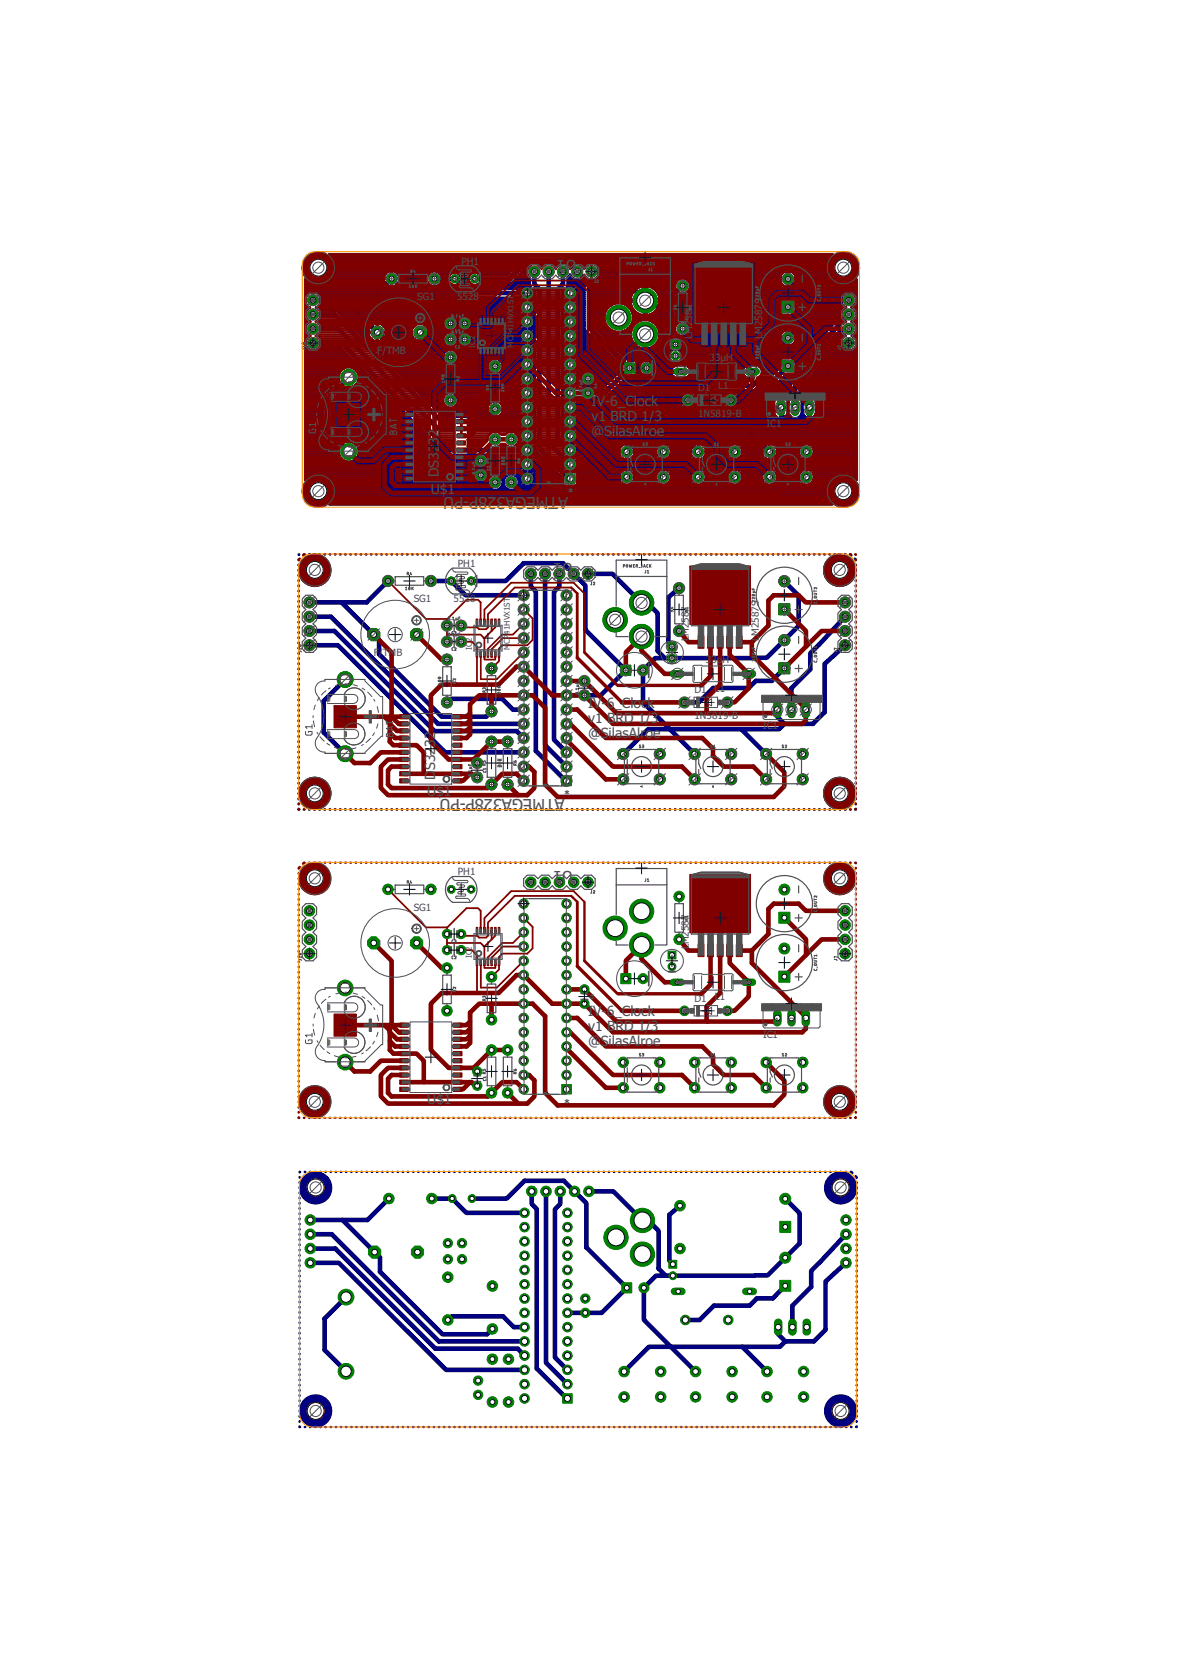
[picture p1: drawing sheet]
<svg xmlns="http://www.w3.org/2000/svg" width="210mm" height="297mm" viewBox="0 0 210 297" stroke-linecap="round" stroke-linejoin="round" font-family="sans-serif">
<defs><g id="words">
<g font-size="2.9" fill="#505050">
<text x="102.5" y="46.3" transform="rotate(-180 102.5 46.3)">U1</text>
<text x="101" y="88.3" transform="rotate(-180 101 88.3)">ATMEGA328P-PU</text>
<text x="101.8" y="100" transform="rotate(-180 101.8 100)">U1</text>
<text x="100.3" y="142" transform="rotate(-180 100.3 142)">ATMEGA328P-PU</text>
<text x="101.8" y="154.8" transform="rotate(-180 101.8 154.8)">U1</text>
</g>
<g font-size="2.5" fill="#505050">
<text x="105.1" y="72.1">IV-6_Clock</text>
<text x="105.1" y="74.8">v1 BRD 1/3</text>
<text x="105.1" y="77.5">@SilasAlroe</text>
<text x="76.6" y="87.8">U$1</text>
<text x="78" y="84.8" transform="rotate(-90 78 84.8)">DS3232</text>
<text x="104.5" y="125.9">IV-6_Clock</text>
<text x="104.5" y="128.5">v1 BRD 1/3</text>
<text x="104.5" y="131.2">@SilasAlroe</text>
<text x="75.9" y="141.5">U$1</text>
<text x="77.3" y="138.6" transform="rotate(-90 77.3 138.6)">DS3232</text>
<text x="104.5" y="180.7">IV-6_Clock</text>
<text x="104.5" y="183.4">v1 BRD 1/3</text>
<text x="104.5" y="186">@SilasAlroe</text>
<text x="75.9" y="196.3">U$1</text>
</g>
<g font-size="1.8" fill="#505050">
<text x="82" y="47">PH1</text>
<text x="74.2" y="53.4">SG1</text>
<text x="81.3" y="53.4">5528</text>
<text x="67.1" y="62.9">F/TMB</text>
<text x="123" y="60.2" transform="rotate(-90 123 60.2)">LM2587</text>
<text x="126.1" y="64.1">33µH</text>
<text x="135.5" y="60.2" transform="rotate(-90 135.5 60.2)">LM2587S</text>
<text x="124.1" y="69.5">D1</text>
<text x="127.7" y="69.2">L1</text>
<text x="124.1" y="74.1">1N5819-B</text>
<text x="136.2" y="75.9">IC1</text>
<text x="138.2" y="73.7">A</text>
<text x="140.7" y="73.7">O</text>
<text x="143.2" y="73.7">I</text>
<text x="101.9" y="86.2" transform="rotate(-180 101.9 86.2)">*</text>
<text x="81.4" y="100.8">PH1</text>
<text x="73.5" y="107.1">SG1</text>
<text x="80.6" y="107.1">5528</text>
<text x="122.4" y="113.9" transform="rotate(-90 122.4 113.9)">LM2587</text>
<text x="134.8" y="113.9" transform="rotate(-90 134.8 113.9)">LM2587S</text>
<text x="66.4" y="116.6">F/TMB</text>
<text x="125.5" y="117.8">33µH</text>
<text x="123.4" y="123.2">D1</text>
<text x="127" y="123">L1</text>
<text x="123.4" y="127.8">1N5819-B</text>
<text x="135.6" y="129.6">IC1</text>
<text x="137.5" y="127.4">A</text>
<text x="140.1" y="127.4">O</text>
<text x="142.6" y="127.4">I</text>
<text x="101.3" y="139.9" transform="rotate(-180 101.3 139.9)">*</text>
<text x="81.4" y="155.6">PH1</text>
<text x="73.5" y="161.9">SG1</text>
<text x="122.4" y="168.8" transform="rotate(-90 122.4 168.8)">LM2587</text>
<text x="123.4" y="178">D1</text>
<text x="127" y="177.8">L1</text>
<text x="135.6" y="184.5">IC1</text>
<text x="137.5" y="182.2">A</text>
<text x="140.1" y="182.2">O</text>
<text x="142.6" y="182.2">I</text>
<text x="101.3" y="194.8" transform="rotate(-180 101.3 194.8)">*</text>
</g>
<g font-size="1.4" fill="#505050">
<text x="84.5" y="61.8" transform="rotate(-90 84.5 61.8)">IC2</text>
<text x="91.3" y="61.8" transform="rotate(-90 91.3 61.8)">MCP41HVX1ST</text>
<text x="83.8" y="115.5" transform="rotate(-90 83.8 115.5)">IC2</text>
<text x="90.6" y="115.5" transform="rotate(-90 90.6 115.5)">MCP41HVX1ST</text>
<text x="83.8" y="170.3" transform="rotate(-90 83.8 170.3)">IC2</text>
</g>
</g></defs>
<g fill="#000080" stroke="#000080" stroke-width=".18">
<path d="M53.7 139.2a2.88 2.88 0 0 1 4.6 .2 2.88 2.88 0 0 1-1.5 4.4 2.88 2.88 0 0 1-3.7-2.8h2.5a.35 .35 0 0 1 .4-.3 .35 .35 0 0 1 .2 .5 .35 .35 0 0 1-.6-.1l-2.5-.1v-.6z" fill-rule="evenodd"/>
<path d="M53.7 99.6a2.89 2.89 0 0 1 4.6 .1 2.89 2.89 0 0 1-1.5 4.4 2.89 2.89 0 0 1-3.7-2.7h2.5a.35 .35 0 0 1 .4-.4 .35 .35 0 0 1 .2 .6 .35 .35 0 0 1-.6-.1l-2.5-.1v-.7z" fill-rule="evenodd"/>
<path d="M147 99.6a2.88 2.88 0 0 1 4.6 .2 2.88 2.88 0 0 1-1.5 4.3 2.88 2.88 0 0 1-3.7-2.7h2.5a.35 .35 0 0 1 .5-.3 .35 .35 0 0 1 0 .6 .35 .35 0 0 1-.5-.2l-2.5-.1 .2-1.3z" fill-rule="evenodd"/>
<path d="M147.4 138.8a2.89 2.89 0 0 1 4.4 1 2.89 2.89 0 0 1-1.9 4 2.89 2.89 0 0 1-3.5-2.8h2.5a.35 .35 0 0 1 .5-.2 .35 .35 0 0 1 0 .6 .35 .35 0 0 1-.5-.3l-2.5-.1a2.87 2.87 0 0 1 1-2.2z" fill-rule="evenodd"/>
</g>
<g fill="none" stroke="#000080" stroke-width=".83">
<path d="M55 114.7h5.1l19 19h14M55 112.2h4.4l17.8 17.8h14.6l1.3 1.2M55 109.6h3.8l19.1 19.1h15.2M60.7 107.1l6.7 6.7v2.5l11.1 11.1h7.9l1-.9M69 103.3l-3.8 3.8h-10.2M76.6 103.3h3.6l2.5 2.5h10.4M83.7 103.3h6.2l3.2-3.2h7l4 4v7.9l7.1 7.1-4.4 4.5h-6.1M94.3 102v2.2l.9 .9v28.4l5.5 5.3M96.9 102v30.5l3.8 3.8M99.4 102v2.2l-.9 1v26.3l2.2 2.2M104.5 102h4.4l5.1 5.2h1.1l1.8 1.8v6.7l1.3 1.3M119.2 117h.2"/>
<path d="M119.4 117h-3l-2.1 2.1v5.7l4.8 4.8M120.7 104.5l-1.9 1.7v8.1l.6 .7M139.4 103.3l2.5 2.6v5.4l-2.5 2.5M139.4 113.4v.4M139.4 118.8l-2.2 2.2h-2.9l-1.2 1.3h-6.4l-2.5 2.6h-2.6M139.4 113.8l-3.1 3.1-16.9 .1M150.2 114.7l-3.6 3.3v8.6l-2.1 2.1h-5.1l-1.2-1.3v-1.3M150.2 109.6l-6.2 6.5v2.9l-3.3 3.3v3.8M61.3 120.8l-3.8 3.8v5.6l3.8 3.8M79.4 124.9l.7-.7h9.2l1.9 1.9h1.9M119.1 129.6h-3.9l-4.4 4.4M119.1 129.6l4.4 4.4"/>
<path d="M119.1 129.6h12.7l4.4 4.4M139.4 128.7l-.9 .9h-6.7"/>
</g>
<g fill="none" stroke="#000080" stroke-width=".42">
<path d="M53.1 99.4v.1M53.2 98.5l-.1 .1M54 98.5h.1M54.9 98.5h.1M55.8 98.5h.1M56.8 98.5h.1M57.7 98.5h.1M58.6 98.5h.1M59.5 98.5h.1M60.4 98.5h.1M61.3 98.5h.1M62.3 98.5h.1"/>
<path d="M63.2 98.5h.1M64.1 98.5h.1M65 98.5h.1M65.9 98.5h.1M66.8 98.5h.1M67.7 98.5h.1M68.6 98.5h.2M69.6 98.5h.1M70.5 98.5h.1M71.4 98.5h.1M72.3 98.5h.1M73.2 98.5h.1"/>
<path d="M74.1 98.5h.2M75.1 98.5h.1M76 98.5h.1M76.9 98.5h.1M77.8 98.5h.1M78.7 98.5h.1M79.6 98.5h.1M80.6 98.5h.1M81.5 98.5h.1M82.4 98.5h.1M83.3 98.5h.1M84.2 98.5h.1"/>
<path d="M85.1 98.5h.1M86 98.5h.2M87 98.5h.1M87.9 98.5h.1M88.8 98.5h.1M89.7 98.5h.1M90.6 98.5h.1M91.5 98.5h.2M92.5 98.5h.1M93.4 98.5h.1M94.3 98.5h.1M95.2 98.5h.1"/>
<path d="M96.1 98.5h.1M97 98.5h.1M98 98.5h.1M98.9 98.5h.1M101.6 98.5h.1M102.5 98.5h.1M103.4 98.5h.1M104.4 98.5h.1M105.3 98.5h.1M106.2 98.5h.1M107.1 98.5h.1M108 98.5h.1"/>
<path d="M108.9 98.5h.1M109.9 98.5h.1M110.8 98.5h.1M111.7 98.5h.1M112.6 98.5h.1M113.5 98.5h.1M114.4 98.5h.1M115.3 98.5h.1M116.3 98.5h.1M117.2 98.5h.1M118.1 98.5h.1M119 98.5h.1"/>
<path d="M119.9 98.5h.1M120.8 98.5h.1M121.8 98.5h.1M122.7 98.5h.1M123.6 98.5h.1M124.5 98.5h.1M125.4 98.5h.1M126.3 98.5h.1M127.3 98.5h.1M128.2 98.5h.1M129.1 98.5h.1M130 98.5h.1"/>
<path d="M130.9 98.5h.1M131.8 98.5h.1M132.7 98.5h.1M133.7 98.5h.1M134.6 98.5h.1M135.5 98.5h.1M136.4 98.5h.1M137.3 98.5h.1M138.2 98.5h.1M139.1 98.5h.2M140.1 98.5h.1M141 98.5h.1"/>
<path d="M141.9 98.5h.1M142.8 98.5h.1M143.7 98.5h.1M144.7 98.5h.1M145.6 98.5h.1M146.5 98.5h.1M147.4 98.5h.1M148.3 98.5h.1M149.2 98.5h.1M150.1 98.5h.1M151 98.5l.3 .2M151.9 99.3l.2 .3"/>
<path d="M53.1 100.4v.1M53.1 101.3v.1M53.1 102.2v.1M53.1 103.1v.2M53.1 104.1v.1M53.1 105v.1M53.1 105.9v.1M53.1 106.8v.2M53.1 107.8v.1M53.1 108.7v.1M53.1 109.6v.1M53.1 110.5v.1"/>
<path d="M53.1 111.4v.2M53.1 112.4v.1M53.1 113.3v.1M53.1 114.2v.1M53.1 115.1v.2M53.1 116.1v.1M53.1 117v.1M53.1 117.9v.1M53.1 118.9v.1M53.1 119.8v.1M152.1 100.4v.1M152.1 101.3v.1"/>
<path d="M152.1 102.2v.2M152.1 103.2v.1M152.1 104.1v.1M152.1 105v.1M152.1 105.9v.1M152.1 106.9v.1M152.1 107.8v.1M152.1 108.7v.1M152.1 109.6v.1M152.1 110.6v.1M152.1 111.5v.1M152.1 112.4v.1"/>
<path d="M152.1 113.3v.1M152.1 114.2v.2M152.1 115.2v.1M152.1 116.1v.1M152.1 117v.1M152.1 117.9v.1M152.1 118.9v.1M152.1 119.8v.1M53.1 120.7v.1M53.1 121.6v.1M53.1 122.5v.1M53.1 123.5v.1"/>
<path d="M53.1 124.4v.1M53.1 125.3v.1M53.1 126.2v.1M53.1 127.2v.1M53.1 128.1v.1M53.1 129v.1M53.1 129.9v.1M53.1 130.9v.1M53.1 131.8v.1M53.1 132.7v.1M53.1 133.6v.1M53.1 134.5v.2"/>
<path d="M53.1 135.5v.1M53.1 136.4v.1M53.1 137.3v.1M53.1 138.2v.1M53.1 139.2v.1M152.1 120.7v.1M152.1 121.6v.1M152.1 122.6v.1M152.1 123.5v.1M152.1 124.4v.1M152.1 125.3v.1M152.1 126.2v.1"/>
<path d="M152.1 127.2v.1M152.1 128.1v.1M152.1 129v.1M152.1 129.9v.1M152.1 130.9v.1M152.1 131.8v.1M152.1 132.7v.1M152.1 133.6v.1M152.1 134.6v.1M152.1 135.5v.1M152.1 136.4v.1M152.1 137.3v.1"/>
<path d="M152.1 138.2v.1M152.1 139.2v.1M53.1 140.1v.1M53.1 141v.1M53.1 141.9v.2M53.1 142.9v.1M53.1 143.8l.1 .1M54 143.9h.1M54.9 143.9h.1M55.8 143.9h.1M56.8 143.9h.1M57.7 143.9h.1"/>
<path d="M58.6 143.9h.1M59.5 143.9h.1M60.4 143.9h.1M61.3 143.9h.1M62.3 143.9h.1M63.2 143.9h.1M64.1 143.9h.1M65 143.9h.1M65.9 143.9h.1M66.8 143.9h.1M67.7 143.9h.1M68.7 143.9h.1"/>
<path d="M69.6 143.9h.1M70.5 143.9h.1M71.4 143.9h.1M72.3 143.9h.1M73.2 143.9h.1M74.1 143.9h.2M75.1 143.9h.1M76 143.9h.1M76.9 143.9h.1M77.8 143.9h.1M78.7 143.9h.1M79.7 143.9h.1"/>
<path d="M80.6 143.9h.1M81.5 143.9h.1M82.4 143.9h.1M83.3 143.9h.1M84.2 143.9h.1M85.2 143.9h.1M86.1 143.9h.1M87 143.9h.1M87.9 143.9h.1M88.8 143.9h.1M89.7 143.9h.1M90.6 143.9h.1"/>
<path d="M91.5 143.9h.2M92.5 143.9h.1M93.4 143.9h.1M94.3 143.9h.1M95.2 143.9h.1M96.1 143.9h.1M97.1 143.9h.1M98 143.9h.1M98.9 143.9h.1M99.8 143.9h.1M100.7 143.9h.1M101.6 143.9h.1"/>
<path d="M102.6 143.9h.1M103.5 143.9h.1M104.4 143.9h.1M105.3 143.9h.1M106.2 143.9h.1M107.1 143.9h.1M108 143.9h.1M109 143.9h.1M109.9 143.9h.1M110.8 143.9h.1M111.7 143.9h.1M112.6 143.9h.1"/>
<path d="M113.5 143.9h.1M114.4 143.9h.2M115.4 143.9h.1M116.3 143.9h.1M117.2 143.9h.1M118.1 143.9h.1M119 143.9h.1M120 143.9h.1M120.9 143.9h.1M121.8 143.9h.1M122.7 143.9h.1M123.6 143.9h.1"/>
<path d="M124.5 143.9h.1M125.4 143.9h.1M126.4 143.9h.1M127.3 143.9h.1M128.2 143.9h.1M129.1 143.9h.1M130 143.9h.1M130.9 143.9h.1M131.8 143.9h.2M132.8 143.9h.1M133.7 143.9h.1M134.6 143.9h.1"/>
<path d="M135.5 143.9h.1M136.4 143.9h.1M137.4 143.9h.1M138.3 143.9h.1M139.2 143.9h.1M140.1 143.9h.1M141 143.9h.1M141.9 143.9h.1M142.9 143.9h.1M143.8 143.9h.1M144.7 143.9h.1M145.6 143.9h.1"/>
<path d="M146.5 143.9h.1M147.4 143.9h.1M148.3 143.9h.1M149.3 143.9h.1M150.2 143.9h.1M151.1 143.9h.1M152.1 143.8l-.1 .1M152.1 140.1v.1M152.1 141v.1M152.1 141.9v.2M152.1 142.9v.1"/>
</g>
<circle cx="119.4" cy="117" r=".7" fill="#008000" stroke="#008000" stroke-width=".18"/>
<circle cx="119.4" cy="117" r=".44" fill="#fff" stroke="#000" stroke-width=".18"/>
<path d="M118.7 114.3h1.4v1.4h-1.4z" fill="#008000" stroke="#008000" stroke-width=".18"/>
<circle cx="119.4" cy="115" r=".44" fill="#fff" stroke="#000" stroke-width=".18"/>
<path d="M110.3 118.3h1.8v1.7h-1.8z" fill="#008000" stroke="#008000" stroke-width=".18"/>
<circle cx="111.2" cy="119.1" r=".44" fill="#fff" stroke="#000" stroke-width=".18"/>
<circle cx="114.3" cy="119.1" r=".89" fill="#008000" stroke="#008000" stroke-width=".18"/>
<circle cx="114.3" cy="119.1" r=".44" fill="#fff" stroke="#000" stroke-width=".18"/>
<circle cx="139.4" cy="113.8" r=".97" fill="#008000" stroke="#008000" stroke-width=".18"/>
<circle cx="139.4" cy="113.8" r=".44" fill="#fff" stroke="#000" stroke-width=".18"/>
<path d="M138.4 117.8h2v2h-2z" fill="#008000" stroke="#008000" stroke-width=".18"/>
<circle cx="139.4" cy="118.8" r=".44" fill="#fff" stroke="#000" stroke-width=".18"/>
<circle cx="139.4" cy="103.3" r=".97" fill="#008000" stroke="#008000" stroke-width=".18"/>
<circle cx="139.4" cy="103.3" r=".44" fill="#fff" stroke="#000" stroke-width=".18"/>
<path d="M138.4 107.3h2v2h-2z" fill="#008000" stroke="#008000" stroke-width=".18"/>
<circle cx="139.4" cy="108.3" r=".44" fill="#fff" stroke="#000" stroke-width=".18"/>
<circle cx="121.6" cy="124.9" r=".85" fill="#008000" stroke="#008000" stroke-width=".18"/>
<circle cx="121.6" cy="124.9" r=".55" fill="#fff" stroke="#000" stroke-width=".18"/>
<circle cx="129.3" cy="124.9" r=".85" fill="#008000" stroke="#008000" stroke-width=".18"/>
<circle cx="129.3" cy="124.9" r=".55" fill="#fff" stroke="#000" stroke-width=".18"/>
<path d="M132.4 119.8h1.3" fill="none" stroke="#008000" stroke-width="1.3"/>
<circle cx="133.1" cy="119.8" r=".4" fill="#fff" stroke="#000" stroke-width=".18"/>
<path d="M119.7 119.8h1.3" fill="none" stroke="#008000" stroke-width="1.3"/>
<circle cx="120.4" cy="119.8" r=".4" fill="#fff" stroke="#000" stroke-width=".18"/>
<circle cx="120.7" cy="104.5" r=".93" fill="#008000" stroke="#008000" stroke-width=".18"/>
<circle cx="120.7" cy="104.5" r=".44" fill="#fff" stroke="#000" stroke-width=".18"/>
<circle cx="120.7" cy="112.2" r=".93" fill="#008000" stroke="#008000" stroke-width=".18"/>
<circle cx="120.7" cy="112.2" r=".44" fill="#fff" stroke="#000" stroke-width=".18"/>
<circle cx="114" cy="113.2" r="2.16" fill="#008000" stroke="#008000" stroke-width=".18"/>
<circle cx="114" cy="113.2" r="1.5" fill="#fff" stroke="#000" stroke-width=".18"/>
<circle cx="114" cy="107.2" r="2.16" fill="#008000" stroke="#008000" stroke-width=".18"/>
<circle cx="114" cy="107.2" r="1.5" fill="#fff" stroke="#000" stroke-width=".18"/>
<circle cx="109.3" cy="110.2" r="2.16" fill="#008000" stroke="#008000" stroke-width=".18"/>
<circle cx="109.3" cy="110.2" r="1.5" fill="#fff" stroke="#000" stroke-width=".18"/>
<circle cx="150.2" cy="114.7" r=".93" fill="#008000" stroke="#008000" stroke-width=".18"/>
<circle cx="150.2" cy="114.7" r=".51" fill="#fff" stroke="#000" stroke-width=".18"/>
<circle cx="150.2" cy="112.2" r=".93" fill="#008000" stroke="#008000" stroke-width=".18"/>
<circle cx="150.2" cy="112.2" r=".51" fill="#fff" stroke="#000" stroke-width=".18"/>
<circle cx="150.2" cy="109.6" r=".93" fill="#008000" stroke="#008000" stroke-width=".18"/>
<circle cx="150.2" cy="109.6" r=".51" fill="#fff" stroke="#000" stroke-width=".18"/>
<circle cx="150.2" cy="107.1" r=".93" fill="#008000" stroke="#008000" stroke-width=".18"/>
<circle cx="150.2" cy="107.1" r=".51" fill="#fff" stroke="#000" stroke-width=".18"/>
<circle cx="55" cy="114.7" r=".93" fill="#008000" stroke="#008000" stroke-width=".18"/>
<circle cx="55" cy="114.7" r=".51" fill="#fff" stroke="#000" stroke-width=".18"/>
<circle cx="55" cy="112.2" r=".93" fill="#008000" stroke="#008000" stroke-width=".18"/>
<circle cx="55" cy="112.2" r=".51" fill="#fff" stroke="#000" stroke-width=".18"/>
<circle cx="55" cy="109.6" r=".93" fill="#008000" stroke="#008000" stroke-width=".18"/>
<circle cx="55" cy="109.6" r=".51" fill="#fff" stroke="#000" stroke-width=".18"/>
<circle cx="55" cy="107.1" r=".93" fill="#008000" stroke="#008000" stroke-width=".18"/>
<circle cx="55" cy="107.1" r=".51" fill="#fff" stroke="#000" stroke-width=".18"/>
<circle cx="83.7" cy="103.3" r=".7" fill="#008000" stroke="#008000" stroke-width=".18"/>
<circle cx="83.7" cy="103.3" r=".4" fill="#fff" stroke="#000" stroke-width=".18"/>
<circle cx="80.2" cy="103.3" r=".7" fill="#008000" stroke="#008000" stroke-width=".18"/>
<circle cx="80.2" cy="103.3" r=".4" fill="#fff" stroke="#000" stroke-width=".18"/>
<circle cx="69" cy="103.3" r=".93" fill="#008000" stroke="#008000" stroke-width=".18"/>
<circle cx="69" cy="103.3" r=".44" fill="#fff" stroke="#000" stroke-width=".18"/>
<circle cx="76.6" cy="103.3" r=".93" fill="#008000" stroke="#008000" stroke-width=".18"/>
<circle cx="76.6" cy="103.3" r=".44" fill="#fff" stroke="#000" stroke-width=".18"/>
<circle cx="123.5" cy="134" r=".93" fill="#008000" stroke="#008000" stroke-width=".18"/>
<circle cx="123.5" cy="134" r=".51" fill="#fff" stroke="#000" stroke-width=".18"/>
<circle cx="130" cy="134" r=".93" fill="#008000" stroke="#008000" stroke-width=".18"/>
<circle cx="130" cy="134" r=".51" fill="#fff" stroke="#000" stroke-width=".18"/>
<circle cx="123.5" cy="138.5" r=".93" fill="#008000" stroke="#008000" stroke-width=".18"/>
<circle cx="123.5" cy="138.5" r=".51" fill="#fff" stroke="#000" stroke-width=".18"/>
<circle cx="130" cy="138.5" r=".93" fill="#008000" stroke="#008000" stroke-width=".18"/>
<circle cx="130" cy="138.5" r=".51" fill="#fff" stroke="#000" stroke-width=".18"/>
<path d="M138.2 125.4v1.5" fill="none" stroke="#008000" stroke-width="1.5"/>
<circle cx="138.2" cy="126.1" r=".51" fill="#fff" stroke="#000" stroke-width=".18"/>
<path d="M140.7 125.4v1.5" fill="none" stroke="#008000" stroke-width="1.5"/>
<circle cx="140.7" cy="126.1" r=".51" fill="#fff" stroke="#000" stroke-width=".18"/>
<path d="M143.2 125.4v1.5" fill="none" stroke="#008000" stroke-width="1.5"/>
<circle cx="143.2" cy="126.1" r=".51" fill="#fff" stroke="#000" stroke-width=".18"/>
<circle cx="136.2" cy="134" r=".93" fill="#008000" stroke="#008000" stroke-width=".18"/>
<circle cx="136.2" cy="134" r=".51" fill="#fff" stroke="#000" stroke-width=".18"/>
<circle cx="142.7" cy="134" r=".93" fill="#008000" stroke="#008000" stroke-width=".18"/>
<circle cx="142.7" cy="134" r=".51" fill="#fff" stroke="#000" stroke-width=".18"/>
<circle cx="136.2" cy="138.5" r=".93" fill="#008000" stroke="#008000" stroke-width=".18"/>
<circle cx="136.2" cy="138.5" r=".51" fill="#fff" stroke="#000" stroke-width=".18"/>
<circle cx="142.7" cy="138.5" r=".93" fill="#008000" stroke="#008000" stroke-width=".18"/>
<circle cx="142.7" cy="138.5" r=".51" fill="#fff" stroke="#000" stroke-width=".18"/>
<circle cx="110.8" cy="134" r=".93" fill="#008000" stroke="#008000" stroke-width=".18"/>
<circle cx="110.8" cy="134" r=".51" fill="#fff" stroke="#000" stroke-width=".18"/>
<circle cx="117.3" cy="134" r=".93" fill="#008000" stroke="#008000" stroke-width=".18"/>
<circle cx="117.3" cy="134" r=".51" fill="#fff" stroke="#000" stroke-width=".18"/>
<circle cx="110.8" cy="138.5" r=".93" fill="#008000" stroke="#008000" stroke-width=".18"/>
<circle cx="110.8" cy="138.5" r=".51" fill="#fff" stroke="#000" stroke-width=".18"/>
<circle cx="117.3" cy="138.5" r=".93" fill="#008000" stroke="#008000" stroke-width=".18"/>
<circle cx="117.3" cy="138.5" r=".51" fill="#fff" stroke="#000" stroke-width=".18"/>
<circle cx="66.4" cy="112.8" r="1.17" fill="#008000" stroke="#008000" stroke-width=".18"/>
<circle cx="66.4" cy="112.8" r=".51" fill="#fff" stroke="#000" stroke-width=".18"/>
<circle cx="74" cy="112.8" r="1.17" fill="#008000" stroke="#008000" stroke-width=".18"/>
<circle cx="74" cy="112.8" r=".51" fill="#fff" stroke="#000" stroke-width=".18"/>
<circle cx="79.4" cy="117.2" r=".93" fill="#008000" stroke="#008000" stroke-width=".18"/>
<circle cx="79.4" cy="117.2" r=".44" fill="#fff" stroke="#000" stroke-width=".18"/>
<circle cx="79.4" cy="124.9" r=".93" fill="#008000" stroke="#008000" stroke-width=".18"/>
<circle cx="79.4" cy="124.9" r=".44" fill="#fff" stroke="#000" stroke-width=".18"/>
<path d="M99.8 138h1.7v1.7h-1.7z" fill="#008000" stroke="#008000" stroke-width=".18"/>
<circle cx="100.7" cy="138.8" r=".55" fill="#fff" stroke="#000" stroke-width=".18"/>
<circle cx="100.7" cy="136.3" r=".85" fill="#008000" stroke="#008000" stroke-width=".18"/>
<circle cx="100.7" cy="136.3" r=".55" fill="#fff" stroke="#000" stroke-width=".18"/>
<circle cx="100.7" cy="133.7" r=".85" fill="#008000" stroke="#008000" stroke-width=".18"/>
<circle cx="100.7" cy="133.7" r=".55" fill="#fff" stroke="#000" stroke-width=".18"/>
<circle cx="100.7" cy="131.2" r=".85" fill="#008000" stroke="#008000" stroke-width=".18"/>
<circle cx="100.7" cy="131.2" r=".55" fill="#fff" stroke="#000" stroke-width=".18"/>
<circle cx="100.7" cy="128.7" r=".85" fill="#008000" stroke="#008000" stroke-width=".18"/>
<circle cx="100.7" cy="128.7" r=".55" fill="#fff" stroke="#000" stroke-width=".18"/>
<circle cx="100.7" cy="126.1" r=".85" fill="#008000" stroke="#008000" stroke-width=".18"/>
<circle cx="100.7" cy="126.1" r=".55" fill="#fff" stroke="#000" stroke-width=".18"/>
<circle cx="100.7" cy="123.6" r=".85" fill="#008000" stroke="#008000" stroke-width=".18"/>
<circle cx="100.7" cy="123.6" r=".55" fill="#fff" stroke="#000" stroke-width=".18"/>
<circle cx="100.7" cy="121.1" r=".85" fill="#008000" stroke="#008000" stroke-width=".18"/>
<circle cx="100.7" cy="121.1" r=".55" fill="#fff" stroke="#000" stroke-width=".18"/>
<circle cx="100.7" cy="118.5" r=".85" fill="#008000" stroke="#008000" stroke-width=".18"/>
<circle cx="100.7" cy="118.5" r=".55" fill="#fff" stroke="#000" stroke-width=".18"/>
<circle cx="100.7" cy="116" r=".85" fill="#008000" stroke="#008000" stroke-width=".18"/>
<circle cx="100.7" cy="116" r=".55" fill="#fff" stroke="#000" stroke-width=".18"/>
<circle cx="100.7" cy="113.4" r=".85" fill="#008000" stroke="#008000" stroke-width=".18"/>
<circle cx="100.7" cy="113.4" r=".55" fill="#fff" stroke="#000" stroke-width=".18"/>
<circle cx="100.7" cy="110.9" r=".85" fill="#008000" stroke="#008000" stroke-width=".18"/>
<circle cx="100.7" cy="110.9" r=".55" fill="#fff" stroke="#000" stroke-width=".18"/>
<circle cx="100.7" cy="108.4" r=".85" fill="#008000" stroke="#008000" stroke-width=".18"/>
<circle cx="100.7" cy="108.4" r=".55" fill="#fff" stroke="#000" stroke-width=".18"/>
<circle cx="100.7" cy="105.8" r=".85" fill="#008000" stroke="#008000" stroke-width=".18"/>
<circle cx="100.7" cy="105.8" r=".55" fill="#fff" stroke="#000" stroke-width=".18"/>
<circle cx="93.1" cy="105.8" r=".85" fill="#008000" stroke="#008000" stroke-width=".18"/>
<circle cx="93.1" cy="105.8" r=".55" fill="#fff" stroke="#000" stroke-width=".18"/>
<circle cx="93.1" cy="108.4" r=".85" fill="#008000" stroke="#008000" stroke-width=".18"/>
<circle cx="93.1" cy="108.4" r=".55" fill="#fff" stroke="#000" stroke-width=".18"/>
<circle cx="93.1" cy="110.9" r=".85" fill="#008000" stroke="#008000" stroke-width=".18"/>
<circle cx="93.1" cy="110.9" r=".55" fill="#fff" stroke="#000" stroke-width=".18"/>
<circle cx="93.1" cy="113.4" r=".85" fill="#008000" stroke="#008000" stroke-width=".18"/>
<circle cx="93.1" cy="113.4" r=".55" fill="#fff" stroke="#000" stroke-width=".18"/>
<circle cx="93.1" cy="116" r=".85" fill="#008000" stroke="#008000" stroke-width=".18"/>
<circle cx="93.1" cy="116" r=".55" fill="#fff" stroke="#000" stroke-width=".18"/>
<circle cx="93.1" cy="118.5" r=".85" fill="#008000" stroke="#008000" stroke-width=".18"/>
<circle cx="93.1" cy="118.5" r=".55" fill="#fff" stroke="#000" stroke-width=".18"/>
<circle cx="93.1" cy="121.1" r=".85" fill="#008000" stroke="#008000" stroke-width=".18"/>
<circle cx="93.1" cy="121.1" r=".55" fill="#fff" stroke="#000" stroke-width=".18"/>
<circle cx="93.1" cy="123.6" r=".85" fill="#008000" stroke="#008000" stroke-width=".18"/>
<circle cx="93.1" cy="123.6" r=".55" fill="#fff" stroke="#000" stroke-width=".18"/>
<circle cx="93.1" cy="126.1" r=".85" fill="#008000" stroke="#008000" stroke-width=".18"/>
<circle cx="93.1" cy="126.1" r=".55" fill="#fff" stroke="#000" stroke-width=".18"/>
<circle cx="93.1" cy="128.7" r=".85" fill="#008000" stroke="#008000" stroke-width=".18"/>
<circle cx="93.1" cy="128.7" r=".55" fill="#fff" stroke="#000" stroke-width=".18"/>
<circle cx="93.1" cy="131.2" r=".85" fill="#008000" stroke="#008000" stroke-width=".18"/>
<circle cx="93.1" cy="131.2" r=".55" fill="#fff" stroke="#000" stroke-width=".18"/>
<circle cx="93.1" cy="133.7" r=".85" fill="#008000" stroke="#008000" stroke-width=".18"/>
<circle cx="93.1" cy="133.7" r=".55" fill="#fff" stroke="#000" stroke-width=".18"/>
<circle cx="93.1" cy="136.3" r=".85" fill="#008000" stroke="#008000" stroke-width=".18"/>
<circle cx="93.1" cy="136.3" r=".55" fill="#fff" stroke="#000" stroke-width=".18"/>
<circle cx="93.1" cy="138.8" r=".85" fill="#008000" stroke="#008000" stroke-width=".18"/>
<circle cx="93.1" cy="138.8" r=".55" fill="#fff" stroke="#000" stroke-width=".18"/>
<circle cx="61.3" cy="134" r="1.4" fill="#008000" stroke="#008000" stroke-width=".18"/>
<circle cx="61.3" cy="134" r=".93" fill="#fff" stroke="#000" stroke-width=".18"/>
<circle cx="61.3" cy="120.8" r="1.4" fill="#008000" stroke="#008000" stroke-width=".18"/>
<circle cx="61.3" cy="120.8" r=".93" fill="#fff" stroke="#000" stroke-width=".18"/>
<circle cx="104.5" cy="102" r=".93" fill="#008000" stroke="#008000" stroke-width=".18"/>
<circle cx="104.5" cy="102" r=".51" fill="#fff" stroke="#000" stroke-width=".18"/>
<circle cx="102" cy="102" r=".93" fill="#008000" stroke="#008000" stroke-width=".18"/>
<circle cx="102" cy="102" r=".51" fill="#fff" stroke="#000" stroke-width=".18"/>
<circle cx="99.4" cy="102" r=".93" fill="#008000" stroke="#008000" stroke-width=".18"/>
<circle cx="99.4" cy="102" r=".51" fill="#fff" stroke="#000" stroke-width=".18"/>
<circle cx="96.9" cy="102" r=".93" fill="#008000" stroke="#008000" stroke-width=".18"/>
<circle cx="96.9" cy="102" r=".51" fill="#fff" stroke="#000" stroke-width=".18"/>
<circle cx="94.3" cy="102" r=".93" fill="#008000" stroke="#008000" stroke-width=".18"/>
<circle cx="94.3" cy="102" r=".51" fill="#fff" stroke="#000" stroke-width=".18"/>
<circle cx="87.4" cy="126.5" r=".93" fill="#008000" stroke="#008000" stroke-width=".18"/>
<circle cx="87.4" cy="126.5" r=".44" fill="#fff" stroke="#000" stroke-width=".18"/>
<circle cx="87.4" cy="118.8" r=".93" fill="#008000" stroke="#008000" stroke-width=".18"/>
<circle cx="87.4" cy="118.8" r=".44" fill="#fff" stroke="#000" stroke-width=".18"/>
<circle cx="87.4" cy="139.4" r=".93" fill="#008000" stroke="#008000" stroke-width=".18"/>
<circle cx="87.4" cy="139.4" r=".44" fill="#fff" stroke="#000" stroke-width=".18"/>
<circle cx="87.4" cy="131.8" r=".93" fill="#008000" stroke="#008000" stroke-width=".18"/>
<circle cx="87.4" cy="131.8" r=".44" fill="#fff" stroke="#000" stroke-width=".18"/>
<circle cx="90.2" cy="131.8" r=".93" fill="#008000" stroke="#008000" stroke-width=".18"/>
<circle cx="90.2" cy="131.8" r=".44" fill="#fff" stroke="#000" stroke-width=".18"/>
<circle cx="90.2" cy="139.4" r=".93" fill="#008000" stroke="#008000" stroke-width=".18"/>
<circle cx="90.2" cy="139.4" r=".44" fill="#fff" stroke="#000" stroke-width=".18"/>
<circle cx="84.8" cy="135.6" r=".83" fill="#008000" stroke="#008000" stroke-width=".18"/>
<circle cx="84.8" cy="135.6" r=".44" fill="#fff" stroke="#000" stroke-width=".18"/>
<circle cx="84.8" cy="138.2" r=".83" fill="#008000" stroke="#008000" stroke-width=".18"/>
<circle cx="84.8" cy="138.2" r=".44" fill="#fff" stroke="#000" stroke-width=".18"/>
<circle cx="82" cy="114.1" r=".83" fill="#008000" stroke="#008000" stroke-width=".18"/>
<circle cx="82" cy="114.1" r=".44" fill="#fff" stroke="#000" stroke-width=".18"/>
<circle cx="79.4" cy="114.1" r=".83" fill="#008000" stroke="#008000" stroke-width=".18"/>
<circle cx="79.4" cy="114.1" r=".44" fill="#fff" stroke="#000" stroke-width=".18"/>
<circle cx="82" cy="111.2" r=".83" fill="#008000" stroke="#008000" stroke-width=".18"/>
<circle cx="82" cy="111.2" r=".44" fill="#fff" stroke="#000" stroke-width=".18"/>
<circle cx="79.4" cy="111.2" r=".83" fill="#008000" stroke="#008000" stroke-width=".18"/>
<circle cx="79.4" cy="111.2" r=".44" fill="#fff" stroke="#000" stroke-width=".18"/>
<circle cx="103.9" cy="121.1" r=".83" fill="#008000" stroke="#008000" stroke-width=".18"/>
<circle cx="103.9" cy="121.1" r=".44" fill="#fff" stroke="#000" stroke-width=".18"/>
<circle cx="103.9" cy="123.6" r=".83" fill="#008000" stroke="#008000" stroke-width=".18"/>
<circle cx="103.9" cy="123.6" r=".44" fill="#fff" stroke="#000" stroke-width=".18"/>
<g fill="#800000" stroke="#800000" stroke-width=".18">
<path d="M122.6 100.6h10.8v10.4h-10.8z"/>
<path d="M124.1 113.1h1v2.1h-1z"/>
<path d="M125.8 113.1h1v2.1h-1z"/>
<path d="M127.5 113.1h1v2.1h-1z"/>
<path d="M129.2 113.1h1v2.1h-1z"/>
<path d="M130.9 113.1h1v2.1h-1z"/>
<path d="M80.6 138.4h1.5v.8h-1.5z"/>
<path d="M80.6 137.2h1.5v.7h-1.5z"/>
<path d="M80.6 135.9h1.5v.8h-1.5z"/>
<path d="M80.6 134.6h1.5v.8h-1.5z"/>
<path d="M80.6 133.4h1.5v.7h-1.5z"/>
<path d="M80.6 132.1h1.5v.7h-1.5z"/>
<path d="M80.6 130.8h1.5v.8h-1.5z"/>
<path d="M80.6 129.5h1.5v.8h-1.5z"/>
<path d="M80.6 128.3h1.5v.8h-1.5z"/>
<path d="M80.6 127h1.5v.8h-1.5z"/>
<path d="M71 128.3h1.6v.8h-1.6z"/>
<path d="M71.1 127h1.5v.8h-1.5z"/>
<path d="M71 129.5h1.6v.8h-1.6z"/>
<path d="M71 130.8h1.6v.8h-1.6z"/>
<path d="M71 132.1h1.6v.7h-1.6z"/>
<path d="M71 133.4h1.6v.7h-1.6z"/>
<path d="M71 134.6h1.6v.8h-1.6z"/>
<path d="M71 135.9h1.6v.8h-1.6z"/>
<path d="M71 137.2h1.6v.7h-1.6z"/>
<path d="M71 138.4h1.6v.8h-1.6z"/>
<path d="M59.4 125.4h3.9v4h-3.9z"/>
<path d="M84.6 115.9h.3v.9h-.3z"/>
<path d="M85.3 115.9h.3v.9h-.3z"/>
<path d="M85.9 115.9h.3v.9h-.3z"/>
<path d="M86.6 115.9h.3v.9h-.3z"/>
<path d="M87.2 115.9h.3v.9h-.3z"/>
<path d="M87.9 115.9h.3v.9h-.3z"/>
<path d="M88.5 115.9h.3v.9h-.3z"/>
<path d="M88.5 110h.3v1h-.3z"/>
<path d="M87.9 110h.3v1h-.3z"/>
<path d="M87.2 110h.3v1h-.3z"/>
<path d="M86.6 110h.3v1h-.3z"/>
<path d="M85.9 110h.3v1h-.3z"/>
<path d="M85.3 110h.3v1h-.3z"/>
<path d="M84.6 110h.3v1h-.3z"/>
</g>
<g fill="none" stroke="#800000" stroke-width=".42">
<path d="M53.3 99.3l-.2 .3M54.1 98.5l-.2 .2M55 98.5h.1M55.9 98.5h.1M56.8 98.5h.1M57.7 98.5h.1M58.6 98.5h.1M59.5 98.5h.1M60.5 98.5h.1M61.4 98.5h.1M62.3 98.5h.1M63.2 98.5h.1"/>
<path d="M64.1 98.5h.1M65 98.5h.1M65.9 98.5h.1M66.9 98.5h.1M67.8 98.5h.1M68.7 98.5h.1M69.6 98.5h.1M70.5 98.5h.1M71.4 98.5h.1M72.4 98.5h.1M73.3 98.5h.1M74.2 98.5h.1"/>
<path d="M75.1 98.5h.1M76 98.5h.1M76.9 98.5h.1M77.9 98.5h.1M78.8 98.5h.1M79.7 98.5h.1M80.6 98.5h.1M81.5 98.5h.1M82.4 98.5h.1M83.3 98.5h.1M84.2 98.5h.2M85.2 98.5h.1"/>
<path d="M86.1 98.5h.1M87 98.5h.1M87.9 98.5h.1M88.8 98.5h.1M89.7 98.5h.2M90.7 98.5h.1M91.6 98.5h.1M92.5 98.5h.1M93.4 98.5h.1M94.3 98.5h.1M95.3 98.5h.1M96.2 98.5h.1"/>
<path d="M97.1 98.5h.1M98 98.5h.1M101.6 98.5h.1M102.6 98.5h.1M103.5 98.5h.1M104.4 98.5h.1M105.3 98.5h.1M106.2 98.5h.1M107.1 98.5h.2M108.1 98.5h.1M109 98.5h.1M109.9 98.5h.1"/>
<path d="M110.8 98.5h.1M111.7 98.5h.1M112.6 98.5h.1M113.6 98.5h.1M114.5 98.5h.1M115.4 98.5h.1M116.3 98.5h.1M117.2 98.5h.1M118.1 98.5h.1M119 98.5h.1M120 98.5h.1M120.9 98.5h.1"/>
<path d="M121.8 98.5h.1M122.7 98.5h.1M123.6 98.5h.1M124.5 98.5h.2M125.5 98.5h.1M126.4 98.5h.1M127.3 98.5h.1M128.2 98.5h.1M129.1 98.5h.1M130 98.5h.1M131 98.5h.1M131.9 98.5h.1"/>
<path d="M132.8 98.5h.1M133.7 98.5h.1M134.6 98.5h.1M135.5 98.5h.1M136.4 98.5h.1M137.4 98.5h.1M138.3 98.5h.1M139.2 98.5h.1M140.1 98.5h.1M141 98.5h.1M141.9 98.5h.1M142.9 98.5h.1"/>
<path d="M143.8 98.5h.1M144.7 98.5h.1M145.6 98.5h.1M146.5 98.5h.1M147.4 98.5h.1M148.3 98.5h.1M149.3 98.5h.1M150.2 98.5h.1M151.1 98.5h.1M152 98.5l.1 .1M152.1 99.4v.1M53.1 100.4v.1"/>
<path d="M53.1 101.3v.1M53.1 102.2v.2M53.1 103.2v.1M53.1 104.1v.1M53.1 105v.1M53.1 105.9v.1M53.1 106.9v.1M53.1 107.8v.1M53.1 108.7v.1M53.1 109.6v.1M53.1 110.6v.1M53.1 111.5v.1"/>
<path d="M53.1 112.4v.1M53.1 113.3v.1M53.1 114.2v.2M53.1 115.2v.1M53.1 116.1v.1M53.1 117v.1M53.1 117.9v.1M53.1 118.9v.1M53.1 119.8v.1M101.5 104.4l1.1 1.1M103.9 105.5v10.5M152.1 100.4v.1"/>
<path d="M152.1 101.3v.1M152.1 102.2v.1M152.1 103.1v.2M152.1 104.1v.1M152.1 105v.1M152.1 105.9v.1M152.1 106.8v.2M152.1 107.8v.1M152.1 108.7v.1M152.1 109.6v.1M152.1 110.5v.1M152.1 111.4v.2"/>
<path d="M152.1 112.4v.1M152.1 113.3v.1M152.1 114.2v.1M152.1 115.1v.2M152.1 116.1v.1M152.1 117v.1M152.1 117.9v.1M152.1 118.9v.1M152.1 119.8v.1M53.1 120.7v.1M53.1 121.6v.1M53.1 122.6v.1"/>
<path d="M53.1 123.5v.1M53.1 124.4v.1M53.1 125.3v.1M53.1 126.2v.1M53.1 127.2v.1M53.1 128.1v.1M53.1 129v.1M53.1 129.9v.1M53.1 130.9v.1M53.1 131.8v.1M53.1 132.7v.1M53.1 133.6v.1"/>
<path d="M53.1 134.6v.1M53.1 135.5v.1M53.1 136.4v.1M53.1 137.3v.1M53.1 138.2v.1M53.1 139.2v.1M152.1 120.7v.1M152.1 121.6v.1M152.1 122.5v.1M152.1 123.5v.1M152.1 124.4v.1M152.1 125.3v.1"/>
<path d="M152.1 126.2v.1M152.1 127.2v.1M152.1 128.1v.1M152.1 129v.1M152.1 129.9v.1M152.1 130.9v.1M152.1 131.8v.1M152.1 132.7v.1M152.1 133.6v.1M152.1 134.5v.2M152.1 135.5v.1M152.1 136.4v.1"/>
<path d="M152.1 137.3v.1M152.1 138.2v.1M152.1 139.2v.1M53.1 140.1v.1M53.1 141v.1M53.1 141.9v.2M53.1 142.9v.1M53.1 143.8l.1 .1M54 143.9h.1M54.9 143.9h.1M55.8 143.9h.1M56.8 143.9h.1"/>
<path d="M57.7 143.9h.1M58.6 143.9h.1M59.5 143.9h.1M60.4 143.9h.1M61.3 143.9h.1M62.3 143.9h.1M63.2 143.9h.1M64.1 143.9h.1M65 143.9h.1M65.9 143.9h.1M66.8 143.9h.1M67.7 143.9h.1"/>
<path d="M68.7 143.9h.1M69.6 143.9h.1M70.5 143.9h.1M71.4 143.9h.1M72.3 143.9h.1M73.2 143.9h.1M74.1 143.9h.2M75.1 143.9h.1M76 143.9h.1M76.9 143.9h.1M77.8 143.9h.1M78.7 143.9h.1"/>
<path d="M79.7 143.9h.1M80.6 143.9h.1M81.5 143.9h.1M82.4 143.9h.1M83.3 143.9h.1M84.2 143.9h.1M85.2 143.9h.1M86.1 143.9h.1M87 143.9h.1M87.9 143.9h.1M88.8 143.9h.1M89.7 143.9h.1"/>
<path d="M90.6 143.9h.1M91.5 143.9h.2M92.5 143.9h.1M93.4 143.9h.1M94.3 143.9h.1M95.2 143.9h.1M96.1 143.9h.1M97.1 143.9h.1M98 143.9h.1M98.9 143.9h.1M99.8 143.9h.1M100.7 143.9h.1"/>
<path d="M101.6 143.9h.1M102.6 143.9h.1M103.5 143.9h.1M104.4 143.9h.1M105.3 143.9h.1M106.2 143.9h.1M107.1 143.9h.1M108 143.9h.1M109 143.9h.1M109.9 143.9h.1M110.8 143.9h.1M111.7 143.9h.1"/>
<path d="M112.6 143.9h.1M113.5 143.9h.1M114.4 143.9h.2M115.4 143.9h.1M116.3 143.9h.1M117.2 143.9h.1M118.1 143.9h.1M119 143.9h.1M120 143.9h.1M120.9 143.9h.1M121.8 143.9h.1M122.7 143.9h.1"/>
<path d="M123.6 143.9h.1M124.5 143.9h.1M125.4 143.9h.1M126.4 143.9h.1M127.3 143.9h.1M128.2 143.9h.1M129.1 143.9h.1M130 143.9h.1M130.9 143.9h.1M131.8 143.9h.2M132.8 143.9h.1M133.7 143.9h.1"/>
<path d="M134.6 143.9h.1M135.5 143.9h.1M136.4 143.9h.1M137.4 143.9h.1M138.3 143.9h.1M139.2 143.9h.1M140.1 143.9h.1M141 143.9h.1M141.9 143.9h.1M142.9 143.9h.1M143.8 143.9h.1M144.7 143.9h.1"/>
<path d="M145.6 143.9h.1M146.5 143.9h.1M147.4 143.9h.1M148.3 143.9h.1M149.3 143.9h.1M150.2 143.9h.1M151.1 143.9h.1M152.1 143.8l-.1 .1M152.1 140.1v.1M152.1 141v.1M152.1 141.9v.2M152.1 142.9v.1"/>
</g>
<g fill="none" stroke="#800000" stroke-width=".83">
<path d="M66.4 112.8l3.2 3.2v11.4h2.2M74 112.8l4.5 4.4h.9M114 113.2v2.5l4.2 4.1h2.2M114.6 113.2h-.6l-2.8 2.8v3.1M120.7 112.2l1.6 2h2.3M126.3 114.2v6l-1.6 1.6M128 114.2v7.5l-2.4 2.4v2.5l.2 .2M129.7 114.2v2.2l3.4 3.4v2.5l-2.6 2.6h-1.2M131.4 114.2h2.2M133.6 114.2v2.2l9.6 9.6v2l-.6 .7h-33.7l-5-5.1h-5.7l-5.1-5.1h-1.3l-3.2 3.2h-10.1l-1.9 1.9v8.2l3.2 3.2h4.4M139.4 108.3l3.9 3.9v2.7M150.2 112.2h-4.2l-6.6 6.6v-.6"/>
<path d="M150.2 107.1h-7l-1.3-1.3h-4.4l-.9 1v4.4l-3 3M61.3 127.4h8M68.3 127.4l1 1v.3M69.3 127.4h.3l1.3 1.3h.9M69.3 128.7l1.3 1.2h1.2M69.3 130.2l.9 1h1.6M69.3 128.7v3.1l.6 .7h4.1l1.3 1.2v3.8M69.3 127.4v1M71.8 137.5h12l.6 .7h.4M71.8 133.7h-4.1l-1.9 1.9h-2.8l-1.7-1.6M71.8 135h-2.8l-1.3 1.3v3.8l1.3 1.3h24.7l1.3-1.3v-2.9l-1-.9h-.9M71.8 136.3h-2.2l-.6 .6v2.5l.6 .7h17.1l2.6-2.6h2.5l1.3 1.3"/>
<path d="M81.3 131.2h1.6l.6-.6v-5.4l1.7-1.6h9.5l2.2 2.2v13.6l2.2 2.3h38.4l1.9-1.9v-2.5l-3.2-3.3M83.5 128l-.6 .7h-1.6M83.5 129.3l-.6 .6h-1.6M83.5 126.8l-.6 .6h-1.6M83.5 137.5l-1.2 1.3h-1M84.2 135l.6 .6M87.4 123.6v2.9M90.2 131.8h-2.8l-3.2 3.2M90.2 139.4l1.9 2M100.7 126.1h1.9l5.1 5.1h17.1l1.9 1.9v1.3l1.9 1.9h5.3l2.3 2.2M100.7 128.7h.6l7.6 7.6h12.3l2.3 2.2M100.7 121.1h3.2l5.7 5.7h27.9l.7-.7"/>
<path d="M100.7 131.2h-.4l7.4 7.3h3.1M110.5 124.9h11.1"/>
</g>
<g fill="none" stroke="#800000" stroke-width=".32">
<path d="M69 103.3l6.7 6.7h3.8M79.4 112.8h6l.7 .7M82 114.1h1.9l.9 .9v6.7M82 111.2l.3 .3h2.5M85.4 110.5v-3.4l-.4-.5h-2.1l-3.5 3.5v4M87.4 112.2l-1.3 1.3v3.7h1.9v-.8M87.4 110.5v1.7M88 110.5v1l-.6 .7M93.1 110.9l-1.9 1.9h-1.9l-2.6 2.5v1.1M93.1 108.4l1.6 1.5v3.9l-1 .9h-4.4l-.6 .6v2.2l-1.3 1.3M93.1 113.4h-3.8l-1.9 2v1M93.1 116l-4.8 4.7h-2.8l-.1-4.3"/>
<path d="M101.5 104.4h-10l-4.8 4.8v2.3l-.3 .3h-1.3l-.3-.3v-1M103.9 105.5l-1.9-1.9h-11.2l-4.7 4.8v2.1M81 121.6v.1"/>
</g>
<path d="M102.6 105.5v11.4M103.9 116l5.9 5.8h.1" fill="none" stroke="#800000" stroke-width=".51"/>
<path d="M102.6 116.9l7.9 8M109.9 121.8h14.8" fill="none" stroke="#800000" stroke-width=".61"/>
<circle cx="119.4" cy="117" r=".7" fill="#008000" stroke="#008000" stroke-width=".18"/>
<circle cx="119.4" cy="117" r=".44" fill="#fff" stroke="#000" stroke-width=".18"/>
<path d="M118.7 114.3h1.4v1.4h-1.4z" fill="#008000" stroke="#008000" stroke-width=".18"/>
<circle cx="119.4" cy="115" r=".44" fill="#fff" stroke="#000" stroke-width=".18"/>
<path d="M110.3 118.3h1.8v1.7h-1.8z" fill="#008000" stroke="#008000" stroke-width=".18"/>
<circle cx="111.2" cy="119.1" r=".44" fill="#fff" stroke="#000" stroke-width=".18"/>
<circle cx="114.3" cy="119.1" r=".89" fill="#008000" stroke="#008000" stroke-width=".18"/>
<circle cx="114.3" cy="119.1" r=".44" fill="#fff" stroke="#000" stroke-width=".18"/>
<circle cx="139.4" cy="113.8" r=".97" fill="#008000" stroke="#008000" stroke-width=".18"/>
<circle cx="139.4" cy="113.8" r=".44" fill="#fff" stroke="#000" stroke-width=".18"/>
<path d="M138.4 117.8h2v2h-2z" fill="#008000" stroke="#008000" stroke-width=".18"/>
<circle cx="139.4" cy="118.8" r=".44" fill="#fff" stroke="#000" stroke-width=".18"/>
<circle cx="139.4" cy="103.3" r=".97" fill="#008000" stroke="#008000" stroke-width=".18"/>
<circle cx="139.4" cy="103.3" r=".44" fill="#fff" stroke="#000" stroke-width=".18"/>
<path d="M138.4 107.3h2v2h-2z" fill="#008000" stroke="#008000" stroke-width=".18"/>
<circle cx="139.4" cy="108.3" r=".44" fill="#fff" stroke="#000" stroke-width=".18"/>
<circle cx="121.6" cy="124.9" r=".85" fill="#008000" stroke="#008000" stroke-width=".18"/>
<circle cx="121.6" cy="124.9" r=".55" fill="#fff" stroke="#000" stroke-width=".18"/>
<circle cx="129.3" cy="124.9" r=".85" fill="#008000" stroke="#008000" stroke-width=".18"/>
<circle cx="129.3" cy="124.9" r=".55" fill="#fff" stroke="#000" stroke-width=".18"/>
<path d="M132.4 119.8h1.3" fill="none" stroke="#008000" stroke-width="1.3"/>
<circle cx="133.1" cy="119.8" r=".4" fill="#fff" stroke="#000" stroke-width=".18"/>
<path d="M119.7 119.8h1.3" fill="none" stroke="#008000" stroke-width="1.3"/>
<circle cx="120.4" cy="119.8" r=".4" fill="#fff" stroke="#000" stroke-width=".18"/>
<circle cx="120.7" cy="104.5" r=".93" fill="#008000" stroke="#008000" stroke-width=".18"/>
<circle cx="120.7" cy="104.5" r=".44" fill="#fff" stroke="#000" stroke-width=".18"/>
<circle cx="120.7" cy="112.2" r=".93" fill="#008000" stroke="#008000" stroke-width=".18"/>
<circle cx="120.7" cy="112.2" r=".44" fill="#fff" stroke="#000" stroke-width=".18"/>
<circle cx="114" cy="113.2" r="2.16" fill="#008000" stroke="#008000" stroke-width=".18"/>
<circle cx="114" cy="113.2" r="1.5" fill="#fff" stroke="#000" stroke-width=".18"/>
<circle cx="114" cy="107.2" r="2.16" fill="#008000" stroke="#008000" stroke-width=".18"/>
<circle cx="114" cy="107.2" r="1.5" fill="#fff" stroke="#000" stroke-width=".18"/>
<circle cx="109.3" cy="110.2" r="2.16" fill="#008000" stroke="#008000" stroke-width=".18"/>
<circle cx="109.3" cy="110.2" r="1.5" fill="#fff" stroke="#000" stroke-width=".18"/>
<circle cx="150.2" cy="114.7" r=".93" fill="#008000" stroke="#008000" stroke-width=".18"/>
<circle cx="150.2" cy="114.7" r=".51" fill="#fff" stroke="#000" stroke-width=".18"/>
<circle cx="150.2" cy="112.2" r=".93" fill="#008000" stroke="#008000" stroke-width=".18"/>
<circle cx="150.2" cy="112.2" r=".51" fill="#fff" stroke="#000" stroke-width=".18"/>
<circle cx="150.2" cy="109.6" r=".93" fill="#008000" stroke="#008000" stroke-width=".18"/>
<circle cx="150.2" cy="109.6" r=".51" fill="#fff" stroke="#000" stroke-width=".18"/>
<circle cx="150.2" cy="107.1" r=".93" fill="#008000" stroke="#008000" stroke-width=".18"/>
<circle cx="150.2" cy="107.1" r=".51" fill="#fff" stroke="#000" stroke-width=".18"/>
<circle cx="55" cy="114.7" r=".93" fill="#008000" stroke="#008000" stroke-width=".18"/>
<circle cx="55" cy="114.7" r=".51" fill="#fff" stroke="#000" stroke-width=".18"/>
<circle cx="55" cy="112.2" r=".93" fill="#008000" stroke="#008000" stroke-width=".18"/>
<circle cx="55" cy="112.2" r=".51" fill="#fff" stroke="#000" stroke-width=".18"/>
<circle cx="55" cy="109.6" r=".93" fill="#008000" stroke="#008000" stroke-width=".18"/>
<circle cx="55" cy="109.6" r=".51" fill="#fff" stroke="#000" stroke-width=".18"/>
<circle cx="55" cy="107.1" r=".93" fill="#008000" stroke="#008000" stroke-width=".18"/>
<circle cx="55" cy="107.1" r=".51" fill="#fff" stroke="#000" stroke-width=".18"/>
<circle cx="83.7" cy="103.3" r=".7" fill="#008000" stroke="#008000" stroke-width=".18"/>
<circle cx="83.7" cy="103.3" r=".4" fill="#fff" stroke="#000" stroke-width=".18"/>
<circle cx="80.2" cy="103.3" r=".7" fill="#008000" stroke="#008000" stroke-width=".18"/>
<circle cx="80.2" cy="103.3" r=".4" fill="#fff" stroke="#000" stroke-width=".18"/>
<circle cx="69" cy="103.3" r=".93" fill="#008000" stroke="#008000" stroke-width=".18"/>
<circle cx="69" cy="103.3" r=".44" fill="#fff" stroke="#000" stroke-width=".18"/>
<circle cx="76.6" cy="103.3" r=".93" fill="#008000" stroke="#008000" stroke-width=".18"/>
<circle cx="76.6" cy="103.3" r=".44" fill="#fff" stroke="#000" stroke-width=".18"/>
<circle cx="123.5" cy="134" r=".93" fill="#008000" stroke="#008000" stroke-width=".18"/>
<circle cx="123.5" cy="134" r=".51" fill="#fff" stroke="#000" stroke-width=".18"/>
<circle cx="130" cy="134" r=".93" fill="#008000" stroke="#008000" stroke-width=".18"/>
<circle cx="130" cy="134" r=".51" fill="#fff" stroke="#000" stroke-width=".18"/>
<circle cx="123.5" cy="138.5" r=".93" fill="#008000" stroke="#008000" stroke-width=".18"/>
<circle cx="123.5" cy="138.5" r=".51" fill="#fff" stroke="#000" stroke-width=".18"/>
<circle cx="130" cy="138.5" r=".93" fill="#008000" stroke="#008000" stroke-width=".18"/>
<circle cx="130" cy="138.5" r=".51" fill="#fff" stroke="#000" stroke-width=".18"/>
<path d="M138.2 125.4v1.5" fill="none" stroke="#008000" stroke-width="1.5"/>
<circle cx="138.2" cy="126.1" r=".51" fill="#fff" stroke="#000" stroke-width=".18"/>
<path d="M140.7 125.4v1.5" fill="none" stroke="#008000" stroke-width="1.5"/>
<circle cx="140.7" cy="126.1" r=".51" fill="#fff" stroke="#000" stroke-width=".18"/>
<path d="M143.2 125.4v1.5" fill="none" stroke="#008000" stroke-width="1.5"/>
<circle cx="143.2" cy="126.1" r=".51" fill="#fff" stroke="#000" stroke-width=".18"/>
<circle cx="136.2" cy="134" r=".93" fill="#008000" stroke="#008000" stroke-width=".18"/>
<circle cx="136.2" cy="134" r=".51" fill="#fff" stroke="#000" stroke-width=".18"/>
<circle cx="142.7" cy="134" r=".93" fill="#008000" stroke="#008000" stroke-width=".18"/>
<circle cx="142.7" cy="134" r=".51" fill="#fff" stroke="#000" stroke-width=".18"/>
<circle cx="136.2" cy="138.5" r=".93" fill="#008000" stroke="#008000" stroke-width=".18"/>
<circle cx="136.2" cy="138.5" r=".51" fill="#fff" stroke="#000" stroke-width=".18"/>
<circle cx="142.7" cy="138.5" r=".93" fill="#008000" stroke="#008000" stroke-width=".18"/>
<circle cx="142.7" cy="138.5" r=".51" fill="#fff" stroke="#000" stroke-width=".18"/>
<circle cx="110.8" cy="134" r=".93" fill="#008000" stroke="#008000" stroke-width=".18"/>
<circle cx="110.8" cy="134" r=".51" fill="#fff" stroke="#000" stroke-width=".18"/>
<circle cx="117.3" cy="134" r=".93" fill="#008000" stroke="#008000" stroke-width=".18"/>
<circle cx="117.3" cy="134" r=".51" fill="#fff" stroke="#000" stroke-width=".18"/>
<circle cx="110.8" cy="138.5" r=".93" fill="#008000" stroke="#008000" stroke-width=".18"/>
<circle cx="110.8" cy="138.5" r=".51" fill="#fff" stroke="#000" stroke-width=".18"/>
<circle cx="117.3" cy="138.5" r=".93" fill="#008000" stroke="#008000" stroke-width=".18"/>
<circle cx="117.3" cy="138.5" r=".51" fill="#fff" stroke="#000" stroke-width=".18"/>
<circle cx="66.4" cy="112.8" r="1.17" fill="#008000" stroke="#008000" stroke-width=".18"/>
<circle cx="66.4" cy="112.8" r=".51" fill="#fff" stroke="#000" stroke-width=".18"/>
<circle cx="74" cy="112.8" r="1.17" fill="#008000" stroke="#008000" stroke-width=".18"/>
<circle cx="74" cy="112.8" r=".51" fill="#fff" stroke="#000" stroke-width=".18"/>
<circle cx="79.4" cy="117.2" r=".93" fill="#008000" stroke="#008000" stroke-width=".18"/>
<circle cx="79.4" cy="117.2" r=".44" fill="#fff" stroke="#000" stroke-width=".18"/>
<circle cx="79.4" cy="124.9" r=".93" fill="#008000" stroke="#008000" stroke-width=".18"/>
<circle cx="79.4" cy="124.9" r=".44" fill="#fff" stroke="#000" stroke-width=".18"/>
<path d="M99.8 138h1.7v1.7h-1.7z" fill="#008000" stroke="#008000" stroke-width=".18"/>
<circle cx="100.7" cy="138.8" r=".55" fill="#fff" stroke="#000" stroke-width=".18"/>
<circle cx="100.7" cy="136.3" r=".85" fill="#008000" stroke="#008000" stroke-width=".18"/>
<circle cx="100.7" cy="136.3" r=".55" fill="#fff" stroke="#000" stroke-width=".18"/>
<circle cx="100.7" cy="133.7" r=".85" fill="#008000" stroke="#008000" stroke-width=".18"/>
<circle cx="100.7" cy="133.7" r=".55" fill="#fff" stroke="#000" stroke-width=".18"/>
<circle cx="100.7" cy="131.2" r=".85" fill="#008000" stroke="#008000" stroke-width=".18"/>
<circle cx="100.7" cy="131.2" r=".55" fill="#fff" stroke="#000" stroke-width=".18"/>
<circle cx="100.7" cy="128.7" r=".85" fill="#008000" stroke="#008000" stroke-width=".18"/>
<circle cx="100.7" cy="128.7" r=".55" fill="#fff" stroke="#000" stroke-width=".18"/>
<circle cx="100.7" cy="126.1" r=".85" fill="#008000" stroke="#008000" stroke-width=".18"/>
<circle cx="100.7" cy="126.1" r=".55" fill="#fff" stroke="#000" stroke-width=".18"/>
<circle cx="100.7" cy="123.6" r=".85" fill="#008000" stroke="#008000" stroke-width=".18"/>
<circle cx="100.7" cy="123.6" r=".55" fill="#fff" stroke="#000" stroke-width=".18"/>
<circle cx="100.7" cy="121.1" r=".85" fill="#008000" stroke="#008000" stroke-width=".18"/>
<circle cx="100.7" cy="121.1" r=".55" fill="#fff" stroke="#000" stroke-width=".18"/>
<circle cx="100.7" cy="118.5" r=".85" fill="#008000" stroke="#008000" stroke-width=".18"/>
<circle cx="100.7" cy="118.5" r=".55" fill="#fff" stroke="#000" stroke-width=".18"/>
<circle cx="100.7" cy="116" r=".85" fill="#008000" stroke="#008000" stroke-width=".18"/>
<circle cx="100.7" cy="116" r=".55" fill="#fff" stroke="#000" stroke-width=".18"/>
<circle cx="100.7" cy="113.4" r=".85" fill="#008000" stroke="#008000" stroke-width=".18"/>
<circle cx="100.7" cy="113.4" r=".55" fill="#fff" stroke="#000" stroke-width=".18"/>
<circle cx="100.7" cy="110.9" r=".85" fill="#008000" stroke="#008000" stroke-width=".18"/>
<circle cx="100.7" cy="110.9" r=".55" fill="#fff" stroke="#000" stroke-width=".18"/>
<circle cx="100.7" cy="108.4" r=".85" fill="#008000" stroke="#008000" stroke-width=".18"/>
<circle cx="100.7" cy="108.4" r=".55" fill="#fff" stroke="#000" stroke-width=".18"/>
<circle cx="100.7" cy="105.8" r=".85" fill="#008000" stroke="#008000" stroke-width=".18"/>
<circle cx="100.7" cy="105.8" r=".55" fill="#fff" stroke="#000" stroke-width=".18"/>
<circle cx="93.1" cy="105.8" r=".85" fill="#008000" stroke="#008000" stroke-width=".18"/>
<circle cx="93.1" cy="105.8" r=".55" fill="#fff" stroke="#000" stroke-width=".18"/>
<circle cx="93.1" cy="108.4" r=".85" fill="#008000" stroke="#008000" stroke-width=".18"/>
<circle cx="93.1" cy="108.4" r=".55" fill="#fff" stroke="#000" stroke-width=".18"/>
<circle cx="93.1" cy="110.9" r=".85" fill="#008000" stroke="#008000" stroke-width=".18"/>
<circle cx="93.1" cy="110.9" r=".55" fill="#fff" stroke="#000" stroke-width=".18"/>
<circle cx="93.1" cy="113.4" r=".85" fill="#008000" stroke="#008000" stroke-width=".18"/>
<circle cx="93.1" cy="113.4" r=".55" fill="#fff" stroke="#000" stroke-width=".18"/>
<circle cx="93.1" cy="116" r=".85" fill="#008000" stroke="#008000" stroke-width=".18"/>
<circle cx="93.1" cy="116" r=".55" fill="#fff" stroke="#000" stroke-width=".18"/>
<circle cx="93.1" cy="118.5" r=".85" fill="#008000" stroke="#008000" stroke-width=".18"/>
<circle cx="93.1" cy="118.5" r=".55" fill="#fff" stroke="#000" stroke-width=".18"/>
<circle cx="93.1" cy="121.1" r=".85" fill="#008000" stroke="#008000" stroke-width=".18"/>
<circle cx="93.1" cy="121.1" r=".55" fill="#fff" stroke="#000" stroke-width=".18"/>
<circle cx="93.1" cy="123.6" r=".85" fill="#008000" stroke="#008000" stroke-width=".18"/>
<circle cx="93.1" cy="123.6" r=".55" fill="#fff" stroke="#000" stroke-width=".18"/>
<circle cx="93.1" cy="126.1" r=".85" fill="#008000" stroke="#008000" stroke-width=".18"/>
<circle cx="93.1" cy="126.1" r=".55" fill="#fff" stroke="#000" stroke-width=".18"/>
<circle cx="93.1" cy="128.7" r=".85" fill="#008000" stroke="#008000" stroke-width=".18"/>
<circle cx="93.1" cy="128.7" r=".55" fill="#fff" stroke="#000" stroke-width=".18"/>
<circle cx="93.1" cy="131.2" r=".85" fill="#008000" stroke="#008000" stroke-width=".18"/>
<circle cx="93.1" cy="131.2" r=".55" fill="#fff" stroke="#000" stroke-width=".18"/>
<circle cx="93.1" cy="133.7" r=".85" fill="#008000" stroke="#008000" stroke-width=".18"/>
<circle cx="93.1" cy="133.7" r=".55" fill="#fff" stroke="#000" stroke-width=".18"/>
<circle cx="93.1" cy="136.3" r=".85" fill="#008000" stroke="#008000" stroke-width=".18"/>
<circle cx="93.1" cy="136.3" r=".55" fill="#fff" stroke="#000" stroke-width=".18"/>
<circle cx="93.1" cy="138.8" r=".85" fill="#008000" stroke="#008000" stroke-width=".18"/>
<circle cx="93.1" cy="138.8" r=".55" fill="#fff" stroke="#000" stroke-width=".18"/>
<circle cx="61.3" cy="134" r="1.4" fill="#008000" stroke="#008000" stroke-width=".18"/>
<circle cx="61.3" cy="134" r=".93" fill="#fff" stroke="#000" stroke-width=".18"/>
<circle cx="61.3" cy="120.8" r="1.4" fill="#008000" stroke="#008000" stroke-width=".18"/>
<circle cx="61.3" cy="120.8" r=".93" fill="#fff" stroke="#000" stroke-width=".18"/>
<circle cx="104.5" cy="102" r=".93" fill="#008000" stroke="#008000" stroke-width=".18"/>
<circle cx="104.5" cy="102" r=".51" fill="#fff" stroke="#000" stroke-width=".18"/>
<circle cx="102" cy="102" r=".93" fill="#008000" stroke="#008000" stroke-width=".18"/>
<circle cx="102" cy="102" r=".51" fill="#fff" stroke="#000" stroke-width=".18"/>
<circle cx="99.4" cy="102" r=".93" fill="#008000" stroke="#008000" stroke-width=".18"/>
<circle cx="99.4" cy="102" r=".51" fill="#fff" stroke="#000" stroke-width=".18"/>
<circle cx="96.9" cy="102" r=".93" fill="#008000" stroke="#008000" stroke-width=".18"/>
<circle cx="96.9" cy="102" r=".51" fill="#fff" stroke="#000" stroke-width=".18"/>
<circle cx="94.3" cy="102" r=".93" fill="#008000" stroke="#008000" stroke-width=".18"/>
<circle cx="94.3" cy="102" r=".51" fill="#fff" stroke="#000" stroke-width=".18"/>
<circle cx="87.4" cy="126.5" r=".93" fill="#008000" stroke="#008000" stroke-width=".18"/>
<circle cx="87.4" cy="126.5" r=".44" fill="#fff" stroke="#000" stroke-width=".18"/>
<circle cx="87.4" cy="118.8" r=".93" fill="#008000" stroke="#008000" stroke-width=".18"/>
<circle cx="87.4" cy="118.8" r=".44" fill="#fff" stroke="#000" stroke-width=".18"/>
<circle cx="87.4" cy="139.4" r=".93" fill="#008000" stroke="#008000" stroke-width=".18"/>
<circle cx="87.4" cy="139.4" r=".44" fill="#fff" stroke="#000" stroke-width=".18"/>
<circle cx="87.4" cy="131.8" r=".93" fill="#008000" stroke="#008000" stroke-width=".18"/>
<circle cx="87.4" cy="131.8" r=".44" fill="#fff" stroke="#000" stroke-width=".18"/>
<circle cx="90.2" cy="131.8" r=".93" fill="#008000" stroke="#008000" stroke-width=".18"/>
<circle cx="90.2" cy="131.8" r=".44" fill="#fff" stroke="#000" stroke-width=".18"/>
<circle cx="90.2" cy="139.4" r=".93" fill="#008000" stroke="#008000" stroke-width=".18"/>
<circle cx="90.2" cy="139.4" r=".44" fill="#fff" stroke="#000" stroke-width=".18"/>
<circle cx="84.8" cy="135.6" r=".83" fill="#008000" stroke="#008000" stroke-width=".18"/>
<circle cx="84.8" cy="135.6" r=".44" fill="#fff" stroke="#000" stroke-width=".18"/>
<circle cx="84.8" cy="138.2" r=".83" fill="#008000" stroke="#008000" stroke-width=".18"/>
<circle cx="84.8" cy="138.2" r=".44" fill="#fff" stroke="#000" stroke-width=".18"/>
<circle cx="82" cy="114.1" r=".83" fill="#008000" stroke="#008000" stroke-width=".18"/>
<circle cx="82" cy="114.1" r=".44" fill="#fff" stroke="#000" stroke-width=".18"/>
<circle cx="79.4" cy="114.1" r=".83" fill="#008000" stroke="#008000" stroke-width=".18"/>
<circle cx="79.4" cy="114.1" r=".44" fill="#fff" stroke="#000" stroke-width=".18"/>
<circle cx="82" cy="111.2" r=".83" fill="#008000" stroke="#008000" stroke-width=".18"/>
<circle cx="82" cy="111.2" r=".44" fill="#fff" stroke="#000" stroke-width=".18"/>
<circle cx="79.4" cy="111.2" r=".83" fill="#008000" stroke="#008000" stroke-width=".18"/>
<circle cx="79.4" cy="111.2" r=".44" fill="#fff" stroke="#000" stroke-width=".18"/>
<circle cx="103.9" cy="121.1" r=".83" fill="#008000" stroke="#008000" stroke-width=".18"/>
<circle cx="103.9" cy="121.1" r=".44" fill="#fff" stroke="#000" stroke-width=".18"/>
<circle cx="103.9" cy="123.6" r=".83" fill="#008000" stroke="#008000" stroke-width=".18"/>
<circle cx="103.9" cy="123.6" r=".44" fill="#fff" stroke="#000" stroke-width=".18"/>
<g fill="#800000" stroke="#800000" stroke-width=".18">
<path d="M53.7 139.2a2.88 2.88 0 0 1 4.6 .2 2.88 2.88 0 0 1-1.5 4.4 2.88 2.88 0 0 1-3.7-2.8h2.5a.35 .35 0 0 1 .4-.3 .35 .35 0 0 1 .2 .5 .35 .35 0 0 1-.6-.1l-2.5-.1v-.6z" fill-rule="evenodd"/>
<path d="M53.7 99.6a2.89 2.89 0 0 1 4.6 .1 2.89 2.89 0 0 1-1.5 4.4 2.89 2.89 0 0 1-3.7-2.7h2.5a.35 .35 0 0 1 .4-.4 .35 .35 0 0 1 .2 .6 .35 .35 0 0 1-.6-.1l-2.5-.1v-.7z" fill-rule="evenodd"/>
<path d="M147 99.6a2.88 2.88 0 0 1 4.6 .2 2.88 2.88 0 0 1-1.5 4.3 2.88 2.88 0 0 1-3.7-2.7h2.5a.35 .35 0 0 1 .5-.3 .35 .35 0 0 1 0 .6 .35 .35 0 0 1-.5-.2l-2.5-.1 .2-1.3z" fill-rule="evenodd"/>
<path d="M147.4 138.8a2.89 2.89 0 0 1 4.4 1 2.89 2.89 0 0 1-1.9 4 2.89 2.89 0 0 1-3.5-2.8h2.5a.35 .35 0 0 1 .5-.2 .35 .35 0 0 1 0 .6 .35 .35 0 0 1-.5-.3l-2.5-.1a2.87 2.87 0 0 1 1-2.2z" fill-rule="evenodd"/>
</g>
<g fill="none" stroke="#505050" stroke-width=".18">
<path d="M53 115.7h.4l.1 .2M53.1 114.7h.4a.2 .2 0 0 1-.2 .2 .2 .2 0 0 1-.2-.2zM53.2 114.7l.2 .2M53.5 115.2v.2M53.5 115.3h-.5l.2 .1M72.1 104.5l.1-.1v.4M72.1 104.8h.2M72.4 102h.1M72.5 102l.1-.2-.2-.1v.5M72.5 102l.1 .2M72.7 104.4a.2 .2 0 0 1 .2 .2 .2 .2 0 0 1-.3 .2zM72.9 104.5l-.3 .2"/>
<path d="M73 101.7l-.1 .4h.3M73.1 102v.2M73.2 104.4v.4M73.3 104.5l.2 .3M73.5 104.4l-.3 .3M73.7 110.3h.7M74 109.9v.7M79.7 112.6v-.1a.2 .2 0 0 1 .2 .3 .2 .2 0 0 1-.2 .1zM79.7 109.7a.2 .2 0 0 1 .2 .2 .2 .2 0 0 1-.2 .2zM79.9 112.6l-.2 .3M79.9 109.8l-.2 .2M80.2 113h.1"/>
<path d="M80.2 110.2h.1M80.4 112.6l.2-.1v.5M80.4 109.8l.2-.1v.5M80.4 113h.3M80.4 110.2h.3M80.5 101.2v.3l.3 .2h2.2l.1 .1v.2l-.1 .1-1.8 .1v.2l.2 .1h1l.2 .2-.2 .2-.8 .1 .1 .3h.6v.3l-.8 .1-.1 .3 1.3 .1 .1 .2-.2 .2h-1.5l-.1 .2 .2 .2h1.9l.3 .2 .1 .3M80.5 115.1l-.2 .1 .1 .4h.1M80.5 112.3l-.2 .1 .1 .3 .1 .1M80.8 115.2h.2l-.2 .4h.3M80.8 112.3l.2 .1v.1h-.1M80.9 112.5l.1 .2-.2 .1M81 112.9l.3 .1"/>
<path d="M81 110l.3 .2M81 109.8v.5M81 112.7v.5M81.2 109.8v.2M81.2 112.7v.2M81.5 112.7h.2M81.5 109.9h.2M81.7 112.5h-.2v.5M81.7 109.7h-.2v.5M84.2 111.1h5v4.6h-5zM84.4 111.4h4.6v4.1h-4.6zM92.5 105.3h.6l.1 1.1h-.7z"/>
<path d="M92.5 107.8h.6l.1 1.1h-.7zM92.5 110.3h.7v1.2h-.7zM92.5 112.9h.7v1.1h-.7zM92.5 115.4h.7v1.1h-.7zM92.5 118h.7v1.1h-.7zM93.1 104.9h7.5v34.8h-7.5zM94 104.9h5.7M100.6 118h.7v1.1h-.7zM100.6 115.4h.7v1.1h-.7zM100.6 112.9h.7v1.1h-.7zM100.6 110.3h.7v1.2h-.7zM100.6 107.8h.7v1.1h-.7z"/>
<path d="M100.6 105.3h.7v1.1h-.7zM105.1 103.5v.4l-.1 .1M105.4 103.6l.3-.1-.3 .5h.3M110.8 100.6h.2v-.2h-.2v.4M111.3 100.4h.2v.4h-.2zM111.8 100.4l.2 .4 .1-.3 .1 .3 .1-.4M112.6 100.6h.1M112.8 100.4h-.2v.4h.2M113.1 100.6h.2v-.2h-.2v.4M113.2 100.6l.1 .2M113.6 100.9h.2M114.1 100.4v.3l-.2 .1"/>
<path d="M114.4 100.8l.1-.4 .2 .4M114.4 100.7h.3M114.8 101.4v.4l-.2 .1M115.1 101.5l.1-.1v.5M115.1 101.9h.2M115.2 100.4l-.2 .1v.3h.2M115.4 100.4v.4M115.5 100.5l.2 .3M115.7 100.4l-.3 .3M119.1 108.2h.5M119.1 107.9l.3 .3M119.3 108.7l.2-.2 .1 .3"/>
<path d="M119.3 108.6h-.2v.2M119.3 108.6v.1M119.6 107.9l-.3 .2M122.3 108.8h-.5v-.3h.2v.3M122.3 108.5l-.3 .1M122.3 108v.2M122.3 108.1h-.5l.1 .1M123.2 118.3l5.4 .1 .2-.1h1.3l.2 .2v2.6l-.3 .2h-1.2l-.2-.1-5.3 .1-.1-.2zM123.4 118.6v2.3M124.7 118.6v2.3M128.8 118.6v2.3M130 118.6v2.3"/>
<path d="M133.7 115.1v.2h.5M133.7 104.6v.2h.5M133.7 105.7a.21 .21 0 0 1 .3-.1 .21 .21 0 0 1 .1 .3h-.4zM133.7 116.2h.4a.18 .18 0 0 1-.2 .2 .18 .18 0 0 1-.2-.2zM133.8 116.2l.2 .2M133.8 105.7l.2 .2M133.8 115.8h.5M133.8 105.3h.5M133.8 115.6h.2M133.8 105.1h.2M133.9 104.6v.2M133.9 115.1v.2"/>
<path d="M134.2 115.5l-.2 .3M134.2 105.1l-.2 .2M134.2 117.2v.3l-.5-.2 .1 .2M134.2 116.7v.2l-.5-.2 .1 .2M134.2 106.8v.2l-.5-.2 .1 .2M134.2 106.2v.3l-.5-.3 .1 .3M144.7 115.6h.5M144.7 105.1h.5M144.7 117.5l.1 .2h.3l.1-.2M144.7 116h.5l-.1 .2h-.4M144.7 105.5l.5 .1-.2 .2h-.3M144.7 104.9v.3"/>
<path d="M144.7 115.4v.3M144.7 116.5h.3l.2 .2-.5 .1zM144.7 106.1h.4l.1 .1-.5 .1zM145.2 107l-.1 .2h-.3l-.1-.2M145.2 114.9v.3M145.2 104.4v.3l-.5-.2 .1 .2M145.2 115h-.5l.1 .2M145.2 106.6v.2M145.2 117v.2M148.3 115.7l.4 .1v.1M148.7 115.3l-.4-.1v.2M54.3 130l.1 .6 .8 .1 .2-.2 .1-.5h-.7v.2"/>
<path d="M55.5 128.8v.7M55.5 129.2h-1.2l.2 .3M55.7 127.2v.4M55.7 128.1l.2 1.1M56 125.3l-.2 .8M56.3 130.2l.2 .3M56.5 121.5a1.61 1.61 0 0 1 1.3-.4v-.3h7.1v.3l2.7 2.7h.4v7.1h-.2l-2.9 2.9v.1h-7.1v-.2a1.65 1.65 0 0 1-1.7-1.1 1.65 1.65 0 0 1 .5-1.9 6.9 6.9 0 0 0-.5-7.7 1.53 1.53 0 0 1 .4-1.5zM56.7 124l-.3 .5M56.9 131l.7 .8M57.9 122.8l-.8 .8M58.1 132.1l.5 .4M58.1 129.7h4.8a.8 .8 0 0 1 .8 .8 .8 .8 0 0 1-.8 .8h-4.8"/>
<path d="M58.2 123.4h4.6a.8 .8 0 0 1 .8 .9 .8 .8 0 0 1-.8 .8h-4.6M58.2 123.6v1.2M58.2 129.9v1.2M58.4 123.7v1M58.4 130v1M58.6 123.8v.8M58.6 130.1v.8M58.7 122.3l-.3 .2M59.4 132.8l.8 .3M60.5 134v.7h1.6v-.7M60.5 120.7v-.7h1.6v.7M60.7 121.6l-1 .3"/>
<path d="M61.2 125.1a1.96 1.96 0 0 0 3 .7 1.96 1.96 0 0 0 0-3.1 1.96 1.96 0 0 0-3 .7 1.95 1.95 0 0 1 3.2-.5 1.95 1.95 0 0 1-.9 3.2M61.2 123.6v1.3M61.2 129.9v1.2M61.3 133.2h.4M61.3 121.6h.4M61.4 123.7v1.1M61.4 130v1M61.6 123.8v.9M61.6 130.1v.8M62.7 121.7l.8 .2M63.3 132.9l-1.1 .3M63.5 128.6a1.96 1.96 0 0 1 .9 3.2 1.96 1.96 0 0 1-3.2-.5 1.96 1.96 0 0 0 2.9 .7 1.96 1.96 0 0 0 0-3.1 1.96 1.96 0 0 0-2.9 .7"/>
<path d="M64.3 122.3l.6 .3M64.6 132.3l-.3 .2M65.3 123l.8 .8M65.9 131.3l-.9 .7M66.4 124.3l.2 .3M66.6 130.3l-.4 .5M67 125.6l.3 1M67.2 128.7l-.3 .8M67.3 127.2v.4M68.7 128.4h1.2M68.7 128.1v.7M68.8 130.4h.3l.1 .2 .1-.3h.3l.2 .2 .1 .4h-1.2z"/>
<path d="M69.2 130.6v.3M69.6 129.2v.6M69.9 129.1l-1.2 .4 1.2 .4M72.9 126.8h7.4v12.6h-7.4zM77.9 120.9h.4a.18 .18 0 0 1-.2 .3 .18 .18 0 0 1-.2-.3zM77.9 120.4h.4a.18 .18 0 0 1-.2 .2 .18 .18 0 0 1-.2-.2zM78 120.9l.2 .3M78 120.4l.2 .2M78.4 121.5v.2M78.4 121.6h-.5l.1 .1M81 121.5h-.5v-.3h.3v.3M81 121.2l-.2 .1"/>
<path d="M81 120.7v.2l-.5-.2 .1 .2M83.3 135.9v.2h.5M83.3 137.8a.22 .22 0 0 1 .3-.1 .22 .22 0 0 1 .1 .2h-.3zM83.4 137.7l.3 .2M83.4 136.6h.5M83.4 136.4h.3M83.5 135.9v.2M83.8 137.5h.1M83.8 136.9v.3M83.8 136.3l-.1 .3M83.8 137.1h-.5l.1 .1M85.8 135.2v.3h.2l.1-.3 .2 .1v.2"/>
<path d="M85.9 137.1l.1 .2h.3l.1-.2M86 122.4l.2-.2 .1 .3M86 122.5l-.1-.3-.1 .3M86.3 123h-.5v-.2h.2l.1 .2M86.3 136h-.5v-.2h.2l.1 .2M86.3 122.8l-.2 .1M86.3 135.8l-.2 .1M86.4 136.5v.3M86.4 136.7h-.5l.1 .1M88.4 122.2h.5M88.4 135.2h.7M88.4 121.9l.3 .3"/>
<path d="M88.4 134.9l.3 .3M88.5 122.6a.22 .22 0 0 1 .2-.1 .22 .22 0 0 1 .2 .2h-.4zM88.5 135.6a.22 .22 0 0 1 .2-.1 .22 .22 0 0 1 .2 .2l-.3 .1zM88.5 122.5l.3 .3M88.5 135.6l.3 .2M88.7 135.6a.22 .22 0 0 1 .2-.1 .22 .22 0 0 1 .2 .2l-.3 .1zM88.7 134.9l.3 .3M88.8 135.6l.2 .2M88.9 121.9l-.3 .2M88.9 134.9l-.3 .2M88.9 123.1v.2l-.4-.2v.2M88.9 136.1v.2l-.4-.2v.2"/>
<path d="M89.1 134.9l-.3 .2M89.1 136.1v.2l-.4-.2 .1 .2M91.3 135.3l.2 .2M91.5 135.3h.2v.2h-.2zM91.8 136h-.5v-.2h.2l.1 .2M91.8 135.8l-.2 .1M92.5 120.5h.7v1.1h-.7zM92.5 123h.7v1.1h-.7zM92.5 125.6h.7v1.1h-.7zM92.5 128.1h.7v1.1h-.7zM92.5 130.6h.7v1.2h-.7zM92.5 133.2h.7v1.1h-.7z"/>
<path d="M92.5 135.7h.7v1.1h-.7zM92.5 138.3h.7v1.1h-.7zM94 139.7h5.4M96.6 139.7l.2-.3 .3 .1 .1 .2M100.6 138.3h.7v1.1h-.7zM100.6 135.7h.7v1.1h-.7zM100.6 133.2h.7v1.1h-.7zM100.6 130.6h.7v1.2h-.7zM100.6 128.1h.7v1.1h-.7zM100.6 125.6h.7v1.1h-.7zM100.6 123h.7v1.1h-.7zM100.6 120.5h.7v1.1h-.7z"/>
<path d="M102.3 121.3v.2h.5M102.4 123.1l.4 .1a.2 .2 0 0 1-.2 .2 .2 .2 0 0 1-.2-.3zM102.4 123.1l.3 .2M102.5 122h.5M102.5 121.8h.2M102.5 121.3v.2M102.8 122.9h.1M102.8 122.3v.3M102.8 121.7l-.1 .3M102.8 122.5h-.5l.1 .1M104.9 122.5l.1 .2h.4v-.2M105.2 122h.2"/>
<path d="M105.3 122v.2l-.4-.1M113.9 132.5l-.2-.1-.1 .2 .3 .3-.3-.1M114.2 132.4l.2 .1-.2 .2M114.2 139.7l-.3 .1 .3 .1M114.3 132.7l.1 .1-.2 .1M123.4 123.9h4.1v1.9h-4.1zM124.8 124.9h.7l1-.7v1.3l-1-.6h1.5M125.5 124.2v1.3M126.6 132.5h-.3l.3 .4-.3-.1M126.6 139.7l.1 .3 .1-.3M126.9 132.5l.1-.1v.5M126.9 132.9h.2"/>
<path d="M135.6 124.7v3l.3 .2h9.6l.3-.2v-3M139.3 132.5h-.3l.3 .4-.3-.1M139.3 139.7l.3 .1-.3 .1M139.6 132.5h.2l-.2 .4h.2"/>
<circle cx="55.9" cy="101.3" r="2.86"/>
<circle cx="70.2" cy="112.8" r="6.1"/>
<circle cx="70.2" cy="112.8" r="1.27"/>
<circle cx="112.8" cy="119.1" r="3.2"/>
<circle cx="119.4" cy="116" r="2.03"/>
<circle cx="149.2" cy="101.3" r="2.86"/>
<circle cx="55.9" cy="141" r="2.86"/>
<circle cx="149.2" cy="141" r="2.86"/>
</g>
<path d="M115.3 117.9v2.5M118.8 117.9h1.3" fill="none" stroke="#505050" stroke-width=".32"/>
<g fill="none" stroke="#505050" stroke-width=".21">
<path d="M53.7 106.5l.7-.7h1.2l.7 .7v1.2l-.7 .7 .7 .6v1.3l-.7 .6 .7 .6v1.3l-.7 .6 .7 .7v1.2l-.7 .7h-1.2l-.7-.7v-1.2l.7-.7-.7-.6v-1.3l.7-.6-.7-.6v-1.3l.7-.6-.7-.7zM70 103.3h.2M70.2 102.5h5.1v1.5h-5.1zM75.3 103.3h.3M78.7 118.5h1.5v5.1h-1.5zM79.4 118.3v.2M79.7 111.2h.5M79.7 114.1h.5M80.2 113.4v1.3M80.2 110.6v1.2M80.4 101a2.7 2.7 0 0 0 .1 4.6h3a2.7 2.7 0 0 0 0-4.6h-3M81.2 113.4v1.3"/>
<path d="M81.2 110.6v1.2M81.2 111.2h.5M81.2 114.1h.5M87.4 119.8v.3M93.1 101.4l.6-.6h1.3l.6 .6 .6-.6h1.3l.7 .6 .6-.6h1.3l.6 .6 .6-.6h1.3l.6 .6 .7-.6h1.2l.7 .6v1.2l-.7 .7h-1.2l-.7-.7-.6 .7h-1.3l-.6-.7-.6 .7h-1.3l-.6-.7-.7 .7h-1.3l-.6-.7-.6 .7h-1.3l-.6-.7zM109.5 112.5v.7h2.1M109.5 102.5h9M118.5 102.5v10.7h-2.1M118.5 102.5v-2.9h-9v8.2M119.9 105.8h1.6v5.1h-1.6zM120.7 105.6v.2M120.7 110.9v.2"/>
<path d="M122.9 101.2h10.2v10h-10.2zM122.9 100.7l1.7-.5h6.8l1.7 .5v.4h-10.2zM122.9 101.1h10.2M122.9 100.9h10.2M122.9 100.7h10.2M123.4 100.5h9.2M124 100.4h7.9M141.3 118.8h1.3M141.3 108.4h1.3M141.9 102.6v1.3M141.9 107.7v1.3M141.9 113.1v1.3"/>
<path d="M141.9 118.2v1.3M148.9 106.5l.7-.7h1.2l.7 .7v1.2l-.7 .7 .7 .6v1.3l-.7 .6 .7 .6v1.3l-.7 .6 .7 .7v1.2l-.7 .7h-1.2l-.7-.7v-1.2l.7-.7-.7-.6v-1.3l.7-.6-.7-.6v-1.3l.7-.6-.7-.7zM79.4 123.6v.2M84.2 136.4h1.3M84.2 137.4h1.3M84.8 136v.4M84.8 137.4v.5M86.6 120.1h1.5v5.1h-1.5zM86.6 133.1h1.5v5.1h-1.5zM87.4 125.2v.2M87.4 132.8v.3M87.4 138.2v.2"/>
<path d="M89.5 133.1h1.5v5.1h-1.5zM90.2 132.8v.3M90.2 138.2v.2M103.2 121.8h1.3M103.2 122.8h1.3M103.9 121.4v.4M103.9 122.8v.5M111.5 135v.8l.4 .9M111.5 136.8v.7M117.1 135.3v-1.6l-.5-.5h-5.1l-.5 .5v5.1l.5 .5h5.1l.5-.5v-3.5M124.2 135v.8l.4 .9M124.2 136.8v.7"/>
<path d="M129.8 135.3v-1.6l-.5-.5h-5.1l-.5 .5v5.1l.5 .5h5.1l.5-.5v-3.5M136.9 135v.8l.4 .9M136.9 136.8v.7M142.5 135.3v-1.6l-.6-.5h-5l-.5 .5v5.1l.5 .5h5l.6-.5v-3.5"/>
<circle cx="139.4" cy="116.3" r="5"/>
<circle cx="139.4" cy="105.8" r="5"/>
<circle cx="114" cy="136.3" r="1.78"/>
<circle cx="126.7" cy="136.3" r="1.78"/>
<circle cx="139.4" cy="136.3" r="1.78"/>
</g>
<g fill="#505050" stroke="#505050" stroke-width=".18">
<path d="M123.8 123.9h.5v1.9h-.5z"/>
<path d="M127.5 124.4h.7v.9h-.7z"/>
<path d="M122.7 124.4h.7v.9h-.7z"/>
<path d="M121.2 119.5h2v.6h-2z"/>
<path d="M130.3 119.5h1.9v.6h-1.9z"/>
<path d="M124.1 111.1h1v1.7h-1z"/>
<path d="M125.8 111.1h1v1.7h-1z"/>
<path d="M127.5 111.1h1v1.7h-1z"/>
<path d="M129.2 111.1h1v1.7h-1z"/>
<path d="M130.9 111.1h1v1.7h-1z"/>
<path d="M135.4 123.6h1.9v1.3h-1.9z"/>
<path d="M137.3 123.6h1.7v.8h-1.7z"/>
<path d="M139 123.6h.8v1.3h-.8z"/>
<path d="M139.8 123.6h1.8v.8h-1.8z"/>
<path d="M141.6 123.6h.7v1.3h-.7z"/>
<path d="M142.3 123.6h1.8v.8h-1.8z"/>
<path d="M144.1 123.6h1.9v1.3h-1.9z"/>
<path d="M64.7 127.2h2.2v.4h-2.2z"/>
<path d="M65.6 126.3h.4v2.2h-.4z"/>
<path d="M124.1 112.8h1v2.2h-1z"/>
<path d="M125.8 112.8h1v2.2h-1z"/>
<path d="M127.5 112.8h1v2.2h-1z"/>
<path d="M129.2 112.8h1v2.2h-1z"/>
<path d="M130.9 112.8h1v2.2h-1z"/>
<path d="M149.9 106.8h.6v.5h-.6z"/>
<path d="M149.9 109.4h.6v.5h-.6z"/>
<path d="M149.9 111.9h.6v.5h-.6z"/>
<path d="M149.9 114.5h.6v.5h-.6z"/>
<path d="M54.7 106.8h.5v.5h-.5z"/>
<path d="M54.7 109.4h.5v.5h-.5z"/>
<path d="M54.7 111.9h.5v.5h-.5z"/>
<path d="M54.7 114.5h.5v.5h-.5z"/>
<path d="M137.3 124.4h1.7v.5h-1.7z"/>
<path d="M139.8 124.4h1.8v.5h-1.8z"/>
<path d="M142.3 124.4h1.8v.5h-1.8z"/>
<path d="M71.5 127.2h1.3v.4h-1.3z"/>
<path d="M71.5 128.5h1.3v.4h-1.3z"/>
<path d="M71.5 129.7h1.3v.4h-1.3z"/>
<path d="M71.5 131h1.3v.4h-1.3z"/>
<path d="M71.5 132.3h1.3v.4h-1.3z"/>
<path d="M71.5 133.5h1.3v.4h-1.3z"/>
<path d="M71.5 134.8h1.3v.4h-1.3z"/>
<path d="M71.5 136.1h1.3v.4h-1.3z"/>
<path d="M71.5 137.3h1.3v.5h-1.3z"/>
<path d="M71.5 138.6h1.3v.4h-1.3z"/>
<path d="M80.3 127.2h1.3v.4h-1.3z"/>
<path d="M80.3 128.5h1.3v.4h-1.3z"/>
<path d="M80.3 129.7h1.3v.4h-1.3z"/>
<path d="M80.3 131h1.3v.4h-1.3z"/>
<path d="M80.3 132.3h1.3v.4h-1.3z"/>
<path d="M80.3 133.5h1.3v.4h-1.3z"/>
<path d="M80.3 134.8h1.3v.4h-1.3z"/>
<path d="M80.3 136.1h1.3v.4h-1.3z"/>
<path d="M80.3 137.3h1.3v.5h-1.3z"/>
<path d="M80.3 138.6h1.3v.4h-1.3z"/>
<path d="M84.7 115.7h.2v.9h-.2z"/>
<path d="M85.3 115.7h.2v.9h-.2z"/>
<path d="M86 115.7h.2v.9h-.2z"/>
<path d="M86.6 115.7h.2v.9h-.2z"/>
<path d="M87.3 115.7h.2v.9h-.2z"/>
<path d="M87.9 115.7h.2v.9h-.2z"/>
<path d="M88.6 115.7h.2v.9h-.2z"/>
<path d="M88.6 110.3h.2v.9h-.2z"/>
<path d="M87.9 110.3h.2v.9h-.2z"/>
<path d="M87.3 110.3h.2v.9h-.2z"/>
<path d="M86.6 110.3h.2v.9h-.2z"/>
<path d="M86 110.3h.2v.9h-.2z"/>
<path d="M85.3 110.3h.2v.9h-.2z"/>
<path d="M84.7 110.3h.2v.9h-.2z"/>
<path d="M94.1 101.8h.5v.5h-.5z"/>
<path d="M96.6 101.8h.5v.5h-.5z"/>
<path d="M99.2 101.8h.5v.5h-.5z"/>
<path d="M101.7 101.8h.5v.5h-.5z"/>
<path d="M104.2 101.8h.6v.5h-.6z"/>
</g>
<g fill="#505050" stroke="#505050" stroke-width=".18">
<path d="M73.4 109.8a.84 .84 0 0 1 1.3 0 .84 .84 0 0 1-.4 1.3 .84 .84 0 0 1-1.1-.8h.1a.69 .69 0 0 1 1-.7 .69 .69 0 0 1 .2 1.2 .69 .69 0 0 1-1.1-.3l-.1-.2h-.1z" fill-rule="evenodd"/>
<path d="M78.9 138.1a.61 .61 0 0 1 1 .1 .61 .61 0 0 1-.4 .9 .61 .61 0 0 1-.8-.6h.2a.46 .46 0 0 1 .7-.4 .46 .46 0 0 1 .1 .8 .46 .46 0 0 1-.8-.2v-.2h-.2z" fill-rule="evenodd"/>
<path d="M84.8 114.3a.53 .53 0 0 1 .8 .1 .53 .53 0 0 1-.4 .8 .53 .53 0 0 1-.6-.5h.1a.38 .38 0 0 1 .6-.4 .38 .38 0 0 1 .1 .7 .38 .38 0 0 1-.6-.2l-.1-.1h-.1z" fill-rule="evenodd"/>
<circle cx="136.1" cy="127.3" r=".25"/>
</g>
<path d="M121.6 124.9h1.3M128 124.9h1.3" fill="none" stroke="#505050" stroke-width=".87"/>
<path d="M120.4 119.8h1.1M131.9 119.8h1.2" fill="none" stroke="#505050" stroke-width=".61"/>
<g fill="none" stroke="#000" stroke-width=".18">
<path d="M113 99.5h2M114 98.5v2M54 114.7h2M55 113.7v2M69.2 112.8h2M70.2 111.8v2M71.8 103.3h2M72.8 102.3v2M79.7 114.1h2M79.7 111.2h2M80.7 110.2v2M80.7 113.1v2"/>
<path d="M81 103.3h2M82 102.3v2M85.9 113.4h1.7M86.7 112.6v1.7M92.1 105.8h2M93.1 104.8v2M103.5 102h2M104.5 101v2M111.7 119.1h2.1M112.8 118.1v2.1M118.4 116h2M119.4 115v2"/>
<path d="M119.7 108.4h2M120.7 107.3v2.1M125.7 119.8h2M126.7 118.8v2M127 108.4h2M128 107.3v2.1M138.4 116.3h2M138.4 105.8h2M139.4 104.8v2M139.4 115.3v2M149.2 114.7h2M150.2 113.7v2"/>
<path d="M60.3 127.4h2.1M61.3 126.4v2M75.6 133.1h2M76.6 132.1v2M78.4 121.1h2.1M79.4 120v2.1M83.8 136.9h2M84.8 135.9v2M86.3 122.6h2.1M86.3 135.6h2.1M87.4 121.6v2.1M87.4 134.6v2.1"/>
<path d="M89.2 135.6h2M90.2 134.6v2.1M102.9 122.3h2M103.9 121.3v2M113 136.3h2M114 135.3v2M124.4 124.9h2.1M125.5 123.8v2.1M125.7 136.3h2M126.7 135.3v2M138.4 136.3h2M139.4 135.3v2"/>
<path d="M139.7 123.6h2M140.7 122.6v2"/>
</g>
<g fill="none" stroke="#f90" stroke-width=".18">
<path d="M53.9 99a2.4 2.4 0 0 1 1.5-.5h94.4a2.26 2.26 0 0 1 2.3 2.3v40.8a2.29 2.29 0 0 1-2.3 2.3h-94.4a2.29 2.29 0 0 1-2.3-2.3v-40.8a2.31 2.31 0 0 1 .8-1.8z"/>
<circle cx="55.9" cy="141" r="1.5"/>
</g>
<circle cx="55.9" cy="141" r="1.5" fill="#fff" stroke="#000" stroke-width=".18"/>
<circle cx="55.9" cy="101.3" r="1.5" fill="none" stroke="#f90" stroke-width=".18"/>
<circle cx="55.9" cy="101.3" r="1.5" fill="#fff" stroke="#000" stroke-width=".18"/>
<circle cx="149.2" cy="101.3" r="1.5" fill="none" stroke="#f90" stroke-width=".18"/>
<circle cx="149.2" cy="101.3" r="1.5" fill="#fff" stroke="#000" stroke-width=".18"/>
<circle cx="149.2" cy="141" r="1.5" fill="none" stroke="#f90" stroke-width=".18"/>
<circle cx="149.2" cy="141" r="1.5" fill="#fff" stroke="#000" stroke-width=".18"/>
<g fill="none" stroke="#505050" stroke-width=".18">
<path d="M56 113.7l-2 2M56 111.1l-2 2.1M56 108.6l-2 2M56 106.1l-2 2M57 100.3l-2.1 2M62.4 119.8l-2.1 2M67.4 111.8l-2 2M67.9 103.3h2.1M69 102.3v2M75.1 111.8l-2.1 2M75.6 103.3h2M76.6 102.3v2"/>
<path d="M78.4 117.2h2.1M78.4 114.1h2.1M78.4 111.2h2.1M79.2 103.3h1l1-1v2l-1-1M79.4 110.2v2M79.4 113.1v2M79.4 116.2v2.1M81 114.1h2M81 111.2h2M82 110.2v2M82 113.1v2M82.7 103.3h1l1.1-1v2l-1.1-1"/>
<path d="M86.3 118.8h2.1M87.4 117.8v2M94.1 117.5l-2 2M94.1 115l-2 2M94.1 112.4l-2 2.1M94.1 104.8l-2 2M94.1 107.3l-2 2.1M94.1 109.9l-2 2M95.4 101l-2.1 2M97.9 101l-2 2M100.4 101l-2 2M101.7 117.5l-2 2"/>
<path d="M101.7 115l-2 2M101.7 112.4l-2 2.1M101.7 109.9l-2 2M101.7 107.3l-2 2.1M101.7 104.8l-2 2M103 101l-2.1 2M105.5 101l-2 2M110.2 119.1h2M110.3 109.2l-2 2M111.2 118.1v2.1M113.3 119.1h2M114.3 118.1v2.1"/>
<path d="M115 112.1l-2 2.1M115 106.2l-2 2M118.4 117h2M118.4 115h2M119.4 113.9v4.1M119.7 104.5h2M119.7 112.2h2M120.7 103.5v2.1M120.7 111.1v2.1M121.4 118.8l-2 2M134.1 118.8l-2 2M138.4 113.8h2"/>
<path d="M138.4 118.8h2M138.4 103.3h2M138.4 108.3h2M139.4 102.3v2M139.4 107.3v2M139.4 112.8v2M139.4 117.8v2M150.3 100.3l-2.1 2M151.2 113.7l-2 2M151.2 111.1l-2 2.1M151.2 108.6l-2 2M151.2 106.1l-2 2"/>
<path d="M62.4 133l-2.1 2M78.4 124.9h2.1M79.4 123.8v2.1M83.8 135.6h2M83.8 138.2h2M84.8 134.6v2.1M84.8 137.2v2M86.3 126.5h2.1M86.3 139.4h2.1M86.3 131.8h2.1M87.4 125.4v2.1M87.4 130.8v2"/>
<path d="M87.4 138.4v2.1M89.2 139.4h2M89.2 131.8h2M90.2 130.8v2M90.2 138.4v2.1M94.1 137.8l-2 2M94.1 130.2l-2 2M94.1 125.1l-2 2.1M94.1 122.6l-2 2M94.1 120l-2 2.1M94.1 127.7l-2 2M94.1 132.7l-2 2"/>
<path d="M94.1 135.3l-2 2M101.7 137.8l-2 2M101.7 135.3l-2 2M101.7 132.7l-2 2M101.7 130.2l-2 2M101.7 127.7l-2 2M101.7 125.1l-2 2.1M101.7 122.6l-2 2M101.7 120l-2 2.1M102.9 121.1h2M102.9 123.6h2M103.9 120v2.1"/>
<path d="M103.9 122.6v2M111.8 133l-2 2M111.8 137.5l-2 2.1M118.3 133l-2.1 2M118.3 137.5l-2.1 2.1M122.7 123.8l-2.1 2.1M124.5 133l-2.1 2M124.5 137.5l-2.1 2.1M130.3 123.8l-2.1 2.1M131 133l-2.1 2M131 137.5l-2.1 2.1M137.2 133l-2.1 2"/>
<path d="M137.2 137.5l-2.1 2.1M139.1 125.1l-2 2.1M141.7 125.1l-2 2.1M143.7 133l-2.1 2M143.7 137.5l-2.1 2.1M144.2 125.1l-2 2.1M57 140l-2.1 2.1M150.3 140l-2.1 2.1"/>
<circle cx="55" cy="109.6" r=".99"/>
<circle cx="55" cy="114.7" r=".99"/>
<circle cx="55" cy="107.1" r=".99"/>
<circle cx="55" cy="112.2" r=".99"/>
<circle cx="55.9" cy="101.3" r=".99"/>
<circle cx="66.4" cy="112.8" r=".99"/>
<circle cx="69" cy="103.3" r=".99"/>
<circle cx="74" cy="112.8" r=".99"/>
<circle cx="76.6" cy="103.3" r=".99"/>
<circle cx="79.4" cy="111.2" r=".99"/>
<circle cx="79.4" cy="114.1" r=".99"/>
<circle cx="79.4" cy="117.2" r=".99"/>
<circle cx="82" cy="114.1" r=".99"/>
<circle cx="82" cy="111.2" r=".99"/>
<circle cx="87.4" cy="118.8" r=".99"/>
<circle cx="93.1" cy="113.4" r=".99"/>
<circle cx="93.1" cy="108.4" r=".99"/>
<circle cx="93.1" cy="118.5" r=".99"/>
<circle cx="93.1" cy="105.8" r=".99"/>
<circle cx="93.1" cy="110.9" r=".99"/>
<circle cx="93.1" cy="116" r=".99"/>
<circle cx="94.3" cy="102" r=".99"/>
<circle cx="96.9" cy="102" r=".99"/>
<circle cx="99.4" cy="102" r=".99"/>
<circle cx="100.7" cy="116" r=".99"/>
<circle cx="100.7" cy="108.4" r=".99"/>
<circle cx="100.7" cy="113.4" r=".99"/>
<circle cx="100.7" cy="105.8" r=".99"/>
<circle cx="100.7" cy="118.5" r=".99"/>
<circle cx="100.7" cy="110.9" r=".99"/>
<circle cx="102" cy="102" r=".99"/>
<circle cx="104.5" cy="102" r=".99"/>
<circle cx="109.3" cy="110.2" r=".99"/>
<circle cx="111.2" cy="119.1" r=".99"/>
<circle cx="114" cy="113.2" r=".99"/>
<circle cx="114" cy="107.2" r=".99"/>
<circle cx="114.3" cy="119.1" r=".99"/>
<circle cx="119.4" cy="117" r=".99"/>
<circle cx="119.4" cy="115" r=".99"/>
<circle cx="120.4" cy="119.8" r=".99"/>
<circle cx="120.7" cy="112.2" r=".99"/>
<circle cx="120.7" cy="104.5" r=".99"/>
<circle cx="133.1" cy="119.8" r=".99"/>
<circle cx="139.4" cy="103.3" r=".99"/>
<circle cx="139.4" cy="118.8" r=".99"/>
<circle cx="139.4" cy="113.8" r=".99"/>
<circle cx="139.4" cy="108.3" r=".99"/>
<circle cx="149.2" cy="101.3" r=".99"/>
<circle cx="150.2" cy="112.2" r=".99"/>
<circle cx="150.2" cy="109.6" r=".99"/>
<circle cx="150.2" cy="107.1" r=".99"/>
<circle cx="150.2" cy="114.7" r=".99"/>
<circle cx="61.3" cy="134" r=".99"/>
<circle cx="61.3" cy="120.8" r=".99"/>
<circle cx="79.4" cy="124.9" r=".99"/>
<circle cx="84.8" cy="138.2" r=".99"/>
<circle cx="84.8" cy="135.6" r=".99"/>
<circle cx="87.4" cy="131.8" r=".99"/>
<circle cx="87.4" cy="126.5" r=".99"/>
<circle cx="87.4" cy="139.4" r=".99"/>
<circle cx="90.2" cy="131.8" r=".99"/>
<circle cx="90.2" cy="139.4" r=".99"/>
<circle cx="93.1" cy="128.7" r=".99"/>
<circle cx="93.1" cy="123.6" r=".99"/>
<circle cx="93.1" cy="133.7" r=".99"/>
<circle cx="93.1" cy="131.2" r=".99"/>
<circle cx="93.1" cy="138.8" r=".99"/>
<circle cx="93.1" cy="126.1" r=".99"/>
<circle cx="93.1" cy="136.3" r=".99"/>
<circle cx="93.1" cy="121.1" r=".99"/>
<circle cx="100.7" cy="128.7" r=".99"/>
<circle cx="100.7" cy="133.7" r=".99"/>
<circle cx="100.7" cy="123.6" r=".99"/>
<circle cx="100.7" cy="121.1" r=".99"/>
<circle cx="100.7" cy="136.3" r=".99"/>
<circle cx="100.7" cy="138.8" r=".99"/>
<circle cx="100.7" cy="131.2" r=".99"/>
<circle cx="100.7" cy="126.1" r=".99"/>
<circle cx="103.9" cy="123.6" r=".99"/>
<circle cx="103.9" cy="121.1" r=".99"/>
<circle cx="110.8" cy="134" r=".99"/>
<circle cx="110.8" cy="138.5" r=".99"/>
<circle cx="117.3" cy="134" r=".99"/>
<circle cx="117.3" cy="138.5" r=".99"/>
<circle cx="121.6" cy="124.9" r=".99"/>
<circle cx="123.5" cy="138.5" r=".99"/>
<circle cx="123.5" cy="134" r=".99"/>
<circle cx="129.3" cy="124.9" r=".99"/>
<circle cx="130" cy="134" r=".99"/>
<circle cx="130" cy="138.5" r=".99"/>
<circle cx="136.2" cy="134" r=".99"/>
<circle cx="136.2" cy="138.5" r=".99"/>
<circle cx="138.2" cy="126.1" r=".99"/>
<circle cx="140.7" cy="126.1" r=".99"/>
<circle cx="142.7" cy="138.5" r=".99"/>
<circle cx="142.7" cy="134" r=".99"/>
<circle cx="143.2" cy="126.1" r=".99"/>
<circle cx="55.9" cy="141" r=".99"/>
<circle cx="149.2" cy="141" r=".99"/>
</g>
<g fill="#000080" stroke="#000080" stroke-width=".18">
<path d="M54.3 85.5a2.88 2.88 0 0 1 4.7 .1 2.88 2.88 0 0 1-1.5 4.4 2.88 2.88 0 0 1-3.8-2.7h2.5a.35 .35 0 0 1 .5-.4 .35 .35 0 0 1 .1 .6 .35 .35 0 0 1-.6-.1l-2.5-.1 .1-.6z" fill-rule="evenodd"/>
<path d="M54.3 45.8a2.89 2.89 0 0 1 4.7 .2 2.89 2.89 0 0 1-1.5 4.4 2.89 2.89 0 0 1-3.8-2.8h2.5a.35 .35 0 0 1 .5-.3 .35 .35 0 0 1 .1 .5 .35 .35 0 0 1-.6-.1l-2.5-.1 .1-.6z" fill-rule="evenodd"/>
<path d="M147.6 45.8a2.88 2.88 0 0 1 4.7 .2 2.88 2.88 0 0 1-1.6 4.4 2.88 2.88 0 0 1-3.7-2.8h2.5a.35 .35 0 0 1 .6-.2 .35 .35 0 0 1 0 .6 .35 .35 0 0 1-.6-.3l-2.5-.1 .3-1.2z" fill-rule="evenodd"/>
<path d="M148.1 85a2.89 2.89 0 0 1 4.4 1 2.89 2.89 0 0 1-2 4.1 2.89 2.89 0 0 1-3.5-2.8h2.5a.35 .35 0 0 1 .6-.2 .35 .35 0 0 1 0 .6 .35 .35 0 0 1-.6-.3l-2.5-.1a2.87 2.87 0 0 1 1.1-2.3z" fill-rule="evenodd"/>
</g>
<g fill="none" stroke="#000080" stroke-width=".83">
<path d="M55.6 55.9h3.8l19.1 19h15.2M55.6 58.4h4.5l17.8 17.8h14.6l1.2 1.3M61.3 53.4l6.7 6.6v2.6l11.1 11.1h7.9l1-1M69.6 49.5l-3.8 3.9h-10.2M77.2 49.5h3.6l2.6 2.6h10.3M84.4 49.5h6.1l3.2-3.1h7l4 4v7.8l7.2 7.2-4.5 4.5h-6.1M95 48.3v2.2l.9 .9v28.4l5.4 5.3M97.5 48.3v30.4l3.8 3.8M100.1 48.3v2.2l-1 1v26.3l2.2 2.2M105.1 48.3h4.4l5.2 5.1h1l1.8 1.9v6.7l1.3 1.3M121.3 50.8l-1.9 1.6v8.2l.7 .6M140 59.7v.4"/>
<path d="M140 49.6l2.6 2.5v5.4l-2.6 2.6M150.8 55.9l-6.1 6.5v2.9l-3.4 3.3v3.8M55.6 61h5.1l19.1 19h13.9M62 67.1l-3.8 3.8v5.6l3.8 3.8M80.1 71.1l.6-.6h9.2l1.9 1.9h1.9M119.7 75.9h-3.9l-4.4 4.4M119.7 75.9l4.4 4.4M119.7 75.9h12.7l4.4 4.4M119.8 63.3h.3M120.1 63.3h-3l-2.2 2.1v5.7l4.8 4.8M140 60.1l-3.1 3.1-16.8 .1M140 74.9l-.9 1h-6.7"/>
<path d="M140 65.1l-2.2 2.2h-2.8l-1.3 1.3h-6.3l-2.6 2.5h-2.5M150.8 61l-3.6 3.3v8.6l-2.1 2h-5.1l-1.2-1.2v-1.3"/>
</g>
<g fill="none" stroke="#000080" stroke-width=".42">
<path d="M54.2 58.7h.1M54.2 58.4h.1M54.2 56.1h.1M54.2 55.7h.1M54.2 53.8h.1M54.2 53.5h.1M54.2 53.1h.1M54.2 59.1h.2M54.2 58h.2M54.2 57.6h.4M54.2 56.5h.2M54.2 55.3h.2"/>
<path d="M54.2 54.2h.3M54.2 52.7h.2M54.2 49.7h.1M54.2 59.5h.6M54.2 56.9h.5M54.2 55h.5M54.2 52.4h.5M54.2 50.1h.6M54.2 59.8h.7M54.2 57.2h.9M54.2 54.6h.8M54.2 52h1.2"/>
<path d="M54.2 50.5h1.3M54.2 50.9h14.9M54.2 51.2h27.1M54.2 51.6h27.5M54.7 52.3l.9-.3 .1 1.3v-1.3a1.4 1.4 0 0 1 1.3 1.3h-1.3v.1h1.3a1.45 1.45 0 0 1-.8 1.3l.5 .4h2.9l.3 .1 18.9 18.9h14a1.25 1.25 0 0 1 2.1 .4 1.25 1.25 0 0 1-1.3 1.7 1.27 1.27 0 0 1 1.4 1.1 1.27 1.27 0 0 1-1.2 1.4 1.27 1.27 0 0 1-1.3-1.3l-.4-.3h-.4a1.32 1.32 0 0 1 0 2.1h1.1a1.25 1.25 0 0 1 1.8-.1 1.25 1.25 0 0 1 0 1.8 1.25 1.25 0 0 1-1.8-.1h-6.8a1.24 1.24 0 0 1 .4 1.9 1.24 1.24 0 0 1-1.9 0 1.24 1.24 0 0 1 .4-1.9h-5.3l-.3-.1-18.9-18.9h-3.7a1.35 1.35 0 0 1-2.2 0 1.35 1.35 0 0 1 .7-2.1 1.33 1.33 0 0 1-1-1.3 1.33 1.33 0 0 1 1-1.2 1.34 1.34 0 0 1-.9-1.3 1.34 1.34 0 0 1 .8-1.2 1.39 1.39 0 0 1-.9-1.3h1.4v-.1h-1.4l.1-.5zM55.6 53.1h.1M55.6 52.7h.1M55.6 52.4h.1M55.6 52h.1M55.8 52h26.3M56.3 54.6h36.2M56.6 52.4h25.9"/>
<path d="M56.6 55h35.9M56.7 54.2h35.8M56.9 52.7h26M56.9 53.8h35.8M57 53.1h36M57 53.5h36.2M57.7 50.5h10.8M58.2 50.3a3.1 3.1 0 0 1-4-.6v35.6l.8-.7 1.1-.3h1l1 .3M58.4 50.1h9.9M58.4 45.3h89.6M58.8 49.7h9.4M58.9 45.6h34.5"/>
<path d="M59 49.7l-.9 .6M59.1 49.4h9.1M59.1 46h33.9M59.3 49h9M59.4 46.4h33.2M59.5 48.7l-.5 .9M59.5 48.6h9.1M59.5 46.7h32.7M59.6 48.2h9.5M59.6 47.1h32.2M59.6 47.9h31.5M59.7 47.5h31.8"/>
<path d="M59.7 47.6l-.2-1-.5-.9-.6-.4h89.6a2.96 2.96 0 0 0-1.2 2.4M59.7 47.6l-.2 1.1M60 55.3h32.7M60.4 55.7h32.7M60.8 56.1h32.3M61.2 56.5h18.1M61.5 56.9h17.5M61.9 57.2h16.9M62.3 57.6h4.1M62.7 58h3.3M63 58.4h2.6M63.4 58.7h2.1"/>
<path d="M63.8 59.1h3.2M64.2 59.5h1.3M64.5 59.8h1.1M65.5 58.4l.9-.8h.6v1.4h.1v-1.4h.6l.9 .8v.6l-1.5 .1h1.5v.6l-.9 .9h-.6v-1.5h-.1v1.5h-.6l-.9-.9v-.6l1.5-.1h-1.5zM67 59.8h.1M67 59.5h.1M67 58.7h.1M67 58.4h.1M67 58h.1M67 57.6h.1M67.1 59.1h6.1M67.8 57.6h6.2"/>
<path d="M68.1 58h5.6M68.5 59.8h4.8M68.5 58.4h4.8M68.5 48.6l.6-.3 .5-.1v1.3v-1.3a1.4 1.4 0 0 1 1.4 1.3h-1.4l1.4 .1a1.4 1.4 0 0 1-1.4 1.3v-1.3v1.3a1.36 1.36 0 0 1-1.4-1.3h1.4l-1.4-.1zM68.6 59.5h4.6M68.6 58.7h4.6M69.6 50.9h.1M69.6 50.5h.1M69.6 50.1h.1M69.6 49.7h.1M69.6 49.4h.1M69.6 49h.1"/>
<path d="M69.6 48.6h.1M69.6 48.2h.1M70 48.2h6.9M70.1 50.9h6.7M70.6 48.6h5.6M70.6 50.5h5.6M70.9 50.1h5.1M70.9 49h5.1M71 49.7h4.9M71 49.4h4.9M75.3 57.6h3.5M75.7 58h3.2"/>
<path d="M76 59.8h2.9M76 58.4h3.1M76.1 48.8a1.36 1.36 0 0 1 2.2-.1h1.8a1.09 1.09 0 0 1 1.2-.2 1.09 1.09 0 0 1 .6 1l1.8 1.8h9.1a1.19 1.19 0 0 1 1.5-.3l-.1-.3v-1.3a1.35 1.35 0 0 1 0-2.2l-3.2 3-.3 .2h-5.6a1.12 1.12 0 0 1-1.5-.1 1.12 1.12 0 0 1 0-1.5 1.12 1.12 0 0 1 1.5-.1h5.1l3.1-3 .3-.1h7.3l.3 .1 1.2 1.2a1.32 1.32 0 0 1 1.5 .9 1.32 1.32 0 0 1 1.2-.9v1.3l.1-1.3a1.36 1.36 0 0 1 1.3 1.3h-1.3v.1h1.3a1.4 1.4 0 0 1-1.3 1.4l-.1-1.4v1.3l.4 .6v7.7l6.2 6.2h1.2l.3 .3v2.1l-.3 .2h-1.2l-3.8 3.8-.3 .2h-2.2a1.19 1.19 0 0 1-1.8 0h-1.3a1.26 1.26 0 0 1-1.8 .1 1.26 1.26 0 0 1 0-1.9 1.26 1.26 0 0 1 1.8 .1h1.3a1.23 1.23 0 0 1 1.8 0h1.7l3.5-3.4v-.3l-6.6-6.6-.1-.3v-7.7l-1.1-1.1a1.31 1.31 0 0 1-1.5-.9l-.4 .7v1.3l-.2 .3a1.26 1.26 0 0 1 1.9 .9 1.26 1.26 0 0 1-1.5 1.4 1.26 1.26 0 0 1-.8-1.8l-.4 .3v25.7l.2 .1a1.25 1.25 0 0 1 1.2-1.4 1.25 1.25 0 0 1 1.3 1.3 1.25 1.25 0 0 1-1.4 1.2 1.28 1.28 0 0 1 1.4 1.3 1.28 1.28 0 0 1-1.4 1.3 1.28 1.28 0 0 1 1.4 1.3 1.28 1.28 0 0 1-1.6 1.2h1.3l.3 .3v2l-.3 .2h-2l-.2-.2v-1l-4.7-4.6-.3-.6v-28.2l-.3-.2a1.25 1.25 0 0 1-.3 1.6 1.25 1.25 0 0 1-1.7-.2h-9.6l-.5-.3-1.9-1.9-.7-.3h-1.8a1.37 1.37 0 0 1-1.9 .3 1.37 1.37 0 0 1-.3-1.9zM76.2 59.5h2.9M76.2 59.1h3.6M76.2 58.7h3.5M77.5 48.2h13.2M77.6 50.9h3.4M78.2 48.6h2M78.2 50.5h2M79.1 56.7l.5-.4 .5-.1v1.3v-1.3a1.25 1.25 0 0 1 1.2 1.3h-1.2h1.2a1.25 1.25 0 0 1-1.2 1.3v-1.3v1.3a1.29 1.29 0 0 1-1.3-1.3h1.3h-1.3zM79.1 59.5l.5-.3 .5-.1v1.2v-1.2a1.3 1.3 0 0 1 1.2 1.2h-1.2l1.2 .1a1.29 1.29 0 0 1-1.2 1.2v-1.2v1.2a1.29 1.29 0 0 1-1.3-1.2h1.3l-1.3-.1z"/>
<path d="M80.1 59.8h.1M80.1 59.5h.1M80.1 59.1h.1M80.1 58.7h.1M80.1 58.4h.1M80.1 58h.1M80.1 57.6h.1M80.1 57.2h.1M80.1 56.9h.1M80.1 56.5h.1M80.4 59.1h12.2M80.4 58.7h12.5"/>
<path d="M80.9 56.5h1M81 59.5h.8M81 58.4h.7M81.2 56.9h.3M81.2 59.8h.3M81.3 58h.2M81.3 57.2h.1M81.3 57.6h.1M81.4 48.6h2.4M81.8 49h1.6M81.9 49.4h1.4M82.2 49.7h1.1"/>
<path d="M82.5 50.1h.9M82.9 50.5h.8M83.3 50.9h10.2M83.3 56.5h9.4M83.5 59.5h9M83.5 58.4h9.8M83.7 51.2h9.1M83.7 56.9h8.8M83.7 59.8h8.8M83.7 58h9.1M83.8 57.2h8.7M83.8 57.6h8.7"/>
<path d="M85 48.6h5.3M85 50.5h9.2M91.1 50.1h3.1M91.5 49.7h2.7M91.9 49.4h2.3M92.3 49h1.5M92.6 48.6h1.1M93 48.2h.6M93.4 47.9h.3M93.8 47.5h.1M94 50.9h.3M94.1 58.4h1"/>
<path d="M94.2 53.5h.9M94.3 55.7h.8M94.4 56.1h.7M94.5 53.1h.6M94.5 58.7h.6M94.7 58h.4M94.7 53.8h.4M94.7 55.3h.4M94.8 56.5h.3M94.8 52.7h.3M94.8 59.1h.3M94.9 51.6h.1"/>
<path d="M94.9 57.6h.2M94.9 54.2h.2M94.9 55h.2M94.9 56.9h.2M95 59.8h.1M95 59.5h.1M95 57.2h.1M95 54.6h.1M95 52.4h.1M95 52h.1M99.9 59.8h.2M99.9 59.5h.2"/>
<path d="M99.9 59.1h.4M99.9 58h.5M99.9 57.6h.3M99.9 57.2h.2M99.9 56.9h.2M99.9 56.5h.4M99.9 55.3h.4M99.9 55h.2M99.9 54.6h.2M99.9 54.2h.2M99.9 53.8h.5M99.9 52.7h.4"/>
<path d="M99.9 52.4h.2M99.9 52h.2M99.9 58.7h.7M99.9 56.1h.8M99.9 55.7h.8M99.9 53.1h.7M99.9 58.4h1M99.9 53.5h1M100.1 51.6h.1M100.8 50.9h.3M100.9 49.4h.9M100.9 50.1h2.4"/>
<path d="M100.9 49.7h2M100.9 50.5h2.8M101 45.6h46.6M101.2 49h.2M101.5 46h45.8M101.6 50.9h2.3M101.8 58.4h2.1M101.8 53.5h2.1M101.8 46.4h45.3M101.9 55.7h2M102 56.1h1.9M102.1 53.1h1.8"/>
<path d="M102.1 58.7h1.9M102.2 46.7h44.8M102.2 51.2h1.7M102.3 58h1.6M102.3 53.8h1.6M102.4 55.3h1.5M102.4 56.5h1.5M102.4 52.7h1.5M102.4 59.1h2M102.5 51.6h1.4M102.5 57.6h1.4M102.5 54.2h1.4"/>
<path d="M102.5 56.9h1.4M102.5 55h1.4M102.6 57.2h1.3M102.6 54.6h1.3M102.6 52.4h1.3M102.6 52h1.3M102.6 59.5h2.2M102.6 59.8h2.5M103.3 47.1h1.1M103.7 47.5h.3M105.1 49.4h.1M105.1 49h.1"/>
<path d="M105.1 48.6h.1M105.1 47.9h.1M105.1 47.5h.1M105.1 47.1h.1M105.2 48.2h34.4M105.2 49.7h15.3M105.5 50.1h14.7M105.5 57.6h2.2M105.5 57.2h2M105.5 56.9h1.9M105.5 56.5h1.9M105.5 56.1h1.9"/>
<path d="M105.5 55.7h2M105.5 55.3h2.1M105.5 55h2.4M105.5 54.6h2.7M105.5 54.2h3.2M105.5 53.8h6.6M105.5 53.1h6.6M105.5 52.7h6.6M105.5 52.4h6.8M105.5 52h7M105.5 51.6h7.3M105.5 51.2h7.8"/>
<path d="M105.5 53.5h9M105.5 50.9h8.8M105.5 50.5h14.5M105.6 58h2.3M105.9 47.1h41M105.9 58.4h2.4M106 49.4h32.6M106.3 47.5h40.5M106.3 58.7h2.5M106.3 49h32.5M106.5 47.9h40.3M106.5 48.6h32.5"/>
<path d="M106.7 59.1h5.4M107.1 59.5h5M107.4 59.8h4.7M111.2 58.7h1M111.3 54.2h.9M111.7 58.4h.6M111.7 54.6h.6M112 58h.5M112.1 55h.4M112.3 57.6h.6M112.3 55.3h.6M112.4 57.2h1"/>
<path d="M112.4 55.7h1M112.5 56.9h6.1M112.5 56.5h6.1M112.5 56.1h6.1M112.9 51.5l.8-.5 .8-.2v2.4h.4v-2.4a2.62 2.62 0 0 1 2.4 2.4h-2.4v.5h2.4a2.62 2.62 0 0 1-2.4 2.3v-2.3h-.4v2.3a2.58 2.58 0 0 1-2.4-2.3h2.4v-.5h-2.4l.3-1zM114.5 55.7h.4M114.5 55.3h.4M114.5 55h.4M114.5 54.6h.4M114.5 54.2h.4M114.5 53.8h.4M114.5 53.1h.4"/>
<path d="M114.5 52.7h.4M114.5 52.4h.4M114.5 52h.4M114.5 51.6h.4M114.5 51.2h.4M114.5 50.9h.4M114.9 53.5h3.7M115.1 50.9h4.9M116 57.2h2.6M116 55.7h2.6M116.1 51.2h3.5M116.4 57.6h2.2"/>
<path d="M116.5 55.3h2.1M116.5 51.6h2.7M116.8 58h1.8M116.8 55h1.8M116.8 52h2M117 58.4h1.6M117 54.6h1.6M117 52.4h1.6M117.1 58.7h1.5M117.2 54.2h1.4M117.2 52.7h1.4M117.2 59.8h1.4"/>
<path d="M117.2 59.5h1.4M117.2 59.1h1.4M117.2 53.8h1.4M117.2 53.1h1.4M120.2 50.1a1.37 1.37 0 0 1 2.4 .2 1.37 1.37 0 0 1-1.6 1.9l-.7 .6v4.8a1.36 1.36 0 0 1 2-.2 1.36 1.36 0 0 1 0 2.1 1.36 1.36 0 0 1-2-.2v.8h.6l.3 .3v1.7l-.4 .2 .3 .4 .1 .5-1.1 .1h1.1a1.15 1.15 0 0 1-1.1 1.1v-1.1l-.1 1.1a1.15 1.15 0 0 1-1.1-1.1l1.1-.1h-1.1l.1-.4 .3-.5-.4-.2v-.8l-.3-.5v-8.6l.2-.3 1.2-1zM120.3 57.6h.1M120.3 59.5h.2M120.3 57.2h.5M120.3 59.8h18.3M120.3 55.7h18.4M120.3 55.3h18.4M120.3 55h18.4"/>
<path d="M120.3 54.6h18.4M120.3 54.2h18.4M120.3 53.8h18.4M120.3 53.5h18.4M120.3 56.9h28.5M120.3 56.5h28.9M120.3 56.1h29.2M120.3 53.1h29.2M120.4 52.7h29.3M120.8 52.4h29.2M121.9 57.2h26.6M122.1 52h30.1"/>
<path d="M122.1 49.7h16.5M122.2 59.5h16.6M122.4 57.6h25.8M122.5 51.6h29.7M122.5 50.1h16.2M122.5 59.1h16.5M122.6 58h25.2M122.6 51.2h29.6M122.6 50.5h16.3M122.7 58.7h16.9M122.7 50.9h16.7M122.7 58.4h24.8"/>
<path d="M138.7 53.5l.2-.3h2.3l.2 .3v2.2l-.2 .3h-2.3l-.2-.3zM139 59.1l.5-.3 .5-.1 .1 1.3v-1.3a1.43 1.43 0 0 1 1.4 1.3h-1.4l1.4 .1a1.4 1.4 0 0 1-1.4 1.4v-1.4l-.1 1.4a1.43 1.43 0 0 1-1.4-1.4h1.4l-1.4-.1zM139 48.7l.5-.4 .5-.1 .1 1.4v-1.4a1.43 1.43 0 0 1 1.4 1.4h-1.4h1.4a1.4 1.4 0 0 1-1.4 1.4v-1.4l-.1 1.4a1.39 1.39 0 0 1-1.4-1.4h1.4h-1.4zM140 59.8h.1M140 59.5h.1M140 59.1h.1M140 58.7h.1M140 50.9h.1M140 50.5h.1M140 50.1h.1M140 49.7h.1M140 49.4h.1"/>
<path d="M140 49h.1M140 48.6h.1M140 48.2h.1M140.5 48.2h6.4M140.5 58.7h6.6M140.7 50.9h11.5M141.1 48.6h5.9M141.1 59.1h5.7M141.2 50.5h7.6M141.3 59.5h5.1M141.3 49h5.9M141.4 50.1h6.7"/>
<path d="M141.4 55.7h8.1M141.4 55.3h8.2M141.4 53.8h8.2M141.4 53.5h8.1M141.4 55h8.5M141.4 54.6h8.9M141.4 54.2h8.4M141.5 59.8h4.5M141.5 49.4h5.9M141.5 49.7h6.1M146.8 47.6l.2 1.1M147 48.7l.5 1"/>
<path d="M147.5 49.6h.1M147.5 49.6a3.1 3.1 0 0 0 4 .7M148.3 59.8h1.7M148.6 59.5h1.4M149 59.1h.7M149.3 58.7h.2M149.7 52.6a1.37 1.37 0 0 1 2.2-.1 1.37 1.37 0 0 1-.6 2.1 1.34 1.34 0 0 1 .9 1.3 1.34 1.34 0 0 1-.9 1.3 1.34 1.34 0 0 1 .9 1.2 1.34 1.34 0 0 1-.8 1.3 1.32 1.32 0 0 1 .8 1.2h-1.3l1.3 .1a1.36 1.36 0 0 1-1.3 1.4v-1.4h-.1v1.4a1.4 1.4 0 0 1-1.4-1.4h1.4l-1.4-.1a1.37 1.37 0 0 1 .9-1.2 1.19 1.19 0 0 1-.8-1.2l-4 4.2v2.7l-.2 .3-3.2 3.2v1.9l.4 .6v2a1.2 1.2 0 0 1-1.2 1 1.2 1.2 0 0 1-1.1-1v-2l.3-.6v-2.4l.1-.3 3.3-3.2v-2.7l.1-.2 5.5-5.8a1.28 1.28 0 0 1 .9-1.6 1.33 1.33 0 0 1-.7-2zM151 50.5h1.2M151.4 54.6h.8M151.4 50.3l.8-.6v35.6l-.8-.7-1-.3h-1l-1.1 .3-.8 .7M151.4 57.2h.8M151.7 59.8h.5"/>
<path d="M151.7 50.1h.5M151.7 59.5h.5M151.8 52.4h.4M151.8 56.9h.4M151.8 55h.4M151.9 54.2h.3M151.9 57.6h.3M152 59.1h.2M152 52.7h.2M152.1 56.5h.1M152.1 55.3h.1M152.1 58h.1"/>
<path d="M152.1 53.8h.1M152.2 49.7h.1M152.2 58.7h.1M152.2 58.4h.1M152.2 56.1h.1M152.2 55.7h.1M152.2 53.5h.1M152.2 53.1h.1M54.2 61.3h.1M54.2 61h.1M54.2 61.7h.3M54.2 60.6h.1"/>
<path d="M54.2 60.2h.3M54.2 62.1h.6M54.2 76.7h3.2M54.2 76.3h3.2M54.2 75.9h3.2M54.2 75.6h3.2M54.2 75.2h3.2M54.2 74.8h3.2M54.2 74.4h3.2M54.2 74.1h3.2M54.2 73.7h3.2M54.2 73.3h3.2"/>
<path d="M54.2 72.9h3.2M54.2 72.6h3.2M54.2 72.2h3.2M54.2 71.8h3.2M54.2 71.5h3.2M54.2 71.1h3.2M54.2 70.7h3.2M54.2 77.1h3.4M54.2 70.3h3.4M54.2 77.4h3.8M54.2 70h3.7M54.2 77.8h4.2"/>
<path d="M54.2 69.6h4.1M54.2 78.2h4.5M54.2 69.2h4.5M54.2 68.8h4.9M54.2 78.6h4.9M54.2 78.9h5.3M54.2 68.5h5.2M54.2 79.3h5.7M54.2 68.1h5.6M54.2 79.7h6M54.2 67.7h6M54.2 67.3h6"/>
<path d="M54.2 66.9h6M54.2 66.6h6M54.2 66.2h6.2M54.2 65.8h6.5M54.2 65.5h7M54.2 62.5h6.9M54.2 62.8h7.2M54.2 63.2h7.6M54.2 63.6h8M54.2 64h8.4M54.2 64.3h8.7M54.2 64.7h9.1"/>
<path d="M54.2 65.1h9.5M56.4 62.1h4.3M59 71.5h11M59 71.8h11.4M59 72.2h11.8M59 72.6h12.2M59 72.9h12.5M59 73.3h12.9M59 73.7h13.3M59 74.1h13.7M59 74.4h14M59 74.8h14.4"/>
<path d="M59 75.2h14.8M59 75.6h15.2M59 75.9h15.5M59.1 71.1h10.6M59.2 76.3h15.7M59.5 70.7h9.8M59.5 76.7h15.8M59.9 70.3h9M59.9 77.1h15.8M60.2 70h8.3M60.3 77.4h15.7M60.5 66.1a1.82 1.82 0 0 1 2.3-.7 1.82 1.82 0 0 1 .9 2.4 1.82 1.82 0 0 1-2.3 1l-2.4 2.4v4.9l2.4 2.5a1.81 1.81 0 0 1 2.4 1.5 1.81 1.81 0 0 1-2 2 1.81 1.81 0 0 1-1.5-2.4l-2.8-2.8-.1-.3v-5.9l.1-.3 2.8-2.8-.1-.9z"/>
<path d="M60.6 69.6h7.6M60.7 77.8h15.7M61 69.2h6.8M61.1 78.2h15.7M61.4 68.8h.1M62.4 68.8h5M62.5 78.6h14.7M62.8 65.5h1.2M63.1 68.5h3.9M63.2 78.9h14.3M63.3 65.8h1.1M63.5 68.1h3.2"/>
<path d="M63.5 79.3h14.4M63.6 66.2h1.2M63.7 67.7h2.6M63.7 79.7h14.6M63.7 66.6h1.5M63.8 66.9h1.7M63.8 67.3h2.1M64.9 60.2h1.1M65.3 60.6h1.1M65.7 61h13.3M66 61.3h13.3M66.4 61.7h26.2"/>
<path d="M66.8 62.1h25.7M67 60.6h.1M67 60.2h.1M67.1 62.5h12.1M67.5 62.8h11.4M67.7 60.6h11.1M67.9 63.2h10.8M68.1 60.2h5.6M68.3 63.6h10.4M68.7 64h10.1M69 64.3h10M69.4 64.7h10"/>
<path d="M69.8 65.1h16.9M70.2 65.5h16.5M70.5 65.8h16.4M70.9 66.2h16.3M71.3 66.6h21.4M71.7 66.9h20.8M72 67.3h20.5M72.4 67.7h20.1M72.8 68.1h19.9M73.1 68.5h20.1M73.5 68.8h19.4M73.9 69.2h18.7"/>
<path d="M74.3 69.6h18.1M74.6 70h4.8M75 70.3h4M75.4 70.7h3.4M75.6 60.2h3.2M75.8 71.1h2.9M76.1 71.5h2.6M76.5 71.8h2.4M76.9 72.2h2.3M77.3 72.6h9.3M77.6 72.9h9M78 73.3h8.7"/>
<path d="M78.4 73.7h8.6M78.8 74.1h8.9M78.9 70.4l.4-.4 .5-.2 .7-.1h9.6l.3 .1 1.7 1.8h.7a1.25 1.25 0 0 1 1.8-.1 1.25 1.25 0 0 1 0 1.8 1.25 1.25 0 0 1-1.8-.1h-1.1l-.3-.1-1.8-1.8h-8.2a1.36 1.36 0 0 1-1.8 1.1 1.36 1.36 0 0 1-.7-2zM80.1 61.3h.1M80.1 61h.1M80.1 60.6h.1M80.1 60.2h.1M80.7 64.7h6M80.9 61.3h1M80.9 72.2h5.8M80.9 62.5h11.6M81.2 64.3h5.7"/>
<path d="M81.2 61h.3M81.2 71.8h5.7M81.2 62.8h11.4M81.3 60.6h.1M81.3 60.2h.1M81.3 64h5.9M81.4 71.5h6M81.4 63.2h11.5M81.4 63.6h12M83.4 61.3h9.5M83.7 61h11.4M83.8 60.2h8.8"/>
<path d="M83.8 60.6h9M87.1 71.6l.4-.2 .5-.1v1.4v-1.4a1.36 1.36 0 0 1 1.4 1.4h-1.4h1.4a1.36 1.36 0 0 1-1.4 1.4v-1.4v1.4a1.4 1.4 0 0 1-1.4-1.4h1.4h-1.4l.1-.5zM88 74.1h.1M88 73.7h.1M88 73.3h.1M88 72.9h.1M88 72.6h.1M88 72.2h.1M88 71.8h.1M88 71.5h.1M88.4 74.1h4.4M88.6 71.5h1.1"/>
<path d="M88.8 64h4M88.8 66.2h4.4M89 73.7h4.5M89.1 71.8h1M89.1 64.3h3.4M89.2 65.8h3.8M89.3 73.3h3.6M89.3 72.2h1.2M89.3 64.7h3.2M89.3 65.5h3.4M89.4 65.1h3.1M89.4 72.9h1.8"/>
<path d="M89.4 72.6h1.4M90.5 70h1.9M90.9 70.3h1.6M91.3 70.7h1.4M91.6 71.1h1.7M91.7 77.1h.5M91.9 78.9h1.2M92 71.5h.9M92 77.4h.5M92.1 78.6h1M92.2 77.8h.3M92.2 78.2h.5"/>
<path d="M92.9 68.9l.7-.3v1.2h.2v-1.2a1.26 1.26 0 0 1 1.2 1.2h-1.2v.1h1.2a1.26 1.26 0 0 1-1.2 1.3v-1.3h-.2v1.3a1.3 1.3 0 0 1-1.2-1.3h1.2v-.1h-1.2l.1-.4zM93.6 71.1h.2M93.6 70.7h.2M93.6 70.3h.2M93.6 70h.2M93.6 69.6h.2M93.6 69.2h.2M93.6 68.8h.2M94 73.7h1.1M94.1 63.6h1M94.2 76.3h.9M94.2 71.1h.9"/>
<path d="M94.2 68.5h.9M94.3 66.2h.8M94.3 78.6h.8M94.4 78.9h.7M94.4 65.8h.7M94.5 75.9h.6M94.5 68.8h.6M94.5 71.5h.6M94.5 63.2h.6M94.6 73.3h.5M94.6 61.3h.5M94.6 74.1h.5"/>
<path d="M94.6 60.6h.5M94.6 64h.5M94.7 76.7h.4M94.7 70.7h.4M94.7 68.1h.4M94.7 66.6h.4M94.8 79.3h.3M94.8 78.2h.3M94.8 65.5h.3M94.8 75.6h.3M94.8 62.8h.3M94.8 72.9h.3"/>
<path d="M94.8 71.8h.3M94.8 69.2h.3M94.9 74.4h.2M94.9 61.7h.2M94.9 60.2h.2M94.9 64.3h.2M94.9 77.1h.2M94.9 67.7h.2M94.9 79.7h.2M94.9 77.8h.2M94.9 66.9h.2M94.9 70.3h.2"/>
<path d="M94.9 65.1h.2M95 77.4h.1M95 75.2h.1M95 74.8h.1M95 72.6h.1M95 72.2h.1M95 67.3h.1M95 64.7h.1M95 62.5h.1M95 62.1h.1M95 69.6h.1M95 70h.1"/>
<path d="M99.9 77.4h.2M99.9 77.1h.3M99.9 76.7h.5M99.9 75.6h.4M99.9 75.2h.2M99.9 74.8h.2M99.9 74.4h.3M99.9 74.1h.5M99.9 73.3h.6M99.9 72.9h.3M99.9 72.6h.2M99.9 72.2h.2"/>
<path d="M99.9 71.8h.3M99.9 70.7h.5M99.9 70.3h.3M99.9 70h.2M99.9 69.6h.2M99.9 69.2h.4M99.9 68.1h.4M99.9 67.7h.2M99.9 66.9h.2M99.9 66.6h.4M99.9 65.5h.4M99.9 65.1h.2"/>
<path d="M99.9 64.7h.2M99.9 64.3h.3M99.9 64h.5M99.9 62.8h.3M99.9 62.5h.2M99.9 62.1h.2M99.9 61.7h.3M99.9 61.3h.6M99.9 60.6h.6M99.9 60.2h.3M99.9 75.9h.7M99.9 71.5h.6"/>
<path d="M99.9 68.8h.7M99.9 68.5h.8M99.9 66.2h.8M99.9 65.8h.7M99.9 63.2h.6M99.9 76.3h1M99.9 73.7h1.2M99.9 71.1h1.1M99.9 67.3h1.4M99.9 63.6h1.1M99.9 61h6.4M100.5 66.3l.8-.3v1.2h.1v-1.2a1.26 1.26 0 0 1 1.2 1.2h-1.2v.2h1.2a1.26 1.26 0 0 1-1.2 1.2v-1.2h-.1v1.2a1.3 1.3 0 0 1-1.3-1.2h1.3v-.2h-1.3l.1-.4z"/>
<path d="M101.3 68.5h.1M101.3 68.1h.1M101.3 67.7h.1M101.3 66.9h.1M101.3 66.6h.1M101.3 66.2h.1M101.4 67.3h7.4M101.6 73.7h36.1M101.6 71.1h2.6M101.7 63.6h7.2M101.8 76.3h50.4M102 68.5h1.9"/>
<path d="M102 78.6h50.2M102 66.2h1.9M102 78.9h9.1M102.1 68.8h1.7M102.1 65.8h8.2M102.1 75.9h50.1M102.1 63.2h6.4M102.1 71.5h19M102.2 61.3h4.4M102.2 73.3h35.4M102.2 60.6h3.7M102.2 74.1h35.8"/>
<path d="M102.3 70.7h1.3M102.3 64h7M102.3 76.7h49.9M102.4 68.1h1.1M102.4 66.6h1.1M102.4 79.3h8M102.4 78.2h49.8M102.4 65.5h8.2M102.4 75.6h49.8M102.4 62.8h5.7M102.4 71.8h18.8M102.5 61.7h4.5"/>
<path d="M102.5 72.9h35.1M102.5 60.2h3M102.5 74.4h49.7M102.5 64.3h7.1M102.5 77.1h49.7M102.5 79.7h7.7M102.5 77.8h49.7M102.6 65.1h7.8M102.6 67.7h.7M102.6 66.9h.7M102.6 62.5h5.2M102.6 62.1h4.8"/>
<path d="M102.6 64.7h7.4M102.6 72.2h19M102.6 72.6h35M102.6 77.4h49.6M102.6 75.2h49.6M102.6 74.8h49.6M103.5 66.5l.3-.3 .7-.2v1.3v-1.3a1.29 1.29 0 0 1 1.3 1.3h-1.3l1.3 .1a1.3 1.3 0 0 1-1.3 1.2v-1.2v1.2a1.25 1.25 0 0 1-1.3-1.2h1.3l-1.3-.1zM104.5 68.5h.1M104.5 68.1h.1M104.5 67.7h.1M104.5 66.9h.1M104.5 66.6h.1"/>
<path d="M104.5 66.2h.1M104.8 71.1h16.2M105.1 68.5h2.6M105.1 66.2h4.8M105.2 68.8h2.1M105.4 70.7h15.7M105.5 68.1h2.6M105.6 66.6h4M105.7 67.7h2.7M105.7 66.9h3.5M107.8 60.2h4.4M108.1 70.3h13.2"/>
<path d="M108.2 60.6h4.2M108.5 70h13.3M108.6 61h4M108.9 69.6h16.3M108.9 61.3h4M109.2 69.2h16.4M109.3 61.7h4.2M109.6 68.8h16.4M109.7 62.1h9.2M110 68.5h16.3M110.1 62.5h9.1M110.4 68.1h16.3"/>
<path d="M110.4 62.8h8.6M110.5 79.2l.9-.3v1.3h.1v-1.3a1.36 1.36 0 0 1 1.3 1.3h-1.3v.1h1.3a1.33 1.33 0 0 1-1.3 1.4v-1.4h-.1v1.4a1.36 1.36 0 0 1-1.4-1.4h1.4v-.1h-1.4l.1-.4zM110.7 67.7h22.7M110.8 63.2h8.1M111.1 67.3h22.7M111.2 63.6h7.7M111.4 79.7h.1M111.4 79.3h.1M111.4 78.9h.1M111.5 66.9h8.2M111.6 64h7.5M111.7 78.9h12.1"/>
<path d="M112.4 79.3h4.6M112.7 79.7h4M113.1 66.6h1.1M113.1 64.3h1M113.2 66.2h.6M113.2 65.8h.4M113.2 65.5h.4M113.2 65.1h.4M113.2 64.7h.6M113.9 64.5l.5-.3 .5-.1v1.3v-1.3a1.36 1.36 0 0 1 1.4 1.3h-1.4h1.4a1.37 1.37 0 0 1-1.4 1.4v-1.4v1.4a1.36 1.36 0 0 1-1.3-1.4h1.3h-1.3zM114.9 66.6h.1M114.9 66.2h.1"/>
<path d="M114.9 65.8h.1M114.9 65.5h.1M114.9 65.1h.1M114.9 64.7h.1M114.9 64.3h.1M115.6 66.6h3.8M115.7 64.3h3.9M115.9 61.7h3M116 66.2h3.3M116.1 64.7h22.6M116.2 65.8h3.1M116.2 65.1h3.7"/>
<path d="M116.3 65.5h3.1M116.4 61.3h2.5M116.7 61h2M117 60.6h1.6M117.1 60.2h1.5M118.8 79.3h4.3M119.1 79.7h3.8M119.4 65.4l.7-.4h1.8a1.09 1.09 0 0 1 .8 1 1.09 1.09 0 0 1-.8 1.1h-1.8a1.09 1.09 0 0 1-.7-1.7zM120 64.3h.1M120 64h.1M120 63.6h.1M120.5 64.3h18.2"/>
<path d="M120.9 62.5h23M121 64h17.7M121 60.2h17.6M121.1 62.8h22.8M121.2 60.6h17.5M121.2 61.3h18.2M121.2 61h17.7M121.2 62.1h22.7M121.2 61.7h23M121.2 63.6h22.7M121.2 70.4a1.26 1.26 0 0 1 2-.1h1.3l2.4-2.4 .3-.1h6.2l.6-.7h-1.2a1.09 1.09 0 0 1-.8-1.1 1.09 1.09 0 0 1 .8-1h1.8a1.09 1.09 0 0 1 .7 1.5h2.2l1.2-1.2v-1.4l.2-.2h2.3l.2 .2v2.3l-.2 .2h-1.4l-1.5 1.6-.3 .1h-2.7l-1.1 1.2-.3 .1h-6.2l-2.4 2.4-.3 .1h-1.8a1.27 1.27 0 0 1-1.7 .2 1.27 1.27 0 0 1-.3-1.7zM121.2 63.2h22.7"/>
<path d="M122.1 65.1h10.5M122.3 66.9h10.1M122.6 65.5h9.5M122.6 66.6h9.5M122.7 70h2.1M122.7 66.2h9.3M122.7 65.8h9.3M123 72.2h6.2M123.2 79.2l.9-.3v1.3h.1v-1.3a1.36 1.36 0 0 1 1.3 1.3h-1.3v.1h1.3a1.37 1.37 0 0 1-1.3 1.4v-1.4h-.1v1.4a1.36 1.36 0 0 1-1.4-1.4h1.4v-.1h-1.4l.1-.4zM124.1 79.7h.1M124.1 79.3h.1M124.1 78.9h.1"/>
<path d="M124.4 78.9h12.1M125.1 79.3h4.6M125.3 71.8h3.5M125.4 79.7h4M125.7 71.5h3M126 71.1h2.6M126.4 70.7h2.3M126.8 70.3h2.1M127.2 70h2.3M127.5 69.6h13M130.3 70h10.2M130.6 72.2h7"/>
<path d="M130.9 70.3h9.6M131 71.8h6.6M131.1 70.7h6.9M131.1 71.5h6.5M131.2 71.1h6.5M131.5 79.3h4.3M131.8 79.7h3.8M134.2 69.2h6.3M134.6 68.8h5.9M134.8 65.1h3.9M135 68.5h5.5M135.3 65.5h3.2"/>
<path d="M135.4 66.2h2.4M135.4 65.8h2.7M135.9 79.2l.9-.3v1.3v-1.3a1.36 1.36 0 0 1 1.4 1.3h-1.4v.1h1.4a1.37 1.37 0 0 1-1.4 1.4v-1.4v1.4a1.36 1.36 0 0 1-1.4-1.4h1.4v-.1h-1.4l.1-.4zM136.8 79.7h.1M136.8 79.3h.1M136.8 78.9h.1M137.1 78.9h15.1M137.8 79.3h4.6M138 70.7l.7-.3v1.9h.1v-1.9a1.23 1.23 0 0 1 1.2 1.1v.8h-1.2v.2h1.2v.8a1.23 1.23 0 0 1-1.2 1.1v-1.9h-.1v1.9a1.23 1.23 0 0 1-1.1-1.1v-.8h1.1v-.2h-1.1v-.9zM138.1 68.1h2.6M138.1 79.7h4M138.6 67.7h2.5"/>
<path d="M138.7 74.1h.1M138.7 73.7h.1M138.7 73.3h.1M138.7 72.9h.1M138.7 72.6h.1M138.7 72.2h.1M138.7 71.8h.1M138.7 71.5h.1M138.7 71.1h.1M138.7 70.7h.1M138.9 67.3h2.5M139.3 66.9h2.5"/>
<path d="M139.6 70.7h.9M139.7 66.6h2.5M139.9 73.7h.4M139.9 71.1h.4M140 71.5h.2M140 73.3h.2M140 72.9h.2M140 72.6h.2M140 72.2h.2M140 71.8h.2M140 61.3h.1M140 61h.1"/>
<path d="M140 60.6h.1M140 60.2h.1M140.7 61.3h3.9M141.2 61h3.8M141.4 60.6h3.9M141.4 66.2h1.2M141.4 65.8h1.5M141.4 65.5h1.9M141.4 65.1h2.3M141.4 64.7h2.5M141.4 64.3h2.5M141.4 64h2.5"/>
<path d="M141.5 60.2h4.2M142.1 70.7h1.1M142.1 70.3h10.1M142.1 70h10.1M142.1 69.6h10.1M142.1 69.2h10.1M142.2 68.8h10M142.4 71.1h.4M142.4 73.7h.4M142.5 73.3h.2M142.5 72.9h.2M142.5 72.6h.2"/>
<path d="M142.5 72.2h.2M142.5 71.8h.2M142.5 71.5h.2M142.6 68.5h9.6M142.9 71a1.19 1.19 0 0 1 1.2-.5 1.19 1.19 0 0 1 .9 .9v2a1.2 1.2 0 0 1-1.1 1 1.2 1.2 0 0 1-1.2-1v-2zM143 68.1h9.2M143.4 67.7h8.8M143.7 67.3h8.5M144.1 66.9h8.1M144.2 79.3h8M144.5 66.6h7.7M144.5 79.7h7.7"/>
<path d="M144.6 70.7h7.6M144.6 74.1h7.6M144.9 66.2h7.3M144.9 71.1h7.3M144.9 73.7h7.3M145 73.3h7.2M145 72.9h7.2M145 72.6h7.2M145 72.2h7.2M145 71.8h7.2M145 71.5h7.2M145.2 65.8h7"/>
<path d="M145.5 65.5h6.7M145.5 65.1h6.7M145.5 64.7h6.7M145.5 64.3h6.7M145.5 64h6.7M145.5 63.6h6.7M145.5 63.2h6.7M145.5 62.8h6.7M145.7 62.5h6.5M146.1 62.1h3.9M146.5 61.7h3.2M146.9 61.3h2.6"/>
<path d="M147.2 61h3.6M147.6 60.6h1.9M147.9 60.2h1.8M150.8 62.1h.1M150.8 61.7h.1M150.8 61.3h.1M150.9 61h1.3M151.7 62.1h.5M152 60.2h.2M152 61.7h.2M152.2 61.3h.1M152.2 60.6h.1"/>
<path d="M54.2 85.3h.1M54.2 84.9h.5M54.2 84.6h1.1M54.2 81.2h6.2M54.2 80.8h6.1M54.2 80.4h6M54.2 80.1h6M54.2 81.6h6.5M54.2 81.9h7.1M54.2 84.2h30M54.2 83.8h30.2M54.2 82.7h30.3"/>
<path d="M54.2 82.3h30.1M54.2 83.4h30.5M54.2 83.1h30.8M57.9 84.6h26.3M58.2 84.6l.8 .7M58.5 84.9h25.8M58.8 89.4h88.9M58.9 85.3h25.6M59 85.3l.5 1M59.1 89h88.3M59.1 85.7h26M59.3 88.7h87.9"/>
<path d="M59.4 86h27.3M59.5 86.3l.2 1-.2 1.1-.5 .9-.5 .4h89.5l-.5-.4M59.5 88.3h87.5M59.5 86.4h27.3M59.6 87.9h87.3M59.6 86.8h27.6M59.6 87.5h87.2M59.7 87.2h87.1M62.7 81.9h21.5M63.2 81.6h21.1M63.5 81.2h21M63.7 80.8h15.9"/>
<path d="M63.8 80.1h14.8M63.8 80.4h15.2M84.5 83.6l.5-.3 .4-.1 .1 1.2v-1.2a1.25 1.25 0 0 1 1.2 1.2h-1.2l1.2 .1a1.25 1.25 0 0 1-1.2 1.2v-1.2l-.1 1.2a1.3 1.3 0 0 1-1.2-1.2h1.2l-1.2-.1zM85.4 85.3h.1M85.4 85.7h.1M85.4 84.9h.1M85.4 84.6h.1M85.4 84.2h.1M85.4 83.8h.1M85.4 83.4h.1M85.9 85.7h.8M85.9 83.1h6.7"/>
<path d="M86.2 83.4h6.6M86.4 85.3h.3M86.5 82.7h6M86.5 81.2h6.8M86.6 83.8h12.2M86.6 82.3h5.9M86.6 81.6h6.3M86.7 84.9h.2M86.7 81.9h5.9M86.7 84.2h6.2M86.7 84.6h.6M88.7 84.6h1.5"/>
<path d="M88.8 86.8h1.2M89.1 84.9h.7M89.2 86.4h.5M89.3 85.3h.3M89.3 86h.2M89.4 85.7h.1M91.6 84.6h1M91.7 86.8h55.2M92 84.9h.5M92 86.4h55M92.1 85.3h.4M92.2 86h.7"/>
<path d="M92.2 85.7h.4M94.2 81.2h1.9M94.5 81.6h2M94.5 86h5.6M94.6 84.2h4.5M94.6 83.4h3.8M94.7 80.8h1.1M94.8 81.9h2.1M94.8 85.7h5.3M94.8 84.6h4.7M94.9 83.1h3.1M94.9 80.4h.5"/>
<path d="M95 80.1h.1M95 82.7h2.6M95 82.3h2.3M95 85.3h5.1M95 84.9h4.9M101.1 83.8h9.4M101.8 81.2h8.5M102.1 81.6h8.7M102.2 83.4h50M102.3 80.8h7.8M102.4 81.9h49.8M102.5 83.1h49.7"/>
<path d="M102.5 80.4h7.5M102.6 80.1h7.4M102.6 85.3h7.6M102.6 84.9h7.5M102.6 84.6h7.5M102.6 84.2h7.6M102.6 86h8.3M102.6 85.7h7.8M102.6 82.7h49.6M102.6 82.3h49.6M111.4 81.6h.1M111.4 81.2h.1"/>
<path d="M111.4 80.8h.1M111.4 80.4h.1M111.4 80.1h.1M111.9 86h5.5M112 81.6h5.4M112.3 83.8h4.7M112.5 85.7h4.4M112.5 81.2h4.4M112.6 84.2h4.1M112.7 85.3h4M112.7 80.8h4M112.8 84.9h3.8"/>
<path d="M112.8 84.6h3.8M112.8 80.1h3.8M112.8 80.4h3.8M118.4 81.6h5.1M118.4 86h5.2M118.8 83.8h4.4M118.9 81.2h4.1M119 85.7h4.1M119.1 84.2h3.8M119.2 80.8h3.6M119.2 85.3h3.7M119.3 80.4h3.4"/>
<path d="M119.3 80.1h3.4M119.3 84.9h3.5M119.3 84.6h3.5M124.1 81.6h.1M124.1 81.2h.1M124.1 80.8h.1M124.1 80.4h.1M124.1 80.1h.1M124.6 86h5.5M124.7 81.6h5.4M125 83.8h4.7M125.1 85.7h4.5"/>
<path d="M125.2 81.2h4.4M125.3 84.2h4.1M125.4 85.3h4M125.4 80.8h4M125.5 84.9h3.8M125.5 84.6h3.8M125.5 80.1h3.8M125.5 80.4h3.8M131.1 81.6h5.1M131.1 86h5.2M131.5 83.8h4.4M131.6 81.2h4.1"/>
<path d="M131.6 85.7h4.2M131.8 84.2h3.8M131.9 85.3h3.7M131.9 80.8h3.6M132 80.4h3.4M132 80.1h3.4M132 84.9h3.5M132 84.6h3.5M136.8 81.6h.1M136.8 81.2h.1M136.8 80.8h.1M136.8 80.4h.1"/>
<path d="M136.8 80.1h.1M137.3 86h5.5M137.4 81.6h5.4M137.7 83.8h4.7M137.8 85.7h4.5M137.9 81.2h4.4M138 84.2h4.1M138.1 85.3h4M138.1 80.8h4M138.2 84.9h3.7M138.2 84.6h3.7M138.2 80.1h3.7"/>
<path d="M138.2 80.4h3.7M143.8 81.6h8.4M143.8 86h3.3M144.2 83.8h8M144.3 81.2h7.9M144.3 85.7h3M144.5 84.2h7.7M144.6 85.3h3M144.6 80.8h7.6M144.7 84.9h3.3M144.7 84.6h3.9M144.7 80.4h7.5"/>
<path d="M144.7 80.1h7.5M147 86.3a3.2 3.2 0 0 0 .5 3M147.5 85.3l-.5 1M147.5 89.3h.1M151.2 84.6h1M151.8 84.9h.4M152.2 85.3h.1"/>
<circle cx="74.7" cy="59.1" r="1.61"/>
<circle cx="82.6" cy="57.5" r="1.26"/>
<circle cx="93.7" cy="54.6" r="1.28"/>
<circle cx="93.7" cy="59.7" r="1.27"/>
<circle cx="93.7" cy="57.2" r="1.27"/>
<circle cx="101.3" cy="54.6" r="1.28"/>
<circle cx="101.3" cy="57.2" r="1.27"/>
<circle cx="101.3" cy="59.7" r="1.27"/>
<circle cx="110" cy="56.4" r="2.59"/>
<circle cx="114.7" cy="59.4" r="2.59"/>
<circle cx="80.1" cy="63.5" r="1.37"/>
<circle cx="82.6" cy="60.4" r="1.26"/>
<circle cx="88" cy="65.1" r="1.37"/>
<circle cx="93.7" cy="67.3" r="1.27"/>
<circle cx="93.7" cy="64.8" r="1.27"/>
<circle cx="93.7" cy="62.2" r="1.27"/>
<circle cx="101.3" cy="72.4" r="1.27"/>
<circle cx="101.3" cy="74.9" r="1.27"/>
<circle cx="101.3" cy="62.2" r="1.27"/>
<circle cx="101.3" cy="64.8" r="1.27"/>
<circle cx="129.9" cy="71.1" r="1.28"/>
<circle cx="88" cy="85.7" r="1.37"/>
<circle cx="90.9" cy="85.7" r="1.37"/>
<circle cx="93.7" cy="82.6" r="1.27"/>
<circle cx="93.7" cy="85.1" r="1.27"/>
<circle cx="111.4" cy="84.8" r="1.38"/>
<circle cx="117.9" cy="80.3" r="1.37"/>
<circle cx="117.9" cy="84.8" r="1.37"/>
<circle cx="124.1" cy="84.8" r="1.38"/>
<circle cx="130.6" cy="80.3" r="1.38"/>
<circle cx="130.6" cy="84.8" r="1.38"/>
<circle cx="136.8" cy="84.8" r="1.38"/>
<circle cx="143.3" cy="80.3" r="1.38"/>
<circle cx="143.3" cy="84.8" r="1.38"/>
</g>
<circle cx="120.1" cy="63.3" r=".7" fill="#008000" stroke="#008000" stroke-width=".18"/>
<circle cx="120.1" cy="63.3" r=".44" fill="#fff" stroke="#000" stroke-width=".18"/>
<path d="M119.4 60.5h1.4v1.4h-1.4z" fill="#008000" stroke="#008000" stroke-width=".18"/>
<circle cx="120.1" cy="61.2" r=".44" fill="#fff" stroke="#000" stroke-width=".18"/>
<path d="M111 64.5h1.8v1.8h-1.8z" fill="#008000" stroke="#008000" stroke-width=".18"/>
<circle cx="111.9" cy="65.4" r=".44" fill="#fff" stroke="#000" stroke-width=".18"/>
<circle cx="114.9" cy="65.4" r=".89" fill="#008000" stroke="#008000" stroke-width=".18"/>
<circle cx="114.9" cy="65.4" r=".44" fill="#fff" stroke="#000" stroke-width=".18"/>
<circle cx="140" cy="60.1" r=".97" fill="#008000" stroke="#008000" stroke-width=".18"/>
<circle cx="140" cy="60.1" r=".44" fill="#fff" stroke="#000" stroke-width=".18"/>
<path d="M139.1 64.1h1.9v1.9h-1.9z" fill="#008000" stroke="#008000" stroke-width=".18"/>
<circle cx="140" cy="65.1" r=".44" fill="#fff" stroke="#000" stroke-width=".18"/>
<circle cx="140" cy="49.6" r=".97" fill="#008000" stroke="#008000" stroke-width=".18"/>
<circle cx="140" cy="49.6" r=".44" fill="#fff" stroke="#000" stroke-width=".18"/>
<path d="M139.1 53.6h1.9v2h-1.9z" fill="#008000" stroke="#008000" stroke-width=".18"/>
<circle cx="140" cy="54.6" r=".44" fill="#fff" stroke="#000" stroke-width=".18"/>
<circle cx="122.3" cy="71.1" r=".85" fill="#008000" stroke="#008000" stroke-width=".18"/>
<circle cx="122.3" cy="71.1" r=".55" fill="#fff" stroke="#000" stroke-width=".18"/>
<circle cx="129.9" cy="71.1" r=".85" fill="#008000" stroke="#008000" stroke-width=".18"/>
<circle cx="129.9" cy="71.1" r=".55" fill="#fff" stroke="#000" stroke-width=".18"/>
<path d="M133 66.1h1.4" fill="none" stroke="#008000" stroke-width="1.3"/>
<circle cx="133.7" cy="66.1" r=".4" fill="#fff" stroke="#000" stroke-width=".18"/>
<path d="M120.4 66.1h1.3" fill="none" stroke="#008000" stroke-width="1.3"/>
<circle cx="121" cy="66.1" r=".4" fill="#fff" stroke="#000" stroke-width=".18"/>
<circle cx="121.3" cy="50.8" r=".93" fill="#008000" stroke="#008000" stroke-width=".18"/>
<circle cx="121.3" cy="50.8" r=".44" fill="#fff" stroke="#000" stroke-width=".18"/>
<circle cx="121.3" cy="58.4" r=".93" fill="#008000" stroke="#008000" stroke-width=".18"/>
<circle cx="121.3" cy="58.4" r=".44" fill="#fff" stroke="#000" stroke-width=".18"/>
<circle cx="114.7" cy="59.4" r="2.16" fill="#008000" stroke="#008000" stroke-width=".18"/>
<circle cx="114.7" cy="59.4" r="1.5" fill="#fff" stroke="#000" stroke-width=".18"/>
<circle cx="114.7" cy="53.4" r="2.16" fill="#008000" stroke="#008000" stroke-width=".18"/>
<circle cx="114.7" cy="53.4" r="1.5" fill="#fff" stroke="#000" stroke-width=".18"/>
<circle cx="110" cy="56.4" r="2.16" fill="#008000" stroke="#008000" stroke-width=".18"/>
<circle cx="110" cy="56.5" r="1.5" fill="#fff" stroke="#000" stroke-width=".18"/>
<circle cx="150.8" cy="61" r=".93" fill="#008000" stroke="#008000" stroke-width=".18"/>
<circle cx="150.8" cy="61" r=".51" fill="#fff" stroke="#000" stroke-width=".18"/>
<circle cx="150.8" cy="58.4" r=".93" fill="#008000" stroke="#008000" stroke-width=".18"/>
<circle cx="150.8" cy="58.4" r=".51" fill="#fff" stroke="#000" stroke-width=".18"/>
<circle cx="150.8" cy="55.9" r=".93" fill="#008000" stroke="#008000" stroke-width=".18"/>
<circle cx="150.8" cy="55.9" r=".51" fill="#fff" stroke="#000" stroke-width=".18"/>
<circle cx="150.8" cy="53.4" r=".93" fill="#008000" stroke="#008000" stroke-width=".18"/>
<circle cx="150.8" cy="53.4" r=".51" fill="#fff" stroke="#000" stroke-width=".18"/>
<circle cx="55.6" cy="61" r=".93" fill="#008000" stroke="#008000" stroke-width=".18"/>
<circle cx="55.6" cy="61" r=".51" fill="#fff" stroke="#000" stroke-width=".18"/>
<circle cx="55.6" cy="58.4" r=".93" fill="#008000" stroke="#008000" stroke-width=".18"/>
<circle cx="55.6" cy="58.4" r=".51" fill="#fff" stroke="#000" stroke-width=".18"/>
<circle cx="55.6" cy="55.9" r=".93" fill="#008000" stroke="#008000" stroke-width=".18"/>
<circle cx="55.6" cy="55.9" r=".51" fill="#fff" stroke="#000" stroke-width=".18"/>
<circle cx="55.6" cy="53.4" r=".93" fill="#008000" stroke="#008000" stroke-width=".18"/>
<circle cx="55.6" cy="53.4" r=".51" fill="#fff" stroke="#000" stroke-width=".18"/>
<circle cx="84.4" cy="49.5" r=".7" fill="#008000" stroke="#008000" stroke-width=".18"/>
<circle cx="84.4" cy="49.5" r=".4" fill="#fff" stroke="#000" stroke-width=".18"/>
<circle cx="80.8" cy="49.5" r=".7" fill="#008000" stroke="#008000" stroke-width=".18"/>
<circle cx="80.8" cy="49.5" r=".4" fill="#fff" stroke="#000" stroke-width=".18"/>
<circle cx="69.6" cy="49.5" r=".93" fill="#008000" stroke="#008000" stroke-width=".18"/>
<circle cx="69.6" cy="49.5" r=".44" fill="#fff" stroke="#000" stroke-width=".18"/>
<circle cx="77.2" cy="49.5" r=".93" fill="#008000" stroke="#008000" stroke-width=".18"/>
<circle cx="77.2" cy="49.5" r=".44" fill="#fff" stroke="#000" stroke-width=".18"/>
<circle cx="124.1" cy="80.3" r=".93" fill="#008000" stroke="#008000" stroke-width=".18"/>
<circle cx="124.1" cy="80.3" r=".51" fill="#fff" stroke="#000" stroke-width=".18"/>
<circle cx="130.6" cy="80.3" r=".93" fill="#008000" stroke="#008000" stroke-width=".18"/>
<circle cx="130.6" cy="80.3" r=".51" fill="#fff" stroke="#000" stroke-width=".18"/>
<circle cx="124.1" cy="84.8" r=".93" fill="#008000" stroke="#008000" stroke-width=".18"/>
<circle cx="124.1" cy="84.8" r=".51" fill="#fff" stroke="#000" stroke-width=".18"/>
<circle cx="130.6" cy="84.8" r=".93" fill="#008000" stroke="#008000" stroke-width=".18"/>
<circle cx="130.6" cy="84.8" r=".51" fill="#fff" stroke="#000" stroke-width=".18"/>
<path d="M138.8 71.6v1.6" fill="none" stroke="#008000" stroke-width="1.5"/>
<circle cx="138.8" cy="72.4" r=".51" fill="#fff" stroke="#000" stroke-width=".18"/>
<path d="M141.3 71.6v1.6" fill="none" stroke="#008000" stroke-width="1.5"/>
<circle cx="141.3" cy="72.4" r=".51" fill="#fff" stroke="#000" stroke-width=".18"/>
<path d="M143.9 71.6v1.6" fill="none" stroke="#008000" stroke-width="1.5"/>
<circle cx="143.9" cy="72.4" r=".51" fill="#fff" stroke="#000" stroke-width=".18"/>
<circle cx="136.8" cy="80.3" r=".93" fill="#008000" stroke="#008000" stroke-width=".18"/>
<circle cx="136.8" cy="80.3" r=".51" fill="#fff" stroke="#000" stroke-width=".18"/>
<circle cx="143.3" cy="80.3" r=".93" fill="#008000" stroke="#008000" stroke-width=".18"/>
<circle cx="143.3" cy="80.3" r=".51" fill="#fff" stroke="#000" stroke-width=".18"/>
<circle cx="136.8" cy="84.8" r=".93" fill="#008000" stroke="#008000" stroke-width=".18"/>
<circle cx="136.8" cy="84.8" r=".51" fill="#fff" stroke="#000" stroke-width=".18"/>
<circle cx="143.3" cy="84.8" r=".93" fill="#008000" stroke="#008000" stroke-width=".18"/>
<circle cx="143.3" cy="84.8" r=".51" fill="#fff" stroke="#000" stroke-width=".18"/>
<circle cx="111.4" cy="80.3" r=".93" fill="#008000" stroke="#008000" stroke-width=".18"/>
<circle cx="111.4" cy="80.3" r=".51" fill="#fff" stroke="#000" stroke-width=".18"/>
<circle cx="117.9" cy="80.3" r=".93" fill="#008000" stroke="#008000" stroke-width=".18"/>
<circle cx="117.9" cy="80.3" r=".51" fill="#fff" stroke="#000" stroke-width=".18"/>
<circle cx="111.4" cy="84.8" r=".93" fill="#008000" stroke="#008000" stroke-width=".18"/>
<circle cx="111.4" cy="84.8" r=".51" fill="#fff" stroke="#000" stroke-width=".18"/>
<circle cx="117.9" cy="84.8" r=".93" fill="#008000" stroke="#008000" stroke-width=".18"/>
<circle cx="117.9" cy="84.8" r=".51" fill="#fff" stroke="#000" stroke-width=".18"/>
<circle cx="67.1" cy="59.1" r="1.17" fill="#008000" stroke="#008000" stroke-width=".18"/>
<circle cx="67.1" cy="59.1" r=".51" fill="#fff" stroke="#000" stroke-width=".18"/>
<circle cx="74.7" cy="59.1" r="1.17" fill="#008000" stroke="#008000" stroke-width=".18"/>
<circle cx="74.7" cy="59.1" r=".51" fill="#fff" stroke="#000" stroke-width=".18"/>
<circle cx="80.1" cy="63.5" r=".93" fill="#008000" stroke="#008000" stroke-width=".18"/>
<circle cx="80.1" cy="63.5" r=".44" fill="#fff" stroke="#000" stroke-width=".18"/>
<circle cx="80.1" cy="71.1" r=".93" fill="#008000" stroke="#008000" stroke-width=".18"/>
<circle cx="80.1" cy="71.1" r=".44" fill="#fff" stroke="#000" stroke-width=".18"/>
<path d="M100.5 84.2h1.7v1.7h-1.7z" fill="#008000" stroke="#008000" stroke-width=".18"/>
<circle cx="101.3" cy="85.1" r=".55" fill="#fff" stroke="#000" stroke-width=".18"/>
<circle cx="101.3" cy="82.5" r=".85" fill="#008000" stroke="#008000" stroke-width=".18"/>
<circle cx="101.3" cy="82.5" r=".55" fill="#fff" stroke="#000" stroke-width=".18"/>
<circle cx="101.3" cy="80" r=".85" fill="#008000" stroke="#008000" stroke-width=".18"/>
<circle cx="101.3" cy="80" r=".55" fill="#fff" stroke="#000" stroke-width=".18"/>
<circle cx="101.3" cy="77.5" r=".85" fill="#008000" stroke="#008000" stroke-width=".18"/>
<circle cx="101.3" cy="77.5" r=".55" fill="#fff" stroke="#000" stroke-width=".18"/>
<circle cx="101.3" cy="74.9" r=".85" fill="#008000" stroke="#008000" stroke-width=".18"/>
<circle cx="101.3" cy="74.9" r=".55" fill="#fff" stroke="#000" stroke-width=".18"/>
<circle cx="101.3" cy="72.4" r=".85" fill="#008000" stroke="#008000" stroke-width=".18"/>
<circle cx="101.3" cy="72.4" r=".55" fill="#fff" stroke="#000" stroke-width=".18"/>
<circle cx="101.3" cy="69.9" r=".85" fill="#008000" stroke="#008000" stroke-width=".18"/>
<circle cx="101.3" cy="69.9" r=".55" fill="#fff" stroke="#000" stroke-width=".18"/>
<circle cx="101.3" cy="67.3" r=".85" fill="#008000" stroke="#008000" stroke-width=".18"/>
<circle cx="101.3" cy="67.3" r=".55" fill="#fff" stroke="#000" stroke-width=".18"/>
<circle cx="101.3" cy="64.8" r=".85" fill="#008000" stroke="#008000" stroke-width=".18"/>
<circle cx="101.3" cy="64.8" r=".55" fill="#fff" stroke="#000" stroke-width=".18"/>
<circle cx="101.3" cy="62.2" r=".85" fill="#008000" stroke="#008000" stroke-width=".18"/>
<circle cx="101.3" cy="62.2" r=".55" fill="#fff" stroke="#000" stroke-width=".18"/>
<circle cx="101.3" cy="59.7" r=".85" fill="#008000" stroke="#008000" stroke-width=".18"/>
<circle cx="101.3" cy="59.7" r=".55" fill="#fff" stroke="#000" stroke-width=".18"/>
<circle cx="101.3" cy="57.2" r=".85" fill="#008000" stroke="#008000" stroke-width=".18"/>
<circle cx="101.3" cy="57.2" r=".55" fill="#fff" stroke="#000" stroke-width=".18"/>
<circle cx="101.3" cy="54.6" r=".85" fill="#008000" stroke="#008000" stroke-width=".18"/>
<circle cx="101.3" cy="54.6" r=".55" fill="#fff" stroke="#000" stroke-width=".18"/>
<circle cx="101.3" cy="52.1" r=".85" fill="#008000" stroke="#008000" stroke-width=".18"/>
<circle cx="101.3" cy="52.1" r=".55" fill="#fff" stroke="#000" stroke-width=".18"/>
<circle cx="93.7" cy="52.1" r=".85" fill="#008000" stroke="#008000" stroke-width=".18"/>
<circle cx="93.7" cy="52.1" r=".55" fill="#fff" stroke="#000" stroke-width=".18"/>
<circle cx="93.7" cy="54.6" r=".85" fill="#008000" stroke="#008000" stroke-width=".18"/>
<circle cx="93.7" cy="54.6" r=".55" fill="#fff" stroke="#000" stroke-width=".18"/>
<circle cx="93.7" cy="57.2" r=".85" fill="#008000" stroke="#008000" stroke-width=".18"/>
<circle cx="93.7" cy="57.2" r=".55" fill="#fff" stroke="#000" stroke-width=".18"/>
<circle cx="93.7" cy="59.7" r=".85" fill="#008000" stroke="#008000" stroke-width=".18"/>
<circle cx="93.7" cy="59.7" r=".55" fill="#fff" stroke="#000" stroke-width=".18"/>
<circle cx="93.7" cy="62.2" r=".85" fill="#008000" stroke="#008000" stroke-width=".18"/>
<circle cx="93.7" cy="62.2" r=".55" fill="#fff" stroke="#000" stroke-width=".18"/>
<circle cx="93.7" cy="64.8" r=".85" fill="#008000" stroke="#008000" stroke-width=".18"/>
<circle cx="93.7" cy="64.8" r=".55" fill="#fff" stroke="#000" stroke-width=".18"/>
<circle cx="93.7" cy="67.3" r=".85" fill="#008000" stroke="#008000" stroke-width=".18"/>
<circle cx="93.7" cy="67.3" r=".55" fill="#fff" stroke="#000" stroke-width=".18"/>
<circle cx="93.7" cy="69.9" r=".85" fill="#008000" stroke="#008000" stroke-width=".18"/>
<circle cx="93.7" cy="69.9" r=".55" fill="#fff" stroke="#000" stroke-width=".18"/>
<circle cx="93.7" cy="72.4" r=".85" fill="#008000" stroke="#008000" stroke-width=".18"/>
<circle cx="93.7" cy="72.4" r=".55" fill="#fff" stroke="#000" stroke-width=".18"/>
<circle cx="93.7" cy="74.9" r=".85" fill="#008000" stroke="#008000" stroke-width=".18"/>
<circle cx="93.7" cy="74.9" r=".55" fill="#fff" stroke="#000" stroke-width=".18"/>
<circle cx="93.7" cy="77.5" r=".85" fill="#008000" stroke="#008000" stroke-width=".18"/>
<circle cx="93.7" cy="77.5" r=".55" fill="#fff" stroke="#000" stroke-width=".18"/>
<circle cx="93.7" cy="80" r=".85" fill="#008000" stroke="#008000" stroke-width=".18"/>
<circle cx="93.7" cy="80" r=".55" fill="#fff" stroke="#000" stroke-width=".18"/>
<circle cx="93.7" cy="82.5" r=".85" fill="#008000" stroke="#008000" stroke-width=".18"/>
<circle cx="93.7" cy="82.5" r=".55" fill="#fff" stroke="#000" stroke-width=".18"/>
<circle cx="93.7" cy="85.1" r=".85" fill="#008000" stroke="#008000" stroke-width=".18"/>
<circle cx="93.7" cy="85.1" r=".55" fill="#fff" stroke="#000" stroke-width=".18"/>
<circle cx="62" cy="80.3" r="1.4" fill="#008000" stroke="#008000" stroke-width=".18"/>
<circle cx="62" cy="80.3" r=".93" fill="#fff" stroke="#000" stroke-width=".18"/>
<circle cx="62" cy="67.1" r="1.4" fill="#008000" stroke="#008000" stroke-width=".18"/>
<circle cx="62" cy="67.1" r=".93" fill="#fff" stroke="#000" stroke-width=".18"/>
<circle cx="105.1" cy="48.3" r=".93" fill="#008000" stroke="#008000" stroke-width=".18"/>
<circle cx="105.1" cy="48.3" r=".51" fill="#fff" stroke="#000" stroke-width=".18"/>
<circle cx="102.6" cy="48.3" r=".93" fill="#008000" stroke="#008000" stroke-width=".18"/>
<circle cx="102.6" cy="48.3" r=".51" fill="#fff" stroke="#000" stroke-width=".18"/>
<circle cx="100.1" cy="48.3" r=".93" fill="#008000" stroke="#008000" stroke-width=".18"/>
<circle cx="100.1" cy="48.3" r=".51" fill="#fff" stroke="#000" stroke-width=".18"/>
<circle cx="97.5" cy="48.3" r=".93" fill="#008000" stroke="#008000" stroke-width=".18"/>
<circle cx="97.5" cy="48.3" r=".51" fill="#fff" stroke="#000" stroke-width=".18"/>
<circle cx="95" cy="48.3" r=".93" fill="#008000" stroke="#008000" stroke-width=".18"/>
<circle cx="95" cy="48.3" r=".51" fill="#fff" stroke="#000" stroke-width=".18"/>
<circle cx="88" cy="72.7" r=".93" fill="#008000" stroke="#008000" stroke-width=".18"/>
<circle cx="88" cy="72.7" r=".44" fill="#fff" stroke="#000" stroke-width=".18"/>
<circle cx="88" cy="65.1" r=".93" fill="#008000" stroke="#008000" stroke-width=".18"/>
<circle cx="88" cy="65.1" r=".44" fill="#fff" stroke="#000" stroke-width=".18"/>
<circle cx="88" cy="85.7" r=".93" fill="#008000" stroke="#008000" stroke-width=".18"/>
<circle cx="88" cy="85.7" r=".44" fill="#fff" stroke="#000" stroke-width=".18"/>
<circle cx="88" cy="78.1" r=".93" fill="#008000" stroke="#008000" stroke-width=".18"/>
<circle cx="88" cy="78.1" r=".44" fill="#fff" stroke="#000" stroke-width=".18"/>
<circle cx="90.9" cy="78.1" r=".93" fill="#008000" stroke="#008000" stroke-width=".18"/>
<circle cx="90.9" cy="78.1" r=".44" fill="#fff" stroke="#000" stroke-width=".18"/>
<circle cx="90.9" cy="85.7" r=".93" fill="#008000" stroke="#008000" stroke-width=".18"/>
<circle cx="90.9" cy="85.7" r=".44" fill="#fff" stroke="#000" stroke-width=".18"/>
<circle cx="85.5" cy="81.9" r=".83" fill="#008000" stroke="#008000" stroke-width=".18"/>
<circle cx="85.5" cy="81.9" r=".44" fill="#fff" stroke="#000" stroke-width=".18"/>
<circle cx="85.5" cy="84.5" r=".83" fill="#008000" stroke="#008000" stroke-width=".18"/>
<circle cx="85.5" cy="84.5" r=".44" fill="#fff" stroke="#000" stroke-width=".18"/>
<circle cx="82.6" cy="60.3" r=".83" fill="#008000" stroke="#008000" stroke-width=".18"/>
<circle cx="82.6" cy="60.3" r=".44" fill="#fff" stroke="#000" stroke-width=".18"/>
<circle cx="80.1" cy="60.3" r=".83" fill="#008000" stroke="#008000" stroke-width=".18"/>
<circle cx="80.1" cy="60.3" r=".44" fill="#fff" stroke="#000" stroke-width=".18"/>
<circle cx="82.6" cy="57.5" r=".83" fill="#008000" stroke="#008000" stroke-width=".18"/>
<circle cx="82.6" cy="57.5" r=".44" fill="#fff" stroke="#000" stroke-width=".18"/>
<circle cx="80.1" cy="57.5" r=".83" fill="#008000" stroke="#008000" stroke-width=".18"/>
<circle cx="80.1" cy="57.5" r=".44" fill="#fff" stroke="#000" stroke-width=".18"/>
<circle cx="104.5" cy="67.3" r=".83" fill="#008000" stroke="#008000" stroke-width=".18"/>
<circle cx="104.5" cy="67.3" r=".44" fill="#fff" stroke="#000" stroke-width=".18"/>
<circle cx="104.5" cy="69.9" r=".83" fill="#008000" stroke="#008000" stroke-width=".18"/>
<circle cx="104.5" cy="69.9" r=".44" fill="#fff" stroke="#000" stroke-width=".18"/>
<g fill="#800000" stroke="#800000" stroke-width=".18">
<path d="M123.2 46.9h10.8v10.4h-10.8z"/>
<path d="M124.7 59.3h1.1v2.2h-1.1z"/>
<path d="M126.4 59.3h1.1v2.2h-1.1z"/>
<path d="M128.1 59.3h1.1v2.2h-1.1z"/>
<path d="M129.8 59.3h1.1v2.2h-1.1z"/>
<path d="M131.5 59.3h1.1v2.2h-1.1z"/>
<path d="M81.2 84.7h1.5v.8h-1.5z"/>
<path d="M81.2 83.4h1.5v.8h-1.5z"/>
<path d="M81.2 82.2h1.5v.7h-1.5z"/>
<path d="M81.2 80.9h1.5v.8h-1.5z"/>
<path d="M81.2 79.6h1.5v.8h-1.5z"/>
<path d="M81.2 78.4h1.5v.7h-1.5z"/>
<path d="M81.2 77.1h1.5v.7h-1.5z"/>
<path d="M81.2 75.8h1.5v.8h-1.5z"/>
<path d="M81.2 74.6h1.5v.7h-1.5z"/>
<path d="M81.2 73.3h1.5v.8h-1.5z"/>
<path d="M71.7 74.6h1.5v.7h-1.5z"/>
<path d="M71.7 73.3h1.5v.8h-1.5z"/>
<path d="M71.7 75.8h1.5v.8h-1.5z"/>
<path d="M71.7 77.1h1.5v.7h-1.5z"/>
<path d="M71.7 78.4h1.5v.7h-1.5z"/>
<path d="M71.7 79.6h1.5v.8h-1.5z"/>
<path d="M71.7 80.9h1.5v.8h-1.5z"/>
<path d="M71.7 82.2h1.5v.7h-1.5z"/>
<path d="M71.7 83.4h1.5v.8h-1.5z"/>
<path d="M71.7 84.7h1.5v.8h-1.5z"/>
<path d="M60 71.7h4v3.9h-4z"/>
<path d="M85.3 62.1h.3v1h-.3z"/>
<path d="M85.9 62.1h.3v1h-.3z"/>
<path d="M86.6 62.1h.3v1h-.3z"/>
<path d="M87.2 62.1h.3v1h-.3z"/>
<path d="M87.9 62.1h.3v1h-.3z"/>
<path d="M88.5 62.1h.3v1h-.3z"/>
<path d="M89.2 62.1h.3v1h-.3z"/>
<path d="M89.2 56.3h.3v1h-.3z"/>
<path d="M88.5 56.3h.3v1h-.3z"/>
<path d="M87.9 56.3h.3v1h-.3z"/>
<path d="M87.2 56.3h.3v1h-.3z"/>
<path d="M86.6 56.3h.3v1h-.3z"/>
<path d="M85.9 56.3h.3v1h-.3z"/>
<path d="M85.3 56.3h.3v1h-.3z"/>
</g>
<g fill="none" stroke="#800000" stroke-width=".42">
<path d="M54.2 58.7h.1M54.2 58.4h.1M54.2 56.1h.1M54.2 55.7h.1M54.2 53.8h.1M54.2 53.5h.1M54.2 53.1h.1M54.2 59.1h.2M54.2 58h.2M54.2 57.6h.4M54.2 56.5h.2M54.2 55.3h.2"/>
<path d="M54.2 54.2h.3M54.2 52.7h.2M54.2 49.7h.1M54.2 59.5h.6M54.2 56.9h.5M54.2 55h.5M54.2 52.4h.5M54.2 50.1h.6M54.2 59.8h.7M54.2 57.2h.9M54.2 54.6h.8M54.2 52h1.2"/>
<path d="M54.2 50.5h1.3M54.2 50.9h14.9M54.2 51.6h34.8M54.2 51.2h35.2M54.6 52.4l.5-.3 .5-.1 .1 1.3v-1.3a1.4 1.4 0 0 1 1.3 1.3h-1.3v.1h1.3a1.45 1.45 0 0 1-.8 1.3 1.32 1.32 0 0 1 .8 1.3 1.32 1.32 0 0 1-.9 1.2 1.33 1.33 0 0 1 .9 1.2 1.33 1.33 0 0 1-.9 1.3 1.36 1.36 0 0 1 .6 2.1 1.36 1.36 0 0 1-2.2 0 1.36 1.36 0 0 1 .7-2.1 1.33 1.33 0 0 1-1-1.3 1.33 1.33 0 0 1 1-1.2 1.34 1.34 0 0 1-.9-1.3 1.34 1.34 0 0 1 .8-1.2 1.39 1.39 0 0 1-.9-1.3h1.4v-.1h-1.4zM55.6 53.1h.1M55.6 52.7h.1M55.6 52.4h.1M55.6 52h.1M55.8 52h32.8M56.2 57.2h22.6M56.3 54.6h29.9"/>
<path d="M56.4 59.8h9.2M56.5 59.5h9M56.6 56.9h22.4M56.6 55h29.6M56.6 52.4h31.6M56.7 57.6h9.7M56.7 54.2h29.6M56.8 59.1h10.2M56.9 56.5h22.4M56.9 55.3h29.3M56.9 52.7h30.9M56.9 58h9.1"/>
<path d="M56.9 53.8h29.8M57 58.7h8.5M57 58.4h8.6M57 56.1h27.9M57 55.7h29.2M57 53.1h30.5M57 53.5h30.1M57.7 50.5h10.8M58.2 50.3a3.1 3.1 0 0 1-4-.6v35.6l.8-.7 1.1-.3h1l1 .3M58.4 50.1h9.9M58.4 45.3h89.6M58.8 49.7h9.4"/>
<path d="M58.9 45.6h88.7M59 49.7l-.9 .6M59.1 49.4h9.1M59.1 46h88.2M59.3 49h9M59.4 46.4h87.7M59.5 48.7l-.5 .9M59.5 48.6h9.1M59.5 46.7h63.3M59.6 48.2h9.5M59.6 47.1h34.7M59.6 47.9h34.1"/>
<path d="M59.7 47.5h34.2M59.7 47.6l-.2-1-.5-.9-.6-.4h89.6a2.96 2.96 0 0 0-1.2 2.4M59.7 47.6l-.2 1.1M65.5 58.4l.9-.8h.6v1.4h.1v-1.4h.6l.9 .8v.6l-1.5 .1h1.5v.6l-.9 .9h-.6v-1.5h-.1v1.5h-.6l-.9-.9v-.6l1.5-.1h-1.5zM67 59.8h.1M67 59.5h.1M67 58.7h.1M67 58.4h.1M67 58h.1M67 57.6h.1M67.1 59.1h6.1M67.8 57.6h6.2"/>
<path d="M68.1 58h5.6M68.5 59.8h4.8M68.5 58.4h4.8M68.5 48.6l.6-.3 .5-.1v1.3v-1.3a1.4 1.4 0 0 1 1.4 1.3h-1.4l1.4 .1a1.4 1.4 0 0 1-1.4 1.3v-1.3v1.3a1.36 1.36 0 0 1-1.4-1.3h1.4l-1.4-.1zM68.6 59.5h4.6M68.6 58.7h4.6M69.6 50.9h.1M69.6 50.5h.1M69.6 50.1h.1M69.6 49.7h.1M69.6 49.4h.1M69.6 49h.1"/>
<path d="M69.6 48.6h.1M69.6 48.2h.1M70 48.2h6.9M70.1 50.9h6.7M70.6 48.6h5.6M70.6 50.5h5.6M70.9 50.1h5.1M70.9 49h5.1M71 49.7h4.9M71 49.4h4.9M73.2 58.5l.9-.9h1.2l.9 .9v.9l3 3.1a1.37 1.37 0 0 1 2 .2 1.37 1.37 0 0 1-.3 1.9 1.37 1.37 0 0 1-1.9-.3l-.3-.1-3.7-3.6h-.9l-.9-.9zM75.3 57.6h3.5"/>
<path d="M75.7 58h3.2M76 58.4h3.1M76.2 59.1h3.6M76.2 58.7h3.5M76.2 59.5h2.9M76.6 59.8h2.3M77.5 48.2h16.1M77.6 50.9h12.1M78.2 48.6h2M78.2 50.5h2M78.4 49h1.5M78.5 50.1h1.4"/>
<path d="M78.6 49.7h1.1M78.6 49.4h1.1M79.1 59.5l.5-.3 .5-.1v1.2v-1.2a1.3 1.3 0 0 1 1.2 1.2h-1.2l1.2 .1a1.29 1.29 0 0 1-1.2 1.2v-1.2v1.2a1.29 1.29 0 0 1-1.3-1.2h1.3l-1.3-.1zM79.1 56.7l.5-.4 .5-.1v1.3v-1.3a1.25 1.25 0 0 1 1.2 1.3h-1.2h1.2a1.25 1.25 0 0 1-1.2 1.3v-1.3v1.3a1.29 1.29 0 0 1-1.3-1.3h1.3h-1.3zM80.1 59.8h.1M80.1 59.5h.1M80.1 59.1h.1M80.1 58.7h.1M80.1 58.4h.1M80.1 58h.1M80.1 57.6h.1M80.1 57.2h.1"/>
<path d="M80.1 56.9h.1M80.1 56.5h.1M80.4 59.1h8.7M80.4 58.7h9.1M80.9 56.5h1M81 59.5h.8M81 58.4h.7M81.2 56.9h.3M81.2 59.8h.3M81.3 58h.2M81.3 57.2h.1M81.3 57.6h.1"/>
<path d="M81.4 48.6h2.4M81.5 50.5h2.2M81.8 50.1h1.6M81.8 49h1.6M81.9 49.7h1.4M81.9 49.4h1.4M83.3 56.5h1.6M83.5 59.5h5.2M83.7 56.9h1.2M83.8 57.2h1.1M84.8 59.8h3.6M85 48.6h8.7"/>
<path d="M85 50.5h5.1M85.4 50.1h5.1M85.4 49h8.4M85.5 49.7h5.4M85.5 49.4h5.7M86.1 56.8v-1l-1 .1-.2 .2v1.2h-1.1a1.25 1.25 0 0 0-1.6-1 1.25 1.25 0 0 0-.7 1.8 1.25 1.25 0 0 0 2 .3h1.7l.4 .3h1.7l.6-.7 .1-1.2M86.1 56.5h.1M86.1 56.1h.1M87.6 58.4h4.1M87.9 58h4.2M87.9 55.7h5.2M88 57.6h.1"/>
<path d="M88 57.2h.1M88 56.9h.1M88 56.5h.1M88 56.1h.1M88 56.8h.7M88 56.8v.9h.7v-.9M88 56.8v-1h.7v1M88.3 55.3h4.4M88.7 55h3.8M88.7 56.8h-.7M88.7 57.6h.1M88.7 57.2h.1"/>
<path d="M88.7 56.9h.1M88.7 56.5h.1M88.7 56.1h.1M88.7 55.8l.9 .1 .3 .2v1.4l-.3 .2h-.9zM89 54.6h3.5M89.4 54.2h3.1M89.7 57.6h2.8M89.8 53.8h2.9M89.8 56.1h3.3M89.9 57.2h2.6M89.9 56.9h2.6M89.9 56.5h2.8"/>
<path d="M90.1 53.5h3.1M90.5 53.1h2.5M90.9 52.7h1.7M91.3 52.4h1.2M91.6 52h.9M92 51.6h.6M94.2 53.5h6.7M94.4 56.1h.1M94.5 53.1h6.1M94.7 53.8h5.7M94.8 52.7h5.5M94.9 51.6h5.3"/>
<path d="M94.9 54.2h5.2M94.9 55h5.2M95 54.6h5.1M95 52.4h5.1M95 52h5.1M95.2 55.3h5.1M95.6 55.7h5.1M95.7 47.1h1.1M95.9 59.8h4.2M95.9 59.5h4.2M95.9 59.1h4.4M95.9 57.6h4.3"/>
<path d="M95.9 57.2h4.2M95.9 56.9h4.2M95.9 56.5h4.4M95.9 58.7h4.7M95.9 58h4.5M95.9 58.4h5M95.9 56.1h4.8M96.1 47.5h.3M98.2 47.1h1.2M98.6 47.5h.4M100.8 47.1h1.1M101.2 47.5h.3"/>
<path d="M101.8 58.4h.8M101.8 53.5h.8M101.9 55.7h.7M102 56.1h.6M102.1 53.1h.5M102.1 58.7h.5M102.2 50.7l1 1.1M102.3 58h.3M102.3 53.8h.3M102.4 55.3h.2M102.4 56.5h.2M102.4 52.7h.2"/>
<path d="M102.4 59.1h.2M102.5 57.6h.1M102.5 54.2h.1M102.5 56.9h.1M102.5 55h.1M102.6 59.8h.1M102.6 59.5h.1M102.6 57.2h.1M102.6 54.6h.1M102.6 52.4h.1M102.6 52h.1M102.6 52l-.1 11.4 .1 .2 7.8 7.8 .3 .4 .3 .1h10.3a1.27 1.27 0 0 0 1.9 .2 1.27 1.27 0 0 0 0-1.9 1.27 1.27 0 0 0-1.9 .1h-9.9l-7.5-7.4v-.4l6.1 6.2 .4 .1h14.5l.6 .1 .3-.1 1.8-1.9 .1-.2v-4.9l.2 .1 .7 .1v-1.5h.1v1.5l.6-.1 .2-.1v1l.2 .3 2.4 2.5a1.06 1.06 0 0 0 .8 1.5v1.2l-2.1 2a1.27 1.27 0 0 0-1.8-.1 1.27 1.27 0 0 0 0 1.9 1.27 1.27 0 0 0 1.9-.2l.7-.1 2.8-2.8 .1-.3v-1.6a1.08 1.08 0 0 0 1-1 1.08 1.08 0 0 0-.9-1.1h-.8l-2.7-2.7v-.5l.2 .1h1.4l.3-.2v-.5h.5l.1 1.9 7.4 7.4-.7 .5-.2 .4v2l.5 .7h-1.1l.5-.7v-.9h-1.2v-.2h1.2v-.8a1.23 1.23 0 0 0-1.2-1.1v1.9h-.1v-1.9a1.23 1.23 0 0 0-1.1 1.1v.8h1.1v.2h-1.1v.9l.4 .7h-28.1l-4.2-4.1a1.22 1.22 0 0 0-.7-1.3 1.22 1.22 0 0 0-1.4 .3h-1.3a1.23 1.23 0 0 0-1.9 0h-1.3l-4.1-4.1a1.23 1.23 0 0 0-.6-1.2 1.23 1.23 0 0 0-1.4 0l.3-.3a1.25 1.25 0 0 0 1.5-.4 1.25 1.25 0 0 0-.1-1.6l1.2-1.1v-4.3l-1-1a1.26 1.26 0 0 0-1.1-1.6 1.26 1.26 0 0 0-1.3 1.4 1.26 1.26 0 0 0 1.6 1l.3 .3a1.26 1.26 0 0 0-1.5 .1 1.26 1.26 0 0 0-.4 1.4l-.9 .9h-1.9l-2.9 2.9-.1 1.2"/>
<path d="M102.6 52a1.26 1.26 0 0 1-1.7 1.3 1.26 1.26 0 0 1-.5-2h-5.8a1.25 1.25 0 0 1 0 1.7 1.25 1.25 0 0 1-1.8 0 1.25 1.25 0 0 1 0-1.7h-.4l-4.5 4.4 .1 1.1M103.3 49.7h17.2M103.3 47.1h1.1M103.4 49.4h.9M103.6 50.1h16.6M103.7 47.5h.3M103.8 49h.1M104 50.5h16M104.4 50.9h9.9M104.5 51.8v10.4M104.8 51.2h8.5M105.1 49.4h.1"/>
<path d="M105.1 49h.1M105.1 48.6h.1M105.1 47.9h.1M105.1 47.5h.1M105.1 47.1h.1M105.1 51.6h7.7M105.1 57.2h2.4M105.1 56.9h2.3M105.1 56.5h2.3M105.1 56.1h2.3M105.1 55.7h2.4M105.1 57.6h2.6"/>
<path d="M105.1 55.3h2.5M105.1 58.4h3.2M105.1 58h2.8M105.1 55h2.8M105.1 54.6h3.1M105.1 58.7h3.7M105.1 54.2h3.6M105.1 59.8h7M105.1 59.5h7M105.1 59.1h7M105.1 53.8h7M105.1 53.1h7"/>
<path d="M105.1 52.7h7M105.1 52.4h7.2M105.1 52h7.4M105.1 53.5h9.4M105.2 48.2h17.6M105.9 47.1h16.9M106 49.4h16.8M106.3 47.5h16.5M106.3 49h16.5M106.5 47.9h16.3M106.5 48.6h16.3M111.2 58.7h1"/>
<path d="M111.3 54.2h.9M111.7 58.4h.6M111.7 54.6h.6M112 58h.5M112.1 55h.4M112.3 57.6h.6M112.3 55.3h.6M112.4 57.2h1M112.4 55.7h1M112.5 56.9h10.3M112.5 56.5h10.3M112.5 56.1h10.3"/>
<path d="M112.9 51.5l.8-.5 .8-.2v2.4h.4v-2.4a2.62 2.62 0 0 1 2.4 2.4h-2.4v.5h2.4a2.62 2.62 0 0 1-2.4 2.3v-2.3h-.4v2.3a2.58 2.58 0 0 1-2.4-2.3h2.4v-.5h-2.4l.3-1zM113.1 57.4a2.58 2.58 0 0 1 3.8 .7 2.58 2.58 0 0 1-1.2 3.7l3.4 3.4h.6l.4-.2h1.8a1.09 1.09 0 0 1 .8 1 1.09 1.09 0 0 1-.8 1.1h-1.8l-.4-.2h-1.1l-.3-.2-4.3-4.3-.1-.5-.4-.2-.8 .9v1.5h.2l.3 .3v2.1l-.3 .2h-2.1l-.2-.2v-2.1l.2-.3h.3v-2l.1-.3 1.2-1.2a2.58 2.58 0 0 1 .7-3.2zM114.5 55.7h.4M114.5 55.3h.4M114.5 55h.4M114.5 54.6h.4M114.5 54.2h.4M114.5 53.8h.4M114.5 53.1h.4M114.5 52.7h.4M114.5 52.4h.4M114.5 52h.4"/>
<path d="M114.5 51.6h.4M114.5 51.2h.4M114.5 50.9h.4M114.9 53.5h7.9M115.1 50.9h4.9M116 57.2h4.8M116 55.7h6.8M116.1 51.2h3.9M116.4 57.6h3.9M116.5 55.3h6.3M116.5 51.6h3.7M116.8 58h3.3"/>
<path d="M116.8 55h6M116.8 52h3.8M117 58.4h3M117 54.6h5.8M117 52.4h5.8M117.1 58.7h2.9M117.2 54.2h5.6M117.2 52.7h5.6M117.2 59.8h4.2M117.2 59.1h2.9M117.2 59.5h3.3M117.2 53.8h5.6"/>
<path d="M117.2 53.1h5.6M121.9 57.2h.9M122.1 52h.7M122.1 49.7h.7M122.4 57.6h.6M122.5 51.6h.3M122.5 50.1h.3M122.6 58h13M122.6 51.2h.2M122.6 50.5h.2M122.7 50.9h.1M122.7 58.7h12.1"/>
<path d="M122.7 58.4h12.5M122.8 46.7l.3-.2h11.1l.2 .2v10.8l-.2 .2h-11.1l-.3-.2zM122.9 59.1h1.5M123.3 59.5h1M128.6 59.8h.1M128.6 59.5h.1M128.6 59.1h.1M132.9 59.1h1.5M133 59.5h1.1M134.3 57.6h1.6M134.4 57.2h1.9M134.4 56.9h2"/>
<path d="M134.4 56.5h2M134.4 56.1h2M134.4 55.7h2M134.4 55.3h2M134.4 55h2M134.4 54.6h2M134.4 54.2h2M134.4 53.8h2M134.4 53.5h2M134.4 53.1h2M134.4 52.7h2M134.4 52.4h2.3"/>
<path d="M134.4 52h2.7M134.4 51.6h3.1M134.4 50.1h4.3M134.4 49.7h4.2M134.4 49.4h4.2M134.4 50.9h5M134.4 50.5h4.5M134.4 49h4.4M134.4 48.6h4.6M134.4 48.2h5.2M134.4 47.9h12.4M134.4 47.5h12.4"/>
<path d="M134.4 47.1h12.5M134.4 46.7h12.6M134.4 51.2h17.8M136 59.8h2.6M136.4 59.5h2.4M136.7 59.1h2.3M137.1 58.7h2.5M137.5 58.4h5.2M137.9 58h4.4M138 55.7h.7M138 55.3h.7M138 55h.7"/>
<path d="M138 54.6h.7M138 54.2h.7M138 53.8h.7M138 53.5h.7M138 56.1h2.4M138 56.9h3.2M138 56.5h2.8M138 57.6h3.9M138 57.2h3.5M138 53.4l.5-.5h3.8l1.1 1.2 .3 .1h6.1l.6 .4a1.34 1.34 0 0 0-.9 1.3 1.34 1.34 0 0 0 .9 1.3l-.6 .4h-3.3l-.3 .2-1.5 1.5v-1l-.1-.3-3.2-3.2v-1.3l-.2-.3h-2.3l-.2 .3v2.2l.2 .3h1.4l2.8 2.8v2.1l-2.8 2.8h-1.4l-.2 .2v2l-3.6-3.6v-1.5l2.8-2.8 .1-.3zM138.3 53.1h4.2M139 59.1l.5-.3 .5-.1 .1 1.3v-1.3a1.43 1.43 0 0 1 1.4 1.3h-1.4l1.4 .1a1.4 1.4 0 0 1-1.4 1.4v-1.4l-.1 1.4a1.43 1.43 0 0 1-1.4-1.4h1.4l-1.4-.1z"/>
<path d="M139 48.7l.5-.4 .5-.1 .1 1.4v-1.4a1.43 1.43 0 0 1 1.4 1.4h-1.4h1.4a1.4 1.4 0 0 1-1.4 1.4v-1.4l-.1 1.4a1.39 1.39 0 0 1-1.4-1.4h1.4h-1.4zM140 59.8h.1M140 59.5h.1M140 59.1h.1M140 58.7h.1M140 50.9h.1M140 50.5h.1M140 50.1h.1M140 49.7h.1M140 49.4h.1M140 49h.1M140 48.6h.1"/>
<path d="M140 48.2h.1M140.5 48.2h6.4M140.5 58.7h2.5M140.7 50.9h11.5M141.1 48.6h5.9M141.1 59.1h2M141.2 50.5h7.6M141.3 59.5h1.8M141.3 49h5.9M141.4 50.1h6.7M141.4 53.5h1.4M141.4 53.8h1.8"/>
<path d="M141.4 54.6h8.9M141.4 54.2h8.4M141.5 59.8h1.6M141.5 49.4h5.9M141.5 49.7h6.1M141.6 55h8.3M142 55.3h7.6M142.3 55.7h7.2M142.7 56.1h6.8M143.1 56.5h6.5M143.3 51.6h8.9M143.3 51.6l-.5-.3h-4.8l-.3 .1-1.2 1.2-.1 .3v4.2l-2.5 2.5h-.9v-.4l-.3-.3h-1.4l-.1 .2-.2-.2h-1.4l-.1 .2-.3-.2h-.5v1.5h-.1v-1.5h-.6l-.3 .2-.1-.2h-1.4l-.1 .2-.2-.2h-1.4l-.2 .3v.4h-.9l-.8-.8a1.36 1.36 0 0 0-1.1-1.7 1.36 1.36 0 0 0-1.5 1.3 1.36 1.36 0 0 0 1.4 1.4l1 1.2 .4 .2h1.5v.5l.2 .2h1.4l.2-.1v4.3l-1.2 1.3h-14.3l-5.5-5.5v-10.2l-.1-.3-1.9-1.9 .3-.1 .5-.6a1.32 1.32 0 0 0 1.2 .9v-1.4l.1 1.4a1.36 1.36 0 0 0 1.3-1.4h-1.3v-.1h1.3a1.4 1.4 0 0 0-1.3-1.3v1.3l-.1-1.3a1.35 1.35 0 0 0-1.2 .9 1.34 1.34 0 0 0-1.3-.9 1.34 1.34 0 0 0-1.3 .9 1.34 1.34 0 0 0-1.2-.9 1.34 1.34 0 0 0-1.3 .9 1.34 1.34 0 0 0-1.3-.9 1.34 1.34 0 0 0-1.2 .9 1.35 1.35 0 0 0-2.1-.6 1.35 1.35 0 0 0-.1 2.1h-2.8l-5.1 5.1-.1 2.4"/>
<path d="M143.3 51.7l.9 .9h5.6a1.35 1.35 0 0 1 2.1-.1 1.35 1.35 0 0 1-.6 2.1 1.34 1.34 0 0 1 .9 1.3 1.34 1.34 0 0 1-.9 1.3 1.34 1.34 0 0 1 .9 1.2 1.34 1.34 0 0 1-.8 1.3 1.32 1.32 0 0 1 .8 1.2h-1.3l1.3 .1a1.36 1.36 0 0 1-1.3 1.4v-1.4h-.1v1.4a1.4 1.4 0 0 1-1.4-1.4h1.4l-1.4-.1a1.37 1.37 0 0 1 .9-1.2l-.5-.5h-2.8l-5.6 5.7v1.3l-.2 .2h-2l4.2 4.2a1.14 1.14 0 0 1 1.6 .8v2l-.3 .6v.5l-.1 .3-.7 .6-.5 .4h-34l-.5-.4-4.3-4.3-.8-.2-.2-.2h-1.3a1.23 1.23 0 0 1-1.9 0h-1.8l-.3-.2-3.3-3.3a1.26 1.26 0 0 1-1.2 1.4 1.26 1.26 0 0 1-1.4-1.3 1.26 1.26 0 0 1 1.5-1.2l-.9-.3-.2-.2-2.8 2.8M143.5 56.9h6.4M143.6 52h8.6M143.8 57.2h6.5M144 52.4h6M144.2 57.6h5.6M144.6 58h1.4M144.7 59.1h.2M144.7 58.7h.6M144.7 58.4h.9M146.4 59.8h3.6M146.8 47.6l.2 1.1"/>
<path d="M146.8 59.5h3.2M147 48.7l.5 1M147.5 49.6h.1M147.5 49.6a3.1 3.1 0 0 0 4 .7M151 50.5h1.2M151.4 54.6h.8M151.4 50.3l.8-.6v35.6l-.8-.7-1-.3h-1l-1.1 .3-.8 .7M151.4 57.2h.8M151.7 59.8h.5M151.7 50.1h.5M151.7 59.5h.5M151.8 52.4h.4"/>
<path d="M151.8 56.9h.4M151.8 55h.4M151.9 54.2h.3M151.9 57.6h.3M152 59.1h.2M152 52.7h.2M152.1 56.5h.1M152.1 55.3h.1M152.1 58h.1M152.1 53.8h.1M152.2 49.7h.1M152.2 58.7h.1"/>
<path d="M152.2 58.4h.1M152.2 56.1h.1M152.2 55.7h.1M152.2 53.5h.1M152.2 53.1h.1M54.2 61.3h.1M54.2 61h.1M54.2 61.7h.3M54.2 60.6h.1M54.2 60.2h.3M54.2 62.1h.6M54.2 75.6h5.3"/>
<path d="M54.2 75.2h5.3M54.2 74.8h5.3M54.2 74.4h5.3M54.2 74.1h5.3M54.2 73.3h5.3M54.2 72.9h5.3M54.2 72.6h5.3M54.2 72.2h5.3M54.2 71.8h5.3M54.2 71.5h5.4M54.2 75.9h5.5M54.2 79.7h6.1"/>
<path d="M54.2 67.7h6.1M54.2 67.3h6M54.2 66.9h6M54.2 66.6h6M54.2 66.2h6.2M54.2 79.3h6.2M54.2 68.1h6.3M54.2 65.8h6.5M54.2 78.9h6.6M54.2 68.5h6.6M54.2 65.5h7M54.2 78.6h7.2"/>
<path d="M54.2 68.8h7.3M54.2 73.7h7.6M54.2 78.2h17.1M54.2 77.8h17M54.2 77.4h17M54.2 77.1h17M54.2 76.7h17M54.2 76.3h17M54.2 71.1h22.2M54.2 70.7h22.2M54.2 70.3h22.2M54.2 70h22.2"/>
<path d="M54.2 69.6h22.3M54.2 69.2h22.5M54.2 62.5h22.7M54.2 62.8h23.1M54.2 63.2h23.5M54.2 63.6h23.8M54.2 64h24.2M54.2 64.3h24.8M54.2 64.7h25.2M54.2 65.1h30.7M56.4 62.1h20.1M56.8 60.2h9.2"/>
<path d="M56.8 61.7h19.4M56.9 60.6h9.5M56.9 61.3h18.9M57 61h18.4M59.6 71.4l.4-.2h1.8v2.3h.4v-2.3l2 .1 .2 .3v1.9h-2.2v.4h2.2l-.1 2-.3 .2h-1.8v-2.2h-.4v2.2h-1.8l-.3-.1-.2-.3v-1.8h2.3v-.4h-2.3zM61.8 75.9h.4M61.8 75.6h.4M61.8 75.2h.4M61.8 74.8h.4M61.8 74.4h.4M61.8 74.1h.4M61.8 73.3h.4"/>
<path d="M61.8 72.9h.4M61.8 72.6h.4M61.8 72.2h.4M61.8 71.8h.4M61.8 71.5h.4M62.2 73.7h9.1M62.4 68.8h14.7M62.5 78.6h8.7M62.8 65.5h22.1M63.1 68.5h14.4M63.2 78.9h8M63.3 65.8h21.6"/>
<path d="M63.5 68.1h14.4M63.5 79.3h4.4M63.6 66.2h21.3M63.7 67.7h14.5M63.7 79.7h3.8M63.7 66.6h21.2M63.8 67.3h14.8M63.8 66.9h21.1M64.3 75.9h6.9M64.4 71.5h12M64.4 75.6h6.9M64.4 75.2h6.8"/>
<path d="M64.4 74.8h6.8M64.4 74.4h6.8M64.4 74.1h6.9M64.4 73.3h6.9M64.4 72.9h7M64.4 72.6h12M64.4 72.2h12M64.4 71.8h12M67 60.6h.1M67 60.2h.1M67.7 60.6h7.3M68.1 60.2h5.6"/>
<path d="M72.4 77.5h-1.2v1.2h2.5l-.1 .7M72.4 76.2h-1.2v1.3h2.5v1.2h-1.3M72.4 74.9h-1.2v1.3h1.2M72.4 77.5l.1 1.2M72.4 74.9v2.6M72.4 76.2l.1 1.3M72.4 78.6h.1M72.4 78.2h.1M72.4 77.8h.1M72.4 77.4h.1M72.4 77.1h.1M72.4 76.7h.1"/>
<path d="M72.4 76.3h.1M72.4 75.9h.1M72.4 75.6h.1M72.4 75.2h.1M72.4 76.2h1.3v1.3h-1.3M72.4 75l1.3-.1v1.3h-1.3M72.4 78.7h-1.2v.5h-3l-.3 .1-1.8 1.8h-2.1l-.3-.3a1.81 1.81 0 0 0-1.5-2.3 1.81 1.81 0 0 0-2 1.9 1.81 1.81 0 0 0 2.3 1.6l.7 .6 .3 .1h3.1l.3-.1 1.8-1.8h.2l-1.3 1.3-.1 .3v4.1l.1 .3 1.5 1.5 .3 .1h25.1l.3-.1 1.5-1.5 .1-.3v-3.1l-.3-.6M72.5 73.7v-.9l-1 .1-.2 .2v.6h2.4v1.2h-1.3M72.5 73.7h-1.2v.6l-.1 .2v.4l1.2 .1M72.5 77.5l-.1 1.2M72.5 74.9l-.1 1.3M72.5 73.3h.1"/>
<path d="M72.5 72.9h.1M72.5 72.8l1 .1 .2 .3v.5h-1.2zM73.5 72.9h2.9M73.6 79.4l-.1 2.5 .2 1.9h-2.5l.1 1.8h-.7l-.2-.2v-1.9l.2-.1h.6v.4h2.5l-.1 1.8h7.2v-.5h1.2M73.6 75.6h2.8M73.6 79.7h4M73.6 78.2h2.8M73.6 79.3h3.7M73.6 76.7h2.8M73.6 74.4h2.8M73.7 77.8h2.7M73.7 77.4h2.7"/>
<path d="M73.7 77.1h2.7M73.7 76.3h2.7M73.7 75.9h2.7M73.7 75.2h2.7M73.7 74.8h2.7M73.7 78.6h2.8M73.7 78.9h3.2M73.7 74.1h2.7M73.7 73.7h2.7M73.7 73.3h2.7M77 60.2h1.8M77.3 60.6h1.5"/>
<path d="M77.7 61h1.3M78 71.8h.9M78 71.5h.7M78 71.1h.7M78 70.7h.8M78 70.3h1M78 72.2h1.2M78 77.4h2.8M78 77.1h2.8M78 76.7h2.8M78 76.3h2.8M78 75.9h2.8"/>
<path d="M78 75.2h2.8M78 74.8h2.8M78 74.4h2.8M78 74.1h2.8M78 73.7h2.8M78 73.3h2.8M78 75.6h2.8M78 72.9h2.9M78 72.6h8.6M78.1 77.8h2.7M78.1 61.3h1.2M78.3 70h1.1"/>
<path d="M78.4 78.2h2.4M78.5 61.7h6.4M78.6 69.6h13.8M78.8 78.6h2M78.8 62.1h6.1M79 69.2h13.6M79.2 78.9h1.6M79.2 62.5h.1M79.4 68.8h13.5M79.6 79.3h1.2M79.9 79.7h.9M80.1 61.3h.1"/>
<path d="M80.1 61h.1M80.1 60.6h.1M80.1 60.2h.1M80.7 64.7h4.2M80.7 70h11.7M80.9 61.3h1M80.9 72.2h5.8M80.9 62.5h4M81.2 64.3h3.7M81.2 70.3h11.3M81.2 61h.3M81.2 62.8h3.7"/>
<path d="M81.2 71.8h5.7M81.3 60.6h.1M81.3 60.2h.1M81.3 64h3.6M81.4 70.7h11.3M81.4 63.2h3.5M81.4 71.5h6M81.4 63.6h3.5M81.4 71.1h11.9M82 76.2h-1.2v1.3h2.4l-.1 .6M82 73.7v-.9l-.9 .1-.3 .2v.6h1.2M82 73.7h-1.2v1.2l1.2 .1"/>
<path d="M82 74.9h-1.2v1.3h1.2M82 74.9v2.6M82 73.7v2.5M82 76.2v.8M82 77v.4M82 77.1h.1M82 76.7h.1M82 76.3h.1M82 75.9h.1M82 75.6h.1M82 75.2h.1M82 74.8h.1"/>
<path d="M82 74.4h.1M82 74.1h.1M82 73.7h.1M82 73.3h.1M82 72.9h.1M82 73.7h1.2v-.6l-.3-.2-.9-.1v2.1M82 76.2h1.2v1.3h-1.2M82 75l1.2-.1v1.3h-1.2M82 73.7h1.2v1.2h-1.2M83 72.9h3.6M83.1 78.2v2.3h1.4l2.2-2.2a1.36 1.36 0 0 1 .8-1.5 1.36 1.36 0 0 1 1.6 .5h.7a1.36 1.36 0 0 1 2-.2 1.36 1.36 0 0 1 0 2 1.36 1.36 0 0 1-2-.2h-.7l-.8 .6h-.5l-1.5 1.5a1.25 1.25 0 0 1-.2 2 1.25 1.25 0 0 1-1.9-.9h-1.1v1.1M83.1 75.6h9.5"/>
<path d="M83.1 79.7h2.2M83.1 79.3h2.5M83.1 78.9h2.9M83.1 78.6h3.3M83.1 78.2h3.6M83.2 74.4h9.4M83.2 76.7h9.5M83.2 77.8h3.5M83.2 73.3h3.5M83.2 77.4h3.6M83.2 73.7h3.8M83.2 77.1h3.9"/>
<path d="M83.2 74.1h4.5M83.2 75.2h9.3M83.2 74.8h9.3M83.2 75.9h9.8M83.2 76.3h10.1M83.4 61.3h1.3M83.7 61h.7M85.2 60.2h2.8M85.6 60.6h2M85.9 61h1.3M86 61.7h.4M86 61.3h.9"/>
<path d="M86.7 65.5h.1M86.7 65.1h.1M86.7 64.7h.1M86.7 65.8h.2M86.7 64.3h.2M86.7 66.2h.5M86.7 64h.5M86.7 63.6h2M86.7 62.6v-.9h-.7v-.7l-.9-.9-.4-.3h-1a1.25 1.25 0 0 0-1.9-.4 1.25 1.25 0 0 0 0 1.9 1.25 1.25 0 0 0 1.9-.4h.6l.6 .6v5.6h-5.9l-.3 .2-2.2 2.1-.1 .3v8.6l.1 .3 3.4 3.4 .9 .1 .1 1.1-.1 .6h2.4v1.3h-1.2M86.7 63.2h.1M86.7 62.8h.1M86.7 62.5h.1"/>
<path d="M86.7 62.1h.1M86.7 61.7h.1M86.7 62.6v1l1-.1M86.7 62.6v3.8h2l3.8-3.7v-.7l.2-.5h-2.6l-.2 .3v2.2l-.6 .6a1.37 1.37 0 0 1-1.2 1.9 1.37 1.37 0 0 1-1.5-1.6 1.37 1.37 0 0 1 1.9-1.1l.2-.2v-1v1l-1-.1M87.1 71.6l.4-.2 .5-.1v1.4v-1.4a1.36 1.36 0 0 1 1.4 1.4h-1.4h1.4a1.36 1.36 0 0 1-1.4 1.4v-1.4v1.4a1.4 1.4 0 0 1-1.4-1.4h1.4h-1.4l.1-.5zM87.6 79.7h4.9M87.7 63.5h.1M88 74.1h.1M88 73.7h.1M88 73.3h.1M88 72.9h.1M88 72.6h.1"/>
<path d="M88 72.2h.1M88 71.8h.1M88 71.5h.1M88.4 74.1h4.4M88.6 71.5h4.3M88.6 79.3h1.6M88.7 63.2h.1M88.7 62.8h.1M88.8 66.2h.2M88.9 77.1h1.1M89 73.7h4.5M89.1 78.9h.7"/>
<path d="M89.1 71.8h3.5M89.2 65.8h.2M89.3 73.3h3.6M89.3 65.5h.4M89.3 64.7h1.2M89.3 72.2h3.2M89.4 65.1h.7M89.4 72.9h3.2M89.4 72.6h3.1M89.6 64.3h1.2M89.9 64h1.3M89.9 63.6h1.7"/>
<path d="M89.9 63.2h2.1M89.9 62.8h2.4M89.9 62.5h2.6M89.9 62.1h2.6M89.9 68.5h3.3M90 68.5l-.6 .3h-10l-1.4 1.4v7.6l2.8 2.7 .1-1.1-.1-1.9h1.2M90 61.7h2.6M90.3 68.1h2.4M90.7 67.7h1.8M91 67.3h1.5M91.4 66.9h1.1M91.5 79.3h1.2"/>
<path d="M91.7 77.1h.8M91.8 66.6h.9M91.9 78.9h1.2M92 77.4h.5M92.1 78.6h1M92.2 66.2h1M92.2 77.8h.3M92.2 78.2h.5M92.5 65.8h.5M92.9 68.9l.7-.3v1.2h.2v-1.2a1.26 1.26 0 0 1 1.2 1.2h-1.2v.1h1.2a1.26 1.26 0 0 1-1.2 1.3v-1.3h-.2v1.3a1.3 1.3 0 0 1-1.2-1.3h1.2v-.1h-1.2l.1-.4zM93.2 63.6h.2M93.6 71.1h.2"/>
<path d="M93.6 70.7h.2M93.6 70.3h.2M93.6 70h.2M93.6 69.6h.2M93.6 69.2h.2M93.6 68.8h.2M94 73.7h7.1M94.1 63.6h6.9M94.2 76.3h6.7M94.2 71.1h6.8M94.2 68.5h2M94.3 78.6h6.4"/>
<path d="M94.4 78.9h6.3M94.5 75.9h6.1M94.5 68.8h2.1M94.5 71.5h6M94.5 63.2h6M94.6 73.3h5.9M94.6 74.1h5.8M94.6 64h5.8M94.7 76.7h5.7M94.7 70.7h5.7M94.7 68.1h1.2M94.8 79.3h5.5"/>
<path d="M94.8 78.2h5.5M94.8 61.3h5.7M94.8 75.6h5.5M94.8 62.8h5.4M94.8 69.2h2.2M94.8 72.9h5.4M94.8 71.8h5.4M94.9 74.4h5.3M94.9 61.7h5.3M94.9 64.3h5.3M94.9 67.7h.6M94.9 77.1h5.3"/>
<path d="M94.9 79.7h5.2M94.9 77.8h5.2M94.9 70.3h3.2M95 67.3h.1M95 77.4h5.1M95 75.2h5.1M95 74.8h5.1M95 72.6h5.1M95 72.2h5.1M95 64.7h5.1M95 62.5h5.1M95 62.1h5.1"/>
<path d="M95 69.6h2.4M95 70h2.7M95.2 61h7.4M95.2 65.1h4.9M95.5 65.5h4.8M95.5 60.6h5M95.9 60.2h4.3M95.9 65.8h4.7M96.3 66.2h4.4M96.7 66.6h3.6M97 66.9h3.1M97.4 67.3h3.9"/>
<path d="M97.8 67.7h2.3M98.2 68.1h2.1M98.5 68.5h2.2M98.9 68.8h1.7M100.3 76.8a1.26 1.26 0 0 1 1.6-.5 1.26 1.26 0 0 1 .6 1.6l6.2 6.1h1.6a1.36 1.36 0 0 1 2-.2 1.36 1.36 0 0 1 0 2 1.36 1.36 0 0 1-2-.2h-2.2l-.2-.1-5.3-5.3a1.26 1.26 0 0 1-2.1 .7 1.26 1.26 0 0 1 .6-2.1 1.33 1.33 0 0 1-.8-2zM100.3 74.2a1.32 1.32 0 0 1 2.1 .1l7.5 7.4h12.1l.3 .2 1.6 1.6a1.36 1.36 0 0 1 1.6 1.2 1.36 1.36 0 0 1-1.4 1.5 1.36 1.36 0 0 1-1.3-1.6l-1.3-1.2h-12.1l-.3-.2-7.2-7.1a1.27 1.27 0 0 1-1.5-.3 1.27 1.27 0 0 1-.1-1.6zM100.5 66.3l.8-.3v1.2h.1v-1.2a1.26 1.26 0 0 1 1.2 1.2h-1.2v.2h1.2a1.26 1.26 0 0 1-1.2 1.2v-1.2h-.1v1.2a1.3 1.3 0 0 1-1.3-1.2h1.3v-.2h-1.3l.1-.4zM101.3 68.5h.1M101.3 68.1h.1M101.3 67.7h.1M101.3 66.9h.1M101.3 66.6h.1"/>
<path d="M101.3 66.2h.1M101.4 67.3h5M101.6 73.7h1.8M101.6 71.1h2.6M101.7 63.6h.9M101.8 76.3h.4M102 68.5h1.9M102 66.2h1.9M102.1 68.8h1.7M102.1 65.8h2.8M102.1 63.2h.4M102.1 71.5h2.9"/>
<path d="M102.2 73.3h.8M102.2 61.3h.4M102.2 60.6h.4M102.2 74.1h1.6M102.3 64h.7M102.3 70.7h1.3M102.3 76.7h.3M102.4 68.1h1.1M102.4 66.6h1.1M102.4 65.5h2.1M102.4 62.8h.2M102.5 61.7h.1"/>
<path d="M102.5 60.2h.1M102.5 64.3h.9M102.5 77.1h.4M102.5 77.8h1.2M102.6 65.1h1.5M102.6 62.5h.1M102.6 62.1h.1M102.6 77.4h.7M102.6 67.7h.7M102.6 66.9h.7M102.6 64.7h1.1M102.6 74.4h1.5"/>
<path d="M102.8 78.2h1.3M103 74.8h1.5M103.2 78.6h1.2M103.4 75.2h1.5M103.5 66.5l.3-.3 .7-.2v1.3v-1.3a1.29 1.29 0 0 1 1.3 1.3h-1.3l1.3 .1a1.3 1.3 0 0 1-1.3 1.2v-1.2v1.2a1.25 1.25 0 0 1-1.3-1.2h1.3l-1.3-.1zM103.6 78.9h1.2M103.7 75.6h1.6M103.8 71.8h1.5M103.9 62.8h.3M103.9 71.9l-.5-.3h-1.1a1.26 1.26 0 0 0-1.8-.1 1.26 1.26 0 0 0 0 1.8 1.26 1.26 0 0 0 1.8-.1h.6l5 5 .2 .1h17l1.4 1.4v1.1l.2 .3 1.9 1.9M103.9 72l4.8 4.7h16.9l.3 .1 2.1 2.1 .2 .3v1.1l1.4 1.4h5.1l.3 .2 1.6 1.6a1.37 1.37 0 0 1 1.6 1.3 1.37 1.37 0 0 1-1.5 1.4 1.37 1.37 0 0 1-1.2-1.6l-1.3-1.2h-5.1l-.5-.4M104 79.3h1.2"/>
<path d="M104.1 75.9h1.5M104.2 72.2h1.5M104.3 63.2h.2M104.3 79.7h1.3M104.5 68.5h.1M104.5 68.1h.1M104.5 67.7h.1M104.5 66.9h.1M104.5 66.6h.1M104.5 66.2h.1M104.5 76.3h1.5M104.6 72.6h1.5"/>
<path d="M104.6 63.6h.3M104.9 76.7h1.5M104.9 72.9h1.6M105 64h.3M105.1 68.5h2.4M105.1 61.7h6.1M105.1 61.3h6.5M105.1 61h6.9M105.1 60.6h7.3M105.1 60.2h7.1M105.1 66.2h.1M105.2 68.8h2.7"/>
<path d="M105.2 77.1h1.5M105.3 62.1h5.8M105.4 64.3h.3M105.5 68.1h1.6M105.6 66.6h.1M105.6 69.2h2.6M105.6 77.4h1.5M105.6 62.5h5.5M105.7 73.7h1.5M105.7 66.9h.3M105.7 67.7h1M105.7 69.6h2.9"/>
<path d="M105.8 64.7h.2M105.8 70h3.2M106 62.8h5.1M106.1 74.1h1.5M106.1 70.3h3.3M106.1 65.1h.3M106.4 78.2h1.5M106.4 63.2h4.7M106.4 74.4h1.5M106.5 65.5h.3M106.5 70.7h3.2M106.8 78.6h18.6"/>
<path d="M106.8 63.6h4.3M106.8 74.8h1.5M106.9 65.8h.3M106.9 71.1h3.2M107.1 78.9h4M107.2 64h3.9M107.2 75.2h1.5M107.2 71.5h3.2M107.3 66.2h.2M107.5 79.3h2.9M107.5 64.3h3.1M107.6 75.6h1.5"/>
<path d="M107.6 71.8h3.1M107.6 66.6h.3M107.9 79.7h2.3M107.9 64.7h2.7M107.9 75.9h44.3M108 66.9h.3M108 72.2h13.6M108.3 65.1h2.3M108.3 76.3h43.9M108.4 72.6h29.2M108.4 67.3h.3M108.7 65.5h1.9"/>
<path d="M108.7 72.9h28.9M108.8 67.7h.2M109 65.8h1.6M109.1 68.1h.3M109.1 73.3h28.5M109.4 66.2h1.2M109.5 68.5h.3M109.5 73.7h28.2M109.8 66.6h.9M109.9 74.1h28.1M109.9 68.8h15M110.2 66.9h9.5"/>
<path d="M110.2 69.2h21.7M110.5 79.2l.9-.3v1.3h.1v-1.3a1.36 1.36 0 0 1 1.3 1.3h-1.3v.1h1.3a1.33 1.33 0 0 1-1.3 1.4v-1.4h-.1v1.4a1.36 1.36 0 0 1-1.4-1.4h1.4v-.1h-1.4l.1-.4zM110.5 67.3h14.4M110.6 69.6h21M111 70h10.8M111.4 79.7h.1M111.4 79.3h.1M111.4 78.9h.1M111.7 78.9h12.1M112.4 79.3h4.6M112.7 63.2h2.1M112.7 62.8h1.7"/>
<path d="M112.7 64h2.9M112.7 63.6h2.5M112.7 79.7h4M112.8 62.5h1.3M113.1 66.6h1.1M113.1 64.3h1M113.2 66.2h.6M113.2 65.8h.4M113.2 65.5h.4M113.2 65.1h.4M113.2 64.7h.6M113.2 62.1h.7"/>
<path d="M113.9 64.5l.5-.3 .5-.1v1.3v-1.3a1.36 1.36 0 0 1 1.4 1.3h-1.4h1.4a1.37 1.37 0 0 1-1.4 1.4v-1.4v1.4a1.36 1.36 0 0 1-1.3-1.4h1.3h-1.3zM114.9 66.6h.1M114.9 66.2h.1M114.9 65.8h.1M114.9 65.5h.1M114.9 65.1h.1M114.9 64.7h.1M114.9 64.3h.1M115.6 66.6h2.6M115.7 64.3h.2M115.9 61.7h3M116 62.1h2.9"/>
<path d="M116 66.2h1.8M116.1 64.7h.2M116.2 65.8h1.2M116.2 65.1h.5M116.3 65.5h.7M116.3 62.5h2.9M116.4 61.3h2.5M116.7 62.8h2.3M116.7 61h2.2M117 60.6h1.9M117.1 63.2h1.8M117.1 60.2h2"/>
<path d="M117.5 63.6h1.4M117.8 64h1.3M118.2 64.3h1.4M118.6 64.7h7.5M118.8 79.3h4.3M118.9 60.4l.3-.3h1.7l.3 .3v1.7l-.4 .2 .3 .4 .1 .5-1.1 .1h1.1a1.15 1.15 0 0 1-1.1 1.1v-1.1l-.1 1.1a1.15 1.15 0 0 1-1.1-1.1h1.1l-1.1-.1 .1-.4 .3-.5-.4-.2zM119 65.1h.9M119.1 79.7h3.8M120 64.3h.1M120 64h.1M120 63.6h.1M120.5 64.3h5.6"/>
<path d="M120.9 62.5h5.2M121 64h5.1M121 60.2h.8M121.1 62.8h5M121.2 61h1.2M121.2 60.6h.9M121.2 61.7h3.1M121.2 61.3h3.1M121.2 62.1h4.9M121.2 63.6h4.9M121.2 63.2h4.9M122.1 65.1h4"/>
<path d="M122.3 66.9h3M122.6 65.5h3.5M122.6 66.6h3.1M122.7 70h6.8M122.7 66.2h3.4M122.7 65.8h3.4M123 72.2h6.2M123.2 79.2l.9-.3v1.3h.1v-1.3a1.36 1.36 0 0 1 1.3 1.3h-1.3v.1h1.3a1.37 1.37 0 0 1-1.3 1.4v-1.4h-.1v1.4a1.36 1.36 0 0 1-1.4-1.4h1.4v-.1h-1.4l.1-.4zM123.3 70.3h5.6M123.3 71.8h5.5M123.5 70.7h5.2M123.5 71.5h5.2"/>
<path d="M123.5 71.1h5.1M124.1 79.7h.1M124.1 79.3h.1M124.1 78.9h.1M124.4 78.9h1.4M125.1 79.3h1M125.4 79.7h1.1M125.7 76.7h26.5M125.7 68.8h6.6M126.1 68.5h6.6M126.2 77.1h26M126.5 68.1h6.4"/>
<path d="M126.6 77.4h25.6M126.9 67.7h6M126.9 77.8h25.3M127.2 67.3h5.7M127.3 78.2h24.9M127.6 66.9h4.8M127.7 78.6h24.5M127.7 63.2h2M127.7 62.8h1.8M127.7 62.5h1.8M127.7 62.1h1.8M127.7 63.6h2.4"/>
<path d="M127.7 64.3h3.1M127.7 64h2.8M127.7 66.2h4.3M127.7 65.8h4.3M127.7 65.5h4.3M127.7 65.1h3.9M127.7 64.7h3.5M127.7 66.6h4.4M128.1 78.9h8.4M128.2 79.7h1.2M128.2 79.3h1.5M128.6 61.7h.1"/>
<path d="M128.6 61.3h.1M128.6 61h.1M128.6 60.6h.1M128.6 60.2h.1M130.3 70h.9M130.6 72.2h7M131.1 62.1h2.4M131.3 62.5h2.2M131.5 79.3h4.3M131.6 71.8h6M131.6 62.8h1.9M131.8 79.7h3.8"/>
<path d="M132 71.5h5.6M132 63.2h1.7M132.4 63.6h1.7M132.4 71.1h5.3M132.7 70.7h5.3M132.8 64h1.6M132.9 61.7h.6M133 61.3h.5M133.1 70.3h7.7M133.1 64.3h1.7M133.5 64.7h1.7M133.5 70h6.9"/>
<path d="M133.9 69.6h6.1M134.2 69.2h5.5M134.5 68.8h4.8M134.5 67.7h3.7M134.5 67.3h3.3M134.5 68.1h4.1M134.5 68.5h4.4M134.8 65.1h.8M135 66.9h2.4M135.1 61h3.8M135.1 61.3h4.3M135.1 62.1h6.8"/>
<path d="M135.1 61.7h7.1M135.2 60.6h3.5M135.2 62.5h6.3M135.3 65.5h.6M135.3 66.6h1.8M135.4 65.8h.9M135.4 66.2h1.3M135.6 62.8h5.5M135.6 60.2h3M135.9 79.2l.9-.3v1.3v-1.3a1.36 1.36 0 0 1 1.4 1.3h-1.4v.1h1.4a1.37 1.37 0 0 1-1.4 1.4v-1.4v1.4a1.36 1.36 0 0 1-1.4-1.4h1.4v-.1h-1.4l.1-.4zM136 63.2h4.8M136.4 63.6h4"/>
<path d="M136.7 64h2M136.8 79.7h.1M136.8 79.3h.1M136.8 78.9h.1M137.1 64.3h1.6M137.1 78.9h15.1M137.5 64.7h1.2M137.8 79.3h4.6M137.9 65.1h.8M138.1 79.7h4M138.2 65.5h.5M138.6 65.8h.1"/>
<path d="M138.7 72.2h.1M138.7 71.8h.1M138.7 71.5h.1M138.7 71.1h.1M138.7 70.7h.1M139.3 66.6h12.9M139.6 70.7h1M139.7 66.9h12.5M139.9 73.7h.4M139.9 71.1h.4M140 71.5h.2M140 73.3h.2"/>
<path d="M140 72.9h.2M140 72.6h.2M140 72.2h.2M140 71.8h.2M140 61.3h.1M140 61h.1M140 60.6h.1M140 60.2h.1M140.1 67.3h12.1M140.5 67.7h11.7M140.7 61.3h1.9M140.8 68.1h11.4"/>
<path d="M141.2 61h1.8M141.2 68.5h11M141.4 60.6h1.7M141.4 66.2h10.8M141.4 65.8h10.8M141.4 65.5h10.8M141.4 65.1h10.8M141.5 60.2h1.6M141.5 64.7h10.7M141.6 68.8h10.6M141.9 64.3h10.3M142 69.2h10.2"/>
<path d="M142.3 64h9.9M142.4 69.6h9.8M142.7 63.6h9.5M142.7 70h9.5M143.1 63.2h9.1M143.1 70.3h9.1M143.4 62.8h8.8M143.7 75.6h8.5M143.8 62.5h8.4M144.1 75.2h8.1M144.2 62.1h5.8M144.2 79.3h8"/>
<path d="M144.5 74.8h7.7M144.5 79.7h7.7M144.6 61.7h5.1M144.6 70.7h7.6M144.7 74.4h7.5M144.7 74.1h7.5M144.9 71.1h7.3M144.9 73.7h7.3M144.9 61.3h4.6M145 73.3h7.2M145 72.9h7.2M145 72.6h7.2"/>
<path d="M145 72.2h7.2M145 71.8h7.2M145 71.5h7.2M145.3 61h5.5M145.7 60.6h3.8M146.1 60.2h3.6M150.8 62.1h.1M150.8 61.7h.1M150.8 61.3h.1M150.9 61h1.3M151.7 62.1h.5M152 60.2h.2"/>
<path d="M152 61.7h.2M152.2 61.3h.1M152.2 60.6h.1M54.2 85.3h.1M54.2 84.9h.5M54.2 84.6h1.1M54.2 81.2h6.2M54.2 80.8h6.1M54.2 80.4h6M54.2 80.1h6M54.2 81.6h6.5M54.2 81.9h7.1"/>
<path d="M54.2 82.3h8.7M54.2 82.7h9.1M54.2 84.2h13.3M54.2 83.8h13.3M54.2 83.4h13.3M54.2 83.1h13.3M57.9 84.6h9.6M58.2 84.6l.8 .7M58.5 84.9h9M58.8 89.4h88.9M58.9 85.3h8.6M59 85.3l.5 1"/>
<path d="M59.1 89h88.3M59.1 85.7h8.4M59.3 88.7h87.9M59.4 86h8.1M59.5 86.3l.2 1-.2 1.1-.5 .9-.5 .4h89.5l-.5-.4M59.5 88.3h9.6M59.5 86.4h8M59.6 87.9h9.1M59.6 86.8h8M59.6 87.5h8.8M59.7 87.2h8.3M63.7 80.8h2.7"/>
<path d="M63.8 80.4h3M63.8 80.1h3.3M66.7 82.7h.8M67.2 82.3h.3M67.5 81.9h.3M67.9 81.6h.3M68.3 81.2h.2M70.4 84.2h.8M70.4 83.8h.8M70.4 85.3h.9M70.4 84.9h.9M70.4 84.6h.9"/>
<path d="M70.5 83.4h.7M73.5 81.9h6.4M73.6 80.1h4.4M73.6 80.4h4.8M73.6 80.8h5.2M73.6 81.2h5.5M73.6 81.6h5.9M73.6 85.3h7.2M73.6 84.9h7.2M73.6 84.6h7.2M73.6 83.1h7.2M73.6 82.7h7.2"/>
<path d="M73.6 82.3h7.2M73.7 84.2h7.1M73.7 83.8h7.1M73.7 83.4h7.1M80.3 80.1h.5M80.7 80.4h.1M82 83.8h-1.2v1.3h1.2M82 83.8v1.3M82 84.9h.1M82 84.6h.1M82 84.2h.1M83.1 83.2l.1 .6h-1.2"/>
<path d="M83.1 82.7h1.4M83.1 82.3h1.2M83.1 80.4h1.4M83.1 83.1h1.9M83.1 80.1h1.8M83.2 84.6h1M83.2 84.9h1.1M83.2 84.2h1M83.2 83.8h1.2M83.2 85.3h1.3M83.2 83.4h1.5M85.4 84.2h.1"/>
<path d="M85.4 83.8h.1M85.4 83.4h.1M85.9 83.1h3.7M86.2 83.4h3M86.4 85.3h.3M86.5 82.7h6M86.5 80.8h6.3M86.5 81.2h6.8M86.6 83.8h2.2M86.6 82.3h5.9M86.6 81.6h6.3M86.7 84.9h.2"/>
<path d="M86.7 81.9h5.9M86.7 84.2h1.7M86.7 84.6h.6M86.8 80.4h5.7M87.2 80.1h5.3M94.2 81.2h6.7M94.5 81.6h6.1M94.7 80.8h5.7M94.8 88.3h52.2M94.9 80.4h5.3M95 80.1h5.1M95.2 81.9h5.1"/>
<path d="M95.2 87.9h51.7M95.6 82.3h4.5M95.6 87.5h51.2M96 82.7h4.1M96 87.2h50.8M96.1 82.8l-1-.9-.4-.2a1.24 1.24 0 0 0-1.6-.2 1.24 1.24 0 0 0-.5 1.5h-2.8l-.3 .1-1.3 1.3a1.29 1.29 0 0 0-1.5 1.2h-.5l.5-.7v-.4l-1.2-.1h1.2a1.25 1.25 0 0 0-1.2-1.2v1.2l-.1-1.2a1.25 1.25 0 0 0-1.2 1.2h1.2l-1.2 .1 .1 .4 .5 .7h-1.6v-.5h-1.2M96.3 83.1h3.9M96.3 86.8h50.6M96.4 85.3h3.7M96.4 86h3.7M96.4 85.7h3.7M96.4 84.9h3.7"/>
<path d="M96.4 84.6h3.7M96.4 84.2h3.7M96.4 83.4h4M96.4 83.8h9.8M96.4 86.4h50.6M100.3 83.8h2l.3 .3v2l-.3 .2h-2l-.2-.2v-2zM101.8 81.2h1.7M102.1 81.6h1.8M102.2 83.4h3.6M102.3 80.8h.9M102.4 81.9h1.9M102.5 83.1h2.9"/>
<path d="M102.5 80.4h.3M102.6 82.3h2.1M102.6 82.7h2.4M102.6 84.2h3.9M102.6 84.6h4.3M102.6 85.3h5.1M102.6 84.9h4.7M102.6 86h8.3M102.6 85.7h7.8M104.7 80.1h1.2M105.1 80.4h1.2M105.5 80.8h1.2"/>
<path d="M105.8 81.2h1.3M106.2 81.6h1.2M106.6 81.9h1.2M107 82.3h1.2M107.3 82.7h1.3M107.7 83.1h1.2M108.1 83.4h13.5M108.2 80.1h1.8M108.5 83.8h2M108.6 80.4h1.4M109 80.8h1.1M109.4 81.2h.9"/>
<path d="M109.7 81.6h1.1M111.4 81.6h.1M111.4 81.2h.1M111.4 80.8h.1M111.4 80.4h.1M111.4 80.1h.1M111.9 86h5.5M112 81.6h5.4M112.3 83.8h4.7M112.5 85.7h4.4M112.5 81.2h4.4M112.6 84.2h4.1"/>
<path d="M112.7 85.3h4M112.7 80.8h4M112.8 84.9h3.8M112.8 84.6h3.8M112.8 80.1h3.8M112.8 80.4h3.8M118.4 81.6h5.1M118.4 86h5.2M118.8 83.8h3.1M118.9 81.2h4.1M119 85.7h4.1M119.1 84.2h3.2"/>
<path d="M119.2 80.8h3.6M119.2 85.3h3.7M119.3 84.6h3.4M119.3 80.4h3.4M119.3 80.1h3.4M119.3 84.9h3.5M122.4 81.9h5.1M122.8 82.3h5.1M123.1 82.7h5.1M123.5 83.1h5.1M123.9 83.4h10.4M124.1 81.6h.1"/>
<path d="M124.1 81.2h.1M124.1 80.8h.1M124.1 80.4h.1M124.1 80.1h.1M124.6 86h5.5M124.7 81.6h2.4M125 83.8h4.7M125.1 85.7h4.5M125.2 81.2h1.6M125.3 84.2h4.1M125.4 85.3h4M125.4 80.8h1.1"/>
<path d="M125.5 84.9h3.8M125.5 84.6h3.8M125.5 80.1h1M125.5 80.4h1M128.2 80.1h1.1M128.3 80.4h1M128.7 80.8h.7M129 81.2h.6M129.4 81.6h.7M131.1 81.6h5.1M131.1 86h5.2M131.5 83.8h3.1"/>
<path d="M131.6 81.2h4.1M131.6 85.7h4.2M131.8 84.2h3.2M131.9 85.3h3.7M131.9 80.8h3.6M132 84.6h3.4M132 80.4h3.4M132 80.1h3.4M132 84.9h3.5M135.1 81.9h17.1M135.5 82.3h16.7M135.8 82.7h16.4"/>
<path d="M136.2 83.1h16M136.6 83.4h15.6M136.8 81.6h.1M136.8 81.2h.1M136.8 80.8h.1M136.8 80.4h.1M136.8 80.1h.1M137.3 86h5.5M137.4 81.6h5.4M137.7 83.8h4.7M137.8 85.7h4.5M137.9 81.2h4.4"/>
<path d="M138 84.2h4.1M138.1 85.3h4M138.1 80.8h4M138.2 84.9h3.7M138.2 84.6h3.7M138.2 80.1h3.7M138.2 80.4h3.7M143.8 81.6h8.4M143.8 86h3.3M144.2 83.8h8M144.3 81.2h7.9M144.3 85.7h3"/>
<path d="M144.5 84.2h7.7M144.6 85.3h3M144.6 80.8h7.6M144.7 84.9h3.3M144.7 84.6h3.9M144.7 80.4h7.5M144.7 80.1h7.5M147 86.3a3.2 3.2 0 0 0 .5 3M147.5 85.3l-.5 1M147.5 89.3h.1M151.2 84.6h1M151.8 84.9h.4"/>
<path d="M152.2 85.3h.1"/>
<circle cx="77.2" cy="49.6" r="1.37"/>
<circle cx="80.8" cy="49.6" r="1.13"/>
<circle cx="84.4" cy="49.6" r="1.13"/>
<circle cx="101.3" cy="54.6" r="1.28"/>
<circle cx="101.3" cy="57.2" r="1.27"/>
<circle cx="101.3" cy="59.7" r="1.27"/>
<circle cx="110" cy="56.4" r="2.59"/>
<circle cx="121.3" cy="50.8" r="1.37"/>
<circle cx="62" cy="67.1" r="1.83"/>
<circle cx="80.1" cy="71.1" r="1.37"/>
<circle cx="93.7" cy="74.9" r="1.27"/>
<circle cx="93.7" cy="77.5" r="1.27"/>
<circle cx="93.7" cy="72.4" r="1.27"/>
<circle cx="101.3" cy="62.2" r="1.27"/>
<circle cx="101.3" cy="64.8" r="1.27"/>
<circle cx="93.7" cy="80" r="1.27"/>
<circle cx="101.3" cy="82.6" r="1.27"/>
<circle cx="117.9" cy="80.3" r="1.37"/>
<circle cx="117.9" cy="84.8" r="1.37"/>
<circle cx="130.6" cy="80.3" r="1.38"/>
<circle cx="130.6" cy="84.8" r="1.38"/>
<circle cx="143.3" cy="80.3" r="1.38"/>
<circle cx="143.3" cy="84.8" r="1.38"/>
</g>
<g fill="none" stroke="#800000" stroke-width=".83">
<path d="M67.1 59.1l3.1 3.1v11.5h2.3M74.7 59.1l4.4 4.4h1M114.7 59.4v2.5l4.1 4.2h2.2M115.3 59.4h-.6l-2.8 2.8v3.2M121.3 58.4l1.7 2h2.2M140 54.6l3.9 3.8v2.8M150.8 58.4h-4.1l-6.7 6.7v-.6M150.8 53.4h-6.9l-1.3-1.3h-4.4l-1 .9v4.5l-2.9 2.9M62 73.7h7.9M69 73.7l.9 .9v.3M69.9 74.9v3.2l.7 .6h4.1l1.3 1.3v3.8M69.9 73.7v.9"/>
<path d="M69.9 76.5l1 1h1.5M69.9 74.9l1.3 1.3h1.2M69.9 73.7h.3l1.3 1.2h.9M82 77.5h1.6l.6-.7v-5.3l1.6-1.6h9.5l2.2 2.2v13.6l2.2 2.2h38.5l1.8-1.9v-2.5l-3.2-3.2M84.2 74.3l-.6 .6h-1.6M84.2 75.6l-.6 .6h-1.6M84.2 73l-.6 .7h-1.6M88 69.9v2.8M90.9 78.1h-2.9l-3.2 3.2M101.3 74.9h.7l7.6 7.6h12.2l2.3 2.3M101.3 72.4h1.9l5.1 5.1h17.2l1.9 1.9v1.2l1.9 1.9h5.2l2.3 2.3M101.3 67.3h3.2l5.7 5.7h28l.6-.6"/>
<path d="M101.3 77.5h-.3l7.3 7.3h3.1M111.2 71.1h11.1M126.9 60.4v6.1l-1.6 1.6M128.6 60.4v7.6l-2.4 2.4v2.5l.2 .1M130.3 60.4v2.3l3.4 3.4v2.5l-2.5 2.5h-1.3M132 60.4h2.3M134.3 60.4v2.3l9.6 9.5v2.1l-.7 .6h-33.6l-5.1-5h-5.7l-5.1-5.1h-1.3l-3.1 3.2h-10.2l-1.9 1.9v8.2l3.2 3.2h4.4M72.4 80h-4.1l-1.9 1.9h-2.8l-1.6-1.6M72.4 82.5h-2.2l-.6 .7v2.5l.6 .7h17.2l2.5-2.6h2.5l1.3 1.3M72.4 83.8h12l.7 .7h.4M72.4 81.3h-2.8l-1.3 1.2v3.9l1.3 1.2h24.7l1.3-1.2v-2.9l-.9-1h-1M84.2 83.8l-1.3 1.3h-.9"/>
<path d="M84.8 81.3l.7 .6M90.9 85.7l1.9 1.9"/>
</g>
<g fill="none" stroke="#800000" stroke-width=".32">
<path d="M69.6 49.5l6.7 6.8h3.8M80.1 59.1h5.9l.7 .6M82.6 57.5l.3 .3h2.6M86.1 56.8v-3.4l-.5-.5h-2l-3.5 3.5v3.9M88 58.4l-1.3 1.3v3.8h1.9l.1-.9M88 56.8v1.6M88.7 56.8v1l-.7 .6M93.7 57.2l-1.9 1.9h-1.9l-2.5 2.5v1M93.7 59.7h-3.7l-2 2v.9M93.7 54.6l1.6 1.6v3.8l-1 1h-4.4l-.6 .6v2.2l-1.3 1.3M102.2 50.7h-10.1l-4.7 4.8v2.3l-.4 .3h-1.2l-.4-.3v-1M104.5 51.8l-1.9-1.9h-11.1l-4.8 4.8v2.1"/>
<path d="M81.6 67.9l.1 .1M82.6 60.3h1.9l.9 1 .1 6.7M93.7 62.2l-4.8 4.8h-2.8v-4.4"/>
</g>
<path d="M103.2 51.8v11.4M104.5 62.2l5.9 5.9h.1" fill="none" stroke="#800000" stroke-width=".51"/>
<path d="M103.2 63.2l8 7.9M110.5 68.1h14.8" fill="none" stroke="#800000" stroke-width=".61"/>
<circle cx="120.1" cy="63.3" r=".7" fill="#008000" stroke="#008000" stroke-width=".18"/>
<circle cx="120.1" cy="63.3" r=".44" fill="#fff" stroke="#000" stroke-width=".18"/>
<path d="M119.4 60.5h1.4v1.4h-1.4z" fill="#008000" stroke="#008000" stroke-width=".18"/>
<circle cx="120.1" cy="61.2" r=".44" fill="#fff" stroke="#000" stroke-width=".18"/>
<path d="M111 64.5h1.8v1.8h-1.8z" fill="#008000" stroke="#008000" stroke-width=".18"/>
<circle cx="111.9" cy="65.4" r=".44" fill="#fff" stroke="#000" stroke-width=".18"/>
<circle cx="114.9" cy="65.4" r=".89" fill="#008000" stroke="#008000" stroke-width=".18"/>
<circle cx="114.9" cy="65.4" r=".44" fill="#fff" stroke="#000" stroke-width=".18"/>
<circle cx="140" cy="60.1" r=".97" fill="#008000" stroke="#008000" stroke-width=".18"/>
<circle cx="140" cy="60.1" r=".44" fill="#fff" stroke="#000" stroke-width=".18"/>
<path d="M139.1 64.1h1.9v1.9h-1.9z" fill="#008000" stroke="#008000" stroke-width=".18"/>
<circle cx="140" cy="65.1" r=".44" fill="#fff" stroke="#000" stroke-width=".18"/>
<circle cx="140" cy="49.6" r=".97" fill="#008000" stroke="#008000" stroke-width=".18"/>
<circle cx="140" cy="49.6" r=".44" fill="#fff" stroke="#000" stroke-width=".18"/>
<path d="M139.1 53.6h1.9v2h-1.9z" fill="#008000" stroke="#008000" stroke-width=".18"/>
<circle cx="140" cy="54.6" r=".44" fill="#fff" stroke="#000" stroke-width=".18"/>
<circle cx="122.3" cy="71.1" r=".85" fill="#008000" stroke="#008000" stroke-width=".18"/>
<circle cx="122.3" cy="71.1" r=".55" fill="#fff" stroke="#000" stroke-width=".18"/>
<circle cx="129.9" cy="71.1" r=".85" fill="#008000" stroke="#008000" stroke-width=".18"/>
<circle cx="129.9" cy="71.1" r=".55" fill="#fff" stroke="#000" stroke-width=".18"/>
<path d="M133 66.1h1.4" fill="none" stroke="#008000" stroke-width="1.3"/>
<circle cx="133.7" cy="66.1" r=".4" fill="#fff" stroke="#000" stroke-width=".18"/>
<path d="M120.4 66.1h1.3" fill="none" stroke="#008000" stroke-width="1.3"/>
<circle cx="121" cy="66.1" r=".4" fill="#fff" stroke="#000" stroke-width=".18"/>
<circle cx="121.3" cy="50.8" r=".93" fill="#008000" stroke="#008000" stroke-width=".18"/>
<circle cx="121.3" cy="50.8" r=".44" fill="#fff" stroke="#000" stroke-width=".18"/>
<circle cx="121.3" cy="58.4" r=".93" fill="#008000" stroke="#008000" stroke-width=".18"/>
<circle cx="121.3" cy="58.4" r=".44" fill="#fff" stroke="#000" stroke-width=".18"/>
<circle cx="114.7" cy="59.4" r="2.16" fill="#008000" stroke="#008000" stroke-width=".18"/>
<circle cx="114.7" cy="59.4" r="1.5" fill="#fff" stroke="#000" stroke-width=".18"/>
<circle cx="114.7" cy="53.4" r="2.16" fill="#008000" stroke="#008000" stroke-width=".18"/>
<circle cx="114.7" cy="53.4" r="1.5" fill="#fff" stroke="#000" stroke-width=".18"/>
<circle cx="110" cy="56.4" r="2.16" fill="#008000" stroke="#008000" stroke-width=".18"/>
<circle cx="110" cy="56.5" r="1.5" fill="#fff" stroke="#000" stroke-width=".18"/>
<circle cx="150.8" cy="61" r=".93" fill="#008000" stroke="#008000" stroke-width=".18"/>
<circle cx="150.8" cy="61" r=".51" fill="#fff" stroke="#000" stroke-width=".18"/>
<circle cx="150.8" cy="58.4" r=".93" fill="#008000" stroke="#008000" stroke-width=".18"/>
<circle cx="150.8" cy="58.4" r=".51" fill="#fff" stroke="#000" stroke-width=".18"/>
<circle cx="150.8" cy="55.9" r=".93" fill="#008000" stroke="#008000" stroke-width=".18"/>
<circle cx="150.8" cy="55.9" r=".51" fill="#fff" stroke="#000" stroke-width=".18"/>
<circle cx="150.8" cy="53.4" r=".93" fill="#008000" stroke="#008000" stroke-width=".18"/>
<circle cx="150.8" cy="53.4" r=".51" fill="#fff" stroke="#000" stroke-width=".18"/>
<circle cx="55.6" cy="61" r=".93" fill="#008000" stroke="#008000" stroke-width=".18"/>
<circle cx="55.6" cy="61" r=".51" fill="#fff" stroke="#000" stroke-width=".18"/>
<circle cx="55.6" cy="58.4" r=".93" fill="#008000" stroke="#008000" stroke-width=".18"/>
<circle cx="55.6" cy="58.4" r=".51" fill="#fff" stroke="#000" stroke-width=".18"/>
<circle cx="55.6" cy="55.9" r=".93" fill="#008000" stroke="#008000" stroke-width=".18"/>
<circle cx="55.6" cy="55.9" r=".51" fill="#fff" stroke="#000" stroke-width=".18"/>
<circle cx="55.6" cy="53.4" r=".93" fill="#008000" stroke="#008000" stroke-width=".18"/>
<circle cx="55.6" cy="53.4" r=".51" fill="#fff" stroke="#000" stroke-width=".18"/>
<circle cx="84.4" cy="49.5" r=".7" fill="#008000" stroke="#008000" stroke-width=".18"/>
<circle cx="84.4" cy="49.5" r=".4" fill="#fff" stroke="#000" stroke-width=".18"/>
<circle cx="80.8" cy="49.5" r=".7" fill="#008000" stroke="#008000" stroke-width=".18"/>
<circle cx="80.8" cy="49.5" r=".4" fill="#fff" stroke="#000" stroke-width=".18"/>
<circle cx="69.6" cy="49.5" r=".93" fill="#008000" stroke="#008000" stroke-width=".18"/>
<circle cx="69.6" cy="49.5" r=".44" fill="#fff" stroke="#000" stroke-width=".18"/>
<circle cx="77.2" cy="49.5" r=".93" fill="#008000" stroke="#008000" stroke-width=".18"/>
<circle cx="77.2" cy="49.5" r=".44" fill="#fff" stroke="#000" stroke-width=".18"/>
<circle cx="124.1" cy="80.3" r=".93" fill="#008000" stroke="#008000" stroke-width=".18"/>
<circle cx="124.1" cy="80.3" r=".51" fill="#fff" stroke="#000" stroke-width=".18"/>
<circle cx="130.6" cy="80.3" r=".93" fill="#008000" stroke="#008000" stroke-width=".18"/>
<circle cx="130.6" cy="80.3" r=".51" fill="#fff" stroke="#000" stroke-width=".18"/>
<circle cx="124.1" cy="84.8" r=".93" fill="#008000" stroke="#008000" stroke-width=".18"/>
<circle cx="124.1" cy="84.8" r=".51" fill="#fff" stroke="#000" stroke-width=".18"/>
<circle cx="130.6" cy="84.8" r=".93" fill="#008000" stroke="#008000" stroke-width=".18"/>
<circle cx="130.6" cy="84.8" r=".51" fill="#fff" stroke="#000" stroke-width=".18"/>
<path d="M138.8 71.6v1.6" fill="none" stroke="#008000" stroke-width="1.5"/>
<circle cx="138.8" cy="72.4" r=".51" fill="#fff" stroke="#000" stroke-width=".18"/>
<path d="M141.3 71.6v1.6" fill="none" stroke="#008000" stroke-width="1.5"/>
<circle cx="141.3" cy="72.4" r=".51" fill="#fff" stroke="#000" stroke-width=".18"/>
<path d="M143.9 71.6v1.6" fill="none" stroke="#008000" stroke-width="1.5"/>
<circle cx="143.9" cy="72.4" r=".51" fill="#fff" stroke="#000" stroke-width=".18"/>
<circle cx="136.8" cy="80.3" r=".93" fill="#008000" stroke="#008000" stroke-width=".18"/>
<circle cx="136.8" cy="80.3" r=".51" fill="#fff" stroke="#000" stroke-width=".18"/>
<circle cx="143.3" cy="80.3" r=".93" fill="#008000" stroke="#008000" stroke-width=".18"/>
<circle cx="143.3" cy="80.3" r=".51" fill="#fff" stroke="#000" stroke-width=".18"/>
<circle cx="136.8" cy="84.8" r=".93" fill="#008000" stroke="#008000" stroke-width=".18"/>
<circle cx="136.8" cy="84.8" r=".51" fill="#fff" stroke="#000" stroke-width=".18"/>
<circle cx="143.3" cy="84.8" r=".93" fill="#008000" stroke="#008000" stroke-width=".18"/>
<circle cx="143.3" cy="84.8" r=".51" fill="#fff" stroke="#000" stroke-width=".18"/>
<circle cx="111.4" cy="80.3" r=".93" fill="#008000" stroke="#008000" stroke-width=".18"/>
<circle cx="111.4" cy="80.3" r=".51" fill="#fff" stroke="#000" stroke-width=".18"/>
<circle cx="117.9" cy="80.3" r=".93" fill="#008000" stroke="#008000" stroke-width=".18"/>
<circle cx="117.9" cy="80.3" r=".51" fill="#fff" stroke="#000" stroke-width=".18"/>
<circle cx="111.4" cy="84.8" r=".93" fill="#008000" stroke="#008000" stroke-width=".18"/>
<circle cx="111.4" cy="84.8" r=".51" fill="#fff" stroke="#000" stroke-width=".18"/>
<circle cx="117.9" cy="84.8" r=".93" fill="#008000" stroke="#008000" stroke-width=".18"/>
<circle cx="117.9" cy="84.8" r=".51" fill="#fff" stroke="#000" stroke-width=".18"/>
<circle cx="67.1" cy="59.1" r="1.17" fill="#008000" stroke="#008000" stroke-width=".18"/>
<circle cx="67.1" cy="59.1" r=".51" fill="#fff" stroke="#000" stroke-width=".18"/>
<circle cx="74.7" cy="59.1" r="1.17" fill="#008000" stroke="#008000" stroke-width=".18"/>
<circle cx="74.7" cy="59.1" r=".51" fill="#fff" stroke="#000" stroke-width=".18"/>
<circle cx="80.1" cy="63.5" r=".93" fill="#008000" stroke="#008000" stroke-width=".18"/>
<circle cx="80.1" cy="63.5" r=".44" fill="#fff" stroke="#000" stroke-width=".18"/>
<circle cx="80.1" cy="71.1" r=".93" fill="#008000" stroke="#008000" stroke-width=".18"/>
<circle cx="80.1" cy="71.1" r=".44" fill="#fff" stroke="#000" stroke-width=".18"/>
<path d="M100.5 84.2h1.7v1.7h-1.7z" fill="#008000" stroke="#008000" stroke-width=".18"/>
<circle cx="101.3" cy="85.1" r=".55" fill="#fff" stroke="#000" stroke-width=".18"/>
<circle cx="101.3" cy="82.5" r=".85" fill="#008000" stroke="#008000" stroke-width=".18"/>
<circle cx="101.3" cy="82.5" r=".55" fill="#fff" stroke="#000" stroke-width=".18"/>
<circle cx="101.3" cy="80" r=".85" fill="#008000" stroke="#008000" stroke-width=".18"/>
<circle cx="101.3" cy="80" r=".55" fill="#fff" stroke="#000" stroke-width=".18"/>
<circle cx="101.3" cy="77.5" r=".85" fill="#008000" stroke="#008000" stroke-width=".18"/>
<circle cx="101.3" cy="77.5" r=".55" fill="#fff" stroke="#000" stroke-width=".18"/>
<circle cx="101.3" cy="74.9" r=".85" fill="#008000" stroke="#008000" stroke-width=".18"/>
<circle cx="101.3" cy="74.9" r=".55" fill="#fff" stroke="#000" stroke-width=".18"/>
<circle cx="101.3" cy="72.4" r=".85" fill="#008000" stroke="#008000" stroke-width=".18"/>
<circle cx="101.3" cy="72.4" r=".55" fill="#fff" stroke="#000" stroke-width=".18"/>
<circle cx="101.3" cy="69.9" r=".85" fill="#008000" stroke="#008000" stroke-width=".18"/>
<circle cx="101.3" cy="69.9" r=".55" fill="#fff" stroke="#000" stroke-width=".18"/>
<circle cx="101.3" cy="67.3" r=".85" fill="#008000" stroke="#008000" stroke-width=".18"/>
<circle cx="101.3" cy="67.3" r=".55" fill="#fff" stroke="#000" stroke-width=".18"/>
<circle cx="101.3" cy="64.8" r=".85" fill="#008000" stroke="#008000" stroke-width=".18"/>
<circle cx="101.3" cy="64.8" r=".55" fill="#fff" stroke="#000" stroke-width=".18"/>
<circle cx="101.3" cy="62.2" r=".85" fill="#008000" stroke="#008000" stroke-width=".18"/>
<circle cx="101.3" cy="62.2" r=".55" fill="#fff" stroke="#000" stroke-width=".18"/>
<circle cx="101.3" cy="59.7" r=".85" fill="#008000" stroke="#008000" stroke-width=".18"/>
<circle cx="101.3" cy="59.7" r=".55" fill="#fff" stroke="#000" stroke-width=".18"/>
<circle cx="101.3" cy="57.2" r=".85" fill="#008000" stroke="#008000" stroke-width=".18"/>
<circle cx="101.3" cy="57.2" r=".55" fill="#fff" stroke="#000" stroke-width=".18"/>
<circle cx="101.3" cy="54.6" r=".85" fill="#008000" stroke="#008000" stroke-width=".18"/>
<circle cx="101.3" cy="54.6" r=".55" fill="#fff" stroke="#000" stroke-width=".18"/>
<circle cx="101.3" cy="52.1" r=".85" fill="#008000" stroke="#008000" stroke-width=".18"/>
<circle cx="101.3" cy="52.1" r=".55" fill="#fff" stroke="#000" stroke-width=".18"/>
<circle cx="93.7" cy="52.1" r=".85" fill="#008000" stroke="#008000" stroke-width=".18"/>
<circle cx="93.7" cy="52.1" r=".55" fill="#fff" stroke="#000" stroke-width=".18"/>
<circle cx="93.7" cy="54.6" r=".85" fill="#008000" stroke="#008000" stroke-width=".18"/>
<circle cx="93.7" cy="54.6" r=".55" fill="#fff" stroke="#000" stroke-width=".18"/>
<circle cx="93.7" cy="57.2" r=".85" fill="#008000" stroke="#008000" stroke-width=".18"/>
<circle cx="93.7" cy="57.2" r=".55" fill="#fff" stroke="#000" stroke-width=".18"/>
<circle cx="93.7" cy="59.7" r=".85" fill="#008000" stroke="#008000" stroke-width=".18"/>
<circle cx="93.7" cy="59.7" r=".55" fill="#fff" stroke="#000" stroke-width=".18"/>
<circle cx="93.7" cy="62.2" r=".85" fill="#008000" stroke="#008000" stroke-width=".18"/>
<circle cx="93.7" cy="62.2" r=".55" fill="#fff" stroke="#000" stroke-width=".18"/>
<circle cx="93.7" cy="64.8" r=".85" fill="#008000" stroke="#008000" stroke-width=".18"/>
<circle cx="93.7" cy="64.8" r=".55" fill="#fff" stroke="#000" stroke-width=".18"/>
<circle cx="93.7" cy="67.3" r=".85" fill="#008000" stroke="#008000" stroke-width=".18"/>
<circle cx="93.7" cy="67.3" r=".55" fill="#fff" stroke="#000" stroke-width=".18"/>
<circle cx="93.7" cy="69.9" r=".85" fill="#008000" stroke="#008000" stroke-width=".18"/>
<circle cx="93.7" cy="69.9" r=".55" fill="#fff" stroke="#000" stroke-width=".18"/>
<circle cx="93.7" cy="72.4" r=".85" fill="#008000" stroke="#008000" stroke-width=".18"/>
<circle cx="93.7" cy="72.4" r=".55" fill="#fff" stroke="#000" stroke-width=".18"/>
<circle cx="93.7" cy="74.9" r=".85" fill="#008000" stroke="#008000" stroke-width=".18"/>
<circle cx="93.7" cy="74.9" r=".55" fill="#fff" stroke="#000" stroke-width=".18"/>
<circle cx="93.7" cy="77.5" r=".85" fill="#008000" stroke="#008000" stroke-width=".18"/>
<circle cx="93.7" cy="77.5" r=".55" fill="#fff" stroke="#000" stroke-width=".18"/>
<circle cx="93.7" cy="80" r=".85" fill="#008000" stroke="#008000" stroke-width=".18"/>
<circle cx="93.7" cy="80" r=".55" fill="#fff" stroke="#000" stroke-width=".18"/>
<circle cx="93.7" cy="82.5" r=".85" fill="#008000" stroke="#008000" stroke-width=".18"/>
<circle cx="93.7" cy="82.5" r=".55" fill="#fff" stroke="#000" stroke-width=".18"/>
<circle cx="93.7" cy="85.1" r=".85" fill="#008000" stroke="#008000" stroke-width=".18"/>
<circle cx="93.7" cy="85.1" r=".55" fill="#fff" stroke="#000" stroke-width=".18"/>
<circle cx="62" cy="80.3" r="1.4" fill="#008000" stroke="#008000" stroke-width=".18"/>
<circle cx="62" cy="80.3" r=".93" fill="#fff" stroke="#000" stroke-width=".18"/>
<circle cx="62" cy="67.1" r="1.4" fill="#008000" stroke="#008000" stroke-width=".18"/>
<circle cx="62" cy="67.1" r=".93" fill="#fff" stroke="#000" stroke-width=".18"/>
<circle cx="105.1" cy="48.3" r=".93" fill="#008000" stroke="#008000" stroke-width=".18"/>
<circle cx="105.1" cy="48.3" r=".51" fill="#fff" stroke="#000" stroke-width=".18"/>
<circle cx="102.6" cy="48.3" r=".93" fill="#008000" stroke="#008000" stroke-width=".18"/>
<circle cx="102.6" cy="48.3" r=".51" fill="#fff" stroke="#000" stroke-width=".18"/>
<circle cx="100.1" cy="48.3" r=".93" fill="#008000" stroke="#008000" stroke-width=".18"/>
<circle cx="100.1" cy="48.3" r=".51" fill="#fff" stroke="#000" stroke-width=".18"/>
<circle cx="97.5" cy="48.3" r=".93" fill="#008000" stroke="#008000" stroke-width=".18"/>
<circle cx="97.5" cy="48.3" r=".51" fill="#fff" stroke="#000" stroke-width=".18"/>
<circle cx="95" cy="48.3" r=".93" fill="#008000" stroke="#008000" stroke-width=".18"/>
<circle cx="95" cy="48.3" r=".51" fill="#fff" stroke="#000" stroke-width=".18"/>
<circle cx="88" cy="72.7" r=".93" fill="#008000" stroke="#008000" stroke-width=".18"/>
<circle cx="88" cy="72.7" r=".44" fill="#fff" stroke="#000" stroke-width=".18"/>
<circle cx="88" cy="65.1" r=".93" fill="#008000" stroke="#008000" stroke-width=".18"/>
<circle cx="88" cy="65.1" r=".44" fill="#fff" stroke="#000" stroke-width=".18"/>
<circle cx="88" cy="85.7" r=".93" fill="#008000" stroke="#008000" stroke-width=".18"/>
<circle cx="88" cy="85.7" r=".44" fill="#fff" stroke="#000" stroke-width=".18"/>
<circle cx="88" cy="78.1" r=".93" fill="#008000" stroke="#008000" stroke-width=".18"/>
<circle cx="88" cy="78.1" r=".44" fill="#fff" stroke="#000" stroke-width=".18"/>
<circle cx="90.9" cy="78.1" r=".93" fill="#008000" stroke="#008000" stroke-width=".18"/>
<circle cx="90.9" cy="78.1" r=".44" fill="#fff" stroke="#000" stroke-width=".18"/>
<circle cx="90.9" cy="85.7" r=".93" fill="#008000" stroke="#008000" stroke-width=".18"/>
<circle cx="90.9" cy="85.7" r=".44" fill="#fff" stroke="#000" stroke-width=".18"/>
<circle cx="85.5" cy="81.9" r=".83" fill="#008000" stroke="#008000" stroke-width=".18"/>
<circle cx="85.5" cy="81.9" r=".44" fill="#fff" stroke="#000" stroke-width=".18"/>
<circle cx="85.5" cy="84.5" r=".83" fill="#008000" stroke="#008000" stroke-width=".18"/>
<circle cx="85.5" cy="84.5" r=".44" fill="#fff" stroke="#000" stroke-width=".18"/>
<circle cx="82.6" cy="60.3" r=".83" fill="#008000" stroke="#008000" stroke-width=".18"/>
<circle cx="82.6" cy="60.3" r=".44" fill="#fff" stroke="#000" stroke-width=".18"/>
<circle cx="80.1" cy="60.3" r=".83" fill="#008000" stroke="#008000" stroke-width=".18"/>
<circle cx="80.1" cy="60.3" r=".44" fill="#fff" stroke="#000" stroke-width=".18"/>
<circle cx="82.6" cy="57.5" r=".83" fill="#008000" stroke="#008000" stroke-width=".18"/>
<circle cx="82.6" cy="57.5" r=".44" fill="#fff" stroke="#000" stroke-width=".18"/>
<circle cx="80.1" cy="57.5" r=".83" fill="#008000" stroke="#008000" stroke-width=".18"/>
<circle cx="80.1" cy="57.5" r=".44" fill="#fff" stroke="#000" stroke-width=".18"/>
<circle cx="104.5" cy="67.3" r=".83" fill="#008000" stroke="#008000" stroke-width=".18"/>
<circle cx="104.5" cy="67.3" r=".44" fill="#fff" stroke="#000" stroke-width=".18"/>
<circle cx="104.5" cy="69.9" r=".83" fill="#008000" stroke="#008000" stroke-width=".18"/>
<circle cx="104.5" cy="69.9" r=".44" fill="#fff" stroke="#000" stroke-width=".18"/>
<g fill="#800000" stroke="#800000" stroke-width=".18">
<path d="M54.3 85.5a2.88 2.88 0 0 1 4.7 .1 2.88 2.88 0 0 1-1.5 4.4 2.88 2.88 0 0 1-3.8-2.7h2.5a.35 .35 0 0 1 .5-.4 .35 .35 0 0 1 .1 .6 .35 .35 0 0 1-.6-.1l-2.5-.1 .1-.6z" fill-rule="evenodd"/>
<path d="M54.3 45.8a2.89 2.89 0 0 1 4.7 .2 2.89 2.89 0 0 1-1.5 4.4 2.89 2.89 0 0 1-3.8-2.8h2.5a.35 .35 0 0 1 .5-.3 .35 .35 0 0 1 .1 .5 .35 .35 0 0 1-.6-.1l-2.5-.1 .1-.6z" fill-rule="evenodd"/>
<path d="M147.6 45.8a2.88 2.88 0 0 1 4.7 .2 2.88 2.88 0 0 1-1.6 4.4 2.88 2.88 0 0 1-3.7-2.8h2.5a.35 .35 0 0 1 .6-.2 .35 .35 0 0 1 0 .6 .35 .35 0 0 1-.6-.3l-2.5-.1 .3-1.2z" fill-rule="evenodd"/>
<path d="M148.1 85a2.89 2.89 0 0 1 4.4 1 2.89 2.89 0 0 1-2 4.1 2.89 2.89 0 0 1-3.5-2.8h2.5a.35 .35 0 0 1 .6-.2 .35 .35 0 0 1 0 .6 .35 .35 0 0 1-.6-.3l-2.5-.1a2.87 2.87 0 0 1 1.1-2.3z" fill-rule="evenodd"/>
</g>
<g fill="none" stroke="#505050" stroke-width=".18">
<path d="M72.7 50.7l.1-.1v.5M72.7 51.1h.3M73 48.3h.1M73.1 48.3l.2-.2-.3-.1v.5M73.2 48.3l.1 .2M73.3 50.7a.2 .2 0 0 1 .2 .2 .2 .2 0 0 1-.2 .2zM73.5 50.7l-.2 .3M73.6 48l-.1 .4h.3M73.7 48.3v.2M73.8 50.6v.5M73.9 50.8l.2 .3M74.1 50.6l-.3 .3"/>
<path d="M74.3 56.5h.8M74.7 56.2v.7M80.4 58.8a.2 .2 0 0 1 .2 .2 .2 .2 0 0 1-.3 .2zM80.4 56a.2 .2 0 0 1 .2 .2 .2 .2 0 0 1-.3 .2zM80.5 58.9l-.2 .3M80.5 56l-.2 .3M80.8 59.3h.1M80.8 56.4h.1M81.1 58.9l.1-.1v.5M81.1 56l.1-.1v.5M81.1 59.3h.2M81.1 56.4h.2"/>
<path d="M81.1 47.4l.1 .4 .3 .1 2.1 .1 .2 .1v.2l-.2 .1h-1.8v.3l.2 .1h1l.2 .2-.2 .2-.8 .1 .1 .2 .6 .1 .1 .3-.8 .1-.2 .1v.1l1.3 .2 .1 .2-.2 .2h-1.5l-.1 .2 .2 .2h2l.2 .2 .1 .3M81.2 58.5l-.2 .2v.3h.2M81.4 58.5l.3 .1v.2h-.2M81.6 58.8l.1 .1-.3 .1M81.7 56.1v.5M81.7 59v.4M81.7 59.2l.2 .1M81.7 56.3l.2 .1M81.9 56.1v.2M81.9 59v.2M82.2 59h.2M82.2 56.2h.2"/>
<path d="M82.4 58.8h-.2v.5M82.4 55.9h-.2v.5M84.9 57.4h5v4.6h-5zM85.1 57.7h4.5v4.1h-4.5zM93.2 51.5h.6v1.2h-.6zM93.2 54.1h.6v1.1h-.6zM93.2 56.6h.6v1.1h-.6zM93.2 59.2h.6v1.1h-.6zM93.8 51.2h7.5v34.8h-7.5zM94.7 51.2h5.7M101.3 59.2h.6v1.1h-.6zM101.3 56.6h.6v1.1h-.6z"/>
<path d="M101.3 54.1h.6v1.1h-.6zM101.3 51.5h.6v1.2h-.6zM105.8 49.7v.5h-.2M106.1 49.8h.2l-.2 .4h.2M111.4 46.9h.2v-.3h-.2v.5M112 46.7h.2v.4h-.2zM112.5 46.6l.1 .5 .1-.3 .1 .3 .1-.5M113.2 46.8h.2M113.4 46.6h-.2v.5h.2M113.7 46.9h.1M113.8 46.9l.1-.2-.2-.1v.5M113.8 46.9l.1 .2"/>
<path d="M114.2 47.2h.2M114.8 46.6v.4l-.2 .1M115 47.1l.2-.5 .1 .5M115.1 47h.2M115.4 47.6v.4l-.1 .1M115.7 47.8l.1-.2v.5M115.7 48.1h.3M115.8 46.6l-.2 .1v.4h.2M116.1 46.6v.5M116.2 46.8l.2 .3M116.4 46.6l-.3 .3M119.8 54.5h.5"/>
<path d="M119.8 54.2l.3 .3M120 54.9l-.2-.1v.3M120 54.9l.1-.1 .2 .3M120 54.9v.1M120.3 54.2l-.3 .2M122.9 55h-.5v-.2h.2l.1 .2M122.9 54.8l-.2 .1M122.9 54.2v.3M122.9 54.4h-.5l.1 .1M134.3 50.9v.2h.5M134.3 52a.21 .21 0 0 1 .3-.1 .21 .21 0 0 1 .1 .3h-.3zM134.4 52l.3 .2"/>
<path d="M134.5 51.6h.4M134.5 51.4h.2M134.5 50.9v.2M134.8 51.3l-.1 .3M134.8 53v.3l-.5-.2 .1 .2M134.8 52.5v.2l-.5-.2 .1 .2M145.3 53.3l.1 .2h.4v-.2M145.3 51.2v.3M145.3 51.3h.5M145.3 51.8h.5l-.1 .2h-.4M145.4 52.3h.4v.2l-.4 .1zM145.8 50.7v.3l-.4-.3v.3"/>
<path d="M145.9 52.8v.2M53.7 62h.4l.1 .2M53.7 61a.22 .22 0 0 1 .3-.1 .22 .22 0 0 1 .1 .2h-.4zM53.8 60.9l.3 .2M54.2 61.6h-.5l.1 .1M54.2 61.5v.2M54.9 76.3l.2 .6 .7 .1 .3-.2v-.5h-.7v.2M56.1 75.5h-1.2l.3 .3M56.1 75.1v.7M56.3 73.5v.3M56.3 74.4l.3 1.1M56.7 71.6l-.3 .8"/>
<path d="M57 76.5l.2 .3M57.1 67.7a1.61 1.61 0 0 1 1.3-.4v-.2h7.1v.2l2.8 2.8h.3v7.1h-.2l-2.9 2.9v.1h-7.1v-.2a1.65 1.65 0 0 1-1.7-1.1 1.65 1.65 0 0 1 .6-1.9 6.9 6.9 0 0 0-.6-7.7 1.53 1.53 0 0 1 .4-1.6zM57.4 70.3l-.3 .5M57.5 77.2l.8 .8M58.6 69.1l-.9 .7M58.7 78.4l.6 .3M58.8 76h4.8a.8 .8 0 0 1 .8 .8 .8 .8 0 0 1-.8 .8h-4.8M58.8 69.7h4.6a.8 .8 0 0 1 .8 .8 .8 .8 0 0 1-.8 .8h-4.6M58.9 69.9v1.2M58.9 76.2v1.2M59.1 70v1M59.1 76.3v1"/>
<path d="M59.3 70.1v.8M59.3 76.3v.9M59.3 68.6l-.3 .1M60.1 79.1l.8 .3M61.2 67v-.7h1.5v.7M61.4 67.9l-1.1 .2M61.8 69.9v1.2M61.8 76.2v1.2M61.8 71.4a1.96 1.96 0 0 0 3 .6 1.96 1.96 0 0 0 0-3 1.96 1.96 0 0 0-3 .6 1.95 1.95 0 0 1 3.3-.4 1.95 1.95 0 0 1-.9 3.1M61.9 79.5h.4M61.9 67.8h.4M62 70v1"/>
<path d="M62 76.3v1M62.2 70.1v.8M62.2 76.3v.9M63.4 68l.8 .2M63.9 79.2l-1 .3M64.2 74.9a1.96 1.96 0 0 1 .8 3.1 1.96 1.96 0 0 1-3.2-.4 1.96 1.96 0 0 0 3 .7 1.96 1.96 0 0 0 0-3.1 1.96 1.96 0 0 0-3 .7M65 68.6l.5 .3M65.2 78.6l-.3 .2M66 69.3l.7 .8M66.5 77.5l-.8 .8M67.1 70.6l.2 .3M67.2 76.5l-.3 .5"/>
<path d="M67.7 71.9l.2 1M67.8 74.9l-.2 .8M68 73.5v.3M69.3 74.4v.6M69.3 74.7h1.2M69.4 76.7h.3l.1 .2 .2-.3h.2l.2 .1 .1 .5h-1.2zM69.8 76.9v.3M70.2 75.5v.6M70.5 75.4l-1.2 .4 1.2 .4M73.5 73.1h7.4v12.6h-7.4zM78.6 67.2h.3a.18 .18 0 0 1-.2 .3 .18 .18 0 0 1-.1-.3zM78.6 66.7h.3a.18 .18 0 0 1-.2 .2 .18 .18 0 0 1-.1-.2z"/>
<path d="M78.6 67.2l.3 .2M78.6 66.7l.3 .2M79 67.9h-.5l.1 .1M79 67.7v.3M81.2 61.4l-.2 .1v.3l.2 .1M81.4 67.6l-.2-.1v.2h.4M81.4 67.6v.1M81.4 61.5h.3l-.3 .4h.3M81.6 67.5l-.2 .1M81.6 66.9v.3l-.4-.3 .1 .3M86.7 68.7l-.2-.2v.3M86.7 68.6l.1-.1 .1 .3"/>
<path d="M86.9 69.3h-.4v-.2h.2v.2M86.9 69l-.2 .1M89.1 68.5h.5M89.1 68.2l.3 .3M89.1 68.9a.22 .22 0 0 1 .3-.1 .22 .22 0 0 1 .1 .2h-.3zM89.2 68.8l.3 .2M89.6 68.2l-.3 .2M89.6 69.3v.3l-.5-.2 .1 .2M93.2 61.7h.6v1.1h-.6zM93.2 64.2h.6v1.1h-.6zM93.2 66.8h.6v1.1h-.6zM93.2 69.3h.6v1.1h-.6z"/>
<path d="M93.2 71.8h.6v1.2h-.6zM93.2 74.4h.6v1.1h-.6zM93.2 76.9h.6v1.1h-.6zM93.2 79.5h.6v1.1h-.6zM101.3 64.2h.6v1.1h-.6zM101.3 61.7h.6v1.1h-.6zM101.3 79.5h.6v1.1h-.6zM101.3 76.9h.6v1.1h-.6zM101.3 74.4h.6v1.1h-.6zM101.3 71.8h.6v1.2h-.6zM101.3 69.3h.6v1.1h-.6zM101.3 66.8h.6v1.1h-.6z"/>
<path d="M103 67.6v.2h.4M103 69.4h.4a.2 .2 0 0 1-.2 .2 .2 .2 0 0 1-.2-.2zM103.1 69.4l.2 .2M103.1 68.1h.2M103.1 68.3h.5M103.2 67.6v.2M103.4 69.1h.1M103.4 68.7h-.4l.1 .2M103.4 68.6v.3M103.4 68l-.1 .3M105.6 68.7l.1 .3 .3-.1 .1-.2M105.8 68.3h.3"/>
<path d="M105.9 68.2v.3l-.3-.1M114.5 78.8l-.2-.1v.2l.2 .2h-.2M114.8 78.7l.3 .1-.2 .1M114.9 78.9l.1 .2-.2 .1M123.9 64.6l5.4 .1 .1-.2 1.4 .1 .1 .2v2.6l-.2 .2h-1.3l-.1-.1-5.3 .1-.2-.3zM124 70.2h4.2v1.8h-4.2zM124.1 64.9v2.3M125.3 64.9v2.3M125.5 71.1h.6l1-.6v1.3l-1-.7h1.5M126.1 70.5v1.3M127.2 78.8h-.2l.2 .3h-.2M127.5 78.8l.1-.1v.5"/>
<path d="M127.5 79.2h.3M129.4 64.9v2.3M130.7 64.9v2.3M134.3 61.4v.2h.5M134.4 62.4h.3a.18 .18 0 0 1-.2 .3 .18 .18 0 0 1-.1-.3zM134.4 62.4l.3 .3M134.5 62.1h.4M134.5 61.9h.2M134.5 61.4v.2M134.8 61.8l-.1 .3M134.8 63.5v.3l-.5-.3 .1 .3M134.8 62.9v.3l-.5-.2 .1 .2"/>
<path d="M136.3 71v2.9l.2 .3h9.6l.3-.3v-2.9M139.9 78.8h-.2l.2 .3h-.2M140.2 78.8h.2l-.2 .4h.2M145.3 63.7l.1 .3 .4-.1v-.2M145.3 61.7v.3M145.3 61.8h.5M145.3 62.2l.5 .1v.2h-.5M145.4 62.8h.3l.1 .2h-.4zM145.8 61.3h-.5l.1 .1M145.8 61.2v.2M145.9 63.3v.2M148.9 62h.4l.1 .2"/>
<path d="M149.4 61.6l-.5-.1 .1 .2M61.2 80.2v.8h1.5v-.7M83.9 82.1v.3h.5M83.9 84a.22 .22 0 0 1 .3-.1 .22 .22 0 0 1 .1 .3h-.2zM84 84l.3 .2M84.1 82.7h.2M84.1 82.9h.5M84.1 82.1v.3M84.4 83.7h.1M84.4 83.3h-.5l.1 .2M84.4 83.2v.3M84.4 82.6l-.1 .3"/>
<path d="M86.5 81.5v.3h.2l.1-.3 .1 .1v.2M86.9 82.3h-.4v-.2h.2v.2M86.9 82.1l-.2 .1M87 83h-.5l.1 .1M87 83.3v.2h-.4l-.1-.2M87 82.8v.3M89.1 81.5h.7M89.1 81.2l.3 .3M89.1 81.9a.22 .22 0 0 1 .3-.1 .22 .22 0 0 1 .1 .2l-.3 .1zM89.2 81.8l.3 .2M89.3 81.9a.22 .22 0 0 1 .3-.1 .22 .22 0 0 1 .1 .2l-.2 .1zM89.3 81.2l.3 .3"/>
<path d="M89.4 81.8l.3 .2M89.6 81.2l-.3 .2M89.6 82.4v.2l-.5-.2 .1 .2M89.8 81.2l-.3 .2M89.8 82.4v.2l-.5-.2 .1 .2M91.9 81.6l.2 .2M92.3 81.5l-.2 .3M92.3 81.5h.1M92.3 81.5l.1 .3h-.3M92.4 82.3h-.5l.1-.2h.2v.2M92.4 82.1l-.2 .1M93.2 82h.6v1.1h-.6z"/>
<path d="M93.2 84.5h.6v1.2h-.6zM94.7 86h5.3M97.2 86l.3-.3h.2l.1 .3M101.3 84.5h.6v1.2h-.6zM101.3 82h.6v1.1h-.6zM114.8 86l-.3 .1 .3 .1M127.3 86l.1 .3 .1-.3M139.9 86l.3 .1-.3 .1"/>
<circle cx="56.6" cy="47.6" r="2.86"/>
<circle cx="70.9" cy="59.1" r="6.1"/>
<circle cx="70.9" cy="59.1" r="1.27"/>
<circle cx="149.9" cy="47.6" r="2.86"/>
<circle cx="113.4" cy="65.4" r="3.2"/>
<circle cx="120.1" cy="62.2" r="2.03"/>
<circle cx="56.6" cy="87.3" r="2.86"/>
<circle cx="149.9" cy="87.3" r="2.86"/>
</g>
<path d="M115.9 64.2v2.5M119.4 64.2h1.3" fill="none" stroke="#505050" stroke-width=".32"/>
<g fill="none" stroke="#505050" stroke-width=".21">
<path d="M54.4 52.7l.6-.6h1.3l.6 .6v1.3l-.6 .6 .6 .7v1.2l-.6 .7 .6 .6v1.3l-.6 .6 .6 .6v1.3l-.6 .6h-1.3l-.6-.6v-1.3l.6-.6-.6-.6v-1.3l.6-.6-.6-.7v-1.2l.6-.7-.6-.6zM70.6 49.5h.3M70.9 48.8h5.1v1.5h-5.1zM76 49.5h.2M80.4 57.5h.4M80.8 59.7v1.3M80.8 56.9v1.2M81.8 59.7v1.3M81.8 56.9v1.2M81.8 57.5h.5M84.1 51.9a2.7 2.7 0 0 0 0-4.6h-3a2.69 2.69 0 0 0 0 4.6h3M93.7 47.6l.6-.6h1.3l.7 .6 .6-.6h1.3l.6 .6 .6-.6h1.3l.6 .6 .7-.6h1.2l.7 .6 .6-.6h1.3l.6 .6v1.3l-.6 .6h-1.3l-.6-.6-.7 .6h-1.2l-.7-.6-.6 .6h-1.3l-.6-.6-.6 .6h-1.3l-.6-.6-.7 .6h-1.3l-.6-.6z"/>
<path d="M110.2 58.7v.7h2.1M110.2 48.7h9M119.2 48.7v10.7h-2.1M119.2 48.7v-2.9h-9v8.2M120.6 52.1h1.5v5.1h-1.5zM121.3 51.8v.3M121.3 57.2v.2M123.5 47.5h10.2v10h-10.2zM123.5 47l1.7-.5h6.8l1.7 .5v.4h-10.2zM123.5 47h10.2M123.5 47.3h10.2M123.5 47.2h10.2"/>
<path d="M124 46.8h9.2M124.7 46.6h7.9M142 54.6h1.2M142.6 48.9v1.3M142.6 54v1.3M142.6 59.4v1.3M149.6 52.7l.6-.6h1.3l.6 .6v1.3l-.6 .6 .6 .7v1.2l-.6 .7 .6 .6v1.3l-.6 .6 .6 .6v1.3l-.6 .6h-1.3l-.6-.6v-1.3l.6-.6-.6-.6v-1.3l.6-.6-.6-.7v-1.2l.6-.7-.6-.6zM79.3 64.8h1.5v5.1h-1.5zM80.1 64.5v.3M80.1 69.9v.2M80.4 60.3h.4M81.8 60.3h.5"/>
<path d="M87.2 66.4h1.6v5.1h-1.6zM87.2 79.4h1.6v5.1h-1.6zM88 66.1v.3M88 71.5v.2M88 79.1v.3M90.1 79.4h1.5v5.1h-1.5zM90.9 79.1v.3M103.9 68.1h1.2M103.9 69.1h1.2M104.5 67.6v.5M104.5 69.1v.5M112.1 79.5h5.1l.5 .5v5.1l-.5 .5h-5.1l-.5-.5v-5.1z"/>
<path d="M124.8 79.5h5.1l.5 .5v5.1l-.5 .5h-5.1l-.5-.5v-5.1zM137.5 79.5h5.1l.5 .5v5.1l-.5 .5h-5.1l-.5-.5v-5.1zM142 65.1h1.2M142.6 64.5v1.2M84.8 82.7h1.3M84.8 83.7h1.3M85.5 82.2v.5M85.5 83.7v.5M88 84.5v.2M90.9 84.5v.2M112.1 81.3v.7l.4 .9M112.1 83.1v.7"/>
<path d="M124.8 81.3v.7l.4 .9M124.8 83.1v.7M137.5 81.3v.7l.4 .9M137.5 83.1v.7"/>
<circle cx="140" cy="52.1" r="5"/>
<circle cx="140" cy="62.6" r="5"/>
<circle cx="114.7" cy="82.5" r="1.78"/>
<circle cx="127.4" cy="82.5" r="1.78"/>
<circle cx="140" cy="82.5" r="1.78"/>
</g>
<g fill="#505050" stroke="#505050" stroke-width=".18">
<path d="M124.4 70.2h.6v1.9h-.6z"/>
<path d="M128.2 70.7h.6v.9h-.6z"/>
<path d="M123.4 70.7h.6v.9h-.6z"/>
<path d="M121.9 65.8h1.9v.6h-1.9z"/>
<path d="M130.9 65.8h1.9v.6h-1.9z"/>
<path d="M124.7 57.4h1v1.7h-1z"/>
<path d="M126.4 57.4h1v1.7h-1z"/>
<path d="M128.1 57.4h1v1.7h-1z"/>
<path d="M129.8 57.4h1v1.7h-1z"/>
<path d="M131.5 57.4h1v1.7h-1z"/>
<path d="M136 69.9h1.9v1.2h-1.9z"/>
<path d="M137.9 69.9h1.8v.7h-1.8z"/>
<path d="M139.7 69.9h.7v1.2h-.7z"/>
<path d="M140.4 69.9h1.8v.7h-1.8z"/>
<path d="M142.2 69.9h.8v1.2h-.8z"/>
<path d="M143 69.9h1.7v.7h-1.7z"/>
<path d="M144.7 69.9h1.9v1.2h-1.9z"/>
<path d="M65.4 73.5h2.2v.4h-2.2z"/>
<path d="M66.3 72.6h.3v2.2h-.3z"/>
<path d="M124.7 59.1h1v2.1h-1z"/>
<path d="M126.4 59.1h1v2.1h-1z"/>
<path d="M128.1 59.1h1v2.1h-1z"/>
<path d="M129.8 59.1h1v2.1h-1z"/>
<path d="M131.5 59.1h1v2.1h-1z"/>
<path d="M150.6 53.1h.5v.5h-.5z"/>
<path d="M150.6 55.6h.5v.6h-.5z"/>
<path d="M150.6 58.2h.5v.5h-.5z"/>
<path d="M150.6 60.7h.5v.5h-.5z"/>
<path d="M55.4 53.1h.5v.5h-.5z"/>
<path d="M55.4 55.6h.5v.6h-.5z"/>
<path d="M55.4 58.2h.5v.5h-.5z"/>
<path d="M55.4 60.7h.5v.5h-.5z"/>
<path d="M137.9 70.6h1.8v.5h-1.8z"/>
<path d="M140.4 70.6h1.8v.5h-1.8z"/>
<path d="M143 70.6h1.7v.5h-1.7z"/>
<path d="M72.1 73.5h1.4v.4h-1.4z"/>
<path d="M72.1 74.7h1.4v.5h-1.4z"/>
<path d="M72.1 76h1.4v.4h-1.4z"/>
<path d="M72.1 77.3h1.4v.4h-1.4z"/>
<path d="M72.1 78.5h1.4v.5h-1.4z"/>
<path d="M72.1 79.8h1.4v.4h-1.4z"/>
<path d="M72.1 81.1h1.4v.4h-1.4z"/>
<path d="M72.1 82.3h1.4v.5h-1.4z"/>
<path d="M72.1 83.6h1.4v.4h-1.4z"/>
<path d="M72.1 84.9h1.4v.4h-1.4z"/>
<path d="M81 73.5h1.3v.4h-1.3z"/>
<path d="M81 74.7h1.3v.5h-1.3z"/>
<path d="M81 76h1.3v.4h-1.3z"/>
<path d="M81 77.3h1.3v.4h-1.3z"/>
<path d="M81 78.5h1.3v.5h-1.3z"/>
<path d="M81 79.8h1.3v.4h-1.3z"/>
<path d="M81 81.1h1.3v.4h-1.3z"/>
<path d="M81 82.3h1.3v.5h-1.3z"/>
<path d="M81 83.6h1.3v.4h-1.3z"/>
<path d="M81 84.9h1.3v.4h-1.3z"/>
<path d="M85.3 62h.2v.8h-.2z"/>
<path d="M86 62h.2v.8h-.2z"/>
<path d="M86.6 62h.2v.8h-.2z"/>
<path d="M87.3 62h.2v.8h-.2z"/>
<path d="M87.9 62h.2v.8h-.2z"/>
<path d="M88.6 62h.2v.8h-.2z"/>
<path d="M89.2 62h.2v.8h-.2z"/>
<path d="M89.2 56.6h.2v.8h-.2z"/>
<path d="M88.6 56.6h.2v.8h-.2z"/>
<path d="M87.9 56.6h.2v.8h-.2z"/>
<path d="M87.3 56.6h.2v.8h-.2z"/>
<path d="M86.6 56.6h.2v.8h-.2z"/>
<path d="M86 56.6h.2v.8h-.2z"/>
<path d="M85.3 56.6h.2v.8h-.2z"/>
<path d="M94.7 48h.5v.5h-.5z"/>
<path d="M97.3 48h.5v.5h-.5z"/>
<path d="M99.8 48h.5v.5h-.5z"/>
<path d="M102.3 48h.6v.5h-.6z"/>
<path d="M104.9 48h.5v.5h-.5z"/>
</g>
<g fill="#505050" stroke="#505050" stroke-width=".18">
<path d="M74 56a.84 .84 0 0 1 1.4 0 .84 .84 0 0 1-.5 1.3 .84 .84 0 0 1-1.1-.8h.2a.69 .69 0 0 1 .9-.6 .69 .69 0 0 1 .3 1.1 .69 .69 0 0 1-1.2-.2v-.3h-.2z" fill-rule="evenodd"/>
<path d="M79.6 84.3a.61 .61 0 0 1 .9 .1 .61 .61 0 0 1-.3 .9 .61 .61 0 0 1-.8-.5h.1a.46 .46 0 0 1 .7-.4 .46 .46 0 0 1 .1 .7 .46 .46 0 0 1-.7-.2l-.1-.1h-.1z" fill-rule="evenodd"/>
<path d="M85.4 60.5a.53 .53 0 0 1 .8 .2 .53 .53 0 0 1-.3 .8 .53 .53 0 0 1-.7-.6h.2a.38 .38 0 0 1 .5-.3 .38 .38 0 0 1 .1 .6 .38 .38 0 0 1-.6-.1v-.2h-.2z" fill-rule="evenodd"/>
<circle cx="136.7" cy="73.6" r=".25"/>
</g>
<path d="M122.3 71.1h1.3M128.6 71.1h1.3" fill="none" stroke="#505050" stroke-width=".87"/>
<path d="M121 66.1h1.2M132.6 66.1h1.1" fill="none" stroke="#505050" stroke-width=".61"/>
<path d="M139.6 74.1h1M142.1 74.1h1" fill="none" stroke="#000080" stroke-width=".42"/>
<path d="M105.3 73.3h1.5M106 77.8h1.5M139.6 74.1h1" fill="none" stroke="#800000" stroke-width=".42"/>
<g fill="none" stroke="#000" stroke-width=".18">
<path d="M55.6 60v2M69.9 59.1h2M70.9 58.1v2M72.4 49.5h2M73.4 48.5v2.1M80.3 57.5h2M81.3 56.5v2M81.3 59.3v2.1M81.6 49.5h2M82.6 48.5v2.1M86.5 59.7h1.8M87.4 58.8v1.8"/>
<path d="M92.7 52.1h2M93.7 51.1v2M104.1 48.3h2.1M105.1 47.3v2M113.7 45.8h2M114.7 44.7v2.1M120.3 54.6h2M121.3 53.6v2M127.6 54.6h2.1M128.6 53.6v2M139.1 52.1h2M140 51.1v2"/>
<path d="M150.8 60v2M54.6 61h2M61 73.7h2M62 72.7v2M76.2 79.4h2M77.2 78.4v2M79.1 67.3h2M80.1 66.3v2M80.3 60.3h2M87 68.9h2M88 67.9v2M103.5 68.6h2"/>
<path d="M104.5 67.6v2M112.4 65.4h2M113.4 64.4v2M119 62.2h2.1M120.1 61.2v2.1M125.1 71.1h2M126.1 70.1v2.1M126.4 66.1h2M127.4 65v2.1M139.1 62.6h2M140 61.6v2M140.3 69.9h2"/>
<path d="M141.3 68.9v2M149.8 61h2.1M84.4 83.2h2.1M85.5 82.2v2M87 81.9h2M88 80.9v2M89.8 81.9h2.1M90.9 80.9v2M113.7 82.5h2M114.7 81.5v2.1M126.4 82.5h2M127.4 81.5v2.1"/>
<path d="M139.1 82.5h2M140 81.5v2.1"/>
</g>
<g fill="none" stroke="#f90" stroke-width=".18">
<path d="M54.5 45.3a2.4 2.4 0 0 1 1.5-.6h94.5a2.26 2.26 0 0 1 2.2 2.3v40.9a2.29 2.29 0 0 1-2.2 2.3h-94.5a2.29 2.29 0 0 1-2.3-2.3v-40.8a2.31 2.31 0 0 1 .8-1.8z"/>
<circle cx="56.6" cy="87.3" r="1.5"/>
</g>
<circle cx="56.6" cy="87.3" r="1.5" fill="#fff" stroke="#000" stroke-width=".18"/>
<circle cx="56.6" cy="47.6" r="1.5" fill="none" stroke="#f90" stroke-width=".18"/>
<circle cx="56.6" cy="47.6" r="1.5" fill="#fff" stroke="#000" stroke-width=".18"/>
<circle cx="149.9" cy="47.6" r="1.5" fill="none" stroke="#f90" stroke-width=".18"/>
<circle cx="149.9" cy="47.6" r="1.5" fill="#fff" stroke="#000" stroke-width=".18"/>
<circle cx="149.9" cy="87.3" r="1.5" fill="none" stroke="#f90" stroke-width=".18"/>
<circle cx="149.9" cy="87.3" r="1.5" fill="#fff" stroke="#000" stroke-width=".18"/>
<g fill="none" stroke="#505050" stroke-width=".18">
<path d="M56.6 60l-2 2M56.6 57.4l-2 2.1M56.6 54.9l-2 2M56.6 52.3l-2 2.1M57.6 46.6l-2 2M68.1 58.1l-2.1 2M68.6 49.5h2M69.6 48.5v2.1M75.7 58.1l-2 2M76.2 49.5h2M77.2 48.5v2.1M79.1 57.5h2"/>
<path d="M79.8 49.5h1l1.1-1v2.1l-1.1-1.1M80.1 56.5v2M80.1 59.3v2.1M81.6 57.5h2M82.6 56.5v2M82.6 59.3v2.1M83.4 49.5h1l1-1v2.1l-1-1.1M94.7 58.7l-2 2M94.7 51.1l-2 2M94.7 53.6l-2 2M94.7 56.2l-2 2M96 47.3l-2 2"/>
<path d="M98.5 47.3l-2 2M101.1 47.3l-2.1 2M102.3 58.7l-2 2M102.3 56.2l-2 2M102.3 53.6l-2 2M102.3 51.1l-2 2M103.6 47.3l-2 2M106.2 47.3l-2.1 2M111 55.4l-2 2.1M115.7 58.4l-2 2.1M115.7 52.4l-2 2.1M120.3 50.8h2"/>
<path d="M120.3 58.4h2M121.3 49.8v2M121.3 57.4v2.1M139.1 49.6h2M139.1 54.6h2M140 48.6v2M140 53.6v2M140 59.1v2M150.9 46.6l-2 2M151.9 60l-2.1 2M151.9 57.4l-2.1 2.1M151.9 54.9l-2.1 2"/>
<path d="M151.9 52.3l-2.1 2.1M63 79.2l-2 2.1M63 66.1l-2 2M79.1 63.5h2M79.1 71.1h2M79.1 60.3h2M80.1 62.5v2M80.1 70.1v2.1M81.6 60.3h2M87 72.7h2M87 65.1h2M87 78.1h2"/>
<path d="M88 64.1v2M88 71.7v2M88 77.1v2M89.8 78.1h2.1M90.9 77.1v2M94.7 79l-2 2M94.7 71.4l-2 2M94.7 68.9l-2 2M94.7 66.3l-2 2M94.7 61.2l-2 2.1M94.7 63.8l-2 2M94.7 73.9l-2 2"/>
<path d="M94.7 76.5l-2 2M102.3 79l-2 2M102.3 76.5l-2 2M102.3 73.9l-2 2M102.3 71.4l-2 2M102.3 68.9l-2 2M102.3 66.3l-2 2M102.3 63.8l-2 2M102.3 61.2l-2 2.1M103.5 67.3h2M103.5 69.9h2M104.5 66.3v2"/>
<path d="M104.5 68.9v2M110.9 65.4h2M111.9 64.4v2M112.4 79.3l-2 2M113.9 65.4h2M114.9 64.4v2M118.9 79.3l-2 2M119 63.3h2.1M119 61.2h2.1M120.1 60.2v4.1M122 65l-2 2.1M123.3 70.1l-2 2.1"/>
<path d="M125.1 79.3l-2 2M130.9 70.1l-2 2.1M131.6 79.3l-2 2M134.7 65l-2 2.1M137.8 79.3l-2 2M139.1 60.1h2M139.1 65.1h2M139.8 71.4l-2 2M140 64v2.1M142.3 71.4l-2 2M144.3 79.3l-2 2M144.9 71.4l-2.1 2"/>
<path d="M57.6 86.3l-2 2M84.4 81.9h2.1M84.4 84.5h2.1M85.5 80.9v2M85.5 83.4v2.1M87 85.7h2M88 84.7v2M89.8 85.7h2.1M90.9 84.7v2M94.7 84.1l-2 2M94.7 81.5l-2 2.1M102.3 84.1l-2 2"/>
<path d="M102.3 81.5l-2 2.1M112.4 83.8l-2 2M118.9 83.8l-2 2M125.1 83.8l-2 2M131.6 83.8l-2 2M137.8 83.8l-2 2M144.3 83.8l-2 2M150.9 86.3l-2 2"/>
<circle cx="55.6" cy="55.9" r=".99"/>
<circle cx="55.6" cy="53.4" r=".99"/>
<circle cx="55.6" cy="58.4" r=".99"/>
<circle cx="56.6" cy="47.6" r=".99"/>
<circle cx="67.1" cy="59.1" r=".99"/>
<circle cx="69.6" cy="49.5" r=".99"/>
<circle cx="74.7" cy="59.1" r=".99"/>
<circle cx="77.2" cy="49.5" r=".99"/>
<circle cx="80.1" cy="57.5" r=".99"/>
<circle cx="82.6" cy="57.5" r=".99"/>
<circle cx="93.7" cy="54.6" r=".99"/>
<circle cx="93.7" cy="57.2" r=".99"/>
<circle cx="93.7" cy="52.1" r=".99"/>
<circle cx="93.7" cy="59.7" r=".99"/>
<circle cx="95" cy="48.3" r=".99"/>
<circle cx="97.5" cy="48.3" r=".99"/>
<circle cx="100.1" cy="48.3" r=".99"/>
<circle cx="101.3" cy="57.2" r=".99"/>
<circle cx="101.3" cy="59.7" r=".99"/>
<circle cx="101.3" cy="52.1" r=".99"/>
<circle cx="101.3" cy="54.6" r=".99"/>
<circle cx="102.6" cy="48.3" r=".99"/>
<circle cx="105.1" cy="48.3" r=".99"/>
<circle cx="110" cy="56.5" r=".99"/>
<circle cx="114.7" cy="53.4" r=".99"/>
<circle cx="114.7" cy="59.4" r=".99"/>
<circle cx="121.3" cy="50.8" r=".99"/>
<circle cx="121.3" cy="58.4" r=".99"/>
<circle cx="140" cy="54.6" r=".99"/>
<circle cx="140" cy="49.6" r=".99"/>
<circle cx="149.9" cy="47.6" r=".99"/>
<circle cx="150.8" cy="58.4" r=".99"/>
<circle cx="150.8" cy="55.9" r=".99"/>
<circle cx="150.8" cy="53.4" r=".99"/>
<circle cx="55.6" cy="61" r=".99"/>
<circle cx="62" cy="67.1" r=".99"/>
<circle cx="80.1" cy="60.3" r=".99"/>
<circle cx="80.1" cy="71.1" r=".99"/>
<circle cx="80.1" cy="63.5" r=".99"/>
<circle cx="82.6" cy="60.3" r=".99"/>
<circle cx="88" cy="65.1" r=".99"/>
<circle cx="88" cy="72.7" r=".99"/>
<circle cx="88" cy="78.1" r=".99"/>
<circle cx="90.9" cy="78.1" r=".99"/>
<circle cx="93.7" cy="64.8" r=".99"/>
<circle cx="93.7" cy="67.3" r=".99"/>
<circle cx="93.7" cy="74.9" r=".99"/>
<circle cx="93.7" cy="69.9" r=".99"/>
<circle cx="93.7" cy="72.4" r=".99"/>
<circle cx="93.7" cy="77.5" r=".99"/>
<circle cx="93.7" cy="62.2" r=".99"/>
<circle cx="101.3" cy="62.2" r=".99"/>
<circle cx="101.3" cy="72.4" r=".99"/>
<circle cx="101.3" cy="69.9" r=".99"/>
<circle cx="101.3" cy="64.8" r=".99"/>
<circle cx="101.3" cy="77.5" r=".99"/>
<circle cx="101.3" cy="74.9" r=".99"/>
<circle cx="101.3" cy="67.3" r=".99"/>
<circle cx="104.5" cy="67.3" r=".99"/>
<circle cx="104.5" cy="69.9" r=".99"/>
<circle cx="111.9" cy="65.4" r=".99"/>
<circle cx="114.9" cy="65.4" r=".99"/>
<circle cx="120.1" cy="63.3" r=".99"/>
<circle cx="120.1" cy="61.2" r=".99"/>
<circle cx="121" cy="66.1" r=".99"/>
<circle cx="122.3" cy="71.1" r=".99"/>
<circle cx="129.9" cy="71.1" r=".99"/>
<circle cx="133.7" cy="66.1" r=".99"/>
<circle cx="138.8" cy="72.4" r=".99"/>
<circle cx="140" cy="60.1" r=".99"/>
<circle cx="140" cy="65.1" r=".99"/>
<circle cx="141.3" cy="72.4" r=".99"/>
<circle cx="143.9" cy="72.4" r=".99"/>
<circle cx="150.8" cy="61" r=".99"/>
<circle cx="56.6" cy="87.3" r=".99"/>
<circle cx="62" cy="80.3" r=".99"/>
<circle cx="85.5" cy="81.9" r=".99"/>
<circle cx="85.5" cy="84.5" r=".99"/>
<circle cx="88" cy="85.7" r=".99"/>
<circle cx="90.9" cy="85.7" r=".99"/>
<circle cx="93.7" cy="85.1" r=".99"/>
<circle cx="93.7" cy="80" r=".99"/>
<circle cx="93.7" cy="82.5" r=".99"/>
<circle cx="101.3" cy="85.1" r=".99"/>
<circle cx="101.3" cy="80" r=".99"/>
<circle cx="101.3" cy="82.5" r=".99"/>
<circle cx="111.4" cy="84.8" r=".99"/>
<circle cx="111.4" cy="80.3" r=".99"/>
<circle cx="117.9" cy="84.8" r=".99"/>
<circle cx="117.9" cy="80.3" r=".99"/>
<circle cx="124.1" cy="84.8" r=".99"/>
<circle cx="124.1" cy="80.3" r=".99"/>
<circle cx="130.6" cy="80.3" r=".99"/>
<circle cx="130.6" cy="84.8" r=".99"/>
<circle cx="136.8" cy="80.3" r=".99"/>
<circle cx="136.8" cy="84.8" r=".99"/>
<circle cx="143.3" cy="80.3" r=".99"/>
<circle cx="143.3" cy="84.8" r=".99"/>
<circle cx="149.9" cy="87.3" r=".99"/>
</g>
<g fill="#800000" stroke="#800000" stroke-width=".18">
<path d="M122.6 155.4h10.8v10.4h-10.8z"/>
<path d="M124.1 167.9h1v2.2h-1z"/>
<path d="M125.8 167.9h1v2.2h-1z"/>
<path d="M127.5 167.9h1v2.2h-1z"/>
<path d="M129.2 167.9h1v2.2h-1z"/>
<path d="M130.9 167.9h1v2.2h-1z"/>
<path d="M80.6 193.3h1.5v.7h-1.5z"/>
<path d="M80.6 192h1.5v.7h-1.5z"/>
<path d="M80.6 190.7h1.5v.8h-1.5z"/>
<path d="M80.6 189.4h1.5v.8h-1.5z"/>
<path d="M80.6 188.2h1.5v.7h-1.5z"/>
<path d="M80.6 186.9h1.5v.8h-1.5z"/>
<path d="M80.6 185.6h1.5v.8h-1.5z"/>
<path d="M80.6 184.4h1.5v.7h-1.5z"/>
<path d="M80.6 183.1h1.5v.8h-1.5z"/>
<path d="M80.6 181.8h1.5v.8h-1.5z"/>
<path d="M71 183.1h1.6v.8h-1.6z"/>
<path d="M71.1 181.8h1.5v.8h-1.5z"/>
<path d="M71 184.4h1.6v.7h-1.6z"/>
<path d="M71 185.6h1.6v.8h-1.6z"/>
<path d="M71 186.9h1.6v.8h-1.6z"/>
<path d="M71 188.2h1.6v.7h-1.6z"/>
<path d="M71 189.4h1.6v.8h-1.6z"/>
<path d="M71 190.7h1.6v.8h-1.6z"/>
<path d="M71 192h1.6v.7h-1.6z"/>
<path d="M71 193.3h1.6v.7h-1.6z"/>
<path d="M59.4 180.3h3.9v3.9h-3.9z"/>
<path d="M84.6 170.7h.3v1h-.3z"/>
<path d="M85.3 170.7h.3v1h-.3z"/>
<path d="M85.9 170.7h.3v1h-.3z"/>
<path d="M86.6 170.7h.3v1h-.3z"/>
<path d="M87.2 170.7h.3v1h-.3z"/>
<path d="M87.9 170.7h.3v1h-.3z"/>
<path d="M88.5 170.7h.3v1h-.3z"/>
<path d="M88.5 164.8h.3v1h-.3z"/>
<path d="M87.9 164.8h.3v1h-.3z"/>
<path d="M87.2 164.8h.3v1h-.3z"/>
<path d="M86.6 164.8h.3v1h-.3z"/>
<path d="M85.9 164.8h.3v1h-.3z"/>
<path d="M85.3 164.8h.3v1h-.3z"/>
<path d="M84.6 164.8h.3v1h-.3z"/>
</g>
<g fill="none" stroke="#800000" stroke-width=".42">
<path d="M53.1 155.2v.1M53.1 156.1v.2M53.1 157.1v.1M53.1 158v.1M53.1 158.9v.1M53.1 159.8v.1M53.3 154.1l-.2 .3M54.2 153.4l-.3 .1M55 153.4h.1M55.9 153.4h.1M56.8 153.4h.1M57.7 153.4h.1"/>
<path d="M58.6 153.4h.1M59.5 153.4h.1M60.5 153.4h.1M61.4 153.4h.1M62.3 153.4h.1M63.2 153.4h.1M64.1 153.4h.1M65 153.4h.1M65.9 153.4h.1M66.9 153.4h.1M67.8 153.4h.1M68.7 153.4h.1"/>
<path d="M69.6 153.4h.1M70.5 153.4h.1M71.4 153.4h.1M72.4 153.4h.1M73.3 153.4h.1M74.2 153.4h.1M75.1 153.4h.1M76 153.4h.1M76.9 153.4h.1M77.9 153.4h.1M78.8 153.4h.1M79.7 153.4h.1"/>
<path d="M80.6 153.4h.1M81.5 153.4h.1M82.4 153.4h.1M83.3 153.4h.1M84.2 153.4h.2M85.2 153.4h.1M86.1 153.4h.1M87 153.4h.1M87.9 153.4h.1M88.8 153.4h.1M89.8 153.4h.1M90.7 153.4h.1"/>
<path d="M91.6 153.4h.1M92.5 153.4h.1M93.4 153.4h.1M94.3 153.4h.1M95.3 153.4h.1M96.2 153.4h.1M97.1 153.4h.1M98 153.4h.1M101.5 159.3l1.1 1M101.6 153.4h.2M102.6 153.4h.1M103.5 153.4h.1"/>
<path d="M104.4 153.4h.1M105.3 153.4h.1M106.2 153.4h.1M107.2 153.4h.1M108.1 153.4h.1M109 153.4h.1M109.9 153.4h.1M110.8 153.4h.1M111.7 153.4h.1M112.6 153.4h.1M113.6 153.4h.1M114.5 153.4h.1"/>
<path d="M115.4 153.4h.1M116.3 153.4h.1M117.2 153.4h.1M118.1 153.4h.1M119 153.4h.2M120 153.4h.1M120.9 153.4h.1M121.8 153.4h.1M122.7 153.4h.1M123.6 153.4h.1M124.6 153.4h.1M125.5 153.4h.1"/>
<path d="M126.4 153.4h.1M127.3 153.4h.1M128.2 153.4h.1M129.1 153.4h.1M130 153.4h.1M131 153.4h.1M131.9 153.4h.1M132.8 153.4h.1M133.7 153.4h.1M134.6 153.4h.1M135.5 153.4h.1M136.4 153.4h.2"/>
<path d="M137.4 153.4h.1M138.3 153.4h.1M139.2 153.4h.1M140.1 153.4h.1M141 153.4h.1M142 153.4h.1M142.9 153.4h.1M143.8 153.4h.1M144.7 153.4h.1M145.6 153.4h.1M146.5 153.4h.1M147.4 153.4h.1"/>
<path d="M148.3 153.4h.1M149.3 153.4h.1M150.2 153.4h.1M151.1 153.4h.1M152 153.4l.1 .1M152.1 154.3v.1M152.1 155.2v.1M152.1 156.1v.1M152.1 157v.1M152.1 158v.1M152.1 158.9v.1M152.1 159.8v.1"/>
<path d="M53.1 160.8v.1M53.1 161.7v.1M53.1 162.6v.1M53.1 163.5v.1M53.1 164.4v.2M53.1 165.4v.1M53.1 166.3v.1M53.1 167.2v.1M53.1 168.2v.1M53.1 169.1v.1M53.1 170v.1M53.1 170.9v.1"/>
<path d="M53.1 171.8v.1M53.1 172.8v.1M53.1 173.7v.1M53.1 174.6v.1M53.1 175.5v.1M53.1 176.4v.2M53.1 177.4v.1M53.1 178.3v.1M53.1 179.2v.1M103.9 160.3v10.5M152.1 160.7v.1M152.1 161.7v.1"/>
<path d="M152.1 162.6v.1M152.1 163.5v.1M152.1 164.4v.1M152.1 165.4v.1M152.1 166.3v.1M152.1 167.2v.1M152.1 168.1v.1M152.1 169v.2M152.1 170v.1M152.1 170.9v.1M152.1 171.8v.1M152.1 172.7v.1"/>
<path d="M152.1 173.7v.1M152.1 174.6v.1M152.1 175.5v.1M152.1 176.4v.2M152.1 177.4v.1M152.1 178.3v.1M152.1 179.2v.1M53.1 180.2v.1M53.1 181.1v.1M53.1 182v.1M53.1 182.9v.1M53.1 183.8v.1"/>
<path d="M53.1 184.8v.1M53.1 185.7v.1M53.1 186.6v.1M53.1 187.5v.1M53.1 188.4v.2M53.1 189.4v.1M53.1 190.3v.1M53.1 191.2v.1M53.1 192.2v.1M53.1 193.1v.1M53.1 194v.1M53.1 194.9v.1"/>
<path d="M53.1 195.8v.1M53.1 196.8v.1M53.1 197.7v.1M53.1 198.6l.1 .1M54 198.7h.1M54.9 198.7h.1M55.8 198.7h.1M56.8 198.7h.1M57.7 198.7h.1M58.6 198.7h.1M59.5 198.7h.1M60.4 198.7h.1"/>
<path d="M61.3 198.7h.1M62.3 198.7h.1M63.2 198.7h.1M64.1 198.7h.1M65 198.7h.1M65.9 198.7h.1M66.8 198.7h.1M67.7 198.7h.1M68.7 198.7h.1M69.6 198.7h.1M70.5 198.7h.1M71.4 198.7h.1"/>
<path d="M72.3 198.7h.1M73.2 198.7h.1M74.2 198.7h.1M75.1 198.7h.1M76 198.7h.1M76.9 198.7h.1M77.8 198.7h.1M78.7 198.7h.2M79.7 198.7h.1M80.6 198.7h.1M81.5 198.7h.1M82.4 198.7h.1"/>
<path d="M83.3 198.7h.1M84.2 198.7h.1M85.2 198.7h.1M86.1 198.7h.1M87 198.7h.1M87.9 198.7h.1M88.8 198.7h.1M89.7 198.7h.1M90.6 198.7h.1M91.6 198.7h.1M92.5 198.7h.1M93.4 198.7h.1"/>
<path d="M94.3 198.7h.1M95.2 198.7h.1M96.1 198.7h.2M97.1 198.7h.1M98 198.7h.1M98.9 198.7h.1M99.8 198.7h.1M100.7 198.7h.1M101.6 198.7h.1M102.6 198.7h.1M103.5 198.7h.1M104.4 198.7h.1"/>
<path d="M105.3 198.7h.1M106.2 198.7h.1M107.1 198.7h.1M108 198.7h.1M109 198.7h.1M109.9 198.7h.1M110.8 198.7h.1M111.7 198.7h.1M112.6 198.7h.1M113.5 198.7h.2M114.5 198.7h.1M115.4 198.7h.1"/>
<path d="M116.3 198.7h.1M117.2 198.7h.1M118.1 198.7h.1M119 198.7h.1M120 198.7h.1M120.9 198.7h.1M121.8 198.7h.1M122.7 198.7h.1M123.6 198.7h.1M124.5 198.7h.1M125.4 198.7h.1M126.4 198.7h.1"/>
<path d="M127.3 198.7h.1M128.2 198.7h.1M129.1 198.7h.1M130 198.7h.1M130.9 198.7h.1M131.9 198.7h.1M132.8 198.7h.1M133.7 198.7h.1M134.6 198.7h.1M135.5 198.7h.1M136.4 198.7h.2M137.4 198.7h.1"/>
<path d="M138.3 198.7h.1M139.2 198.7h.1M140.1 198.7h.1M141 198.7h.1M141.9 198.7h.1M142.9 198.7h.1M143.8 198.7h.1M144.7 198.7h.1M145.6 198.7h.1M146.5 198.7h.1M147.4 198.7h.1M148.3 198.7h.1"/>
<path d="M149.3 198.7h.1M150.2 198.7h.1M151.1 198.7h.1M152.1 198.6l-.1 .1M152.1 180.1v.1M152.1 181.1v.1M152.1 182v.1M152.1 182.9v.1M152.1 183.8v.1M152.1 184.7v.2M152.1 185.7v.1M152.1 186.6v.1"/>
<path d="M152.1 187.5v.1M152.1 188.4v.2M152.1 189.4v.1M152.1 190.3v.1M152.1 191.2v.1M152.1 192.1v.2M152.1 193.1v.1M152.1 194v.1M152.1 194.9v.1M152.1 195.8v.1M152.1 196.7v.2M152.1 197.7v.1"/>
</g>
<g fill="none" stroke="#800000" stroke-width=".83">
<path d="M66.4 167.6l3.2 3.2v11.4h2.2M74 167.6l4.5 4.5h.9M87.4 178.4v2.9M100.7 175.9h3.2l5.7 5.7h27.9l.7-.6M110.5 179.7h11.2M114 168v2.5l4.2 4.1h2.2M114.6 168h-.6l-2.8 2.8v3.2M120.7 167l1.6 2h2.3M126.3 169v6l-1.6 1.7M128 169v7.5l-2.4 2.4v2.5l.2 .2M129.7 169v2.2l3.4 3.4v2.5l-2.6 2.6h-1.2M131.4 169h2.2"/>
<path d="M133.6 169v2.2l9.6 9.6v2.1l-.6 .6h-33.6l-5.1-5.1h-5.7l-5.1-5.1h-1.3l-3.2 3.2h-10.1l-1.9 1.9v8.3l3.2 3.1h4.4M139.4 163.1l3.9 3.9v2.8M150.2 167h-4.2l-6.6 6.6v-.6M150.2 161.9h-7l-1.2-1.3h-4.5l-.9 1v4.4l-3 3M61.3 182.2h8M68.3 182.2l1 1v.3M69.3 183.5v3.2l.6 .6h4.1l1.3 1.3v3.8M69.3 182.2v1M69.3 185.1l.9 .9h1.6M69.3 183.5l1.3 1.2h1.2M69.3 182.2h.3l1.3 1.3h.9M71.8 188.6h-4.1l-1.9 1.9h-2.8l-1.7-1.7"/>
<path d="M71.8 191.1h-2.2l-.6 .6v2.6l.6 .6h17.1l2.6-2.5h2.5l1.3 1.2M71.8 192.4h12l.6 .6h.4M71.8 189.8h-2.8l-1.3 1.3v3.8l1.3 1.3h24.7l1.3-1.3v-2.9l-1-.9h-.9M81.4 186h1.5l.7-.6v-5.4l1.6-1.6h9.5l2.2 2.2v13.7l2.2 2.2h38.4l1.9-1.9v-2.5l-3.2-3.2M83.6 182.9l-.7 .6h-1.5M83.6 184.1l-.7 .6h-1.5M83.6 181.6l-.7 .6h-1.5M83.6 192.4l-1.3 1.2h-.9M84.2 189.8l.6 .7M90.2 186.7h-2.8l-3.2 3.1M90.2 194.3l1.9 1.9M100.7 183.5h.6l7.7 7.6h12.2l2.3 2.3"/>
<path d="M100.7 181h1.9l5.1 5h17.1l1.9 1.9v1.3l1.9 1.9h5.3l2.3 2.3M100.7 186h-.4l7.4 7.4h3.1"/>
</g>
<g fill="none" stroke="#800000" stroke-width=".32">
<path d="M69 158.1l6.7 6.7h3.8M101.5 159.3h-10l-4.8 4.7v2.4l-.3 .3h-1.3l-.3-.4v-1M79.4 167.6h6l.7 .7M81 176.5h.1M82 168.9h1.9l.9 .9v6.7M82 166l.3 .4h2.5M85.4 165.3v-3.4l-.4-.5h-2.1l-3.5 3.5v4M87.4 167l-1.3 1.3v3.8h1.9v-.9M87.4 165.3v1.7M88 165.3v1l-.6 .7M93.1 170.8l-4.8 4.8h-2.8l-.1-4.4M93.1 165.7l-1.9 1.9h-1.9l-2.6 2.6v1"/>
<path d="M93.1 168.3h-3.7l-2 1.9v1M93.1 163.2l1.6 1.6v3.8l-1 .9h-4.4l-.6 .6v2.2l-1.3 1.4M103.9 160.3l-1.9-1.9h-11.1l-4.8 4.8v2.1"/>
</g>
<path d="M102.6 160.3v11.4M103.9 170.8l5.9 5.9h.1" fill="none" stroke="#800000" stroke-width=".51"/>
<path d="M102.6 171.7l7.9 8M109.9 176.7h14.8" fill="none" stroke="#800000" stroke-width=".61"/>
<circle cx="119.4" cy="171.8" r=".7" fill="#008000" stroke="#008000" stroke-width=".18"/>
<circle cx="119.4" cy="171.8" r=".44" fill="#fff" stroke="#000" stroke-width=".18"/>
<path d="M118.7 169.1h1.4v1.4h-1.4z" fill="#008000" stroke="#008000" stroke-width=".18"/>
<circle cx="119.4" cy="169.8" r=".44" fill="#fff" stroke="#000" stroke-width=".18"/>
<path d="M110.3 173.1h1.8v1.8h-1.8z" fill="#008000" stroke="#008000" stroke-width=".18"/>
<circle cx="111.2" cy="174" r=".44" fill="#fff" stroke="#000" stroke-width=".18"/>
<circle cx="114.3" cy="174" r=".89" fill="#008000" stroke="#008000" stroke-width=".18"/>
<circle cx="114.3" cy="174" r=".44" fill="#fff" stroke="#000" stroke-width=".18"/>
<circle cx="139.4" cy="168.6" r=".97" fill="#008000" stroke="#008000" stroke-width=".18"/>
<circle cx="139.4" cy="168.6" r=".44" fill="#fff" stroke="#000" stroke-width=".18"/>
<path d="M138.4 172.6h2v2h-2z" fill="#008000" stroke="#008000" stroke-width=".18"/>
<circle cx="139.4" cy="173.6" r=".44" fill="#fff" stroke="#000" stroke-width=".18"/>
<circle cx="139.4" cy="158.1" r=".97" fill="#008000" stroke="#008000" stroke-width=".18"/>
<circle cx="139.4" cy="158.1" r=".44" fill="#fff" stroke="#000" stroke-width=".18"/>
<path d="M138.4 162.2h2v1.9h-2z" fill="#008000" stroke="#008000" stroke-width=".18"/>
<circle cx="139.4" cy="163.1" r=".44" fill="#fff" stroke="#000" stroke-width=".18"/>
<circle cx="121.7" cy="179.7" r=".85" fill="#008000" stroke="#008000" stroke-width=".18"/>
<circle cx="121.7" cy="179.7" r=".55" fill="#fff" stroke="#000" stroke-width=".18"/>
<circle cx="129.3" cy="179.7" r=".85" fill="#008000" stroke="#008000" stroke-width=".18"/>
<circle cx="129.3" cy="179.7" r=".55" fill="#fff" stroke="#000" stroke-width=".18"/>
<path d="M132.4 174.6h1.3" fill="none" stroke="#008000" stroke-width="1.3"/>
<circle cx="133.1" cy="174.6" r=".4" fill="#fff" stroke="#000" stroke-width=".18"/>
<path d="M119.7 174.6h1.3" fill="none" stroke="#008000" stroke-width="1.3"/>
<circle cx="120.4" cy="174.6" r=".4" fill="#fff" stroke="#000" stroke-width=".18"/>
<circle cx="120.7" cy="159.4" r=".93" fill="#008000" stroke="#008000" stroke-width=".18"/>
<circle cx="120.7" cy="159.4" r=".44" fill="#fff" stroke="#000" stroke-width=".18"/>
<circle cx="120.7" cy="167" r=".93" fill="#008000" stroke="#008000" stroke-width=".18"/>
<circle cx="120.7" cy="167" r=".44" fill="#fff" stroke="#000" stroke-width=".18"/>
<circle cx="114" cy="168" r="2.16" fill="#008000" stroke="#008000" stroke-width=".18"/>
<circle cx="114" cy="168" r="1.5" fill="#fff" stroke="#000" stroke-width=".18"/>
<circle cx="114" cy="162" r="2.16" fill="#008000" stroke="#008000" stroke-width=".18"/>
<circle cx="114" cy="162" r="1.5" fill="#fff" stroke="#000" stroke-width=".18"/>
<circle cx="109.3" cy="165" r="2.16" fill="#008000" stroke="#008000" stroke-width=".18"/>
<circle cx="109.3" cy="165" r="1.5" fill="#fff" stroke="#000" stroke-width=".18"/>
<circle cx="150.2" cy="169.5" r=".93" fill="#008000" stroke="#008000" stroke-width=".18"/>
<circle cx="150.2" cy="169.5" r=".51" fill="#fff" stroke="#000" stroke-width=".18"/>
<circle cx="150.2" cy="167" r=".93" fill="#008000" stroke="#008000" stroke-width=".18"/>
<circle cx="150.2" cy="167" r=".51" fill="#fff" stroke="#000" stroke-width=".18"/>
<circle cx="150.2" cy="164.4" r=".93" fill="#008000" stroke="#008000" stroke-width=".18"/>
<circle cx="150.2" cy="164.4" r=".51" fill="#fff" stroke="#000" stroke-width=".18"/>
<circle cx="150.2" cy="161.9" r=".93" fill="#008000" stroke="#008000" stroke-width=".18"/>
<circle cx="150.2" cy="161.9" r=".51" fill="#fff" stroke="#000" stroke-width=".18"/>
<circle cx="55" cy="169.5" r=".93" fill="#008000" stroke="#008000" stroke-width=".18"/>
<circle cx="55" cy="169.5" r=".51" fill="#fff" stroke="#000" stroke-width=".18"/>
<circle cx="55" cy="167" r=".93" fill="#008000" stroke="#008000" stroke-width=".18"/>
<circle cx="55" cy="167" r=".51" fill="#fff" stroke="#000" stroke-width=".18"/>
<circle cx="55" cy="164.4" r=".93" fill="#008000" stroke="#008000" stroke-width=".18"/>
<circle cx="55" cy="164.4" r=".51" fill="#fff" stroke="#000" stroke-width=".18"/>
<circle cx="55" cy="161.9" r=".93" fill="#008000" stroke="#008000" stroke-width=".18"/>
<circle cx="55" cy="161.9" r=".51" fill="#fff" stroke="#000" stroke-width=".18"/>
<circle cx="83.7" cy="158.1" r=".7" fill="#008000" stroke="#008000" stroke-width=".18"/>
<circle cx="83.7" cy="158.1" r=".4" fill="#fff" stroke="#000" stroke-width=".18"/>
<circle cx="80.2" cy="158.1" r=".7" fill="#008000" stroke="#008000" stroke-width=".18"/>
<circle cx="80.2" cy="158.1" r=".4" fill="#fff" stroke="#000" stroke-width=".18"/>
<circle cx="69" cy="158.1" r=".93" fill="#008000" stroke="#008000" stroke-width=".18"/>
<circle cx="69" cy="158.1" r=".44" fill="#fff" stroke="#000" stroke-width=".18"/>
<circle cx="76.6" cy="158.1" r=".93" fill="#008000" stroke="#008000" stroke-width=".18"/>
<circle cx="76.6" cy="158.1" r=".44" fill="#fff" stroke="#000" stroke-width=".18"/>
<circle cx="123.5" cy="188.9" r=".93" fill="#008000" stroke="#008000" stroke-width=".18"/>
<circle cx="123.5" cy="188.9" r=".51" fill="#fff" stroke="#000" stroke-width=".18"/>
<circle cx="130" cy="188.9" r=".93" fill="#008000" stroke="#008000" stroke-width=".18"/>
<circle cx="130" cy="188.9" r=".51" fill="#fff" stroke="#000" stroke-width=".18"/>
<circle cx="123.5" cy="193.4" r=".93" fill="#008000" stroke="#008000" stroke-width=".18"/>
<circle cx="123.5" cy="193.4" r=".51" fill="#fff" stroke="#000" stroke-width=".18"/>
<circle cx="130" cy="193.4" r=".93" fill="#008000" stroke="#008000" stroke-width=".18"/>
<circle cx="130" cy="193.4" r=".51" fill="#fff" stroke="#000" stroke-width=".18"/>
<path d="M138.2 180.2v1.5" fill="none" stroke="#008000" stroke-width="1.5"/>
<circle cx="138.2" cy="181" r=".51" fill="#fff" stroke="#000" stroke-width=".18"/>
<path d="M140.7 180.2v1.5" fill="none" stroke="#008000" stroke-width="1.5"/>
<circle cx="140.7" cy="181" r=".51" fill="#fff" stroke="#000" stroke-width=".18"/>
<path d="M143.2 180.2v1.5" fill="none" stroke="#008000" stroke-width="1.5"/>
<circle cx="143.2" cy="181" r=".51" fill="#fff" stroke="#000" stroke-width=".18"/>
<circle cx="136.2" cy="188.9" r=".93" fill="#008000" stroke="#008000" stroke-width=".18"/>
<circle cx="136.2" cy="188.9" r=".51" fill="#fff" stroke="#000" stroke-width=".18"/>
<circle cx="142.7" cy="188.9" r=".93" fill="#008000" stroke="#008000" stroke-width=".18"/>
<circle cx="142.7" cy="188.9" r=".51" fill="#fff" stroke="#000" stroke-width=".18"/>
<circle cx="136.2" cy="193.4" r=".93" fill="#008000" stroke="#008000" stroke-width=".18"/>
<circle cx="136.2" cy="193.4" r=".51" fill="#fff" stroke="#000" stroke-width=".18"/>
<circle cx="142.7" cy="193.4" r=".93" fill="#008000" stroke="#008000" stroke-width=".18"/>
<circle cx="142.7" cy="193.4" r=".51" fill="#fff" stroke="#000" stroke-width=".18"/>
<circle cx="110.8" cy="188.9" r=".93" fill="#008000" stroke="#008000" stroke-width=".18"/>
<circle cx="110.8" cy="188.9" r=".51" fill="#fff" stroke="#000" stroke-width=".18"/>
<circle cx="117.3" cy="188.9" r=".93" fill="#008000" stroke="#008000" stroke-width=".18"/>
<circle cx="117.3" cy="188.9" r=".51" fill="#fff" stroke="#000" stroke-width=".18"/>
<circle cx="110.8" cy="193.4" r=".93" fill="#008000" stroke="#008000" stroke-width=".18"/>
<circle cx="110.8" cy="193.4" r=".51" fill="#fff" stroke="#000" stroke-width=".18"/>
<circle cx="117.3" cy="193.4" r=".93" fill="#008000" stroke="#008000" stroke-width=".18"/>
<circle cx="117.3" cy="193.4" r=".51" fill="#fff" stroke="#000" stroke-width=".18"/>
<circle cx="66.4" cy="167.6" r="1.17" fill="#008000" stroke="#008000" stroke-width=".18"/>
<circle cx="66.4" cy="167.6" r=".51" fill="#fff" stroke="#000" stroke-width=".18"/>
<circle cx="74" cy="167.6" r="1.17" fill="#008000" stroke="#008000" stroke-width=".18"/>
<circle cx="74" cy="167.6" r=".51" fill="#fff" stroke="#000" stroke-width=".18"/>
<circle cx="79.4" cy="172.1" r=".93" fill="#008000" stroke="#008000" stroke-width=".18"/>
<circle cx="79.4" cy="172.1" r=".44" fill="#fff" stroke="#000" stroke-width=".18"/>
<circle cx="79.4" cy="179.7" r=".93" fill="#008000" stroke="#008000" stroke-width=".18"/>
<circle cx="79.4" cy="179.7" r=".44" fill="#fff" stroke="#000" stroke-width=".18"/>
<path d="M99.8 192.8h1.7v1.7h-1.7z" fill="#008000" stroke="#008000" stroke-width=".18"/>
<circle cx="100.7" cy="193.6" r=".55" fill="#fff" stroke="#000" stroke-width=".18"/>
<circle cx="100.7" cy="191.1" r=".85" fill="#008000" stroke="#008000" stroke-width=".18"/>
<circle cx="100.7" cy="191.1" r=".55" fill="#fff" stroke="#000" stroke-width=".18"/>
<circle cx="100.7" cy="188.6" r=".85" fill="#008000" stroke="#008000" stroke-width=".18"/>
<circle cx="100.7" cy="188.6" r=".55" fill="#fff" stroke="#000" stroke-width=".18"/>
<circle cx="100.7" cy="186" r=".85" fill="#008000" stroke="#008000" stroke-width=".18"/>
<circle cx="100.7" cy="186" r=".55" fill="#fff" stroke="#000" stroke-width=".18"/>
<circle cx="100.7" cy="183.5" r=".85" fill="#008000" stroke="#008000" stroke-width=".18"/>
<circle cx="100.7" cy="183.5" r=".55" fill="#fff" stroke="#000" stroke-width=".18"/>
<circle cx="100.7" cy="181" r=".85" fill="#008000" stroke="#008000" stroke-width=".18"/>
<circle cx="100.7" cy="181" r=".55" fill="#fff" stroke="#000" stroke-width=".18"/>
<circle cx="100.7" cy="178.4" r=".85" fill="#008000" stroke="#008000" stroke-width=".18"/>
<circle cx="100.7" cy="178.4" r=".55" fill="#fff" stroke="#000" stroke-width=".18"/>
<circle cx="100.7" cy="175.9" r=".85" fill="#008000" stroke="#008000" stroke-width=".18"/>
<circle cx="100.7" cy="175.9" r=".55" fill="#fff" stroke="#000" stroke-width=".18"/>
<circle cx="100.7" cy="173.3" r=".85" fill="#008000" stroke="#008000" stroke-width=".18"/>
<circle cx="100.7" cy="173.3" r=".55" fill="#fff" stroke="#000" stroke-width=".18"/>
<circle cx="100.7" cy="170.8" r=".85" fill="#008000" stroke="#008000" stroke-width=".18"/>
<circle cx="100.7" cy="170.8" r=".55" fill="#fff" stroke="#000" stroke-width=".18"/>
<circle cx="100.7" cy="168.3" r=".85" fill="#008000" stroke="#008000" stroke-width=".18"/>
<circle cx="100.7" cy="168.3" r=".55" fill="#fff" stroke="#000" stroke-width=".18"/>
<circle cx="100.7" cy="165.7" r=".85" fill="#008000" stroke="#008000" stroke-width=".18"/>
<circle cx="100.7" cy="165.7" r=".55" fill="#fff" stroke="#000" stroke-width=".18"/>
<circle cx="100.7" cy="163.2" r=".85" fill="#008000" stroke="#008000" stroke-width=".18"/>
<circle cx="100.7" cy="163.2" r=".55" fill="#fff" stroke="#000" stroke-width=".18"/>
<circle cx="100.7" cy="160.6" r=".85" fill="#008000" stroke="#008000" stroke-width=".18"/>
<circle cx="100.7" cy="160.6" r=".55" fill="#fff" stroke="#000" stroke-width=".18"/>
<circle cx="93.1" cy="160.6" r=".85" fill="#008000" stroke="#008000" stroke-width=".18"/>
<circle cx="93.1" cy="160.6" r=".55" fill="#fff" stroke="#000" stroke-width=".18"/>
<circle cx="93.1" cy="163.2" r=".85" fill="#008000" stroke="#008000" stroke-width=".18"/>
<circle cx="93.1" cy="163.2" r=".55" fill="#fff" stroke="#000" stroke-width=".18"/>
<circle cx="93.1" cy="165.7" r=".85" fill="#008000" stroke="#008000" stroke-width=".18"/>
<circle cx="93.1" cy="165.7" r=".55" fill="#fff" stroke="#000" stroke-width=".18"/>
<circle cx="93.1" cy="168.3" r=".85" fill="#008000" stroke="#008000" stroke-width=".18"/>
<circle cx="93.1" cy="168.3" r=".55" fill="#fff" stroke="#000" stroke-width=".18"/>
<circle cx="93.1" cy="170.8" r=".85" fill="#008000" stroke="#008000" stroke-width=".18"/>
<circle cx="93.1" cy="170.8" r=".55" fill="#fff" stroke="#000" stroke-width=".18"/>
<circle cx="93.1" cy="173.3" r=".85" fill="#008000" stroke="#008000" stroke-width=".18"/>
<circle cx="93.1" cy="173.3" r=".55" fill="#fff" stroke="#000" stroke-width=".18"/>
<circle cx="93.1" cy="175.9" r=".85" fill="#008000" stroke="#008000" stroke-width=".18"/>
<circle cx="93.1" cy="175.9" r=".55" fill="#fff" stroke="#000" stroke-width=".18"/>
<circle cx="93.1" cy="178.4" r=".85" fill="#008000" stroke="#008000" stroke-width=".18"/>
<circle cx="93.1" cy="178.4" r=".55" fill="#fff" stroke="#000" stroke-width=".18"/>
<circle cx="93.1" cy="181" r=".85" fill="#008000" stroke="#008000" stroke-width=".18"/>
<circle cx="93.1" cy="181" r=".55" fill="#fff" stroke="#000" stroke-width=".18"/>
<circle cx="93.1" cy="183.5" r=".85" fill="#008000" stroke="#008000" stroke-width=".18"/>
<circle cx="93.1" cy="183.5" r=".55" fill="#fff" stroke="#000" stroke-width=".18"/>
<circle cx="93.1" cy="186" r=".85" fill="#008000" stroke="#008000" stroke-width=".18"/>
<circle cx="93.1" cy="186" r=".55" fill="#fff" stroke="#000" stroke-width=".18"/>
<circle cx="93.1" cy="188.6" r=".85" fill="#008000" stroke="#008000" stroke-width=".18"/>
<circle cx="93.1" cy="188.6" r=".55" fill="#fff" stroke="#000" stroke-width=".18"/>
<circle cx="93.1" cy="191.1" r=".85" fill="#008000" stroke="#008000" stroke-width=".18"/>
<circle cx="93.1" cy="191.1" r=".55" fill="#fff" stroke="#000" stroke-width=".18"/>
<circle cx="93.1" cy="193.6" r=".85" fill="#008000" stroke="#008000" stroke-width=".18"/>
<circle cx="93.1" cy="193.6" r=".55" fill="#fff" stroke="#000" stroke-width=".18"/>
<circle cx="61.3" cy="188.8" r="1.4" fill="#008000" stroke="#008000" stroke-width=".18"/>
<circle cx="61.3" cy="188.8" r=".93" fill="#fff" stroke="#000" stroke-width=".18"/>
<circle cx="61.3" cy="175.6" r="1.4" fill="#008000" stroke="#008000" stroke-width=".18"/>
<circle cx="61.3" cy="175.6" r=".93" fill="#fff" stroke="#000" stroke-width=".18"/>
<circle cx="104.5" cy="156.8" r=".93" fill="#008000" stroke="#008000" stroke-width=".18"/>
<circle cx="104.5" cy="156.8" r=".51" fill="#fff" stroke="#000" stroke-width=".18"/>
<circle cx="102" cy="156.8" r=".93" fill="#008000" stroke="#008000" stroke-width=".18"/>
<circle cx="102" cy="156.8" r=".51" fill="#fff" stroke="#000" stroke-width=".18"/>
<circle cx="99.4" cy="156.8" r=".93" fill="#008000" stroke="#008000" stroke-width=".18"/>
<circle cx="99.4" cy="156.8" r=".51" fill="#fff" stroke="#000" stroke-width=".18"/>
<circle cx="96.9" cy="156.8" r=".93" fill="#008000" stroke="#008000" stroke-width=".18"/>
<circle cx="96.9" cy="156.8" r=".51" fill="#fff" stroke="#000" stroke-width=".18"/>
<circle cx="94.3" cy="156.8" r=".93" fill="#008000" stroke="#008000" stroke-width=".18"/>
<circle cx="94.3" cy="156.8" r=".51" fill="#fff" stroke="#000" stroke-width=".18"/>
<circle cx="87.4" cy="181.3" r=".93" fill="#008000" stroke="#008000" stroke-width=".18"/>
<circle cx="87.4" cy="181.3" r=".44" fill="#fff" stroke="#000" stroke-width=".18"/>
<circle cx="87.4" cy="173.7" r=".93" fill="#008000" stroke="#008000" stroke-width=".18"/>
<circle cx="87.4" cy="173.7" r=".44" fill="#fff" stroke="#000" stroke-width=".18"/>
<circle cx="87.4" cy="194.3" r=".93" fill="#008000" stroke="#008000" stroke-width=".18"/>
<circle cx="87.4" cy="194.3" r=".44" fill="#fff" stroke="#000" stroke-width=".18"/>
<circle cx="87.4" cy="186.7" r=".93" fill="#008000" stroke="#008000" stroke-width=".18"/>
<circle cx="87.4" cy="186.7" r=".44" fill="#fff" stroke="#000" stroke-width=".18"/>
<circle cx="90.2" cy="186.7" r=".93" fill="#008000" stroke="#008000" stroke-width=".18"/>
<circle cx="90.2" cy="186.7" r=".44" fill="#fff" stroke="#000" stroke-width=".18"/>
<circle cx="90.2" cy="194.3" r=".93" fill="#008000" stroke="#008000" stroke-width=".18"/>
<circle cx="90.2" cy="194.3" r=".44" fill="#fff" stroke="#000" stroke-width=".18"/>
<circle cx="84.8" cy="190.5" r=".83" fill="#008000" stroke="#008000" stroke-width=".18"/>
<circle cx="84.8" cy="190.5" r=".44" fill="#fff" stroke="#000" stroke-width=".18"/>
<circle cx="84.8" cy="193" r=".83" fill="#008000" stroke="#008000" stroke-width=".18"/>
<circle cx="84.8" cy="193" r=".44" fill="#fff" stroke="#000" stroke-width=".18"/>
<circle cx="82" cy="168.9" r=".83" fill="#008000" stroke="#008000" stroke-width=".18"/>
<circle cx="82" cy="168.9" r=".44" fill="#fff" stroke="#000" stroke-width=".18"/>
<circle cx="79.4" cy="168.9" r=".83" fill="#008000" stroke="#008000" stroke-width=".18"/>
<circle cx="79.4" cy="168.9" r=".44" fill="#fff" stroke="#000" stroke-width=".18"/>
<circle cx="82" cy="166" r=".83" fill="#008000" stroke="#008000" stroke-width=".18"/>
<circle cx="82" cy="166" r=".44" fill="#fff" stroke="#000" stroke-width=".18"/>
<circle cx="79.4" cy="166" r=".83" fill="#008000" stroke="#008000" stroke-width=".18"/>
<circle cx="79.4" cy="166" r=".44" fill="#fff" stroke="#000" stroke-width=".18"/>
<circle cx="103.9" cy="175.9" r=".83" fill="#008000" stroke="#008000" stroke-width=".18"/>
<circle cx="103.9" cy="175.9" r=".44" fill="#fff" stroke="#000" stroke-width=".18"/>
<circle cx="103.9" cy="178.4" r=".83" fill="#008000" stroke="#008000" stroke-width=".18"/>
<circle cx="103.9" cy="178.4" r=".44" fill="#fff" stroke="#000" stroke-width=".18"/>
<g fill="#800000" stroke="#800000" stroke-width=".18">
<path d="M53.7 194.1a2.88 2.88 0 0 1 4.6 .1 2.88 2.88 0 0 1-1.5 4.4 2.88 2.88 0 0 1-3.7-2.7h2.5a.35 .35 0 0 1 .5-.4 .35 .35 0 0 1 .1 .6 .35 .35 0 0 1-.6-.2h-2.5v-.7z" fill-rule="evenodd"/>
<path d="M53.7 154.4a2.89 2.89 0 0 1 4.6 .1 2.89 2.89 0 0 1-1.5 4.4 2.89 2.89 0 0 1-3.7-2.7h2.5a.35 .35 0 0 1 .4-.4 .35 .35 0 0 1 .2 .6 .35 .35 0 0 1-.6-.1l-2.5-.1v-.6z" fill-rule="evenodd"/>
<path d="M147 154.4a2.88 2.88 0 0 1 4.6 .2 2.88 2.88 0 0 1-1.5 4.4 2.88 2.88 0 0 1-3.7-2.8h2.5a.35 .35 0 0 1 .5-.3 .35 .35 0 0 1 0 .6 .35 .35 0 0 1-.5-.2l-2.5-.1 .2-1.3z" fill-rule="evenodd"/>
<path d="M147.5 193.6a2.89 2.89 0 0 1 4.4 1 2.89 2.89 0 0 1-2 4.1 2.89 2.89 0 0 1-3.5-2.8h2.5a.35 .35 0 0 1 .6-.3 .35 .35 0 0 1 0 .6 .35 .35 0 0 1-.6-.3h-2.5a2.87 2.87 0 0 1 1.1-2.3z" fill-rule="evenodd"/>
</g>
<g fill="none" stroke="#505050" stroke-width=".18">
<path d="M72.4 156.8h.1M72.5 156.8l.1-.2h-.2v.4M72.5 156.8l.1 .2M73 156.6l-.1 .3h.3M73.1 156.8v.2M80.5 156v.3l.3 .2h2.2l.1 .1v.2l-.1 .1-1.8 .1v.2l.2 .1h1l.2 .2-.2 .2-.8 .1 .1 .3h.6v.3l-.7 .1-.2 .1v.2l1.3 .1 .1 .2-.2 .2h-1.5l-.1 .2 .2 .2h1.9l.3 .2 .1 .3M93.1 159.7h7.6v34.8h-7.6zM94.1 159.7h5.6M105.1 158.3v.4l-.1 .1M105.4 158.4h.3l-.3 .4h.3M114.8 156.2v.4l-.2 .1M115.1 156.3l.1-.1v.5"/>
<path d="M115.1 156.7h.2M144.7 159.8v.2M144.7 159.9h.5M145.2 159.3v.2l-.5-.2 .1 .2M53.1 170.6h.3l.1 .1M53.1 169.5a.22 .22 0 0 1 .2-.1 .22 .22 0 0 1 .2 .3h-.4zM53.2 169.5l.2 .2M53.5 170.1h-.4l.1 .2M53.5 170v.3M56.5 176.3a1.61 1.61 0 0 1 1.3-.4v-.3h7.1v.3l2.7 2.7h.4v7.1h-.2l-2.9 2.9v.1h-7.1v-.2a1.65 1.65 0 0 1-1.7-1 1.65 1.65 0 0 1 .5-1.9 6.9 6.9 0 0 0-.5-7.7 1.53 1.53 0 0 1 .4-1.6zM56.7 178.8l-.3 .5M57.9 177.6l-.8 .8"/>
<path d="M58.2 178.3h4.6a.8 .8 0 0 1 .8 .8 .8 .8 0 0 1-.8 .8h-4.6M58.2 178.4v1.2M58.4 178.5v1M58.6 178.6v.9M58.7 177.1l-.3 .2M60.5 175.5v-.7h1.6v.7M60.7 176.4l-1 .3M61.2 178.5v1.2M61.2 179.9a1.96 1.96 0 0 0 3 .7 1.96 1.96 0 0 0 0-3.1 1.96 1.96 0 0 0-3 .7 1.95 1.95 0 0 1 3.2-.4 1.95 1.95 0 0 1-.9 3.1M61.3 176.4h.4M61.4 178.5v1.1M61.6 178.6v.9"/>
<path d="M62.7 176.5l.8 .3M64.4 177.1l.5 .4M65.3 177.8l.8 .8M66.4 179.1l.2 .4M73.7 165.1h.7M74 164.7v.8M80.5 169.9l-.2 .2 .1 .3h.1M80.5 167.1l-.2 .1 .1 .3 .1 .1M80.8 167.1l.3 .1-.1 .1h-.1M80.8 170.1l.3-.1-.3 .4h.3M80.9 167.3l.2 .2-.3 .1M81 176.3h-.5v-.2h.3v.2"/>
<path d="M81 176l-.2 .1M81 175.5v.2l-.5-.2 .1 .2M84.2 166h5v4.5h-5zM84.4 166.2h4.6v4.1h-4.6zM86 177.3l-.1-.2-.1 .2M86 177.2l.2-.1 .1 .2M86.3 177.9h-.5v-.2h.2l.1 .2M86.3 177.6l-.2 .1M92.5 160.1h.6l.1 1.1h-.7zM92.5 162.6h.6l.1 1.1h-.7zM92.5 165.2h.7v1.1h-.7zM92.5 167.7h.7v1.1h-.7z"/>
<path d="M92.5 170.2h.7v1.1h-.7zM92.5 172.8h.7v1.1h-.7zM92.5 175.3h.7v1.1h-.7zM92.5 177.8h.7v1.2h-.7zM100.6 172.8h.7v1.1h-.6zM100.6 170.2h.7v1.1h-.7zM100.6 167.7h.7v1.1h-.7zM100.6 165.2h.7v1.1h-.7zM100.6 162.6h.7v1.1h-.7zM100.6 160.1h.7v1.1h-.7zM100.7 177.8h.6v1.2h-.6zM100.7 175.3h.6v1.1h-.6z"/>
<path d="M104.9 177.3l.1 .2h.4v-.2M105.2 176.9h.2M105.3 176.8v.2l-.4-.1M122.3 163.6h-.5v-.2h.2v.2M122.3 163.3l-.3 .1M122.3 162.9h-.5l.1 .1M122.3 162.8v.2M123.2 173.1l5.4 .1 .2-.1h1.3l.2 .2v2.7l-.3 .1h-1.2l-.2-.1-5.3 .1-.1-.2zM123.4 178.8h4.1v1.8h-4.1zM123.4 173.5v2.2M124.7 173.5v2.2M124.8 179.7h.7l1-.6v1.2l-1-.6h1.5"/>
<path d="M125.5 179.1v1.2M128.8 173.5v2.2M130 173.5v2.2M135.6 179.6v2.9l.3 .2h9.6l.3-.2v-2.9M144.7 172.3l.1 .2h.3l.1-.2M144.7 161.8l.1 .2h.3l.1-.2M144.7 170.2v.3M144.7 170.4h.5M144.7 170.8l.5 .1-.1 .1h-.4M144.7 160.3l.5 .1-.2 .2h-.3M144.7 171.4l.3-.1 .2 .2-.5 .1zM144.7 160.9h.4l.1 .1-.5 .1z"/>
<path d="M145.2 169.7v.3M145.2 169.9h-.5l.1 .1M145.2 161.4v.2M145.2 171.9v.2M148.3 170.6h.4v.1M148.7 170.1l-.4-.1v.3M54.3 184.9l.1 .6h.8l.2-.2 .1-.4h-.7v.1M55.5 184h-1.2l.3 .3M55.5 183.7v.6M55.7 182v.4M55.7 183l.2 1M56 180.2l-.2 .8"/>
<path d="M56.4 185l.1 .3M56.9 185.8l.7 .8M58.1 187l.5 .3M58.2 184.5h4.7a.8 .8 0 0 1 .8 .8 .8 .8 0 0 1-.8 .8h-4.7M58.2 184.7v1.2M58.4 184.8v1M58.6 184.9v.8M59.4 187.7l.8 .2M60.5 188.8v.7h1.6v-.6M61.2 184.7v1.2M61.3 188h.4M61.4 184.8v1"/>
<path d="M61.6 184.9v.8M63.3 187.8l-1.1 .2M63.5 183.4a1.96 1.96 0 0 1 .9 3.2 1.96 1.96 0 0 1-3.2-.4 1.96 1.96 0 0 0 2.9 .6 1.96 1.96 0 0 0 0-3 1.96 1.96 0 0 0-2.9 .6M64.6 187.2l-.3 .1M65.9 186.1l-.8 .7M66.6 185.1l-.4 .5M67 180.4l.3 1.1M67.2 183.5l-.3 .8M67.3 182v.4M72.9 181.7h7.4v12.5h-7.4zM85.8 190.1v.2h.2l.1-.2h.2v.2M85.9 191.9l.1 .2h.3l.1-.2"/>
<path d="M86.3 190.9h-.5v-.2h.2l.1 .2M86.3 190.6l-.2 .1M86.4 191.5h-.5l.1 .1M86.4 191.4v.2M91.3 190.1l.2 .2M91.5 190.1h.2v.2h-.2zM91.8 190.9h-.5v-.2h.3v.2M91.8 190.6l-.2 .1M92.5 180.4h.7v1.1h-.7zM92.5 182.9h.7v1.1h-.7zM92.5 185.5h.7v1.1h-.7zM92.5 188h.7v1.1h-.7z"/>
<path d="M92.5 190.5h.7v1.2h-.7zM92.5 193.1h.7v1.1h-.7zM94.1 194.5h5.3M96.6 194.5l.2-.3 .3 .1 .1 .2M100.7 193.1h.6v1.1h-.6zM100.7 190.5h.6v1.2h-.6zM100.7 188h.6v1.1h-.6zM100.7 185.5h.6v1.1h-.6zM100.7 182.9h.6v1.1h-.6zM100.7 180.4h.6v1.1h-.6zM113.9 187.3h-.2v.1l.2 .3h-.3M114.2 187.3h.2l-.2 .2"/>
<path d="M114.3 187.5l.1 .1-.2 .1M126.6 187.3l-.3 .1 .3 .3h-.3M126.9 187.4l.1-.1v.4M126.9 187.7h.2M139.3 187.3l-.3 .1 .3 .3h-.3M139.6 187.4l.2-.1-.2 .4h.2"/>
<circle cx="55.9" cy="156.1" r="2.86"/>
<circle cx="149.3" cy="156.1" r="2.86"/>
<circle cx="70.2" cy="167.6" r="6.1"/>
<circle cx="70.2" cy="167.6" r="1.27"/>
<circle cx="112.8" cy="174" r="3.2"/>
<circle cx="119.4" cy="170.8" r="2.03"/>
<circle cx="55.9" cy="195.9" r="2.86"/>
<circle cx="149.3" cy="195.9" r="2.86"/>
</g>
<path d="M115.3 172.7v2.5M118.8 172.7h1.3" fill="none" stroke="#505050" stroke-width=".32"/>
<g fill="none" stroke="#505050" stroke-width=".21">
<path d="M70 158.1h.2M70.2 157.3h5.1v1.6h-5.1zM75.3 158.1h.3M80.5 155.8h3a2.7 2.7 0 0 1 0 4.6h-3a2.7 2.7 0 0 1-.1-4.6M93.1 156.2l.6-.6h1.3l.6 .6 .7-.6h1.2l.7 .6 .6-.6h1.3l.6 .6 .6-.6h1.3l.6 .6 .7-.6h1.2l.7 .6v1.3l-.7 .6h-1.2l-.7-.6-.6 .6h-1.3l-.6-.6-.6 .6h-1.3l-.6-.6-.7 .6h-1.2l-.7-.6-.6 .6h-1.3l-.6-.6zM109.5 157.3h9M118.5 157.3v10.7h-2.1M118.5 157.3v-2.9h-9v8.2M122.9 156h10.2v10.1h-10.2zM122.9 155.5l1.7-.5h6.8l1.7 .5v.4h-10.2zM122.9 155.9h10.2M122.9 155.7h10.2"/>
<path d="M122.9 155.5h10.2M123.4 155.4h9.2M124 155.2h7.9M142 157.5v1.2M53.7 161.3l.7-.7h1.2l.7 .7v1.2l-.7 .7 .7 .6v1.3l-.7 .6 .7 .7v1.2l-.7 .7 .7 .6v1.3l-.7 .6h-1.2l-.7-.6v-1.3l.7-.6-.7-.7v-1.2l.7-.7-.7-.6v-1.3l.7-.6-.7-.7zM78.7 173.3h1.5v5.1h-1.5zM79.4 173.1v.2M79.4 178.4v.3M79.7 166h.5M79.7 168.9h.5M80.2 168.3v1.2M80.2 165.4v1.3"/>
<path d="M81.2 168.3v1.2M81.2 165.4v1.3M81.2 166h.5M81.2 168.9h.5M86.6 174.9h1.5v5.1h-1.5zM87.4 174.7v.2M103.2 176.6h1.3M103.2 177.6h1.3M103.9 176.2v.4M103.9 177.6v.5M109.5 167.3v.7h2.1M119.9 160.6h1.6v5.1h-1.6z"/>
<path d="M120.7 160.4v.2M120.7 165.7v.3M141.3 173.7h1.3M141.3 163.2h1.3M142 162.5v1.3M142 167.9v1.3M142 173v1.3M148.9 161.3l.7-.7h1.2l.7 .7v1.2l-.7 .7 .7 .6v1.3l-.7 .6 .7 .7v1.2l-.7 .7 .7 .6v1.3l-.7 .6h-1.2l-.7-.6v-1.3l.7-.6-.7-.7v-1.2l.7-.7-.7-.6v-1.3l.7-.6-.7-.7zM84.2 191.2h1.3M84.2 192.2h1.3M84.8 190.8v.4M84.8 192.2v.5"/>
<path d="M86.6 187.9h1.5v5.1h-1.5zM87.4 180v.3M87.4 187.7v.2M87.4 193v.3M89.5 187.9h1.5v5.1h-1.5zM90.2 187.7v.2M90.2 193v.3M111.5 189.8v.8l.4 .9M111.5 191.6v.8M111.5 188h5.1l.5 .6v5l-.5 .5h-5.1l-.5-.5v-5zM124.2 189.8v.8l.4 .9M124.2 191.6v.8"/>
<path d="M124.2 188h5.1l.5 .6v5l-.5 .5h-5.1l-.5-.5v-5zM136.9 189.8v.8l.4 .9M136.9 191.6v.8M136.9 188h5.1l.5 .6v5l-.5 .5h-5.1l-.5-.5v-5z"/>
<circle cx="139.4" cy="160.6" r="5"/>
<circle cx="139.4" cy="171.1" r="5"/>
<circle cx="114" cy="191.1" r="1.78"/>
<circle cx="126.7" cy="191.1" r="1.78"/>
<circle cx="139.4" cy="191.1" r="1.78"/>
</g>
<g fill="#505050" stroke="#505050" stroke-width=".18">
<path d="M123.8 178.8h.5v1.8h-.5z"/>
<path d="M127.5 179.3h.7v.8h-.7z"/>
<path d="M122.7 179.3h.7v.8h-.7z"/>
<path d="M121.2 174.3h2v.6h-2z"/>
<path d="M130.3 174.3h1.9v.6h-1.9z"/>
<path d="M124.1 166h1v1.7h-1z"/>
<path d="M125.8 166h1v1.7h-1z"/>
<path d="M127.5 166h1v1.7h-1z"/>
<path d="M129.2 166h1v1.7h-1z"/>
<path d="M130.9 166h1v1.7h-1z"/>
<path d="M135.4 178.4h1.9v1.3h-1.9z"/>
<path d="M137.3 178.4h1.8v.8h-1.8z"/>
<path d="M139 178.4h.8v1.3h-.8z"/>
<path d="M139.8 178.4h1.8v.8h-1.8z"/>
<path d="M141.6 178.4h.7v1.3h-.7z"/>
<path d="M142.3 178.4h1.8v.8h-1.8z"/>
<path d="M144.1 178.4h1.9v1.3h-1.9z"/>
<path d="M64.7 182h2.2v.4h-2.2z"/>
<path d="M65.6 181.1h.4v2.2h-.4z"/>
<path d="M124.1 167.6h1v2.2h-1z"/>
<path d="M125.8 167.6h1v2.2h-1z"/>
<path d="M127.5 167.6h1v2.2h-1z"/>
<path d="M129.2 167.6h1v2.2h-1z"/>
<path d="M130.9 167.6h1v2.2h-1z"/>
<path d="M150 161.7h.5v.5h-.5z"/>
<path d="M150 164.2h.5v.5h-.5z"/>
<path d="M150 166.7h.5v.5h-.5z"/>
<path d="M150 169.3h.5v.5h-.5z"/>
<path d="M54.7 161.7h.6v.5h-.6z"/>
<path d="M54.7 164.2h.6v.5h-.6z"/>
<path d="M54.7 166.7h.6v.5h-.6z"/>
<path d="M54.7 169.3h.6v.5h-.6z"/>
<path d="M137.3 179.2h1.8v.5h-1.8z"/>
<path d="M139.8 179.2h1.8v.5h-1.8z"/>
<path d="M142.3 179.2h1.8v.5h-1.8z"/>
<path d="M71.5 182h1.3v.4h-1.3z"/>
<path d="M71.5 183.3h1.3v.4h-1.3z"/>
<path d="M71.5 184.5h1.3v.5h-1.3z"/>
<path d="M71.5 185.8h1.3v.4h-1.3z"/>
<path d="M71.5 187.1h1.3v.4h-1.3z"/>
<path d="M71.5 188.3h1.3v.5h-1.3z"/>
<path d="M71.5 189.6h1.3v.4h-1.3z"/>
<path d="M71.5 190.9h1.3v.4h-1.3z"/>
<path d="M71.5 192.2h1.3v.4h-1.3z"/>
<path d="M71.5 193.4h1.3v.4h-1.3z"/>
<path d="M80.3 182h1.3v.4h-1.3z"/>
<path d="M80.3 183.3h1.3v.4h-1.3z"/>
<path d="M80.3 184.5h1.3v.5h-1.3z"/>
<path d="M80.3 185.8h1.3v.4h-1.3z"/>
<path d="M80.3 187.1h1.3v.4h-1.3z"/>
<path d="M80.3 188.3h1.3v.5h-1.3z"/>
<path d="M80.3 189.6h1.3v.4h-1.3z"/>
<path d="M80.3 190.9h1.3v.4h-1.3z"/>
<path d="M80.3 192.2h1.3v.4h-1.3z"/>
<path d="M80.3 193.4h1.3v.4h-1.3z"/>
<path d="M84.7 170.5h.2v.9h-.2z"/>
<path d="M85.3 170.5h.2v.9h-.2z"/>
<path d="M86 170.5h.2v.9h-.2z"/>
<path d="M86.6 170.5h.2v.9h-.2z"/>
<path d="M87.3 170.5h.2v.9h-.2z"/>
<path d="M87.9 170.5h.2v.9h-.2z"/>
<path d="M88.6 170.5h.2v.9h-.2z"/>
<path d="M88.6 165.1h.2v.9h-.2z"/>
<path d="M87.9 165.1h.2v.9h-.2z"/>
<path d="M87.3 165.1h.2v.9h-.2z"/>
<path d="M86.6 165.1h.2v.9h-.2z"/>
<path d="M86 165.1h.2v.9h-.2z"/>
<path d="M85.3 165.1h.2v.9h-.2z"/>
<path d="M84.7 165.1h.2v.9h-.2z"/>
<path d="M94.1 156.6h.5v.5h-.5z"/>
<path d="M96.6 156.6h.5v.5h-.5z"/>
<path d="M99.2 156.6h.5v.5h-.5z"/>
<path d="M101.7 156.6h.5v.5h-.5z"/>
<path d="M104.3 156.6h.5v.5h-.5z"/>
</g>
<g fill="#505050" stroke="#505050" stroke-width=".18">
<path d="M73.4 164.6a.84 .84 0 0 1 1.3 0 .84 .84 0 0 1-.4 1.3 .84 .84 0 0 1-1.1-.8h.1a.69 .69 0 0 1 1-.7 .69 .69 0 0 1 .2 1.2 .69 .69 0 0 1-1.1-.3l-.1-.2h-.1z" fill-rule="evenodd"/>
<path d="M78.9 192.9a.61 .61 0 0 1 1 .1 .61 .61 0 0 1-.4 .9 .61 .61 0 0 1-.8-.6h.2a.46 .46 0 0 1 .7-.4 .46 .46 0 0 1 .1 .8 .46 .46 0 0 1-.8-.2v-.2h-.2z" fill-rule="evenodd"/>
<path d="M84.8 169.1a.53 .53 0 0 1 .8 .2 .53 .53 0 0 1-.4 .7 .53 .53 0 0 1-.6-.5h.1a.38 .38 0 0 1 .6-.3 .38 .38 0 0 1 .1 .6 .38 .38 0 0 1-.6-.2l-.1-.1h-.1z" fill-rule="evenodd"/>
<circle cx="136.1" cy="182.1" r=".25"/>
</g>
<path d="M121.7 179.7h1.2M128 179.7h1.3" fill="none" stroke="#505050" stroke-width=".87"/>
<path d="M120.4 174.6h1.1M131.9 174.6h1.2" fill="none" stroke="#505050" stroke-width=".61"/>
<path d="M98.9 153.4h.1M99.8 153.4h.1M100.7 153.4h.1" fill="none" stroke="#800000" stroke-width=".42"/>
<g fill="none" stroke="#000" stroke-width=".18">
<path d="M71.8 158.1h2M72.8 157.1v2M81 158.1h2M82 157.1v2M93.1 159.6v2.1M103.5 156.8h2M104.5 155.8v2M113 154.3h2M114 153.3v2M139.4 159.6v2.1M54 169.5h2M55 168.5v2"/>
<path d="M69.2 167.6h2.1M70.2 166.6v2M78.4 175.9h2.1M79.4 174.9v2M79.7 168.9h2M79.7 166h2M80.7 165v2.1M80.7 167.9v2M85.9 168.3h1.7M86.3 177.5h2.1M86.7 167.4v1.7M87.4 176.4v2.1"/>
<path d="M92.1 160.6h2M102.9 177.1h2M103.9 176.1v2.1M111.7 174h2.1M112.8 173v2M118.4 170.8h2M119.4 169.8v2M119.7 163.2h2M120.7 162.2v2M124.4 179.7h2.1M125.5 178.7v2M125.7 174.6h2"/>
<path d="M126.7 173.6v2M127 163.2h2M128 162.2v2M138.4 171.1h2M138.4 160.6h2M139.4 170.1v2M139.7 178.4h2M140.7 177.4v2M149.2 169.5h2M150.2 168.5v2M60.3 182.2h2.1M61.3 181.2v2"/>
<path d="M75.6 187.9h2M76.6 186.9v2M83.8 191.7h2M84.8 190.7v2M86.3 190.5h2.1M87.4 189.4v2.1M89.2 190.5h2M90.2 189.4v2.1M113 191.1h2M114 190.1v2M125.7 191.1h2M126.7 190.1v2"/>
<path d="M138.4 191.1h2M139.4 190.1v2"/>
</g>
<g fill="none" stroke="#f90" stroke-width=".18">
<path d="M53.9 153.8a2.4 2.4 0 0 1 1.5-.5h94.4a2.26 2.26 0 0 1 2.3 2.3v40.8a2.29 2.29 0 0 1-2.3 2.3h-94.4a2.29 2.29 0 0 1-2.3-2.3v-40.8a2.31 2.31 0 0 1 .8-1.8z"/>
<circle cx="55.9" cy="195.9" r="1.5"/>
</g>
<circle cx="55.9" cy="195.9" r="1.5" fill="#fff" stroke="#000" stroke-width=".18"/>
<circle cx="55.9" cy="156.1" r="1.5" fill="none" stroke="#f90" stroke-width=".18"/>
<circle cx="55.9" cy="156.1" r="1.5" fill="#fff" stroke="#000" stroke-width=".18"/>
<circle cx="149.3" cy="156.1" r="1.5" fill="none" stroke="#f90" stroke-width=".18"/>
<circle cx="149.3" cy="156.1" r="1.5" fill="#fff" stroke="#000" stroke-width=".18"/>
<circle cx="149.3" cy="195.9" r="1.5" fill="none" stroke="#f90" stroke-width=".18"/>
<circle cx="149.3" cy="195.9" r="1.5" fill="#fff" stroke="#000" stroke-width=".18"/>
<g fill="none" stroke="#505050" stroke-width=".18">
<path d="M57 155.1l-2.1 2M150.3 155.1l-2.1 2M57 194.8l-2.1 2.1M150.3 194.8l-2.1 2.1"/>
<circle cx="55.9" cy="156.1" r=".99"/>
<circle cx="149.3" cy="156.1" r=".99"/>
<circle cx="55.9" cy="195.9" r=".99"/>
<circle cx="149.3" cy="195.9" r=".99"/>
</g>
<g fill="#000080" stroke="#000080" stroke-width=".18">
<path d="M53.8 249a2.88 2.88 0 0 1 4.7 .1 2.88 2.88 0 0 1-1.5 4.4 2.88 2.88 0 0 1-3.8-2.7h2.5a.35 .35 0 0 1 .5-.4 .35 .35 0 0 1 .1 .6 .35 .35 0 0 1-.5-.1l-2.6-.1 .1-.6z" fill-rule="evenodd"/>
<path d="M53.8 209.3a2.89 2.89 0 0 1 4.7 .2 2.89 2.89 0 0 1-1.5 4.4 2.89 2.89 0 0 1-3.8-2.8h2.5a.35 .35 0 0 1 .5-.3 .35 .35 0 0 1 .1 .5 .35 .35 0 0 1-.5-.1l-2.6-.1 .1-.6z" fill-rule="evenodd"/>
<path d="M147.2 209.3a2.88 2.88 0 0 1 4.6 .2 2.88 2.88 0 0 1-1.5 4.4 2.88 2.88 0 0 1-3.8-2.8h2.6a.35 .35 0 0 1 .5-.2 .35 .35 0 0 1 0 .6 .35 .35 0 0 1-.5-.3l-2.6-.1 .3-1.2z" fill-rule="evenodd"/>
<path d="M147.6 248.5a2.89 2.89 0 0 1 4.4 1 2.89 2.89 0 0 1-1.9 4.1 2.89 2.89 0 0 1-3.6-2.8h2.6a.35 .35 0 0 1 .5-.2 .35 .35 0 0 1 0 .6 .35 .35 0 0 1-.5-.3l-2.6-.1a2.87 2.87 0 0 1 1.1-2.3z" fill-rule="evenodd"/>
</g>
<g fill="none" stroke="#000080" stroke-width=".83">
<path d="M55.2 219.4h3.8l19 19.1h15.2M60.9 216.9l6.6 6.6v2.6l11.1 11.1h8l.9-1M69.1 213.1l-3.8 3.8h-10.1M76.7 213.1h3.7l2.5 2.5h10.3M83.9 213.1h6.2l3.1-3.2h7l4 4v7.9l7.2 7.1-4.5 4.5h-6M94.5 211.8v2.2l.9 .9v28.4l5.5 5.3M97 211.8v30.4l3.9 3.9M99.6 211.8v2.2l-1 1v26.3l2.3 2.2M104.7 211.8h4.3l5.2 5.1h1l1.8 1.9v6.7l1.3 1.3M120.9 214.3l-1.9 1.7v8.1l.6 .6M139.6 213.1l2.5 2.5v5.4l-2.5 2.6M150.4 219.4l-6.2 6.5v2.9l-3.4 3.3v3.8"/>
<path d="M55.2 221.9h4.4l17.8 17.8h14.6l1.2 1.3M55.2 224.5h5l19.1 19h13.9M61.5 230.6l-3.8 3.8v5.6l3.8 3.8M79.6 234.6l.6-.6h9.2l1.9 1.9h1.9M119.2 239.4h-3.9l-4.4 4.4M119.2 239.4l4.4 4.4M119.2 239.4h12.7l4.4 4.4M119.3 226.8h.3M119.6 226.8h-3l-2.2 2.1v5.7l4.8 4.8M139.6 223.6l-3.2 3.1-16.8 .1M139.6 238.5l-1 .9h-6.7M139.6 228.6l-2.3 2.2h-2.8l-1.3 1.3h-6.3l-2.6 2.5h-2.5"/>
<path d="M139.6 223.2v.4M150.4 224.5l-3.7 3.3v8.6l-2.1 2.1h-5l-1.3-1.3v-1.3"/>
</g>
<g fill="none" stroke="#000080" stroke-width=".42">
<path d="M53.2 209.2v.1M53.2 210.2v.1M53.2 211.1v.1M53.2 212v.1M53.2 212.9v.1M53.2 213.8v.2M53.2 214.8v.1M53.2 215.7v.1M53.2 216.6v.1M53.2 217.5v.1M53.2 218.5v.1M53.2 219.4v.1"/>
<path d="M53.4 208.3l-.2 .1M54.2 208.3h.1M55.1 208.3h.1M56 208.3h.1M56.9 208.3h.1M57.8 208.3h.1M58.7 208.3h.1M59.7 208.3h.1M60.6 208.3h.1M61.5 208.3h.1M62.4 208.3h.1M63.3 208.3h.1"/>
<path d="M64.2 208.3h.1M65.1 208.3h.1M66.1 208.3h.1M67 208.3h.1M67.9 208.3h.1M68.8 208.3h.1M69.7 208.3h.1M70.6 208.3h.2M71.6 208.3h.1M72.5 208.3h.1M73.4 208.3h.1M74.3 208.3h.1"/>
<path d="M75.2 208.3h.1M76.1 208.3h.1M77.1 208.3h.1M78 208.3h.1M78.9 208.3h.1M79.8 208.3h.1M80.7 208.3h.1M81.6 208.3h.1M82.5 208.3h.1M83.5 208.3h.1M84.4 208.3h.1M85.3 208.3h.1"/>
<path d="M86.2 208.3h.1M87.1 208.3h.1M88 208.3h.2M89 208.3h.1M89.9 208.3h.1M90.8 208.3h.1M91.7 208.3h.1M92.6 208.3h.1M93.5 208.3h.1M94.5 208.3h.1M95.4 208.3h.1M96.3 208.3h.1"/>
<path d="M97.2 208.3h.1M98.1 208.3h.1M99 208.3h.1M99.9 208.3h.1M100.9 208.3h.1M101.8 208.3h.1M102.7 208.3h.1M103.6 208.3h.1M104.5 208.3h.1M105.4 208.3h.1M106.4 208.3h.1M107.3 208.3h.1"/>
<path d="M108.2 208.3h.1M109.1 208.3h.1M110 208.3h.1M110.9 208.3h.1M111.8 208.3h.1M112.8 208.3h.1M113.7 208.3h.1M114.6 208.3h.1M115.5 208.3h.1M116.4 208.3h.1M117.3 208.3h.1M118.2 208.3h.2"/>
<path d="M119.2 208.3h.1M120.1 208.3h.1M121 208.3h.1M121.9 208.3h.1M122.8 208.3h.1M123.8 208.3h.1M124.7 208.3h.1M125.6 208.3h.1M126.5 208.3h.1M127.4 208.3h.1M128.3 208.3h.1M129.2 208.3h.1"/>
<path d="M130.2 208.3h.1M131.1 208.3h.1M132 208.3h.1M132.9 208.3h.1M133.8 208.3h.1M134.7 208.3h.1M135.6 208.3h.2M136.6 208.3h.1M137.5 208.3h.1M138.4 208.3h.1M139.3 208.3h.1M140.2 208.3h.1"/>
<path d="M141.2 208.3h.1M142.1 208.3h.1M143 208.3h.1M143.9 208.3h.1M144.8 208.3h.1M145.7 208.3h.1M146.6 208.3h.1M147.5 208.3h.1M148.5 208.3h.1M149.4 208.3h.1M150.3 208.3h.1M151.2 208.3l.3 .2"/>
<path d="M152.1 209.1l.2 .3M152.3 210.2v.1M152.3 211.1v.1M152.3 212v.1M152.3 212.9v.2M152.3 213.9v.1M152.3 214.8v.1M152.3 215.7v.1M152.3 216.6v.2M152.3 217.6v.1M152.3 218.5v.1M152.3 219.4v.1"/>
<path d="M53.2 220.3v.1M53.2 221.2v.2M53.2 222.2v.1M53.2 223.1v.1M53.2 224v.1M53.2 224.9v.1M53.2 225.9v.1M53.2 226.8v.1M53.2 227.7v.1M53.2 228.6v.1M53.2 229.5v.1M53.2 230.5v.1"/>
<path d="M53.2 231.4v.1M53.2 232.3v.1M53.2 233.2v.2M53.2 234.2v.1M53.2 235.1v.1M53.2 236v.1M53.2 236.9v.2M53.2 237.9v.1M53.2 238.8v.1M53.2 239.7v.1M152.3 220.3v.1M152.3 221.2v.2"/>
<path d="M152.3 222.2v.1M152.3 223.1v.1M152.3 224v.1M152.3 224.9v.2M152.3 225.9v.1M152.3 226.8v.1M152.3 227.7v.1M152.3 228.6v.2M152.3 229.6v.1M152.3 230.5v.1M152.3 231.4v.1M152.3 232.3v.1"/>
<path d="M152.3 233.2v.2M152.3 234.2v.1M152.3 235.1v.1M152.3 236v.1M152.3 237v.1M152.3 237.9v.1M152.3 238.8v.1M152.3 239.7v.1M53.2 240.6v.1M53.2 241.5v.2M53.2 242.5v.1M53.2 243.4v.1"/>
<path d="M53.2 244.3v.1M53.2 245.2v.2M53.2 246.2v.1M53.2 247.1v.1M53.2 248v.1M53.2 249v.1M53.2 249.9v.1M53.2 250.8v.1M53.2 251.7v.1M53.2 252.6v.1M53.2 253.6l.2 .1M54.2 253.7h.1"/>
<path d="M55.1 253.7h.1M56 253.7h.1M56.9 253.7h.1M57.8 253.7h.1M58.7 253.7h.2M59.7 253.7h.1M60.6 253.7h.1M61.5 253.7h.1M62.4 253.7h.1M63.3 253.7h.1M64.2 253.7h.1M65.2 253.7h.1"/>
<path d="M66.1 253.7h.1M67 253.7h.1M67.9 253.7h.1M68.8 253.7h.1M69.7 253.7h.1M70.6 253.7h.2M71.6 253.7h.1M72.5 253.7h.1M73.4 253.7h.1M74.3 253.7h.1M75.2 253.7h.1M76.1 253.7h.2"/>
<path d="M77.1 253.7h.1M78 253.7h.1M78.9 253.7h.1M79.8 253.7h.1M80.7 253.7h.1M81.6 253.7h.1M82.6 253.7h.1M83.5 253.7h.1M84.4 253.7h.1M85.3 253.7h.1M86.2 253.7h.1M87.1 253.7h.1"/>
<path d="M88 253.7h.2M89 253.7h.1M89.9 253.7h.1M90.8 253.7h.1M91.7 253.7h.1M92.6 253.7h.1M93.5 253.7h.2M94.5 253.7h.1M95.4 253.7h.1M96.3 253.7h.1M97.2 253.7h.1M98.1 253.7h.1"/>
<path d="M99.1 253.7h.1M100 253.7h.1M100.9 253.7h.1M101.8 253.7h.1M102.7 253.7h.1M103.6 253.7h.1M104.5 253.7h.1M105.5 253.7h.1M106.4 253.7h.1M107.3 253.7h.1M108.2 253.7h.1M109.1 253.7h.1"/>
<path d="M110 253.7h.1M110.9 253.7h.2M111.9 253.7h.1M112.8 253.7h.1M113.7 253.7h.1M114.6 253.7h.1M115.5 253.7h.1M116.5 253.7h.1M117.4 253.7h.1M118.3 253.7h.1M119.2 253.7h.1M120.1 253.7h.1"/>
<path d="M121 253.7h.1M121.9 253.7h.1M122.9 253.7h.1M123.8 253.7h.1M124.7 253.7h.1M125.6 253.7h.1M126.5 253.7h.1M127.4 253.7h.1M128.3 253.7h.2M129.3 253.7h.1M130.2 253.7h.1M131.1 253.7h.1"/>
<path d="M132 253.7h.1M132.9 253.7h.1M133.8 253.7h.2M134.8 253.7h.1M135.7 253.7h.1M136.6 253.7h.1M137.5 253.7h.1M138.4 253.7h.1M139.4 253.7h.1M140.3 253.7h.1M141.2 253.7h.1M142.1 253.7h.1"/>
<path d="M143 253.7h.1M143.9 253.7h.1M144.8 253.7h.1M145.7 253.7h.2M146.7 253.7h.1M147.6 253.7h.1M148.5 253.7h.1M149.4 253.7h.1M150.3 253.7h.1M151.2 253.7h.2M152.3 253.6l-.1 .1M152.3 240.6v.1"/>
<path d="M152.3 241.6v.1M152.3 242.5v.1M152.3 243.4v.1M152.3 244.3v.1M152.3 245.2v.2M152.3 246.2v.1M152.3 247.1v.1M152.3 248v.1M152.3 249v.1M152.3 249.9v.1M152.3 250.8v.1M152.3 251.7v.1"/>
<path d="M152.3 252.6v.1"/>
</g>
<circle cx="119.6" cy="226.8" r=".7" fill="#008000" stroke="#008000" stroke-width=".18"/>
<circle cx="119.6" cy="226.8" r=".44" fill="#fff" stroke="#000" stroke-width=".18"/>
<path d="M118.9 224h1.4v1.4h-1.4z" fill="#008000" stroke="#008000" stroke-width=".18"/>
<circle cx="119.6" cy="224.7" r=".44" fill="#fff" stroke="#000" stroke-width=".18"/>
<path d="M110.5 228h1.8v1.8h-1.8z" fill="#008000" stroke="#008000" stroke-width=".18"/>
<circle cx="111.4" cy="228.9" r=".44" fill="#fff" stroke="#000" stroke-width=".18"/>
<circle cx="114.4" cy="228.9" r=".89" fill="#008000" stroke="#008000" stroke-width=".18"/>
<circle cx="114.4" cy="228.9" r=".44" fill="#fff" stroke="#000" stroke-width=".18"/>
<circle cx="139.6" cy="223.6" r=".97" fill="#008000" stroke="#008000" stroke-width=".18"/>
<circle cx="139.6" cy="223.6" r=".44" fill="#fff" stroke="#000" stroke-width=".18"/>
<path d="M138.6 227.6h1.9v1.9h-1.9z" fill="#008000" stroke="#008000" stroke-width=".18"/>
<circle cx="139.6" cy="228.6" r=".44" fill="#fff" stroke="#000" stroke-width=".18"/>
<circle cx="139.6" cy="213.1" r=".97" fill="#008000" stroke="#008000" stroke-width=".18"/>
<circle cx="139.6" cy="213.1" r=".44" fill="#fff" stroke="#000" stroke-width=".18"/>
<path d="M138.6 217.1h1.9v2h-1.9z" fill="#008000" stroke="#008000" stroke-width=".18"/>
<circle cx="139.6" cy="218.1" r=".44" fill="#fff" stroke="#000" stroke-width=".18"/>
<circle cx="121.8" cy="234.6" r=".85" fill="#008000" stroke="#008000" stroke-width=".18"/>
<circle cx="121.8" cy="234.6" r=".55" fill="#fff" stroke="#000" stroke-width=".18"/>
<circle cx="129.4" cy="234.6" r=".85" fill="#008000" stroke="#008000" stroke-width=".18"/>
<circle cx="129.4" cy="234.6" r=".55" fill="#fff" stroke="#000" stroke-width=".18"/>
<path d="M132.6 229.6h1.3" fill="none" stroke="#008000" stroke-width="1.3"/>
<circle cx="133.2" cy="229.6" r=".4" fill="#fff" stroke="#000" stroke-width=".18"/>
<path d="M119.9 229.6h1.3" fill="none" stroke="#008000" stroke-width="1.3"/>
<circle cx="120.5" cy="229.6" r=".4" fill="#fff" stroke="#000" stroke-width=".18"/>
<circle cx="120.9" cy="214.3" r=".93" fill="#008000" stroke="#008000" stroke-width=".18"/>
<circle cx="120.9" cy="214.3" r=".44" fill="#fff" stroke="#000" stroke-width=".18"/>
<circle cx="120.9" cy="221.9" r=".93" fill="#008000" stroke="#008000" stroke-width=".18"/>
<circle cx="120.9" cy="221.9" r=".44" fill="#fff" stroke="#000" stroke-width=".18"/>
<circle cx="114.2" cy="222.9" r="2.16" fill="#008000" stroke="#008000" stroke-width=".18"/>
<circle cx="114.2" cy="222.9" r="1.5" fill="#fff" stroke="#000" stroke-width=".18"/>
<circle cx="114.2" cy="216.9" r="2.16" fill="#008000" stroke="#008000" stroke-width=".18"/>
<circle cx="114.2" cy="216.9" r="1.5" fill="#fff" stroke="#000" stroke-width=".18"/>
<circle cx="109.5" cy="220" r="2.16" fill="#008000" stroke="#008000" stroke-width=".18"/>
<circle cx="109.5" cy="220" r="1.5" fill="#fff" stroke="#000" stroke-width=".18"/>
<circle cx="150.4" cy="224.5" r=".93" fill="#008000" stroke="#008000" stroke-width=".18"/>
<circle cx="150.4" cy="224.5" r=".51" fill="#fff" stroke="#000" stroke-width=".18"/>
<circle cx="150.4" cy="221.9" r=".93" fill="#008000" stroke="#008000" stroke-width=".18"/>
<circle cx="150.4" cy="221.9" r=".51" fill="#fff" stroke="#000" stroke-width=".18"/>
<circle cx="150.4" cy="219.4" r=".93" fill="#008000" stroke="#008000" stroke-width=".18"/>
<circle cx="150.4" cy="219.4" r=".51" fill="#fff" stroke="#000" stroke-width=".18"/>
<circle cx="150.4" cy="216.9" r=".93" fill="#008000" stroke="#008000" stroke-width=".18"/>
<circle cx="150.4" cy="216.9" r=".51" fill="#fff" stroke="#000" stroke-width=".18"/>
<circle cx="55.2" cy="224.5" r=".93" fill="#008000" stroke="#008000" stroke-width=".18"/>
<circle cx="55.2" cy="224.5" r=".51" fill="#fff" stroke="#000" stroke-width=".18"/>
<circle cx="55.2" cy="221.9" r=".93" fill="#008000" stroke="#008000" stroke-width=".18"/>
<circle cx="55.2" cy="221.9" r=".51" fill="#fff" stroke="#000" stroke-width=".18"/>
<circle cx="55.2" cy="219.4" r=".93" fill="#008000" stroke="#008000" stroke-width=".18"/>
<circle cx="55.2" cy="219.4" r=".51" fill="#fff" stroke="#000" stroke-width=".18"/>
<circle cx="55.2" cy="216.9" r=".93" fill="#008000" stroke="#008000" stroke-width=".18"/>
<circle cx="55.2" cy="216.9" r=".51" fill="#fff" stroke="#000" stroke-width=".18"/>
<circle cx="83.9" cy="213.1" r=".7" fill="#008000" stroke="#008000" stroke-width=".18"/>
<circle cx="83.9" cy="213.1" r=".4" fill="#fff" stroke="#000" stroke-width=".18"/>
<circle cx="80.4" cy="213.1" r=".7" fill="#008000" stroke="#008000" stroke-width=".18"/>
<circle cx="80.4" cy="213.1" r=".4" fill="#fff" stroke="#000" stroke-width=".18"/>
<circle cx="69.1" cy="213.1" r=".93" fill="#008000" stroke="#008000" stroke-width=".18"/>
<circle cx="69.1" cy="213.1" r=".44" fill="#fff" stroke="#000" stroke-width=".18"/>
<circle cx="76.7" cy="213.1" r=".93" fill="#008000" stroke="#008000" stroke-width=".18"/>
<circle cx="76.7" cy="213.1" r=".44" fill="#fff" stroke="#000" stroke-width=".18"/>
<circle cx="123.6" cy="243.8" r=".93" fill="#008000" stroke="#008000" stroke-width=".18"/>
<circle cx="123.6" cy="243.8" r=".51" fill="#fff" stroke="#000" stroke-width=".18"/>
<circle cx="130.1" cy="243.8" r=".93" fill="#008000" stroke="#008000" stroke-width=".18"/>
<circle cx="130.1" cy="243.8" r=".51" fill="#fff" stroke="#000" stroke-width=".18"/>
<circle cx="123.6" cy="248.3" r=".93" fill="#008000" stroke="#008000" stroke-width=".18"/>
<circle cx="123.6" cy="248.3" r=".51" fill="#fff" stroke="#000" stroke-width=".18"/>
<circle cx="130.1" cy="248.3" r=".93" fill="#008000" stroke="#008000" stroke-width=".18"/>
<circle cx="130.1" cy="248.3" r=".51" fill="#fff" stroke="#000" stroke-width=".18"/>
<path d="M138.3 235.2v1.5" fill="none" stroke="#008000" stroke-width="1.5"/>
<circle cx="138.3" cy="235.9" r=".51" fill="#fff" stroke="#000" stroke-width=".18"/>
<path d="M140.8 235.2v1.5" fill="none" stroke="#008000" stroke-width="1.5"/>
<circle cx="140.8" cy="235.9" r=".51" fill="#fff" stroke="#000" stroke-width=".18"/>
<path d="M143.4 235.2v1.5" fill="none" stroke="#008000" stroke-width="1.5"/>
<circle cx="143.4" cy="235.9" r=".51" fill="#fff" stroke="#000" stroke-width=".18"/>
<circle cx="136.3" cy="243.8" r=".93" fill="#008000" stroke="#008000" stroke-width=".18"/>
<circle cx="136.3" cy="243.8" r=".51" fill="#fff" stroke="#000" stroke-width=".18"/>
<circle cx="142.8" cy="243.8" r=".93" fill="#008000" stroke="#008000" stroke-width=".18"/>
<circle cx="142.8" cy="243.8" r=".51" fill="#fff" stroke="#000" stroke-width=".18"/>
<circle cx="136.3" cy="248.3" r=".93" fill="#008000" stroke="#008000" stroke-width=".18"/>
<circle cx="136.3" cy="248.3" r=".51" fill="#fff" stroke="#000" stroke-width=".18"/>
<circle cx="142.8" cy="248.3" r=".93" fill="#008000" stroke="#008000" stroke-width=".18"/>
<circle cx="142.8" cy="248.3" r=".51" fill="#fff" stroke="#000" stroke-width=".18"/>
<circle cx="110.9" cy="243.8" r=".93" fill="#008000" stroke="#008000" stroke-width=".18"/>
<circle cx="110.9" cy="243.8" r=".51" fill="#fff" stroke="#000" stroke-width=".18"/>
<circle cx="117.4" cy="243.8" r=".93" fill="#008000" stroke="#008000" stroke-width=".18"/>
<circle cx="117.4" cy="243.8" r=".51" fill="#fff" stroke="#000" stroke-width=".18"/>
<circle cx="110.9" cy="248.3" r=".93" fill="#008000" stroke="#008000" stroke-width=".18"/>
<circle cx="110.9" cy="248.3" r=".51" fill="#fff" stroke="#000" stroke-width=".18"/>
<circle cx="117.4" cy="248.3" r=".93" fill="#008000" stroke="#008000" stroke-width=".18"/>
<circle cx="117.4" cy="248.3" r=".51" fill="#fff" stroke="#000" stroke-width=".18"/>
<circle cx="66.6" cy="222.6" r="1.17" fill="#008000" stroke="#008000" stroke-width=".18"/>
<circle cx="66.6" cy="222.6" r=".51" fill="#fff" stroke="#000" stroke-width=".18"/>
<circle cx="74.2" cy="222.6" r="1.17" fill="#008000" stroke="#008000" stroke-width=".18"/>
<circle cx="74.2" cy="222.6" r=".51" fill="#fff" stroke="#000" stroke-width=".18"/>
<circle cx="79.6" cy="227" r=".93" fill="#008000" stroke="#008000" stroke-width=".18"/>
<circle cx="79.6" cy="227" r=".44" fill="#fff" stroke="#000" stroke-width=".18"/>
<circle cx="79.6" cy="234.6" r=".93" fill="#008000" stroke="#008000" stroke-width=".18"/>
<circle cx="79.6" cy="234.6" r=".44" fill="#fff" stroke="#000" stroke-width=".18"/>
<path d="M100 247.7h1.7v1.7h-1.7z" fill="#008000" stroke="#008000" stroke-width=".18"/>
<circle cx="100.9" cy="248.6" r=".55" fill="#fff" stroke="#000" stroke-width=".18"/>
<circle cx="100.9" cy="246.1" r=".85" fill="#008000" stroke="#008000" stroke-width=".18"/>
<circle cx="100.9" cy="246.1" r=".55" fill="#fff" stroke="#000" stroke-width=".18"/>
<circle cx="100.9" cy="243.5" r=".85" fill="#008000" stroke="#008000" stroke-width=".18"/>
<circle cx="100.9" cy="243.5" r=".55" fill="#fff" stroke="#000" stroke-width=".18"/>
<circle cx="100.9" cy="241" r=".85" fill="#008000" stroke="#008000" stroke-width=".18"/>
<circle cx="100.9" cy="241" r=".55" fill="#fff" stroke="#000" stroke-width=".18"/>
<circle cx="100.9" cy="238.5" r=".85" fill="#008000" stroke="#008000" stroke-width=".18"/>
<circle cx="100.9" cy="238.5" r=".55" fill="#fff" stroke="#000" stroke-width=".18"/>
<circle cx="100.9" cy="235.9" r=".85" fill="#008000" stroke="#008000" stroke-width=".18"/>
<circle cx="100.9" cy="235.9" r=".55" fill="#fff" stroke="#000" stroke-width=".18"/>
<circle cx="100.9" cy="233.4" r=".85" fill="#008000" stroke="#008000" stroke-width=".18"/>
<circle cx="100.9" cy="233.4" r=".55" fill="#fff" stroke="#000" stroke-width=".18"/>
<circle cx="100.9" cy="230.8" r=".85" fill="#008000" stroke="#008000" stroke-width=".18"/>
<circle cx="100.9" cy="230.8" r=".55" fill="#fff" stroke="#000" stroke-width=".18"/>
<circle cx="100.9" cy="228.3" r=".85" fill="#008000" stroke="#008000" stroke-width=".18"/>
<circle cx="100.9" cy="228.3" r=".55" fill="#fff" stroke="#000" stroke-width=".18"/>
<circle cx="100.9" cy="225.8" r=".85" fill="#008000" stroke="#008000" stroke-width=".18"/>
<circle cx="100.9" cy="225.8" r=".55" fill="#fff" stroke="#000" stroke-width=".18"/>
<circle cx="100.9" cy="223.2" r=".85" fill="#008000" stroke="#008000" stroke-width=".18"/>
<circle cx="100.9" cy="223.2" r=".55" fill="#fff" stroke="#000" stroke-width=".18"/>
<circle cx="100.9" cy="220.7" r=".85" fill="#008000" stroke="#008000" stroke-width=".18"/>
<circle cx="100.9" cy="220.7" r=".55" fill="#fff" stroke="#000" stroke-width=".18"/>
<circle cx="100.9" cy="218.1" r=".85" fill="#008000" stroke="#008000" stroke-width=".18"/>
<circle cx="100.9" cy="218.1" r=".55" fill="#fff" stroke="#000" stroke-width=".18"/>
<circle cx="100.9" cy="215.6" r=".85" fill="#008000" stroke="#008000" stroke-width=".18"/>
<circle cx="100.9" cy="215.6" r=".55" fill="#fff" stroke="#000" stroke-width=".18"/>
<circle cx="93.2" cy="215.6" r=".85" fill="#008000" stroke="#008000" stroke-width=".18"/>
<circle cx="93.2" cy="215.6" r=".55" fill="#fff" stroke="#000" stroke-width=".18"/>
<circle cx="93.2" cy="218.1" r=".85" fill="#008000" stroke="#008000" stroke-width=".18"/>
<circle cx="93.2" cy="218.1" r=".55" fill="#fff" stroke="#000" stroke-width=".18"/>
<circle cx="93.2" cy="220.7" r=".85" fill="#008000" stroke="#008000" stroke-width=".18"/>
<circle cx="93.2" cy="220.7" r=".55" fill="#fff" stroke="#000" stroke-width=".18"/>
<circle cx="93.2" cy="223.2" r=".85" fill="#008000" stroke="#008000" stroke-width=".18"/>
<circle cx="93.2" cy="223.2" r=".55" fill="#fff" stroke="#000" stroke-width=".18"/>
<circle cx="93.2" cy="225.8" r=".85" fill="#008000" stroke="#008000" stroke-width=".18"/>
<circle cx="93.2" cy="225.8" r=".55" fill="#fff" stroke="#000" stroke-width=".18"/>
<circle cx="93.2" cy="228.3" r=".85" fill="#008000" stroke="#008000" stroke-width=".18"/>
<circle cx="93.2" cy="228.3" r=".55" fill="#fff" stroke="#000" stroke-width=".18"/>
<circle cx="93.2" cy="230.8" r=".85" fill="#008000" stroke="#008000" stroke-width=".18"/>
<circle cx="93.2" cy="230.8" r=".55" fill="#fff" stroke="#000" stroke-width=".18"/>
<circle cx="93.2" cy="233.4" r=".85" fill="#008000" stroke="#008000" stroke-width=".18"/>
<circle cx="93.2" cy="233.4" r=".55" fill="#fff" stroke="#000" stroke-width=".18"/>
<circle cx="93.2" cy="235.9" r=".85" fill="#008000" stroke="#008000" stroke-width=".18"/>
<circle cx="93.2" cy="235.9" r=".55" fill="#fff" stroke="#000" stroke-width=".18"/>
<circle cx="93.2" cy="238.5" r=".85" fill="#008000" stroke="#008000" stroke-width=".18"/>
<circle cx="93.2" cy="238.5" r=".55" fill="#fff" stroke="#000" stroke-width=".18"/>
<circle cx="93.2" cy="241" r=".85" fill="#008000" stroke="#008000" stroke-width=".18"/>
<circle cx="93.2" cy="241" r=".55" fill="#fff" stroke="#000" stroke-width=".18"/>
<circle cx="93.2" cy="243.5" r=".85" fill="#008000" stroke="#008000" stroke-width=".18"/>
<circle cx="93.2" cy="243.5" r=".55" fill="#fff" stroke="#000" stroke-width=".18"/>
<circle cx="93.2" cy="246.1" r=".85" fill="#008000" stroke="#008000" stroke-width=".18"/>
<circle cx="93.2" cy="246.1" r=".55" fill="#fff" stroke="#000" stroke-width=".18"/>
<circle cx="93.2" cy="248.6" r=".85" fill="#008000" stroke="#008000" stroke-width=".18"/>
<circle cx="93.2" cy="248.6" r=".55" fill="#fff" stroke="#000" stroke-width=".18"/>
<circle cx="61.5" cy="243.8" r="1.4" fill="#008000" stroke="#008000" stroke-width=".18"/>
<circle cx="61.5" cy="243.8" r=".93" fill="#fff" stroke="#000" stroke-width=".18"/>
<circle cx="61.5" cy="230.6" r="1.4" fill="#008000" stroke="#008000" stroke-width=".18"/>
<circle cx="61.5" cy="230.6" r=".93" fill="#fff" stroke="#000" stroke-width=".18"/>
<circle cx="104.7" cy="211.8" r=".93" fill="#008000" stroke="#008000" stroke-width=".18"/>
<circle cx="104.7" cy="211.8" r=".51" fill="#fff" stroke="#000" stroke-width=".18"/>
<circle cx="102.1" cy="211.8" r=".93" fill="#008000" stroke="#008000" stroke-width=".18"/>
<circle cx="102.1" cy="211.8" r=".51" fill="#fff" stroke="#000" stroke-width=".18"/>
<circle cx="99.6" cy="211.8" r=".93" fill="#008000" stroke="#008000" stroke-width=".18"/>
<circle cx="99.6" cy="211.8" r=".51" fill="#fff" stroke="#000" stroke-width=".18"/>
<circle cx="97" cy="211.8" r=".93" fill="#008000" stroke="#008000" stroke-width=".18"/>
<circle cx="97" cy="211.8" r=".51" fill="#fff" stroke="#000" stroke-width=".18"/>
<circle cx="94.5" cy="211.8" r=".93" fill="#008000" stroke="#008000" stroke-width=".18"/>
<circle cx="94.5" cy="211.8" r=".51" fill="#fff" stroke="#000" stroke-width=".18"/>
<circle cx="87.5" cy="236.2" r=".93" fill="#008000" stroke="#008000" stroke-width=".18"/>
<circle cx="87.5" cy="236.2" r=".44" fill="#fff" stroke="#000" stroke-width=".18"/>
<circle cx="87.5" cy="228.6" r=".93" fill="#008000" stroke="#008000" stroke-width=".18"/>
<circle cx="87.5" cy="228.6" r=".44" fill="#fff" stroke="#000" stroke-width=".18"/>
<circle cx="87.5" cy="249.2" r=".93" fill="#008000" stroke="#008000" stroke-width=".18"/>
<circle cx="87.5" cy="249.2" r=".44" fill="#fff" stroke="#000" stroke-width=".18"/>
<circle cx="87.5" cy="241.6" r=".93" fill="#008000" stroke="#008000" stroke-width=".18"/>
<circle cx="87.5" cy="241.6" r=".44" fill="#fff" stroke="#000" stroke-width=".18"/>
<circle cx="90.4" cy="241.6" r=".93" fill="#008000" stroke="#008000" stroke-width=".18"/>
<circle cx="90.4" cy="241.6" r=".44" fill="#fff" stroke="#000" stroke-width=".18"/>
<circle cx="90.4" cy="249.2" r=".93" fill="#008000" stroke="#008000" stroke-width=".18"/>
<circle cx="90.4" cy="249.2" r=".44" fill="#fff" stroke="#000" stroke-width=".18"/>
<circle cx="85" cy="245.4" r=".83" fill="#008000" stroke="#008000" stroke-width=".18"/>
<circle cx="85" cy="245.4" r=".44" fill="#fff" stroke="#000" stroke-width=".18"/>
<circle cx="85" cy="248" r=".83" fill="#008000" stroke="#008000" stroke-width=".18"/>
<circle cx="85" cy="248" r=".44" fill="#fff" stroke="#000" stroke-width=".18"/>
<circle cx="82.1" cy="223.8" r=".83" fill="#008000" stroke="#008000" stroke-width=".18"/>
<circle cx="82.1" cy="223.8" r=".44" fill="#fff" stroke="#000" stroke-width=".18"/>
<circle cx="79.6" cy="223.8" r=".83" fill="#008000" stroke="#008000" stroke-width=".18"/>
<circle cx="79.6" cy="223.8" r=".44" fill="#fff" stroke="#000" stroke-width=".18"/>
<circle cx="82.1" cy="221" r=".83" fill="#008000" stroke="#008000" stroke-width=".18"/>
<circle cx="82.1" cy="221" r=".44" fill="#fff" stroke="#000" stroke-width=".18"/>
<circle cx="79.6" cy="221" r=".83" fill="#008000" stroke="#008000" stroke-width=".18"/>
<circle cx="79.6" cy="221" r=".44" fill="#fff" stroke="#000" stroke-width=".18"/>
<circle cx="104" cy="230.8" r=".83" fill="#008000" stroke="#008000" stroke-width=".18"/>
<circle cx="104" cy="230.8" r=".44" fill="#fff" stroke="#000" stroke-width=".18"/>
<circle cx="104" cy="233.4" r=".83" fill="#008000" stroke="#008000" stroke-width=".18"/>
<circle cx="104" cy="233.4" r=".44" fill="#fff" stroke="#000" stroke-width=".18"/>
<g fill="none" stroke="#f90" stroke-width=".18">
<path d="M54.1 208.8a2.4 2.4 0 0 1 1.4-.6h94.5a2.26 2.26 0 0 1 2.3 2.3v40.9a2.29 2.29 0 0 1-2.3 2.3h-94.5a2.29 2.29 0 0 1-2.3-2.3v-40.8a2.31 2.31 0 0 1 .9-1.8z"/>
<circle cx="56.1" cy="250.8" r="1.5"/>
</g>
<circle cx="56.1" cy="250.8" r="1.5" fill="#fff" stroke="#000" stroke-width=".18"/>
<circle cx="56.1" cy="211.1" r="1.5" fill="none" stroke="#f90" stroke-width=".18"/>
<circle cx="56.1" cy="211.1" r="1.5" fill="#fff" stroke="#000" stroke-width=".18"/>
<circle cx="149.4" cy="211.1" r="1.5" fill="none" stroke="#f90" stroke-width=".18"/>
<circle cx="149.4" cy="211.1" r="1.5" fill="#fff" stroke="#000" stroke-width=".18"/>
<circle cx="149.4" cy="250.8" r="1.5" fill="none" stroke="#f90" stroke-width=".18"/>
<circle cx="149.4" cy="250.8" r="1.5" fill="#fff" stroke="#000" stroke-width=".18"/>
<g fill="none" stroke="#505050" stroke-width=".18">
<path d="M57.1 210.1l-2 2M150.4 210.1l-2 2M57.1 249.8l-2 2M150.4 249.8l-2 2"/>
<circle cx="56.1" cy="211.1" r=".99"/>
<circle cx="149.4" cy="211.1" r=".99"/>
<circle cx="56.1" cy="250.8" r=".99"/>
<circle cx="149.4" cy="250.8" r=".99"/>
</g>
<use href="#words"/>
</svg>
